VERSION 5.8 ;
BUSBITCHARS "[]" ;
DIVIDERCHAR "/" ;
UNITS
    DATABASE MICRONS 1000 ;
END UNITS

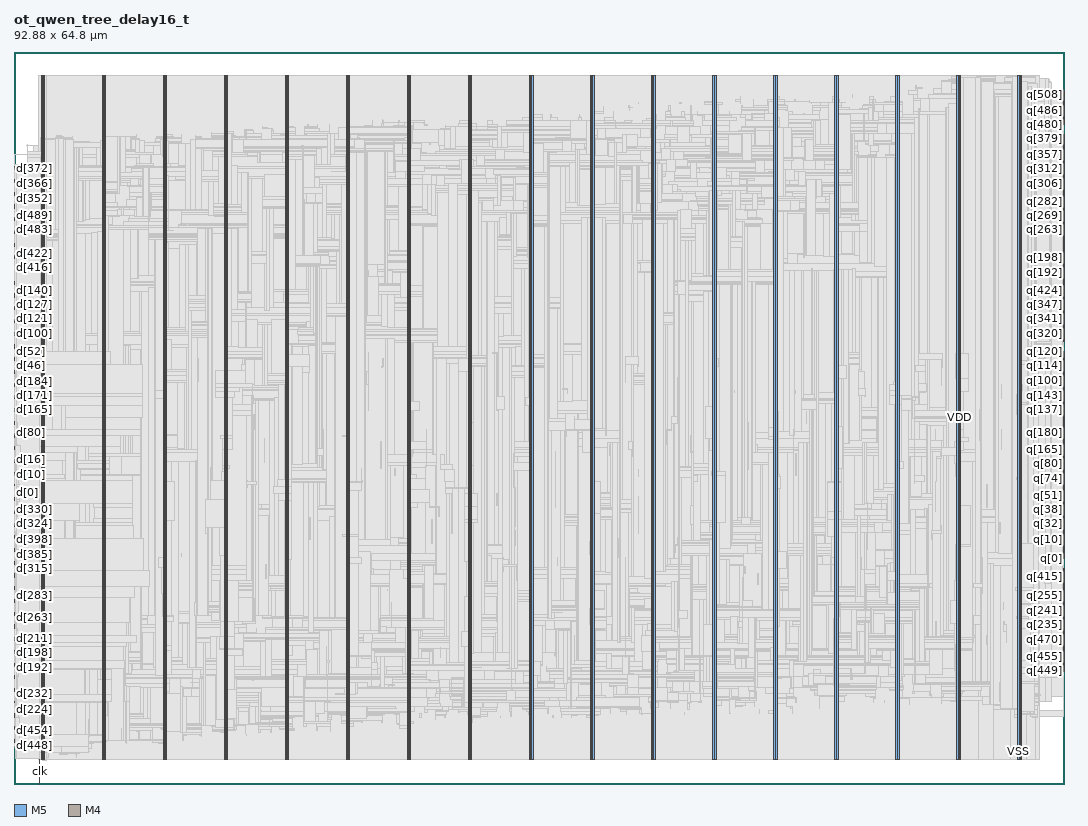
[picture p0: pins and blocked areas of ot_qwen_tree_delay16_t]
MACRO ot_qwen_tree_delay16_t
  FOREIGN ot_qwen_tree_delay16_t 0 0 ;
  CLASS BLOCK ;
  SIZE 92.88 BY 64.8 ;
  PIN clk
    DIRECTION INPUT ;
    USE SIGNAL ;
    PORT
      LAYER M5 ;
        RECT  2.256 0 2.28 0.084 ;
    END
    PORT
      LAYER M5 ;
        RECT  2.256 0.016 2.28 2.137 ;
    END
  END clk
  PIN d[0]
    DIRECTION INPUT ;
    USE SIGNAL ;
    PORT
      LAYER M4 ;
        RECT  0 26.448 0.084 26.472 ;
    END
  END d[0]
  PIN d[100]
    DIRECTION INPUT ;
    USE SIGNAL ;
    PORT
      LAYER M4 ;
        RECT  0 39.12 0.084 39.144 ;
    END
  END d[100]
  PIN d[101]
    DIRECTION INPUT ;
    USE SIGNAL ;
    PORT
      LAYER M4 ;
        RECT  0 39.216 0.084 39.24 ;
    END
  END d[101]
  PIN d[102]
    DIRECTION INPUT ;
    USE SIGNAL ;
    PORT
      LAYER M4 ;
        RECT  0 39.312 0.084 39.336 ;
    END
  END d[102]
  PIN d[103]
    DIRECTION INPUT ;
    USE SIGNAL ;
    PORT
      LAYER M4 ;
        RECT  0 39.408 0.084 39.432 ;
    END
  END d[103]
  PIN d[104]
    DIRECTION INPUT ;
    USE SIGNAL ;
    PORT
      LAYER M4 ;
        RECT  0 39.504 0.084 39.528 ;
    END
  END d[104]
  PIN d[105]
    DIRECTION INPUT ;
    USE SIGNAL ;
    PORT
      LAYER M4 ;
        RECT  0 39.6 0.084 39.624 ;
    END
  END d[105]
  PIN d[106]
    DIRECTION INPUT ;
    USE SIGNAL ;
    PORT
      LAYER M4 ;
        RECT  0 39.696 0.084 39.72 ;
    END
  END d[106]
  PIN d[107]
    DIRECTION INPUT ;
    USE SIGNAL ;
    PORT
      LAYER M4 ;
        RECT  0 39.792 0.084 39.816 ;
    END
  END d[107]
  PIN d[108]
    DIRECTION INPUT ;
    USE SIGNAL ;
    PORT
      LAYER M4 ;
        RECT  0 39.888 0.084 39.912 ;
    END
  END d[108]
  PIN d[109]
    DIRECTION INPUT ;
    USE SIGNAL ;
    PORT
      LAYER M4 ;
        RECT  0 39.984 0.084 40.008 ;
    END
  END d[109]
  PIN d[10]
    DIRECTION INPUT ;
    USE SIGNAL ;
    PORT
      LAYER M4 ;
        RECT  0 27.408 0.084 27.432 ;
    END
  END d[10]
  PIN d[110]
    DIRECTION INPUT ;
    USE SIGNAL ;
    PORT
      LAYER M4 ;
        RECT  0 40.08 0.084 40.104 ;
    END
  END d[110]
  PIN d[111]
    DIRECTION INPUT ;
    USE SIGNAL ;
    PORT
      LAYER M4 ;
        RECT  0 40.176 0.084 40.2 ;
    END
  END d[111]
  PIN d[112]
    DIRECTION INPUT ;
    USE SIGNAL ;
    PORT
      LAYER M4 ;
        RECT  0 40.272 0.084 40.296 ;
    END
  END d[112]
  PIN d[113]
    DIRECTION INPUT ;
    USE SIGNAL ;
    PORT
      LAYER M4 ;
        RECT  0 40.368 0.084 40.392 ;
    END
  END d[113]
  PIN d[114]
    DIRECTION INPUT ;
    USE SIGNAL ;
    PORT
      LAYER M4 ;
        RECT  0 40.464 0.084 40.488 ;
    END
  END d[114]
  PIN d[115]
    DIRECTION INPUT ;
    USE SIGNAL ;
    PORT
      LAYER M4 ;
        RECT  0 40.56 0.084 40.584 ;
    END
  END d[115]
  PIN d[116]
    DIRECTION INPUT ;
    USE SIGNAL ;
    PORT
      LAYER M4 ;
        RECT  0 40.656 0.084 40.68 ;
    END
  END d[116]
  PIN d[117]
    DIRECTION INPUT ;
    USE SIGNAL ;
    PORT
      LAYER M4 ;
        RECT  0 40.752 0.084 40.776 ;
    END
  END d[117]
  PIN d[118]
    DIRECTION INPUT ;
    USE SIGNAL ;
    PORT
      LAYER M4 ;
        RECT  0 40.848 0.084 40.872 ;
    END
  END d[118]
  PIN d[119]
    DIRECTION INPUT ;
    USE SIGNAL ;
    PORT
      LAYER M4 ;
        RECT  0 40.944 0.084 40.968 ;
    END
  END d[119]
  PIN d[11]
    DIRECTION INPUT ;
    USE SIGNAL ;
    PORT
      LAYER M4 ;
        RECT  0 27.504 0.084 27.528 ;
    END
  END d[11]
  PIN d[120]
    DIRECTION INPUT ;
    USE SIGNAL ;
    PORT
      LAYER M4 ;
        RECT  0 41.04 0.084 41.064 ;
    END
  END d[120]
  PIN d[121]
    DIRECTION INPUT ;
    USE SIGNAL ;
    PORT
      LAYER M4 ;
        RECT  0 41.136 0.084 41.16 ;
    END
  END d[121]
  PIN d[122]
    DIRECTION INPUT ;
    USE SIGNAL ;
    PORT
      LAYER M4 ;
        RECT  0 41.232 0.084 41.256 ;
    END
  END d[122]
  PIN d[123]
    DIRECTION INPUT ;
    USE SIGNAL ;
    PORT
      LAYER M4 ;
        RECT  0 41.328 0.084 41.352 ;
    END
  END d[123]
  PIN d[124]
    DIRECTION INPUT ;
    USE SIGNAL ;
    PORT
      LAYER M4 ;
        RECT  0 41.424 0.084 41.448 ;
    END
  END d[124]
  PIN d[125]
    DIRECTION INPUT ;
    USE SIGNAL ;
    PORT
      LAYER M4 ;
        RECT  0 41.52 0.084 41.544 ;
    END
  END d[125]
  PIN d[126]
    DIRECTION INPUT ;
    USE SIGNAL ;
    PORT
      LAYER M4 ;
        RECT  0 41.616 0.084 41.64 ;
    END
  END d[126]
  PIN d[127]
    DIRECTION INPUT ;
    USE SIGNAL ;
    PORT
      LAYER M4 ;
        RECT  0 41.712 0.084 41.736 ;
    END
  END d[127]
  PIN d[128]
    DIRECTION INPUT ;
    USE SIGNAL ;
    PORT
      LAYER M4 ;
        RECT  0 41.808 0.084 41.832 ;
    END
  END d[128]
  PIN d[129]
    DIRECTION INPUT ;
    USE SIGNAL ;
    PORT
      LAYER M4 ;
        RECT  0 41.904 0.084 41.928 ;
    END
  END d[129]
  PIN d[12]
    DIRECTION INPUT ;
    USE SIGNAL ;
    PORT
      LAYER M4 ;
        RECT  0 27.6 0.084 27.624 ;
    END
  END d[12]
  PIN d[130]
    DIRECTION INPUT ;
    USE SIGNAL ;
    PORT
      LAYER M4 ;
        RECT  0 42 0.084 42.024 ;
    END
  END d[130]
  PIN d[131]
    DIRECTION INPUT ;
    USE SIGNAL ;
    PORT
      LAYER M4 ;
        RECT  0 42.096 0.084 42.12 ;
    END
  END d[131]
  PIN d[132]
    DIRECTION INPUT ;
    USE SIGNAL ;
    PORT
      LAYER M4 ;
        RECT  0 42.192 0.084 42.216 ;
    END
  END d[132]
  PIN d[133]
    DIRECTION INPUT ;
    USE SIGNAL ;
    PORT
      LAYER M4 ;
        RECT  0 42.288 0.084 42.312 ;
    END
  END d[133]
  PIN d[134]
    DIRECTION INPUT ;
    USE SIGNAL ;
    PORT
      LAYER M4 ;
        RECT  0 42.384 0.084 42.408 ;
    END
  END d[134]
  PIN d[135]
    DIRECTION INPUT ;
    USE SIGNAL ;
    PORT
      LAYER M4 ;
        RECT  0 42.48 0.084 42.504 ;
    END
  END d[135]
  PIN d[136]
    DIRECTION INPUT ;
    USE SIGNAL ;
    PORT
      LAYER M4 ;
        RECT  0 42.576 0.084 42.6 ;
    END
  END d[136]
  PIN d[137]
    DIRECTION INPUT ;
    USE SIGNAL ;
    PORT
      LAYER M4 ;
        RECT  0 42.672 0.084 42.696 ;
    END
  END d[137]
  PIN d[138]
    DIRECTION INPUT ;
    USE SIGNAL ;
    PORT
      LAYER M4 ;
        RECT  0 42.768 0.084 42.792 ;
    END
  END d[138]
  PIN d[139]
    DIRECTION INPUT ;
    USE SIGNAL ;
    PORT
      LAYER M4 ;
        RECT  0 42.864 0.084 42.888 ;
    END
  END d[139]
  PIN d[13]
    DIRECTION INPUT ;
    USE SIGNAL ;
    PORT
      LAYER M4 ;
        RECT  0 27.696 0.084 27.72 ;
    END
  END d[13]
  PIN d[140]
    DIRECTION INPUT ;
    USE SIGNAL ;
    PORT
      LAYER M4 ;
        RECT  0 42.96 0.084 42.984 ;
    END
  END d[140]
  PIN d[141]
    DIRECTION INPUT ;
    USE SIGNAL ;
    PORT
      LAYER M4 ;
        RECT  0 43.056 0.084 43.08 ;
    END
  END d[141]
  PIN d[142]
    DIRECTION INPUT ;
    USE SIGNAL ;
    PORT
      LAYER M4 ;
        RECT  0 43.152 0.084 43.176 ;
    END
  END d[142]
  PIN d[143]
    DIRECTION INPUT ;
    USE SIGNAL ;
    PORT
      LAYER M4 ;
        RECT  0 43.248 0.084 43.272 ;
    END
  END d[143]
  PIN d[144]
    DIRECTION INPUT ;
    USE SIGNAL ;
    PORT
      LAYER M4 ;
        RECT  0 43.344 0.084 43.368 ;
    END
  END d[144]
  PIN d[145]
    DIRECTION INPUT ;
    USE SIGNAL ;
    PORT
      LAYER M4 ;
        RECT  0 43.44 0.084 43.464 ;
    END
  END d[145]
  PIN d[146]
    DIRECTION INPUT ;
    USE SIGNAL ;
    PORT
      LAYER M4 ;
        RECT  0 43.536 0.084 43.56 ;
    END
  END d[146]
  PIN d[147]
    DIRECTION INPUT ;
    USE SIGNAL ;
    PORT
      LAYER M4 ;
        RECT  0 43.632 0.084 43.656 ;
    END
  END d[147]
  PIN d[148]
    DIRECTION INPUT ;
    USE SIGNAL ;
    PORT
      LAYER M4 ;
        RECT  0 43.728 0.084 43.752 ;
    END
  END d[148]
  PIN d[149]
    DIRECTION INPUT ;
    USE SIGNAL ;
    PORT
      LAYER M4 ;
        RECT  0 43.824 0.084 43.848 ;
    END
  END d[149]
  PIN d[14]
    DIRECTION INPUT ;
    USE SIGNAL ;
    PORT
      LAYER M4 ;
        RECT  0 27.792 0.084 27.816 ;
    END
  END d[14]
  PIN d[150]
    DIRECTION INPUT ;
    USE SIGNAL ;
    PORT
      LAYER M4 ;
        RECT  0 43.92 0.084 43.944 ;
    END
  END d[150]
  PIN d[151]
    DIRECTION INPUT ;
    USE SIGNAL ;
    PORT
      LAYER M4 ;
        RECT  0 44.016 0.084 44.04 ;
    END
  END d[151]
  PIN d[152]
    DIRECTION INPUT ;
    USE SIGNAL ;
    PORT
      LAYER M4 ;
        RECT  0 44.112 0.084 44.136 ;
    END
  END d[152]
  PIN d[153]
    DIRECTION INPUT ;
    USE SIGNAL ;
    PORT
      LAYER M4 ;
        RECT  0 44.208 0.084 44.232 ;
    END
  END d[153]
  PIN d[154]
    DIRECTION INPUT ;
    USE SIGNAL ;
    PORT
      LAYER M4 ;
        RECT  0 44.304 0.084 44.328 ;
    END
  END d[154]
  PIN d[155]
    DIRECTION INPUT ;
    USE SIGNAL ;
    PORT
      LAYER M4 ;
        RECT  0 44.4 0.084 44.424 ;
    END
  END d[155]
  PIN d[156]
    DIRECTION INPUT ;
    USE SIGNAL ;
    PORT
      LAYER M4 ;
        RECT  0 44.496 0.084 44.52 ;
    END
  END d[156]
  PIN d[157]
    DIRECTION INPUT ;
    USE SIGNAL ;
    PORT
      LAYER M4 ;
        RECT  0 44.592 0.084 44.616 ;
    END
  END d[157]
  PIN d[158]
    DIRECTION INPUT ;
    USE SIGNAL ;
    PORT
      LAYER M4 ;
        RECT  0 44.688 0.084 44.712 ;
    END
  END d[158]
  PIN d[159]
    DIRECTION INPUT ;
    USE SIGNAL ;
    PORT
      LAYER M4 ;
        RECT  0 44.784 0.084 44.808 ;
    END
  END d[159]
  PIN d[15]
    DIRECTION INPUT ;
    USE SIGNAL ;
    PORT
      LAYER M4 ;
        RECT  0 27.888 0.084 27.912 ;
    END
  END d[15]
  PIN d[160]
    DIRECTION INPUT ;
    USE SIGNAL ;
    PORT
      LAYER M4 ;
        RECT  0 32.592 0.084 32.616 ;
    END
  END d[160]
  PIN d[161]
    DIRECTION INPUT ;
    USE SIGNAL ;
    PORT
      LAYER M4 ;
        RECT  0 32.688 0.084 32.712 ;
    END
  END d[161]
  PIN d[162]
    DIRECTION INPUT ;
    USE SIGNAL ;
    PORT
      LAYER M4 ;
        RECT  0 32.784 0.084 32.808 ;
    END
  END d[162]
  PIN d[163]
    DIRECTION INPUT ;
    USE SIGNAL ;
    PORT
      LAYER M4 ;
        RECT  0 32.88 0.084 32.904 ;
    END
  END d[163]
  PIN d[164]
    DIRECTION INPUT ;
    USE SIGNAL ;
    PORT
      LAYER M4 ;
        RECT  0 32.976 0.084 33 ;
    END
  END d[164]
  PIN d[165]
    DIRECTION INPUT ;
    USE SIGNAL ;
    PORT
      LAYER M4 ;
        RECT  0 33.072 0.084 33.096 ;
    END
  END d[165]
  PIN d[166]
    DIRECTION INPUT ;
    USE SIGNAL ;
    PORT
      LAYER M4 ;
        RECT  0 33.168 0.084 33.192 ;
    END
  END d[166]
  PIN d[167]
    DIRECTION INPUT ;
    USE SIGNAL ;
    PORT
      LAYER M4 ;
        RECT  0 33.264 0.084 33.288 ;
    END
  END d[167]
  PIN d[168]
    DIRECTION INPUT ;
    USE SIGNAL ;
    PORT
      LAYER M4 ;
        RECT  0 33.36 0.084 33.384 ;
    END
  END d[168]
  PIN d[169]
    DIRECTION INPUT ;
    USE SIGNAL ;
    PORT
      LAYER M4 ;
        RECT  0 33.456 0.084 33.48 ;
    END
  END d[169]
  PIN d[16]
    DIRECTION INPUT ;
    USE SIGNAL ;
    PORT
      LAYER M4 ;
        RECT  0 27.984 0.084 28.008 ;
    END
  END d[16]
  PIN d[170]
    DIRECTION INPUT ;
    USE SIGNAL ;
    PORT
      LAYER M4 ;
        RECT  0 33.552 0.084 33.576 ;
    END
  END d[170]
  PIN d[171]
    DIRECTION INPUT ;
    USE SIGNAL ;
    PORT
      LAYER M4 ;
        RECT  0 33.648 0.084 33.672 ;
    END
  END d[171]
  PIN d[172]
    DIRECTION INPUT ;
    USE SIGNAL ;
    PORT
      LAYER M4 ;
        RECT  0 33.744 0.084 33.768 ;
    END
  END d[172]
  PIN d[173]
    DIRECTION INPUT ;
    USE SIGNAL ;
    PORT
      LAYER M4 ;
        RECT  0 33.84 0.084 33.864 ;
    END
  END d[173]
  PIN d[174]
    DIRECTION INPUT ;
    USE SIGNAL ;
    PORT
      LAYER M4 ;
        RECT  0 33.936 0.084 33.96 ;
    END
  END d[174]
  PIN d[175]
    DIRECTION INPUT ;
    USE SIGNAL ;
    PORT
      LAYER M4 ;
        RECT  0 34.032 0.084 34.056 ;
    END
  END d[175]
  PIN d[176]
    DIRECTION INPUT ;
    USE SIGNAL ;
    PORT
      LAYER M4 ;
        RECT  0 34.128 0.084 34.152 ;
    END
  END d[176]
  PIN d[177]
    DIRECTION INPUT ;
    USE SIGNAL ;
    PORT
      LAYER M4 ;
        RECT  0 34.224 0.084 34.248 ;
    END
  END d[177]
  PIN d[178]
    DIRECTION INPUT ;
    USE SIGNAL ;
    PORT
      LAYER M4 ;
        RECT  0 34.32 0.084 34.344 ;
    END
  END d[178]
  PIN d[179]
    DIRECTION INPUT ;
    USE SIGNAL ;
    PORT
      LAYER M4 ;
        RECT  0 34.416 0.084 34.44 ;
    END
  END d[179]
  PIN d[17]
    DIRECTION INPUT ;
    USE SIGNAL ;
    PORT
      LAYER M4 ;
        RECT  0 28.08 0.084 28.104 ;
    END
  END d[17]
  PIN d[180]
    DIRECTION INPUT ;
    USE SIGNAL ;
    PORT
      LAYER M4 ;
        RECT  0 34.512 0.084 34.536 ;
    END
  END d[180]
  PIN d[181]
    DIRECTION INPUT ;
    USE SIGNAL ;
    PORT
      LAYER M4 ;
        RECT  0 34.608 0.084 34.632 ;
    END
  END d[181]
  PIN d[182]
    DIRECTION INPUT ;
    USE SIGNAL ;
    PORT
      LAYER M4 ;
        RECT  0 34.704 0.084 34.728 ;
    END
  END d[182]
  PIN d[183]
    DIRECTION INPUT ;
    USE SIGNAL ;
    PORT
      LAYER M4 ;
        RECT  0 34.8 0.084 34.824 ;
    END
  END d[183]
  PIN d[184]
    DIRECTION INPUT ;
    USE SIGNAL ;
    PORT
      LAYER M4 ;
        RECT  0 34.896 0.084 34.92 ;
    END
  END d[184]
  PIN d[185]
    DIRECTION INPUT ;
    USE SIGNAL ;
    PORT
      LAYER M4 ;
        RECT  0 34.992 0.084 35.016 ;
    END
  END d[185]
  PIN d[186]
    DIRECTION INPUT ;
    USE SIGNAL ;
    PORT
      LAYER M4 ;
        RECT  0 35.088 0.084 35.112 ;
    END
  END d[186]
  PIN d[187]
    DIRECTION INPUT ;
    USE SIGNAL ;
    PORT
      LAYER M4 ;
        RECT  0 35.184 0.084 35.208 ;
    END
  END d[187]
  PIN d[188]
    DIRECTION INPUT ;
    USE SIGNAL ;
    PORT
      LAYER M4 ;
        RECT  0 35.28 0.084 35.304 ;
    END
  END d[188]
  PIN d[189]
    DIRECTION INPUT ;
    USE SIGNAL ;
    PORT
      LAYER M4 ;
        RECT  0 35.376 0.084 35.4 ;
    END
  END d[189]
  PIN d[18]
    DIRECTION INPUT ;
    USE SIGNAL ;
    PORT
      LAYER M4 ;
        RECT  0 28.176 0.084 28.2 ;
    END
  END d[18]
  PIN d[190]
    DIRECTION INPUT ;
    USE SIGNAL ;
    PORT
      LAYER M4 ;
        RECT  0 35.472 0.084 35.496 ;
    END
  END d[190]
  PIN d[191]
    DIRECTION INPUT ;
    USE SIGNAL ;
    PORT
      LAYER M4 ;
        RECT  0 35.568 0.084 35.592 ;
    END
  END d[191]
  PIN d[192]
    DIRECTION INPUT ;
    USE SIGNAL ;
    PORT
      LAYER M4 ;
        RECT  0 10.32 0.084 10.344 ;
    END
  END d[192]
  PIN d[193]
    DIRECTION INPUT ;
    USE SIGNAL ;
    PORT
      LAYER M4 ;
        RECT  0 10.416 0.084 10.44 ;
    END
  END d[193]
  PIN d[194]
    DIRECTION INPUT ;
    USE SIGNAL ;
    PORT
      LAYER M4 ;
        RECT  0 10.512 0.084 10.536 ;
    END
  END d[194]
  PIN d[195]
    DIRECTION INPUT ;
    USE SIGNAL ;
    PORT
      LAYER M4 ;
        RECT  0 10.608 0.084 10.632 ;
    END
  END d[195]
  PIN d[196]
    DIRECTION INPUT ;
    USE SIGNAL ;
    PORT
      LAYER M4 ;
        RECT  0 10.704 0.084 10.728 ;
    END
  END d[196]
  PIN d[197]
    DIRECTION INPUT ;
    USE SIGNAL ;
    PORT
      LAYER M4 ;
        RECT  0 10.8 0.084 10.824 ;
    END
  END d[197]
  PIN d[198]
    DIRECTION INPUT ;
    USE SIGNAL ;
    PORT
      LAYER M4 ;
        RECT  0 10.896 0.084 10.92 ;
    END
  END d[198]
  PIN d[199]
    DIRECTION INPUT ;
    USE SIGNAL ;
    PORT
      LAYER M4 ;
        RECT  0 10.992 0.084 11.016 ;
    END
  END d[199]
  PIN d[19]
    DIRECTION INPUT ;
    USE SIGNAL ;
    PORT
      LAYER M4 ;
        RECT  0 28.272 0.084 28.296 ;
    END
  END d[19]
  PIN d[1]
    DIRECTION INPUT ;
    USE SIGNAL ;
    PORT
      LAYER M4 ;
        RECT  0 26.544 0.084 26.568 ;
    END
  END d[1]
  PIN d[200]
    DIRECTION INPUT ;
    USE SIGNAL ;
    PORT
      LAYER M4 ;
        RECT  0 11.088 0.084 11.112 ;
    END
  END d[200]
  PIN d[201]
    DIRECTION INPUT ;
    USE SIGNAL ;
    PORT
      LAYER M4 ;
        RECT  0 11.184 0.084 11.208 ;
    END
  END d[201]
  PIN d[202]
    DIRECTION INPUT ;
    USE SIGNAL ;
    PORT
      LAYER M4 ;
        RECT  0 11.28 0.084 11.304 ;
    END
  END d[202]
  PIN d[203]
    DIRECTION INPUT ;
    USE SIGNAL ;
    PORT
      LAYER M4 ;
        RECT  0 11.376 0.084 11.4 ;
    END
  END d[203]
  PIN d[204]
    DIRECTION INPUT ;
    USE SIGNAL ;
    PORT
      LAYER M4 ;
        RECT  0 11.472 0.084 11.496 ;
    END
  END d[204]
  PIN d[205]
    DIRECTION INPUT ;
    USE SIGNAL ;
    PORT
      LAYER M4 ;
        RECT  0 11.568 0.084 11.592 ;
    END
  END d[205]
  PIN d[206]
    DIRECTION INPUT ;
    USE SIGNAL ;
    PORT
      LAYER M4 ;
        RECT  0 11.664 0.084 11.688 ;
    END
  END d[206]
  PIN d[207]
    DIRECTION INPUT ;
    USE SIGNAL ;
    PORT
      LAYER M4 ;
        RECT  0 11.76 0.084 11.784 ;
    END
  END d[207]
  PIN d[208]
    DIRECTION INPUT ;
    USE SIGNAL ;
    PORT
      LAYER M4 ;
        RECT  0 11.856 0.084 11.88 ;
    END
  END d[208]
  PIN d[209]
    DIRECTION INPUT ;
    USE SIGNAL ;
    PORT
      LAYER M4 ;
        RECT  0 11.952 0.084 11.976 ;
    END
  END d[209]
  PIN d[20]
    DIRECTION INPUT ;
    USE SIGNAL ;
    PORT
      LAYER M4 ;
        RECT  0 28.368 0.084 28.392 ;
    END
  END d[20]
  PIN d[210]
    DIRECTION INPUT ;
    USE SIGNAL ;
    PORT
      LAYER M4 ;
        RECT  0 12.048 0.084 12.072 ;
    END
  END d[210]
  PIN d[211]
    DIRECTION INPUT ;
    USE SIGNAL ;
    PORT
      LAYER M4 ;
        RECT  0 12.144 0.084 12.168 ;
    END
  END d[211]
  PIN d[212]
    DIRECTION INPUT ;
    USE SIGNAL ;
    PORT
      LAYER M4 ;
        RECT  0 12.24 0.084 12.264 ;
    END
  END d[212]
  PIN d[213]
    DIRECTION INPUT ;
    USE SIGNAL ;
    PORT
      LAYER M4 ;
        RECT  0 12.336 0.084 12.36 ;
    END
  END d[213]
  PIN d[214]
    DIRECTION INPUT ;
    USE SIGNAL ;
    PORT
      LAYER M4 ;
        RECT  0 12.432 0.084 12.456 ;
    END
  END d[214]
  PIN d[215]
    DIRECTION INPUT ;
    USE SIGNAL ;
    PORT
      LAYER M4 ;
        RECT  0 12.528 0.084 12.552 ;
    END
  END d[215]
  PIN d[216]
    DIRECTION INPUT ;
    USE SIGNAL ;
    PORT
      LAYER M4 ;
        RECT  0 12.624 0.084 12.648 ;
    END
  END d[216]
  PIN d[217]
    DIRECTION INPUT ;
    USE SIGNAL ;
    PORT
      LAYER M4 ;
        RECT  0 12.72 0.084 12.744 ;
    END
  END d[217]
  PIN d[218]
    DIRECTION INPUT ;
    USE SIGNAL ;
    PORT
      LAYER M4 ;
        RECT  0 12.816 0.084 12.84 ;
    END
  END d[218]
  PIN d[219]
    DIRECTION INPUT ;
    USE SIGNAL ;
    PORT
      LAYER M4 ;
        RECT  0 12.912 0.084 12.936 ;
    END
  END d[219]
  PIN d[21]
    DIRECTION INPUT ;
    USE SIGNAL ;
    PORT
      LAYER M4 ;
        RECT  0 28.464 0.084 28.488 ;
    END
  END d[21]
  PIN d[220]
    DIRECTION INPUT ;
    USE SIGNAL ;
    PORT
      LAYER M4 ;
        RECT  0 13.008 0.084 13.032 ;
    END
  END d[220]
  PIN d[221]
    DIRECTION INPUT ;
    USE SIGNAL ;
    PORT
      LAYER M4 ;
        RECT  0 13.104 0.084 13.128 ;
    END
  END d[221]
  PIN d[222]
    DIRECTION INPUT ;
    USE SIGNAL ;
    PORT
      LAYER M4 ;
        RECT  0 13.2 0.084 13.224 ;
    END
  END d[222]
  PIN d[223]
    DIRECTION INPUT ;
    USE SIGNAL ;
    PORT
      LAYER M4 ;
        RECT  0 13.296 0.084 13.32 ;
    END
  END d[223]
  PIN d[224]
    DIRECTION INPUT ;
    USE SIGNAL ;
    PORT
      LAYER M4 ;
        RECT  0 7.248 0.084 7.272 ;
    END
  END d[224]
  PIN d[225]
    DIRECTION INPUT ;
    USE SIGNAL ;
    PORT
      LAYER M4 ;
        RECT  0 7.344 0.084 7.368 ;
    END
  END d[225]
  PIN d[226]
    DIRECTION INPUT ;
    USE SIGNAL ;
    PORT
      LAYER M4 ;
        RECT  0 7.44 0.084 7.464 ;
    END
  END d[226]
  PIN d[227]
    DIRECTION INPUT ;
    USE SIGNAL ;
    PORT
      LAYER M4 ;
        RECT  0 7.536 0.084 7.56 ;
    END
  END d[227]
  PIN d[228]
    DIRECTION INPUT ;
    USE SIGNAL ;
    PORT
      LAYER M4 ;
        RECT  0 7.632 0.084 7.656 ;
    END
  END d[228]
  PIN d[229]
    DIRECTION INPUT ;
    USE SIGNAL ;
    PORT
      LAYER M4 ;
        RECT  0 7.728 0.084 7.752 ;
    END
  END d[229]
  PIN d[22]
    DIRECTION INPUT ;
    USE SIGNAL ;
    PORT
      LAYER M4 ;
        RECT  0 28.56 0.084 28.584 ;
    END
  END d[22]
  PIN d[230]
    DIRECTION INPUT ;
    USE SIGNAL ;
    PORT
      LAYER M4 ;
        RECT  0 7.824 0.084 7.848 ;
    END
  END d[230]
  PIN d[231]
    DIRECTION INPUT ;
    USE SIGNAL ;
    PORT
      LAYER M4 ;
        RECT  0 7.92 0.084 7.944 ;
    END
  END d[231]
  PIN d[232]
    DIRECTION INPUT ;
    USE SIGNAL ;
    PORT
      LAYER M4 ;
        RECT  0 8.016 0.084 8.04 ;
    END
  END d[232]
  PIN d[233]
    DIRECTION INPUT ;
    USE SIGNAL ;
    PORT
      LAYER M4 ;
        RECT  0 8.112 0.084 8.136 ;
    END
  END d[233]
  PIN d[234]
    DIRECTION INPUT ;
    USE SIGNAL ;
    PORT
      LAYER M4 ;
        RECT  0 8.208 0.084 8.232 ;
    END
  END d[234]
  PIN d[235]
    DIRECTION INPUT ;
    USE SIGNAL ;
    PORT
      LAYER M4 ;
        RECT  0 8.304 0.084 8.328 ;
    END
  END d[235]
  PIN d[236]
    DIRECTION INPUT ;
    USE SIGNAL ;
    PORT
      LAYER M4 ;
        RECT  0 8.4 0.084 8.424 ;
    END
  END d[236]
  PIN d[237]
    DIRECTION INPUT ;
    USE SIGNAL ;
    PORT
      LAYER M4 ;
        RECT  0 8.496 0.084 8.52 ;
    END
  END d[237]
  PIN d[238]
    DIRECTION INPUT ;
    USE SIGNAL ;
    PORT
      LAYER M4 ;
        RECT  0 8.592 0.084 8.616 ;
    END
  END d[238]
  PIN d[239]
    DIRECTION INPUT ;
    USE SIGNAL ;
    PORT
      LAYER M4 ;
        RECT  0 8.688 0.084 8.712 ;
    END
  END d[239]
  PIN d[23]
    DIRECTION INPUT ;
    USE SIGNAL ;
    PORT
      LAYER M4 ;
        RECT  0 28.656 0.084 28.68 ;
    END
  END d[23]
  PIN d[240]
    DIRECTION INPUT ;
    USE SIGNAL ;
    PORT
      LAYER M4 ;
        RECT  0 8.784 0.084 8.808 ;
    END
  END d[240]
  PIN d[241]
    DIRECTION INPUT ;
    USE SIGNAL ;
    PORT
      LAYER M4 ;
        RECT  0 8.88 0.084 8.904 ;
    END
  END d[241]
  PIN d[242]
    DIRECTION INPUT ;
    USE SIGNAL ;
    PORT
      LAYER M4 ;
        RECT  0 8.976 0.084 9 ;
    END
  END d[242]
  PIN d[243]
    DIRECTION INPUT ;
    USE SIGNAL ;
    PORT
      LAYER M4 ;
        RECT  0 9.072 0.084 9.096 ;
    END
  END d[243]
  PIN d[244]
    DIRECTION INPUT ;
    USE SIGNAL ;
    PORT
      LAYER M4 ;
        RECT  0 9.168 0.084 9.192 ;
    END
  END d[244]
  PIN d[245]
    DIRECTION INPUT ;
    USE SIGNAL ;
    PORT
      LAYER M4 ;
        RECT  0 9.264 0.084 9.288 ;
    END
  END d[245]
  PIN d[246]
    DIRECTION INPUT ;
    USE SIGNAL ;
    PORT
      LAYER M4 ;
        RECT  0 9.36 0.084 9.384 ;
    END
  END d[246]
  PIN d[247]
    DIRECTION INPUT ;
    USE SIGNAL ;
    PORT
      LAYER M4 ;
        RECT  0 9.456 0.084 9.48 ;
    END
  END d[247]
  PIN d[248]
    DIRECTION INPUT ;
    USE SIGNAL ;
    PORT
      LAYER M4 ;
        RECT  0 9.552 0.084 9.576 ;
    END
  END d[248]
  PIN d[249]
    DIRECTION INPUT ;
    USE SIGNAL ;
    PORT
      LAYER M4 ;
        RECT  0 9.648 0.084 9.672 ;
    END
  END d[249]
  PIN d[24]
    DIRECTION INPUT ;
    USE SIGNAL ;
    PORT
      LAYER M4 ;
        RECT  0 28.752 0.084 28.776 ;
    END
  END d[24]
  PIN d[250]
    DIRECTION INPUT ;
    USE SIGNAL ;
    PORT
      LAYER M4 ;
        RECT  0 9.744 0.084 9.768 ;
    END
  END d[250]
  PIN d[251]
    DIRECTION INPUT ;
    USE SIGNAL ;
    PORT
      LAYER M4 ;
        RECT  0 9.84 0.084 9.864 ;
    END
  END d[251]
  PIN d[252]
    DIRECTION INPUT ;
    USE SIGNAL ;
    PORT
      LAYER M4 ;
        RECT  0 9.936 0.084 9.96 ;
    END
  END d[252]
  PIN d[253]
    DIRECTION INPUT ;
    USE SIGNAL ;
    PORT
      LAYER M4 ;
        RECT  0 10.032 0.084 10.056 ;
    END
  END d[253]
  PIN d[254]
    DIRECTION INPUT ;
    USE SIGNAL ;
    PORT
      LAYER M4 ;
        RECT  0 10.128 0.084 10.152 ;
    END
  END d[254]
  PIN d[255]
    DIRECTION INPUT ;
    USE SIGNAL ;
    PORT
      LAYER M4 ;
        RECT  0 10.224 0.084 10.248 ;
    END
  END d[255]
  PIN d[256]
    DIRECTION INPUT ;
    USE SIGNAL ;
    PORT
      LAYER M4 ;
        RECT  0 13.392 0.084 13.416 ;
    END
  END d[256]
  PIN d[257]
    DIRECTION INPUT ;
    USE SIGNAL ;
    PORT
      LAYER M4 ;
        RECT  0 13.488 0.084 13.512 ;
    END
  END d[257]
  PIN d[258]
    DIRECTION INPUT ;
    USE SIGNAL ;
    PORT
      LAYER M4 ;
        RECT  0 13.584 0.084 13.608 ;
    END
  END d[258]
  PIN d[259]
    DIRECTION INPUT ;
    USE SIGNAL ;
    PORT
      LAYER M4 ;
        RECT  0 13.68 0.084 13.704 ;
    END
  END d[259]
  PIN d[25]
    DIRECTION INPUT ;
    USE SIGNAL ;
    PORT
      LAYER M4 ;
        RECT  0 28.848 0.084 28.872 ;
    END
  END d[25]
  PIN d[260]
    DIRECTION INPUT ;
    USE SIGNAL ;
    PORT
      LAYER M4 ;
        RECT  0 13.776 0.084 13.8 ;
    END
  END d[260]
  PIN d[261]
    DIRECTION INPUT ;
    USE SIGNAL ;
    PORT
      LAYER M4 ;
        RECT  0 13.872 0.084 13.896 ;
    END
  END d[261]
  PIN d[262]
    DIRECTION INPUT ;
    USE SIGNAL ;
    PORT
      LAYER M4 ;
        RECT  0 13.968 0.084 13.992 ;
    END
  END d[262]
  PIN d[263]
    DIRECTION INPUT ;
    USE SIGNAL ;
    PORT
      LAYER M4 ;
        RECT  0 14.064 0.084 14.088 ;
    END
  END d[263]
  PIN d[264]
    DIRECTION INPUT ;
    USE SIGNAL ;
    PORT
      LAYER M4 ;
        RECT  0 14.16 0.084 14.184 ;
    END
  END d[264]
  PIN d[265]
    DIRECTION INPUT ;
    USE SIGNAL ;
    PORT
      LAYER M4 ;
        RECT  0 14.256 0.084 14.28 ;
    END
  END d[265]
  PIN d[266]
    DIRECTION INPUT ;
    USE SIGNAL ;
    PORT
      LAYER M4 ;
        RECT  0 14.352 0.084 14.376 ;
    END
  END d[266]
  PIN d[267]
    DIRECTION INPUT ;
    USE SIGNAL ;
    PORT
      LAYER M4 ;
        RECT  0 14.448 0.084 14.472 ;
    END
  END d[267]
  PIN d[268]
    DIRECTION INPUT ;
    USE SIGNAL ;
    PORT
      LAYER M4 ;
        RECT  0 14.544 0.084 14.568 ;
    END
  END d[268]
  PIN d[269]
    DIRECTION INPUT ;
    USE SIGNAL ;
    PORT
      LAYER M4 ;
        RECT  0 14.64 0.084 14.664 ;
    END
  END d[269]
  PIN d[26]
    DIRECTION INPUT ;
    USE SIGNAL ;
    PORT
      LAYER M4 ;
        RECT  0 28.944 0.084 28.968 ;
    END
  END d[26]
  PIN d[270]
    DIRECTION INPUT ;
    USE SIGNAL ;
    PORT
      LAYER M4 ;
        RECT  0 14.736 0.084 14.76 ;
    END
  END d[270]
  PIN d[271]
    DIRECTION INPUT ;
    USE SIGNAL ;
    PORT
      LAYER M4 ;
        RECT  0 14.832 0.084 14.856 ;
    END
  END d[271]
  PIN d[272]
    DIRECTION INPUT ;
    USE SIGNAL ;
    PORT
      LAYER M4 ;
        RECT  0 14.928 0.084 14.952 ;
    END
  END d[272]
  PIN d[273]
    DIRECTION INPUT ;
    USE SIGNAL ;
    PORT
      LAYER M4 ;
        RECT  0 15.024 0.084 15.048 ;
    END
  END d[273]
  PIN d[274]
    DIRECTION INPUT ;
    USE SIGNAL ;
    PORT
      LAYER M4 ;
        RECT  0 15.12 0.084 15.144 ;
    END
  END d[274]
  PIN d[275]
    DIRECTION INPUT ;
    USE SIGNAL ;
    PORT
      LAYER M4 ;
        RECT  0 15.216 0.084 15.24 ;
    END
  END d[275]
  PIN d[276]
    DIRECTION INPUT ;
    USE SIGNAL ;
    PORT
      LAYER M4 ;
        RECT  0 15.312 0.084 15.336 ;
    END
  END d[276]
  PIN d[277]
    DIRECTION INPUT ;
    USE SIGNAL ;
    PORT
      LAYER M4 ;
        RECT  0 15.408 0.084 15.432 ;
    END
  END d[277]
  PIN d[278]
    DIRECTION INPUT ;
    USE SIGNAL ;
    PORT
      LAYER M4 ;
        RECT  0 15.504 0.084 15.528 ;
    END
  END d[278]
  PIN d[279]
    DIRECTION INPUT ;
    USE SIGNAL ;
    PORT
      LAYER M4 ;
        RECT  0 15.6 0.084 15.624 ;
    END
  END d[279]
  PIN d[27]
    DIRECTION INPUT ;
    USE SIGNAL ;
    PORT
      LAYER M4 ;
        RECT  0 29.04 0.084 29.064 ;
    END
  END d[27]
  PIN d[280]
    DIRECTION INPUT ;
    USE SIGNAL ;
    PORT
      LAYER M4 ;
        RECT  0 15.696 0.084 15.72 ;
    END
  END d[280]
  PIN d[281]
    DIRECTION INPUT ;
    USE SIGNAL ;
    PORT
      LAYER M4 ;
        RECT  0 15.792 0.084 15.816 ;
    END
  END d[281]
  PIN d[282]
    DIRECTION INPUT ;
    USE SIGNAL ;
    PORT
      LAYER M4 ;
        RECT  0 15.888 0.084 15.912 ;
    END
  END d[282]
  PIN d[283]
    DIRECTION INPUT ;
    USE SIGNAL ;
    PORT
      LAYER M4 ;
        RECT  0 15.984 0.084 16.008 ;
    END
  END d[283]
  PIN d[284]
    DIRECTION INPUT ;
    USE SIGNAL ;
    PORT
      LAYER M4 ;
        RECT  0 16.08 0.084 16.104 ;
    END
  END d[284]
  PIN d[285]
    DIRECTION INPUT ;
    USE SIGNAL ;
    PORT
      LAYER M4 ;
        RECT  0 16.176 0.084 16.2 ;
    END
  END d[285]
  PIN d[286]
    DIRECTION INPUT ;
    USE SIGNAL ;
    PORT
      LAYER M4 ;
        RECT  0 16.272 0.084 16.296 ;
    END
  END d[286]
  PIN d[287]
    DIRECTION INPUT ;
    USE SIGNAL ;
    PORT
      LAYER M4 ;
        RECT  0 16.368 0.084 16.392 ;
    END
  END d[287]
  PIN d[288]
    DIRECTION INPUT ;
    USE SIGNAL ;
    PORT
      LAYER M4 ;
        RECT  0 16.464 0.084 16.488 ;
    END
  END d[288]
  PIN d[289]
    DIRECTION INPUT ;
    USE SIGNAL ;
    PORT
      LAYER M4 ;
        RECT  0 16.56 0.084 16.584 ;
    END
  END d[289]
  PIN d[28]
    DIRECTION INPUT ;
    USE SIGNAL ;
    PORT
      LAYER M4 ;
        RECT  0 29.136 0.084 29.16 ;
    END
  END d[28]
  PIN d[290]
    DIRECTION INPUT ;
    USE SIGNAL ;
    PORT
      LAYER M4 ;
        RECT  0 16.656 0.084 16.68 ;
    END
  END d[290]
  PIN d[291]
    DIRECTION INPUT ;
    USE SIGNAL ;
    PORT
      LAYER M4 ;
        RECT  0 16.752 0.084 16.776 ;
    END
  END d[291]
  PIN d[292]
    DIRECTION INPUT ;
    USE SIGNAL ;
    PORT
      LAYER M4 ;
        RECT  0 16.848 0.084 16.872 ;
    END
  END d[292]
  PIN d[293]
    DIRECTION INPUT ;
    USE SIGNAL ;
    PORT
      LAYER M4 ;
        RECT  0 16.944 0.084 16.968 ;
    END
  END d[293]
  PIN d[294]
    DIRECTION INPUT ;
    USE SIGNAL ;
    PORT
      LAYER M4 ;
        RECT  0 17.04 0.084 17.064 ;
    END
  END d[294]
  PIN d[295]
    DIRECTION INPUT ;
    USE SIGNAL ;
    PORT
      LAYER M4 ;
        RECT  0 17.136 0.084 17.16 ;
    END
  END d[295]
  PIN d[296]
    DIRECTION INPUT ;
    USE SIGNAL ;
    PORT
      LAYER M4 ;
        RECT  0 17.232 0.084 17.256 ;
    END
  END d[296]
  PIN d[297]
    DIRECTION INPUT ;
    USE SIGNAL ;
    PORT
      LAYER M4 ;
        RECT  0 17.328 0.084 17.352 ;
    END
  END d[297]
  PIN d[298]
    DIRECTION INPUT ;
    USE SIGNAL ;
    PORT
      LAYER M4 ;
        RECT  0 17.424 0.084 17.448 ;
    END
  END d[298]
  PIN d[299]
    DIRECTION INPUT ;
    USE SIGNAL ;
    PORT
      LAYER M4 ;
        RECT  0 17.52 0.084 17.544 ;
    END
  END d[299]
  PIN d[29]
    DIRECTION INPUT ;
    USE SIGNAL ;
    PORT
      LAYER M4 ;
        RECT  0 29.232 0.084 29.256 ;
    END
  END d[29]
  PIN d[2]
    DIRECTION INPUT ;
    USE SIGNAL ;
    PORT
      LAYER M4 ;
        RECT  0 26.64 0.084 26.664 ;
    END
  END d[2]
  PIN d[300]
    DIRECTION INPUT ;
    USE SIGNAL ;
    PORT
      LAYER M4 ;
        RECT  0 17.616 0.084 17.64 ;
    END
  END d[300]
  PIN d[301]
    DIRECTION INPUT ;
    USE SIGNAL ;
    PORT
      LAYER M4 ;
        RECT  0 17.712 0.084 17.736 ;
    END
  END d[301]
  PIN d[302]
    DIRECTION INPUT ;
    USE SIGNAL ;
    PORT
      LAYER M4 ;
        RECT  0 17.808 0.084 17.832 ;
    END
  END d[302]
  PIN d[303]
    DIRECTION INPUT ;
    USE SIGNAL ;
    PORT
      LAYER M4 ;
        RECT  0 17.904 0.084 17.928 ;
    END
  END d[303]
  PIN d[304]
    DIRECTION INPUT ;
    USE SIGNAL ;
    PORT
      LAYER M4 ;
        RECT  0 18 0.084 18.024 ;
    END
  END d[304]
  PIN d[305]
    DIRECTION INPUT ;
    USE SIGNAL ;
    PORT
      LAYER M4 ;
        RECT  0 18.096 0.084 18.12 ;
    END
  END d[305]
  PIN d[306]
    DIRECTION INPUT ;
    USE SIGNAL ;
    PORT
      LAYER M4 ;
        RECT  0 18.192 0.084 18.216 ;
    END
  END d[306]
  PIN d[307]
    DIRECTION INPUT ;
    USE SIGNAL ;
    PORT
      LAYER M4 ;
        RECT  0 18.288 0.084 18.312 ;
    END
  END d[307]
  PIN d[308]
    DIRECTION INPUT ;
    USE SIGNAL ;
    PORT
      LAYER M4 ;
        RECT  0 18.384 0.084 18.408 ;
    END
  END d[308]
  PIN d[309]
    DIRECTION INPUT ;
    USE SIGNAL ;
    PORT
      LAYER M4 ;
        RECT  0 18.48 0.084 18.504 ;
    END
  END d[309]
  PIN d[30]
    DIRECTION INPUT ;
    USE SIGNAL ;
    PORT
      LAYER M4 ;
        RECT  0 29.328 0.084 29.352 ;
    END
  END d[30]
  PIN d[310]
    DIRECTION INPUT ;
    USE SIGNAL ;
    PORT
      LAYER M4 ;
        RECT  0 18.576 0.084 18.6 ;
    END
  END d[310]
  PIN d[311]
    DIRECTION INPUT ;
    USE SIGNAL ;
    PORT
      LAYER M4 ;
        RECT  0 18.672 0.084 18.696 ;
    END
  END d[311]
  PIN d[312]
    DIRECTION INPUT ;
    USE SIGNAL ;
    PORT
      LAYER M4 ;
        RECT  0 18.768 0.084 18.792 ;
    END
  END d[312]
  PIN d[313]
    DIRECTION INPUT ;
    USE SIGNAL ;
    PORT
      LAYER M4 ;
        RECT  0 18.864 0.084 18.888 ;
    END
  END d[313]
  PIN d[314]
    DIRECTION INPUT ;
    USE SIGNAL ;
    PORT
      LAYER M4 ;
        RECT  0 18.96 0.084 18.984 ;
    END
  END d[314]
  PIN d[315]
    DIRECTION INPUT ;
    USE SIGNAL ;
    PORT
      LAYER M4 ;
        RECT  0 19.056 0.084 19.08 ;
    END
  END d[315]
  PIN d[316]
    DIRECTION INPUT ;
    USE SIGNAL ;
    PORT
      LAYER M4 ;
        RECT  0 19.152 0.084 19.176 ;
    END
  END d[316]
  PIN d[317]
    DIRECTION INPUT ;
    USE SIGNAL ;
    PORT
      LAYER M4 ;
        RECT  0 19.248 0.084 19.272 ;
    END
  END d[317]
  PIN d[318]
    DIRECTION INPUT ;
    USE SIGNAL ;
    PORT
      LAYER M4 ;
        RECT  0 19.344 0.084 19.368 ;
    END
  END d[318]
  PIN d[319]
    DIRECTION INPUT ;
    USE SIGNAL ;
    PORT
      LAYER M4 ;
        RECT  0 19.44 0.084 19.464 ;
    END
  END d[319]
  PIN d[31]
    DIRECTION INPUT ;
    USE SIGNAL ;
    PORT
      LAYER M4 ;
        RECT  0 29.424 0.084 29.448 ;
    END
  END d[31]
  PIN d[320]
    DIRECTION INPUT ;
    USE SIGNAL ;
    PORT
      LAYER M4 ;
        RECT  0 22.608 0.084 22.632 ;
    END
  END d[320]
  PIN d[321]
    DIRECTION INPUT ;
    USE SIGNAL ;
    PORT
      LAYER M4 ;
        RECT  0 22.704 0.084 22.728 ;
    END
  END d[321]
  PIN d[322]
    DIRECTION INPUT ;
    USE SIGNAL ;
    PORT
      LAYER M4 ;
        RECT  0 22.8 0.084 22.824 ;
    END
  END d[322]
  PIN d[323]
    DIRECTION INPUT ;
    USE SIGNAL ;
    PORT
      LAYER M4 ;
        RECT  0 22.896 0.084 22.92 ;
    END
  END d[323]
  PIN d[324]
    DIRECTION INPUT ;
    USE SIGNAL ;
    PORT
      LAYER M4 ;
        RECT  0 22.992 0.084 23.016 ;
    END
  END d[324]
  PIN d[325]
    DIRECTION INPUT ;
    USE SIGNAL ;
    PORT
      LAYER M4 ;
        RECT  0 23.088 0.084 23.112 ;
    END
  END d[325]
  PIN d[326]
    DIRECTION INPUT ;
    USE SIGNAL ;
    PORT
      LAYER M4 ;
        RECT  0 23.184 0.084 23.208 ;
    END
  END d[326]
  PIN d[327]
    DIRECTION INPUT ;
    USE SIGNAL ;
    PORT
      LAYER M4 ;
        RECT  0 23.28 0.084 23.304 ;
    END
  END d[327]
  PIN d[328]
    DIRECTION INPUT ;
    USE SIGNAL ;
    PORT
      LAYER M4 ;
        RECT  0 23.376 0.084 23.4 ;
    END
  END d[328]
  PIN d[329]
    DIRECTION INPUT ;
    USE SIGNAL ;
    PORT
      LAYER M4 ;
        RECT  0 23.472 0.084 23.496 ;
    END
  END d[329]
  PIN d[32]
    DIRECTION INPUT ;
    USE SIGNAL ;
    PORT
      LAYER M4 ;
        RECT  0 35.664 0.084 35.688 ;
    END
  END d[32]
  PIN d[330]
    DIRECTION INPUT ;
    USE SIGNAL ;
    PORT
      LAYER M4 ;
        RECT  0 23.568 0.084 23.592 ;
    END
  END d[330]
  PIN d[331]
    DIRECTION INPUT ;
    USE SIGNAL ;
    PORT
      LAYER M4 ;
        RECT  0 23.664 0.084 23.688 ;
    END
  END d[331]
  PIN d[332]
    DIRECTION INPUT ;
    USE SIGNAL ;
    PORT
      LAYER M4 ;
        RECT  0 23.76 0.084 23.784 ;
    END
  END d[332]
  PIN d[333]
    DIRECTION INPUT ;
    USE SIGNAL ;
    PORT
      LAYER M4 ;
        RECT  0 23.856 0.084 23.88 ;
    END
  END d[333]
  PIN d[334]
    DIRECTION INPUT ;
    USE SIGNAL ;
    PORT
      LAYER M4 ;
        RECT  0 23.952 0.084 23.976 ;
    END
  END d[334]
  PIN d[335]
    DIRECTION INPUT ;
    USE SIGNAL ;
    PORT
      LAYER M4 ;
        RECT  0 24.048 0.084 24.072 ;
    END
  END d[335]
  PIN d[336]
    DIRECTION INPUT ;
    USE SIGNAL ;
    PORT
      LAYER M4 ;
        RECT  0 24.144 0.084 24.168 ;
    END
  END d[336]
  PIN d[337]
    DIRECTION INPUT ;
    USE SIGNAL ;
    PORT
      LAYER M4 ;
        RECT  0 24.24 0.084 24.264 ;
    END
  END d[337]
  PIN d[338]
    DIRECTION INPUT ;
    USE SIGNAL ;
    PORT
      LAYER M4 ;
        RECT  0 24.336 0.084 24.36 ;
    END
  END d[338]
  PIN d[339]
    DIRECTION INPUT ;
    USE SIGNAL ;
    PORT
      LAYER M4 ;
        RECT  0 24.432 0.084 24.456 ;
    END
  END d[339]
  PIN d[33]
    DIRECTION INPUT ;
    USE SIGNAL ;
    PORT
      LAYER M4 ;
        RECT  0 35.76 0.084 35.784 ;
    END
  END d[33]
  PIN d[340]
    DIRECTION INPUT ;
    USE SIGNAL ;
    PORT
      LAYER M4 ;
        RECT  0 24.528 0.084 24.552 ;
    END
  END d[340]
  PIN d[341]
    DIRECTION INPUT ;
    USE SIGNAL ;
    PORT
      LAYER M4 ;
        RECT  0 24.624 0.084 24.648 ;
    END
  END d[341]
  PIN d[342]
    DIRECTION INPUT ;
    USE SIGNAL ;
    PORT
      LAYER M4 ;
        RECT  0 24.72 0.084 24.744 ;
    END
  END d[342]
  PIN d[343]
    DIRECTION INPUT ;
    USE SIGNAL ;
    PORT
      LAYER M4 ;
        RECT  0 24.816 0.084 24.84 ;
    END
  END d[343]
  PIN d[344]
    DIRECTION INPUT ;
    USE SIGNAL ;
    PORT
      LAYER M4 ;
        RECT  0 24.912 0.084 24.936 ;
    END
  END d[344]
  PIN d[345]
    DIRECTION INPUT ;
    USE SIGNAL ;
    PORT
      LAYER M4 ;
        RECT  0 25.008 0.084 25.032 ;
    END
  END d[345]
  PIN d[346]
    DIRECTION INPUT ;
    USE SIGNAL ;
    PORT
      LAYER M4 ;
        RECT  0 25.104 0.084 25.128 ;
    END
  END d[346]
  PIN d[347]
    DIRECTION INPUT ;
    USE SIGNAL ;
    PORT
      LAYER M4 ;
        RECT  0 25.2 0.084 25.224 ;
    END
  END d[347]
  PIN d[348]
    DIRECTION INPUT ;
    USE SIGNAL ;
    PORT
      LAYER M4 ;
        RECT  0 25.296 0.084 25.32 ;
    END
  END d[348]
  PIN d[349]
    DIRECTION INPUT ;
    USE SIGNAL ;
    PORT
      LAYER M4 ;
        RECT  0 25.392 0.084 25.416 ;
    END
  END d[349]
  PIN d[34]
    DIRECTION INPUT ;
    USE SIGNAL ;
    PORT
      LAYER M4 ;
        RECT  0 35.856 0.084 35.88 ;
    END
  END d[34]
  PIN d[350]
    DIRECTION INPUT ;
    USE SIGNAL ;
    PORT
      LAYER M4 ;
        RECT  0 25.488 0.084 25.512 ;
    END
  END d[350]
  PIN d[351]
    DIRECTION INPUT ;
    USE SIGNAL ;
    PORT
      LAYER M4 ;
        RECT  0 25.584 0.084 25.608 ;
    END
  END d[351]
  PIN d[352]
    DIRECTION INPUT ;
    USE SIGNAL ;
    PORT
      LAYER M4 ;
        RECT  0 51.792 0.084 51.816 ;
    END
  END d[352]
  PIN d[353]
    DIRECTION INPUT ;
    USE SIGNAL ;
    PORT
      LAYER M4 ;
        RECT  0 51.888 0.084 51.912 ;
    END
  END d[353]
  PIN d[354]
    DIRECTION INPUT ;
    USE SIGNAL ;
    PORT
      LAYER M4 ;
        RECT  0 51.984 0.084 52.008 ;
    END
  END d[354]
  PIN d[355]
    DIRECTION INPUT ;
    USE SIGNAL ;
    PORT
      LAYER M4 ;
        RECT  0 52.08 0.084 52.104 ;
    END
  END d[355]
  PIN d[356]
    DIRECTION INPUT ;
    USE SIGNAL ;
    PORT
      LAYER M4 ;
        RECT  0 52.176 0.084 52.2 ;
    END
  END d[356]
  PIN d[357]
    DIRECTION INPUT ;
    USE SIGNAL ;
    PORT
      LAYER M4 ;
        RECT  0 52.272 0.084 52.296 ;
    END
  END d[357]
  PIN d[358]
    DIRECTION INPUT ;
    USE SIGNAL ;
    PORT
      LAYER M4 ;
        RECT  0 52.368 0.084 52.392 ;
    END
  END d[358]
  PIN d[359]
    DIRECTION INPUT ;
    USE SIGNAL ;
    PORT
      LAYER M4 ;
        RECT  0 52.464 0.084 52.488 ;
    END
  END d[359]
  PIN d[35]
    DIRECTION INPUT ;
    USE SIGNAL ;
    PORT
      LAYER M4 ;
        RECT  0 35.952 0.084 35.976 ;
    END
  END d[35]
  PIN d[360]
    DIRECTION INPUT ;
    USE SIGNAL ;
    PORT
      LAYER M4 ;
        RECT  0 52.56 0.084 52.584 ;
    END
  END d[360]
  PIN d[361]
    DIRECTION INPUT ;
    USE SIGNAL ;
    PORT
      LAYER M4 ;
        RECT  0 52.656 0.084 52.68 ;
    END
  END d[361]
  PIN d[362]
    DIRECTION INPUT ;
    USE SIGNAL ;
    PORT
      LAYER M4 ;
        RECT  0 52.752 0.084 52.776 ;
    END
  END d[362]
  PIN d[363]
    DIRECTION INPUT ;
    USE SIGNAL ;
    PORT
      LAYER M4 ;
        RECT  0 52.848 0.084 52.872 ;
    END
  END d[363]
  PIN d[364]
    DIRECTION INPUT ;
    USE SIGNAL ;
    PORT
      LAYER M4 ;
        RECT  0 52.944 0.084 52.968 ;
    END
  END d[364]
  PIN d[365]
    DIRECTION INPUT ;
    USE SIGNAL ;
    PORT
      LAYER M4 ;
        RECT  0 53.04 0.084 53.064 ;
    END
  END d[365]
  PIN d[366]
    DIRECTION INPUT ;
    USE SIGNAL ;
    PORT
      LAYER M4 ;
        RECT  0 53.136 0.084 53.16 ;
    END
  END d[366]
  PIN d[367]
    DIRECTION INPUT ;
    USE SIGNAL ;
    PORT
      LAYER M4 ;
        RECT  0 53.232 0.084 53.256 ;
    END
  END d[367]
  PIN d[368]
    DIRECTION INPUT ;
    USE SIGNAL ;
    PORT
      LAYER M4 ;
        RECT  0 53.328 0.084 53.352 ;
    END
  END d[368]
  PIN d[369]
    DIRECTION INPUT ;
    USE SIGNAL ;
    PORT
      LAYER M4 ;
        RECT  0 53.424 0.084 53.448 ;
    END
  END d[369]
  PIN d[36]
    DIRECTION INPUT ;
    USE SIGNAL ;
    PORT
      LAYER M4 ;
        RECT  0 36.048 0.084 36.072 ;
    END
  END d[36]
  PIN d[370]
    DIRECTION INPUT ;
    USE SIGNAL ;
    PORT
      LAYER M4 ;
        RECT  0 53.52 0.084 53.544 ;
    END
  END d[370]
  PIN d[371]
    DIRECTION INPUT ;
    USE SIGNAL ;
    PORT
      LAYER M4 ;
        RECT  0 53.616 0.084 53.64 ;
    END
  END d[371]
  PIN d[372]
    DIRECTION INPUT ;
    USE SIGNAL ;
    PORT
      LAYER M4 ;
        RECT  0 53.712 0.084 53.736 ;
    END
  END d[372]
  PIN d[373]
    DIRECTION INPUT ;
    USE SIGNAL ;
    PORT
      LAYER M4 ;
        RECT  0 53.808 0.084 53.832 ;
    END
  END d[373]
  PIN d[374]
    DIRECTION INPUT ;
    USE SIGNAL ;
    PORT
      LAYER M4 ;
        RECT  0 53.904 0.084 53.928 ;
    END
  END d[374]
  PIN d[375]
    DIRECTION INPUT ;
    USE SIGNAL ;
    PORT
      LAYER M4 ;
        RECT  0 54 0.084 54.024 ;
    END
  END d[375]
  PIN d[376]
    DIRECTION INPUT ;
    USE SIGNAL ;
    PORT
      LAYER M4 ;
        RECT  0 54.096 0.084 54.12 ;
    END
  END d[376]
  PIN d[377]
    DIRECTION INPUT ;
    USE SIGNAL ;
    PORT
      LAYER M4 ;
        RECT  0 54.192 0.084 54.216 ;
    END
  END d[377]
  PIN d[378]
    DIRECTION INPUT ;
    USE SIGNAL ;
    PORT
      LAYER M4 ;
        RECT  0 54.288 0.084 54.312 ;
    END
  END d[378]
  PIN d[379]
    DIRECTION INPUT ;
    USE SIGNAL ;
    PORT
      LAYER M4 ;
        RECT  0 54.384 0.084 54.408 ;
    END
  END d[379]
  PIN d[37]
    DIRECTION INPUT ;
    USE SIGNAL ;
    PORT
      LAYER M4 ;
        RECT  0 36.144 0.084 36.168 ;
    END
  END d[37]
  PIN d[380]
    DIRECTION INPUT ;
    USE SIGNAL ;
    PORT
      LAYER M4 ;
        RECT  0 54.48 0.084 54.504 ;
    END
  END d[380]
  PIN d[381]
    DIRECTION INPUT ;
    USE SIGNAL ;
    PORT
      LAYER M4 ;
        RECT  0 54.576 0.084 54.6 ;
    END
  END d[381]
  PIN d[382]
    DIRECTION INPUT ;
    USE SIGNAL ;
    PORT
      LAYER M4 ;
        RECT  0 54.672 0.084 54.696 ;
    END
  END d[382]
  PIN d[383]
    DIRECTION INPUT ;
    USE SIGNAL ;
    PORT
      LAYER M4 ;
        RECT  0 54.768 0.084 54.792 ;
    END
  END d[383]
  PIN d[384]
    DIRECTION INPUT ;
    USE SIGNAL ;
    PORT
      LAYER M4 ;
        RECT  0 19.536 0.084 19.56 ;
    END
  END d[384]
  PIN d[385]
    DIRECTION INPUT ;
    USE SIGNAL ;
    PORT
      LAYER M4 ;
        RECT  0 19.632 0.084 19.656 ;
    END
  END d[385]
  PIN d[386]
    DIRECTION INPUT ;
    USE SIGNAL ;
    PORT
      LAYER M4 ;
        RECT  0 19.728 0.084 19.752 ;
    END
  END d[386]
  PIN d[387]
    DIRECTION INPUT ;
    USE SIGNAL ;
    PORT
      LAYER M4 ;
        RECT  0 19.824 0.084 19.848 ;
    END
  END d[387]
  PIN d[388]
    DIRECTION INPUT ;
    USE SIGNAL ;
    PORT
      LAYER M4 ;
        RECT  0 19.92 0.084 19.944 ;
    END
  END d[388]
  PIN d[389]
    DIRECTION INPUT ;
    USE SIGNAL ;
    PORT
      LAYER M4 ;
        RECT  0 20.016 0.084 20.04 ;
    END
  END d[389]
  PIN d[38]
    DIRECTION INPUT ;
    USE SIGNAL ;
    PORT
      LAYER M4 ;
        RECT  0 36.24 0.084 36.264 ;
    END
  END d[38]
  PIN d[390]
    DIRECTION INPUT ;
    USE SIGNAL ;
    PORT
      LAYER M4 ;
        RECT  0 20.112 0.084 20.136 ;
    END
  END d[390]
  PIN d[391]
    DIRECTION INPUT ;
    USE SIGNAL ;
    PORT
      LAYER M4 ;
        RECT  0 20.208 0.084 20.232 ;
    END
  END d[391]
  PIN d[392]
    DIRECTION INPUT ;
    USE SIGNAL ;
    PORT
      LAYER M4 ;
        RECT  0 20.304 0.084 20.328 ;
    END
  END d[392]
  PIN d[393]
    DIRECTION INPUT ;
    USE SIGNAL ;
    PORT
      LAYER M4 ;
        RECT  0 20.4 0.084 20.424 ;
    END
  END d[393]
  PIN d[394]
    DIRECTION INPUT ;
    USE SIGNAL ;
    PORT
      LAYER M4 ;
        RECT  0 20.496 0.084 20.52 ;
    END
  END d[394]
  PIN d[395]
    DIRECTION INPUT ;
    USE SIGNAL ;
    PORT
      LAYER M4 ;
        RECT  0 20.592 0.084 20.616 ;
    END
  END d[395]
  PIN d[396]
    DIRECTION INPUT ;
    USE SIGNAL ;
    PORT
      LAYER M4 ;
        RECT  0 20.688 0.084 20.712 ;
    END
  END d[396]
  PIN d[397]
    DIRECTION INPUT ;
    USE SIGNAL ;
    PORT
      LAYER M4 ;
        RECT  0 20.784 0.084 20.808 ;
    END
  END d[397]
  PIN d[398]
    DIRECTION INPUT ;
    USE SIGNAL ;
    PORT
      LAYER M4 ;
        RECT  0 20.88 0.084 20.904 ;
    END
  END d[398]
  PIN d[399]
    DIRECTION INPUT ;
    USE SIGNAL ;
    PORT
      LAYER M4 ;
        RECT  0 20.976 0.084 21 ;
    END
  END d[399]
  PIN d[39]
    DIRECTION INPUT ;
    USE SIGNAL ;
    PORT
      LAYER M4 ;
        RECT  0 36.336 0.084 36.36 ;
    END
  END d[39]
  PIN d[3]
    DIRECTION INPUT ;
    USE SIGNAL ;
    PORT
      LAYER M4 ;
        RECT  0 26.736 0.084 26.76 ;
    END
  END d[3]
  PIN d[400]
    DIRECTION INPUT ;
    USE SIGNAL ;
    PORT
      LAYER M4 ;
        RECT  0 21.072 0.084 21.096 ;
    END
  END d[400]
  PIN d[401]
    DIRECTION INPUT ;
    USE SIGNAL ;
    PORT
      LAYER M4 ;
        RECT  0 21.168 0.084 21.192 ;
    END
  END d[401]
  PIN d[402]
    DIRECTION INPUT ;
    USE SIGNAL ;
    PORT
      LAYER M4 ;
        RECT  0 21.264 0.084 21.288 ;
    END
  END d[402]
  PIN d[403]
    DIRECTION INPUT ;
    USE SIGNAL ;
    PORT
      LAYER M4 ;
        RECT  0 21.36 0.084 21.384 ;
    END
  END d[403]
  PIN d[404]
    DIRECTION INPUT ;
    USE SIGNAL ;
    PORT
      LAYER M4 ;
        RECT  0 21.456 0.084 21.48 ;
    END
  END d[404]
  PIN d[405]
    DIRECTION INPUT ;
    USE SIGNAL ;
    PORT
      LAYER M4 ;
        RECT  0 21.552 0.084 21.576 ;
    END
  END d[405]
  PIN d[406]
    DIRECTION INPUT ;
    USE SIGNAL ;
    PORT
      LAYER M4 ;
        RECT  0 21.648 0.084 21.672 ;
    END
  END d[406]
  PIN d[407]
    DIRECTION INPUT ;
    USE SIGNAL ;
    PORT
      LAYER M4 ;
        RECT  0 21.744 0.084 21.768 ;
    END
  END d[407]
  PIN d[408]
    DIRECTION INPUT ;
    USE SIGNAL ;
    PORT
      LAYER M4 ;
        RECT  0 21.84 0.084 21.864 ;
    END
  END d[408]
  PIN d[409]
    DIRECTION INPUT ;
    USE SIGNAL ;
    PORT
      LAYER M4 ;
        RECT  0 21.936 0.084 21.96 ;
    END
  END d[409]
  PIN d[40]
    DIRECTION INPUT ;
    USE SIGNAL ;
    PORT
      LAYER M4 ;
        RECT  0 36.432 0.084 36.456 ;
    END
  END d[40]
  PIN d[410]
    DIRECTION INPUT ;
    USE SIGNAL ;
    PORT
      LAYER M4 ;
        RECT  0 22.032 0.084 22.056 ;
    END
  END d[410]
  PIN d[411]
    DIRECTION INPUT ;
    USE SIGNAL ;
    PORT
      LAYER M4 ;
        RECT  0 22.128 0.084 22.152 ;
    END
  END d[411]
  PIN d[412]
    DIRECTION INPUT ;
    USE SIGNAL ;
    PORT
      LAYER M4 ;
        RECT  0 22.224 0.084 22.248 ;
    END
  END d[412]
  PIN d[413]
    DIRECTION INPUT ;
    USE SIGNAL ;
    PORT
      LAYER M4 ;
        RECT  0 22.32 0.084 22.344 ;
    END
  END d[413]
  PIN d[414]
    DIRECTION INPUT ;
    USE SIGNAL ;
    PORT
      LAYER M4 ;
        RECT  0 22.416 0.084 22.44 ;
    END
  END d[414]
  PIN d[415]
    DIRECTION INPUT ;
    USE SIGNAL ;
    PORT
      LAYER M4 ;
        RECT  0 22.512 0.084 22.536 ;
    END
  END d[415]
  PIN d[416]
    DIRECTION INPUT ;
    USE SIGNAL ;
    PORT
      LAYER M4 ;
        RECT  0 45.648 0.084 45.672 ;
    END
  END d[416]
  PIN d[417]
    DIRECTION INPUT ;
    USE SIGNAL ;
    PORT
      LAYER M4 ;
        RECT  0 45.744 0.084 45.768 ;
    END
  END d[417]
  PIN d[418]
    DIRECTION INPUT ;
    USE SIGNAL ;
    PORT
      LAYER M4 ;
        RECT  0 45.84 0.084 45.864 ;
    END
  END d[418]
  PIN d[419]
    DIRECTION INPUT ;
    USE SIGNAL ;
    PORT
      LAYER M4 ;
        RECT  0 45.936 0.084 45.96 ;
    END
  END d[419]
  PIN d[41]
    DIRECTION INPUT ;
    USE SIGNAL ;
    PORT
      LAYER M4 ;
        RECT  0 36.528 0.084 36.552 ;
    END
  END d[41]
  PIN d[420]
    DIRECTION INPUT ;
    USE SIGNAL ;
    PORT
      LAYER M4 ;
        RECT  0 46.032 0.084 46.056 ;
    END
  END d[420]
  PIN d[421]
    DIRECTION INPUT ;
    USE SIGNAL ;
    PORT
      LAYER M4 ;
        RECT  0 46.128 0.084 46.152 ;
    END
  END d[421]
  PIN d[422]
    DIRECTION INPUT ;
    USE SIGNAL ;
    PORT
      LAYER M4 ;
        RECT  0 46.224 0.084 46.248 ;
    END
  END d[422]
  PIN d[423]
    DIRECTION INPUT ;
    USE SIGNAL ;
    PORT
      LAYER M4 ;
        RECT  0 46.32 0.084 46.344 ;
    END
  END d[423]
  PIN d[424]
    DIRECTION INPUT ;
    USE SIGNAL ;
    PORT
      LAYER M4 ;
        RECT  0 46.416 0.084 46.44 ;
    END
  END d[424]
  PIN d[425]
    DIRECTION INPUT ;
    USE SIGNAL ;
    PORT
      LAYER M4 ;
        RECT  0 46.512 0.084 46.536 ;
    END
  END d[425]
  PIN d[426]
    DIRECTION INPUT ;
    USE SIGNAL ;
    PORT
      LAYER M4 ;
        RECT  0 46.608 0.084 46.632 ;
    END
  END d[426]
  PIN d[427]
    DIRECTION INPUT ;
    USE SIGNAL ;
    PORT
      LAYER M4 ;
        RECT  0 46.704 0.084 46.728 ;
    END
  END d[427]
  PIN d[428]
    DIRECTION INPUT ;
    USE SIGNAL ;
    PORT
      LAYER M4 ;
        RECT  0 46.8 0.084 46.824 ;
    END
  END d[428]
  PIN d[429]
    DIRECTION INPUT ;
    USE SIGNAL ;
    PORT
      LAYER M4 ;
        RECT  0 46.896 0.084 46.92 ;
    END
  END d[429]
  PIN d[42]
    DIRECTION INPUT ;
    USE SIGNAL ;
    PORT
      LAYER M4 ;
        RECT  0 36.624 0.084 36.648 ;
    END
  END d[42]
  PIN d[430]
    DIRECTION INPUT ;
    USE SIGNAL ;
    PORT
      LAYER M4 ;
        RECT  0 46.992 0.084 47.016 ;
    END
  END d[430]
  PIN d[431]
    DIRECTION INPUT ;
    USE SIGNAL ;
    PORT
      LAYER M4 ;
        RECT  0 47.088 0.084 47.112 ;
    END
  END d[431]
  PIN d[432]
    DIRECTION INPUT ;
    USE SIGNAL ;
    PORT
      LAYER M4 ;
        RECT  0 47.184 0.084 47.208 ;
    END
  END d[432]
  PIN d[433]
    DIRECTION INPUT ;
    USE SIGNAL ;
    PORT
      LAYER M4 ;
        RECT  0 47.28 0.084 47.304 ;
    END
  END d[433]
  PIN d[434]
    DIRECTION INPUT ;
    USE SIGNAL ;
    PORT
      LAYER M4 ;
        RECT  0 47.376 0.084 47.4 ;
    END
  END d[434]
  PIN d[435]
    DIRECTION INPUT ;
    USE SIGNAL ;
    PORT
      LAYER M4 ;
        RECT  0 47.472 0.084 47.496 ;
    END
  END d[435]
  PIN d[436]
    DIRECTION INPUT ;
    USE SIGNAL ;
    PORT
      LAYER M4 ;
        RECT  0 47.568 0.084 47.592 ;
    END
  END d[436]
  PIN d[437]
    DIRECTION INPUT ;
    USE SIGNAL ;
    PORT
      LAYER M4 ;
        RECT  0 47.664 0.084 47.688 ;
    END
  END d[437]
  PIN d[438]
    DIRECTION INPUT ;
    USE SIGNAL ;
    PORT
      LAYER M4 ;
        RECT  0 47.76 0.084 47.784 ;
    END
  END d[438]
  PIN d[439]
    DIRECTION INPUT ;
    USE SIGNAL ;
    PORT
      LAYER M4 ;
        RECT  0 47.856 0.084 47.88 ;
    END
  END d[439]
  PIN d[43]
    DIRECTION INPUT ;
    USE SIGNAL ;
    PORT
      LAYER M4 ;
        RECT  0 36.72 0.084 36.744 ;
    END
  END d[43]
  PIN d[440]
    DIRECTION INPUT ;
    USE SIGNAL ;
    PORT
      LAYER M4 ;
        RECT  0 47.952 0.084 47.976 ;
    END
  END d[440]
  PIN d[441]
    DIRECTION INPUT ;
    USE SIGNAL ;
    PORT
      LAYER M4 ;
        RECT  0 48.048 0.084 48.072 ;
    END
  END d[441]
  PIN d[442]
    DIRECTION INPUT ;
    USE SIGNAL ;
    PORT
      LAYER M4 ;
        RECT  0 48.144 0.084 48.168 ;
    END
  END d[442]
  PIN d[443]
    DIRECTION INPUT ;
    USE SIGNAL ;
    PORT
      LAYER M4 ;
        RECT  0 48.24 0.084 48.264 ;
    END
  END d[443]
  PIN d[444]
    DIRECTION INPUT ;
    USE SIGNAL ;
    PORT
      LAYER M4 ;
        RECT  0 48.336 0.084 48.36 ;
    END
  END d[444]
  PIN d[445]
    DIRECTION INPUT ;
    USE SIGNAL ;
    PORT
      LAYER M4 ;
        RECT  0 48.432 0.084 48.456 ;
    END
  END d[445]
  PIN d[446]
    DIRECTION INPUT ;
    USE SIGNAL ;
    PORT
      LAYER M4 ;
        RECT  0 48.528 0.084 48.552 ;
    END
  END d[446]
  PIN d[447]
    DIRECTION INPUT ;
    USE SIGNAL ;
    PORT
      LAYER M4 ;
        RECT  0 48.624 0.084 48.648 ;
    END
  END d[447]
  PIN d[448]
    DIRECTION INPUT ;
    USE SIGNAL ;
    PORT
      LAYER M4 ;
        RECT  0 3.408 0.084 3.432 ;
    END
  END d[448]
  PIN d[449]
    DIRECTION INPUT ;
    USE SIGNAL ;
    PORT
      LAYER M4 ;
        RECT  0 3.504 0.084 3.528 ;
    END
  END d[449]
  PIN d[44]
    DIRECTION INPUT ;
    USE SIGNAL ;
    PORT
      LAYER M4 ;
        RECT  0 36.816 0.084 36.84 ;
    END
  END d[44]
  PIN d[450]
    DIRECTION INPUT ;
    USE SIGNAL ;
    PORT
      LAYER M4 ;
        RECT  0 3.6 0.084 3.624 ;
    END
  END d[450]
  PIN d[451]
    DIRECTION INPUT ;
    USE SIGNAL ;
    PORT
      LAYER M4 ;
        RECT  0 3.696 0.084 3.72 ;
    END
  END d[451]
  PIN d[452]
    DIRECTION INPUT ;
    USE SIGNAL ;
    PORT
      LAYER M4 ;
        RECT  0 3.792 0.084 3.816 ;
    END
  END d[452]
  PIN d[453]
    DIRECTION INPUT ;
    USE SIGNAL ;
    PORT
      LAYER M4 ;
        RECT  0 3.888 0.084 3.912 ;
    END
  END d[453]
  PIN d[454]
    DIRECTION INPUT ;
    USE SIGNAL ;
    PORT
      LAYER M4 ;
        RECT  0 3.984 0.084 4.008 ;
    END
  END d[454]
  PIN d[455]
    DIRECTION INPUT ;
    USE SIGNAL ;
    PORT
      LAYER M4 ;
        RECT  0 4.08 0.084 4.104 ;
    END
  END d[455]
  PIN d[456]
    DIRECTION INPUT ;
    USE SIGNAL ;
    PORT
      LAYER M4 ;
        RECT  0 4.176 0.084 4.2 ;
    END
  END d[456]
  PIN d[457]
    DIRECTION INPUT ;
    USE SIGNAL ;
    PORT
      LAYER M4 ;
        RECT  0 4.272 0.084 4.296 ;
    END
  END d[457]
  PIN d[458]
    DIRECTION INPUT ;
    USE SIGNAL ;
    PORT
      LAYER M4 ;
        RECT  0 4.368 0.084 4.392 ;
    END
  END d[458]
  PIN d[459]
    DIRECTION INPUT ;
    USE SIGNAL ;
    PORT
      LAYER M4 ;
        RECT  0 4.464 0.084 4.488 ;
    END
  END d[459]
  PIN d[45]
    DIRECTION INPUT ;
    USE SIGNAL ;
    PORT
      LAYER M4 ;
        RECT  0 36.912 0.084 36.936 ;
    END
  END d[45]
  PIN d[460]
    DIRECTION INPUT ;
    USE SIGNAL ;
    PORT
      LAYER M4 ;
        RECT  0 4.56 0.084 4.584 ;
    END
  END d[460]
  PIN d[461]
    DIRECTION INPUT ;
    USE SIGNAL ;
    PORT
      LAYER M4 ;
        RECT  0 4.656 0.084 4.68 ;
    END
  END d[461]
  PIN d[462]
    DIRECTION INPUT ;
    USE SIGNAL ;
    PORT
      LAYER M4 ;
        RECT  0 4.752 0.084 4.776 ;
    END
  END d[462]
  PIN d[463]
    DIRECTION INPUT ;
    USE SIGNAL ;
    PORT
      LAYER M4 ;
        RECT  0 4.848 0.084 4.872 ;
    END
  END d[463]
  PIN d[464]
    DIRECTION INPUT ;
    USE SIGNAL ;
    PORT
      LAYER M4 ;
        RECT  0 4.944 0.084 4.968 ;
    END
  END d[464]
  PIN d[465]
    DIRECTION INPUT ;
    USE SIGNAL ;
    PORT
      LAYER M4 ;
        RECT  0 5.04 0.084 5.064 ;
    END
  END d[465]
  PIN d[466]
    DIRECTION INPUT ;
    USE SIGNAL ;
    PORT
      LAYER M4 ;
        RECT  0 5.136 0.084 5.16 ;
    END
  END d[466]
  PIN d[467]
    DIRECTION INPUT ;
    USE SIGNAL ;
    PORT
      LAYER M4 ;
        RECT  0 5.232 0.084 5.256 ;
    END
  END d[467]
  PIN d[468]
    DIRECTION INPUT ;
    USE SIGNAL ;
    PORT
      LAYER M4 ;
        RECT  0 5.328 0.084 5.352 ;
    END
  END d[468]
  PIN d[469]
    DIRECTION INPUT ;
    USE SIGNAL ;
    PORT
      LAYER M4 ;
        RECT  0 5.424 0.084 5.448 ;
    END
  END d[469]
  PIN d[46]
    DIRECTION INPUT ;
    USE SIGNAL ;
    PORT
      LAYER M4 ;
        RECT  0 37.008 0.084 37.032 ;
    END
  END d[46]
  PIN d[470]
    DIRECTION INPUT ;
    USE SIGNAL ;
    PORT
      LAYER M4 ;
        RECT  0 5.52 0.084 5.544 ;
    END
  END d[470]
  PIN d[471]
    DIRECTION INPUT ;
    USE SIGNAL ;
    PORT
      LAYER M4 ;
        RECT  0 5.616 0.084 5.64 ;
    END
  END d[471]
  PIN d[472]
    DIRECTION INPUT ;
    USE SIGNAL ;
    PORT
      LAYER M4 ;
        RECT  0 5.712 0.084 5.736 ;
    END
  END d[472]
  PIN d[473]
    DIRECTION INPUT ;
    USE SIGNAL ;
    PORT
      LAYER M4 ;
        RECT  0 5.808 0.084 5.832 ;
    END
  END d[473]
  PIN d[474]
    DIRECTION INPUT ;
    USE SIGNAL ;
    PORT
      LAYER M4 ;
        RECT  0 5.904 0.084 5.928 ;
    END
  END d[474]
  PIN d[475]
    DIRECTION INPUT ;
    USE SIGNAL ;
    PORT
      LAYER M4 ;
        RECT  0 6 0.084 6.024 ;
    END
  END d[475]
  PIN d[476]
    DIRECTION INPUT ;
    USE SIGNAL ;
    PORT
      LAYER M4 ;
        RECT  0 6.096 0.084 6.12 ;
    END
  END d[476]
  PIN d[477]
    DIRECTION INPUT ;
    USE SIGNAL ;
    PORT
      LAYER M4 ;
        RECT  0 6.192 0.084 6.216 ;
    END
  END d[477]
  PIN d[478]
    DIRECTION INPUT ;
    USE SIGNAL ;
    PORT
      LAYER M4 ;
        RECT  0 6.288 0.084 6.312 ;
    END
  END d[478]
  PIN d[479]
    DIRECTION INPUT ;
    USE SIGNAL ;
    PORT
      LAYER M4 ;
        RECT  0 6.384 0.084 6.408 ;
    END
  END d[479]
  PIN d[47]
    DIRECTION INPUT ;
    USE SIGNAL ;
    PORT
      LAYER M4 ;
        RECT  0 37.104 0.084 37.128 ;
    END
  END d[47]
  PIN d[480]
    DIRECTION INPUT ;
    USE SIGNAL ;
    PORT
      LAYER M4 ;
        RECT  0 48.72 0.084 48.744 ;
    END
  END d[480]
  PIN d[481]
    DIRECTION INPUT ;
    USE SIGNAL ;
    PORT
      LAYER M4 ;
        RECT  0 48.816 0.084 48.84 ;
    END
  END d[481]
  PIN d[482]
    DIRECTION INPUT ;
    USE SIGNAL ;
    PORT
      LAYER M4 ;
        RECT  0 48.912 0.084 48.936 ;
    END
  END d[482]
  PIN d[483]
    DIRECTION INPUT ;
    USE SIGNAL ;
    PORT
      LAYER M4 ;
        RECT  0 49.008 0.084 49.032 ;
    END
  END d[483]
  PIN d[484]
    DIRECTION INPUT ;
    USE SIGNAL ;
    PORT
      LAYER M4 ;
        RECT  0 49.104 0.084 49.128 ;
    END
  END d[484]
  PIN d[485]
    DIRECTION INPUT ;
    USE SIGNAL ;
    PORT
      LAYER M4 ;
        RECT  0 49.2 0.084 49.224 ;
    END
  END d[485]
  PIN d[486]
    DIRECTION INPUT ;
    USE SIGNAL ;
    PORT
      LAYER M4 ;
        RECT  0 49.296 0.084 49.32 ;
    END
  END d[486]
  PIN d[487]
    DIRECTION INPUT ;
    USE SIGNAL ;
    PORT
      LAYER M4 ;
        RECT  0 49.392 0.084 49.416 ;
    END
  END d[487]
  PIN d[488]
    DIRECTION INPUT ;
    USE SIGNAL ;
    PORT
      LAYER M4 ;
        RECT  0 49.488 0.084 49.512 ;
    END
  END d[488]
  PIN d[489]
    DIRECTION INPUT ;
    USE SIGNAL ;
    PORT
      LAYER M4 ;
        RECT  0 49.584 0.084 49.608 ;
    END
  END d[489]
  PIN d[48]
    DIRECTION INPUT ;
    USE SIGNAL ;
    PORT
      LAYER M4 ;
        RECT  0 37.2 0.084 37.224 ;
    END
  END d[48]
  PIN d[490]
    DIRECTION INPUT ;
    USE SIGNAL ;
    PORT
      LAYER M4 ;
        RECT  0 49.68 0.084 49.704 ;
    END
  END d[490]
  PIN d[491]
    DIRECTION INPUT ;
    USE SIGNAL ;
    PORT
      LAYER M4 ;
        RECT  0 49.776 0.084 49.8 ;
    END
  END d[491]
  PIN d[492]
    DIRECTION INPUT ;
    USE SIGNAL ;
    PORT
      LAYER M4 ;
        RECT  0 49.872 0.084 49.896 ;
    END
  END d[492]
  PIN d[493]
    DIRECTION INPUT ;
    USE SIGNAL ;
    PORT
      LAYER M4 ;
        RECT  0 49.968 0.084 49.992 ;
    END
  END d[493]
  PIN d[494]
    DIRECTION INPUT ;
    USE SIGNAL ;
    PORT
      LAYER M4 ;
        RECT  0 50.064 0.084 50.088 ;
    END
  END d[494]
  PIN d[495]
    DIRECTION INPUT ;
    USE SIGNAL ;
    PORT
      LAYER M4 ;
        RECT  0 50.16 0.084 50.184 ;
    END
  END d[495]
  PIN d[496]
    DIRECTION INPUT ;
    USE SIGNAL ;
    PORT
      LAYER M4 ;
        RECT  0 50.256 0.084 50.28 ;
    END
  END d[496]
  PIN d[497]
    DIRECTION INPUT ;
    USE SIGNAL ;
    PORT
      LAYER M4 ;
        RECT  0 50.352 0.084 50.376 ;
    END
  END d[497]
  PIN d[498]
    DIRECTION INPUT ;
    USE SIGNAL ;
    PORT
      LAYER M4 ;
        RECT  0 50.448 0.084 50.472 ;
    END
  END d[498]
  PIN d[499]
    DIRECTION INPUT ;
    USE SIGNAL ;
    PORT
      LAYER M4 ;
        RECT  0 50.544 0.084 50.568 ;
    END
  END d[499]
  PIN d[49]
    DIRECTION INPUT ;
    USE SIGNAL ;
    PORT
      LAYER M4 ;
        RECT  0 37.296 0.084 37.32 ;
    END
  END d[49]
  PIN d[4]
    DIRECTION INPUT ;
    USE SIGNAL ;
    PORT
      LAYER M4 ;
        RECT  0 26.832 0.084 26.856 ;
    END
  END d[4]
  PIN d[500]
    DIRECTION INPUT ;
    USE SIGNAL ;
    PORT
      LAYER M4 ;
        RECT  0 50.64 0.084 50.664 ;
    END
  END d[500]
  PIN d[501]
    DIRECTION INPUT ;
    USE SIGNAL ;
    PORT
      LAYER M4 ;
        RECT  0 50.736 0.084 50.76 ;
    END
  END d[501]
  PIN d[502]
    DIRECTION INPUT ;
    USE SIGNAL ;
    PORT
      LAYER M4 ;
        RECT  0 50.832 0.084 50.856 ;
    END
  END d[502]
  PIN d[503]
    DIRECTION INPUT ;
    USE SIGNAL ;
    PORT
      LAYER M4 ;
        RECT  0 50.928 0.084 50.952 ;
    END
  END d[503]
  PIN d[504]
    DIRECTION INPUT ;
    USE SIGNAL ;
    PORT
      LAYER M4 ;
        RECT  0 51.024 0.084 51.048 ;
    END
  END d[504]
  PIN d[505]
    DIRECTION INPUT ;
    USE SIGNAL ;
    PORT
      LAYER M4 ;
        RECT  0 51.12 0.084 51.144 ;
    END
  END d[505]
  PIN d[506]
    DIRECTION INPUT ;
    USE SIGNAL ;
    PORT
      LAYER M4 ;
        RECT  0 51.216 0.084 51.24 ;
    END
  END d[506]
  PIN d[507]
    DIRECTION INPUT ;
    USE SIGNAL ;
    PORT
      LAYER M4 ;
        RECT  0 51.312 0.084 51.336 ;
    END
  END d[507]
  PIN d[508]
    DIRECTION INPUT ;
    USE SIGNAL ;
    PORT
      LAYER M4 ;
        RECT  0 51.408 0.084 51.432 ;
    END
  END d[508]
  PIN d[509]
    DIRECTION INPUT ;
    USE SIGNAL ;
    PORT
      LAYER M4 ;
        RECT  0 51.504 0.084 51.528 ;
    END
  END d[509]
  PIN d[50]
    DIRECTION INPUT ;
    USE SIGNAL ;
    PORT
      LAYER M4 ;
        RECT  0 37.392 0.084 37.416 ;
    END
  END d[50]
  PIN d[510]
    DIRECTION INPUT ;
    USE SIGNAL ;
    PORT
      LAYER M4 ;
        RECT  0 51.6 0.084 51.624 ;
    END
  END d[510]
  PIN d[511]
    DIRECTION INPUT ;
    USE SIGNAL ;
    PORT
      LAYER M4 ;
        RECT  0 51.696 0.084 51.72 ;
    END
  END d[511]
  PIN d[51]
    DIRECTION INPUT ;
    USE SIGNAL ;
    PORT
      LAYER M4 ;
        RECT  0 37.488 0.084 37.512 ;
    END
  END d[51]
  PIN d[52]
    DIRECTION INPUT ;
    USE SIGNAL ;
    PORT
      LAYER M4 ;
        RECT  0 37.584 0.084 37.608 ;
    END
  END d[52]
  PIN d[53]
    DIRECTION INPUT ;
    USE SIGNAL ;
    PORT
      LAYER M4 ;
        RECT  0 37.68 0.084 37.704 ;
    END
  END d[53]
  PIN d[54]
    DIRECTION INPUT ;
    USE SIGNAL ;
    PORT
      LAYER M4 ;
        RECT  0 37.776 0.084 37.8 ;
    END
  END d[54]
  PIN d[55]
    DIRECTION INPUT ;
    USE SIGNAL ;
    PORT
      LAYER M4 ;
        RECT  0 37.872 0.084 37.896 ;
    END
  END d[55]
  PIN d[56]
    DIRECTION INPUT ;
    USE SIGNAL ;
    PORT
      LAYER M4 ;
        RECT  0 37.968 0.084 37.992 ;
    END
  END d[56]
  PIN d[57]
    DIRECTION INPUT ;
    USE SIGNAL ;
    PORT
      LAYER M4 ;
        RECT  0 38.064 0.084 38.088 ;
    END
  END d[57]
  PIN d[58]
    DIRECTION INPUT ;
    USE SIGNAL ;
    PORT
      LAYER M4 ;
        RECT  0 38.16 0.084 38.184 ;
    END
  END d[58]
  PIN d[59]
    DIRECTION INPUT ;
    USE SIGNAL ;
    PORT
      LAYER M4 ;
        RECT  0 38.256 0.084 38.28 ;
    END
  END d[59]
  PIN d[5]
    DIRECTION INPUT ;
    USE SIGNAL ;
    PORT
      LAYER M4 ;
        RECT  0 26.928 0.084 26.952 ;
    END
  END d[5]
  PIN d[60]
    DIRECTION INPUT ;
    USE SIGNAL ;
    PORT
      LAYER M4 ;
        RECT  0 38.352 0.084 38.376 ;
    END
  END d[60]
  PIN d[61]
    DIRECTION INPUT ;
    USE SIGNAL ;
    PORT
      LAYER M4 ;
        RECT  0 38.448 0.084 38.472 ;
    END
  END d[61]
  PIN d[62]
    DIRECTION INPUT ;
    USE SIGNAL ;
    PORT
      LAYER M4 ;
        RECT  0 38.544 0.084 38.568 ;
    END
  END d[62]
  PIN d[63]
    DIRECTION INPUT ;
    USE SIGNAL ;
    PORT
      LAYER M4 ;
        RECT  0 38.64 0.084 38.664 ;
    END
  END d[63]
  PIN d[64]
    DIRECTION INPUT ;
    USE SIGNAL ;
    PORT
      LAYER M4 ;
        RECT  0 29.52 0.084 29.544 ;
    END
  END d[64]
  PIN d[65]
    DIRECTION INPUT ;
    USE SIGNAL ;
    PORT
      LAYER M4 ;
        RECT  0 29.616 0.084 29.64 ;
    END
  END d[65]
  PIN d[66]
    DIRECTION INPUT ;
    USE SIGNAL ;
    PORT
      LAYER M4 ;
        RECT  0 29.712 0.084 29.736 ;
    END
  END d[66]
  PIN d[67]
    DIRECTION INPUT ;
    USE SIGNAL ;
    PORT
      LAYER M4 ;
        RECT  0 29.808 0.084 29.832 ;
    END
  END d[67]
  PIN d[68]
    DIRECTION INPUT ;
    USE SIGNAL ;
    PORT
      LAYER M4 ;
        RECT  0 29.904 0.084 29.928 ;
    END
  END d[68]
  PIN d[69]
    DIRECTION INPUT ;
    USE SIGNAL ;
    PORT
      LAYER M4 ;
        RECT  0 30 0.084 30.024 ;
    END
  END d[69]
  PIN d[6]
    DIRECTION INPUT ;
    USE SIGNAL ;
    PORT
      LAYER M4 ;
        RECT  0 27.024 0.084 27.048 ;
    END
  END d[6]
  PIN d[70]
    DIRECTION INPUT ;
    USE SIGNAL ;
    PORT
      LAYER M4 ;
        RECT  0 30.096 0.084 30.12 ;
    END
  END d[70]
  PIN d[71]
    DIRECTION INPUT ;
    USE SIGNAL ;
    PORT
      LAYER M4 ;
        RECT  0 30.192 0.084 30.216 ;
    END
  END d[71]
  PIN d[72]
    DIRECTION INPUT ;
    USE SIGNAL ;
    PORT
      LAYER M4 ;
        RECT  0 30.288 0.084 30.312 ;
    END
  END d[72]
  PIN d[73]
    DIRECTION INPUT ;
    USE SIGNAL ;
    PORT
      LAYER M4 ;
        RECT  0 30.384 0.084 30.408 ;
    END
  END d[73]
  PIN d[74]
    DIRECTION INPUT ;
    USE SIGNAL ;
    PORT
      LAYER M4 ;
        RECT  0 30.48 0.084 30.504 ;
    END
  END d[74]
  PIN d[75]
    DIRECTION INPUT ;
    USE SIGNAL ;
    PORT
      LAYER M4 ;
        RECT  0 30.576 0.084 30.6 ;
    END
  END d[75]
  PIN d[76]
    DIRECTION INPUT ;
    USE SIGNAL ;
    PORT
      LAYER M4 ;
        RECT  0 30.672 0.084 30.696 ;
    END
  END d[76]
  PIN d[77]
    DIRECTION INPUT ;
    USE SIGNAL ;
    PORT
      LAYER M4 ;
        RECT  0 30.768 0.084 30.792 ;
    END
  END d[77]
  PIN d[78]
    DIRECTION INPUT ;
    USE SIGNAL ;
    PORT
      LAYER M4 ;
        RECT  0 30.864 0.084 30.888 ;
    END
  END d[78]
  PIN d[79]
    DIRECTION INPUT ;
    USE SIGNAL ;
    PORT
      LAYER M4 ;
        RECT  0 30.96 0.084 30.984 ;
    END
  END d[79]
  PIN d[7]
    DIRECTION INPUT ;
    USE SIGNAL ;
    PORT
      LAYER M4 ;
        RECT  0 27.12 0.084 27.144 ;
    END
  END d[7]
  PIN d[80]
    DIRECTION INPUT ;
    USE SIGNAL ;
    PORT
      LAYER M4 ;
        RECT  0 31.056 0.084 31.08 ;
    END
  END d[80]
  PIN d[81]
    DIRECTION INPUT ;
    USE SIGNAL ;
    PORT
      LAYER M4 ;
        RECT  0 31.152 0.084 31.176 ;
    END
  END d[81]
  PIN d[82]
    DIRECTION INPUT ;
    USE SIGNAL ;
    PORT
      LAYER M4 ;
        RECT  0 31.248 0.084 31.272 ;
    END
  END d[82]
  PIN d[83]
    DIRECTION INPUT ;
    USE SIGNAL ;
    PORT
      LAYER M4 ;
        RECT  0 31.344 0.084 31.368 ;
    END
  END d[83]
  PIN d[84]
    DIRECTION INPUT ;
    USE SIGNAL ;
    PORT
      LAYER M4 ;
        RECT  0 31.44 0.084 31.464 ;
    END
  END d[84]
  PIN d[85]
    DIRECTION INPUT ;
    USE SIGNAL ;
    PORT
      LAYER M4 ;
        RECT  0 31.536 0.084 31.56 ;
    END
  END d[85]
  PIN d[86]
    DIRECTION INPUT ;
    USE SIGNAL ;
    PORT
      LAYER M4 ;
        RECT  0 31.632 0.084 31.656 ;
    END
  END d[86]
  PIN d[87]
    DIRECTION INPUT ;
    USE SIGNAL ;
    PORT
      LAYER M4 ;
        RECT  0 31.728 0.084 31.752 ;
    END
  END d[87]
  PIN d[88]
    DIRECTION INPUT ;
    USE SIGNAL ;
    PORT
      LAYER M4 ;
        RECT  0 31.824 0.084 31.848 ;
    END
  END d[88]
  PIN d[89]
    DIRECTION INPUT ;
    USE SIGNAL ;
    PORT
      LAYER M4 ;
        RECT  0 31.92 0.084 31.944 ;
    END
  END d[89]
  PIN d[8]
    DIRECTION INPUT ;
    USE SIGNAL ;
    PORT
      LAYER M4 ;
        RECT  0 27.216 0.084 27.24 ;
    END
  END d[8]
  PIN d[90]
    DIRECTION INPUT ;
    USE SIGNAL ;
    PORT
      LAYER M4 ;
        RECT  0 32.016 0.084 32.04 ;
    END
  END d[90]
  PIN d[91]
    DIRECTION INPUT ;
    USE SIGNAL ;
    PORT
      LAYER M4 ;
        RECT  0 32.112 0.084 32.136 ;
    END
  END d[91]
  PIN d[92]
    DIRECTION INPUT ;
    USE SIGNAL ;
    PORT
      LAYER M4 ;
        RECT  0 32.208 0.084 32.232 ;
    END
  END d[92]
  PIN d[93]
    DIRECTION INPUT ;
    USE SIGNAL ;
    PORT
      LAYER M4 ;
        RECT  0 32.304 0.084 32.328 ;
    END
  END d[93]
  PIN d[94]
    DIRECTION INPUT ;
    USE SIGNAL ;
    PORT
      LAYER M4 ;
        RECT  0 32.4 0.084 32.424 ;
    END
  END d[94]
  PIN d[95]
    DIRECTION INPUT ;
    USE SIGNAL ;
    PORT
      LAYER M4 ;
        RECT  0 32.496 0.084 32.52 ;
    END
  END d[95]
  PIN d[96]
    DIRECTION INPUT ;
    USE SIGNAL ;
    PORT
      LAYER M4 ;
        RECT  0 38.736 0.084 38.76 ;
    END
  END d[96]
  PIN d[97]
    DIRECTION INPUT ;
    USE SIGNAL ;
    PORT
      LAYER M4 ;
        RECT  0 38.832 0.084 38.856 ;
    END
  END d[97]
  PIN d[98]
    DIRECTION INPUT ;
    USE SIGNAL ;
    PORT
      LAYER M4 ;
        RECT  0 38.928 0.084 38.952 ;
    END
  END d[98]
  PIN d[99]
    DIRECTION INPUT ;
    USE SIGNAL ;
    PORT
      LAYER M4 ;
        RECT  0 39.024 0.084 39.048 ;
    END
  END d[99]
  PIN d[9]
    DIRECTION INPUT ;
    USE SIGNAL ;
    PORT
      LAYER M4 ;
        RECT  0 27.312 0.084 27.336 ;
    END
  END d[9]
  PIN q[0]
    DIRECTION OUTPUT ;
    USE SIGNAL ;
    PORT
      LAYER M4 ;
        RECT  92.796 19.92 92.88 19.944 ;
    END
  END q[0]
  PIN q[100]
    DIRECTION OUTPUT ;
    USE SIGNAL ;
    PORT
      LAYER M4 ;
        RECT  92.796 35.664 92.88 35.688 ;
    END
  END q[100]
  PIN q[101]
    DIRECTION OUTPUT ;
    USE SIGNAL ;
    PORT
      LAYER M4 ;
        RECT  92.796 35.76 92.88 35.784 ;
    END
  END q[101]
  PIN q[102]
    DIRECTION OUTPUT ;
    USE SIGNAL ;
    PORT
      LAYER M4 ;
        RECT  92.796 35.856 92.88 35.88 ;
    END
  END q[102]
  PIN q[103]
    DIRECTION OUTPUT ;
    USE SIGNAL ;
    PORT
      LAYER M4 ;
        RECT  92.796 35.952 92.88 35.976 ;
    END
  END q[103]
  PIN q[104]
    DIRECTION OUTPUT ;
    USE SIGNAL ;
    PORT
      LAYER M4 ;
        RECT  92.796 36.048 92.88 36.072 ;
    END
  END q[104]
  PIN q[105]
    DIRECTION OUTPUT ;
    USE SIGNAL ;
    PORT
      LAYER M4 ;
        RECT  92.796 36.144 92.88 36.168 ;
    END
  END q[105]
  PIN q[106]
    DIRECTION OUTPUT ;
    USE SIGNAL ;
    PORT
      LAYER M4 ;
        RECT  92.796 36.24 92.88 36.264 ;
    END
  END q[106]
  PIN q[107]
    DIRECTION OUTPUT ;
    USE SIGNAL ;
    PORT
      LAYER M4 ;
        RECT  92.796 36.336 92.88 36.36 ;
    END
  END q[107]
  PIN q[108]
    DIRECTION OUTPUT ;
    USE SIGNAL ;
    PORT
      LAYER M4 ;
        RECT  92.796 36.432 92.88 36.456 ;
    END
  END q[108]
  PIN q[109]
    DIRECTION OUTPUT ;
    USE SIGNAL ;
    PORT
      LAYER M4 ;
        RECT  92.796 36.528 92.88 36.552 ;
    END
  END q[109]
  PIN q[10]
    DIRECTION OUTPUT ;
    USE SIGNAL ;
    PORT
      LAYER M4 ;
        RECT  92.796 20.88 92.88 20.904 ;
    END
  END q[10]
  PIN q[110]
    DIRECTION OUTPUT ;
    USE SIGNAL ;
    PORT
      LAYER M4 ;
        RECT  92.796 36.624 92.88 36.648 ;
    END
  END q[110]
  PIN q[111]
    DIRECTION OUTPUT ;
    USE SIGNAL ;
    PORT
      LAYER M4 ;
        RECT  92.796 36.72 92.88 36.744 ;
    END
  END q[111]
  PIN q[112]
    DIRECTION OUTPUT ;
    USE SIGNAL ;
    PORT
      LAYER M4 ;
        RECT  92.796 36.816 92.88 36.84 ;
    END
  END q[112]
  PIN q[113]
    DIRECTION OUTPUT ;
    USE SIGNAL ;
    PORT
      LAYER M4 ;
        RECT  92.796 36.912 92.88 36.936 ;
    END
  END q[113]
  PIN q[114]
    DIRECTION OUTPUT ;
    USE SIGNAL ;
    PORT
      LAYER M4 ;
        RECT  92.796 37.008 92.88 37.032 ;
    END
  END q[114]
  PIN q[115]
    DIRECTION OUTPUT ;
    USE SIGNAL ;
    PORT
      LAYER M4 ;
        RECT  92.796 37.104 92.88 37.128 ;
    END
  END q[115]
  PIN q[116]
    DIRECTION OUTPUT ;
    USE SIGNAL ;
    PORT
      LAYER M4 ;
        RECT  92.796 37.2 92.88 37.224 ;
    END
  END q[116]
  PIN q[117]
    DIRECTION OUTPUT ;
    USE SIGNAL ;
    PORT
      LAYER M4 ;
        RECT  92.796 37.296 92.88 37.32 ;
    END
  END q[117]
  PIN q[118]
    DIRECTION OUTPUT ;
    USE SIGNAL ;
    PORT
      LAYER M4 ;
        RECT  92.796 37.392 92.88 37.416 ;
    END
  END q[118]
  PIN q[119]
    DIRECTION OUTPUT ;
    USE SIGNAL ;
    PORT
      LAYER M4 ;
        RECT  92.796 37.488 92.88 37.512 ;
    END
  END q[119]
  PIN q[11]
    DIRECTION OUTPUT ;
    USE SIGNAL ;
    PORT
      LAYER M4 ;
        RECT  92.796 20.976 92.88 21 ;
    END
  END q[11]
  PIN q[120]
    DIRECTION OUTPUT ;
    USE SIGNAL ;
    PORT
      LAYER M4 ;
        RECT  92.796 37.584 92.88 37.608 ;
    END
  END q[120]
  PIN q[121]
    DIRECTION OUTPUT ;
    USE SIGNAL ;
    PORT
      LAYER M4 ;
        RECT  92.796 37.68 92.88 37.704 ;
    END
  END q[121]
  PIN q[122]
    DIRECTION OUTPUT ;
    USE SIGNAL ;
    PORT
      LAYER M4 ;
        RECT  92.796 37.776 92.88 37.8 ;
    END
  END q[122]
  PIN q[123]
    DIRECTION OUTPUT ;
    USE SIGNAL ;
    PORT
      LAYER M4 ;
        RECT  92.796 37.872 92.88 37.896 ;
    END
  END q[123]
  PIN q[124]
    DIRECTION OUTPUT ;
    USE SIGNAL ;
    PORT
      LAYER M4 ;
        RECT  92.796 37.968 92.88 37.992 ;
    END
  END q[124]
  PIN q[125]
    DIRECTION OUTPUT ;
    USE SIGNAL ;
    PORT
      LAYER M4 ;
        RECT  92.796 38.064 92.88 38.088 ;
    END
  END q[125]
  PIN q[126]
    DIRECTION OUTPUT ;
    USE SIGNAL ;
    PORT
      LAYER M4 ;
        RECT  92.796 38.16 92.88 38.184 ;
    END
  END q[126]
  PIN q[127]
    DIRECTION OUTPUT ;
    USE SIGNAL ;
    PORT
      LAYER M4 ;
        RECT  92.796 38.256 92.88 38.28 ;
    END
  END q[127]
  PIN q[128]
    DIRECTION OUTPUT ;
    USE SIGNAL ;
    PORT
      LAYER M4 ;
        RECT  92.796 32.208 92.88 32.232 ;
    END
  END q[128]
  PIN q[129]
    DIRECTION OUTPUT ;
    USE SIGNAL ;
    PORT
      LAYER M4 ;
        RECT  92.796 32.304 92.88 32.328 ;
    END
  END q[129]
  PIN q[12]
    DIRECTION OUTPUT ;
    USE SIGNAL ;
    PORT
      LAYER M4 ;
        RECT  92.796 21.072 92.88 21.096 ;
    END
  END q[12]
  PIN q[130]
    DIRECTION OUTPUT ;
    USE SIGNAL ;
    PORT
      LAYER M4 ;
        RECT  92.796 32.4 92.88 32.424 ;
    END
  END q[130]
  PIN q[131]
    DIRECTION OUTPUT ;
    USE SIGNAL ;
    PORT
      LAYER M4 ;
        RECT  92.796 32.496 92.88 32.52 ;
    END
  END q[131]
  PIN q[132]
    DIRECTION OUTPUT ;
    USE SIGNAL ;
    PORT
      LAYER M4 ;
        RECT  92.796 32.592 92.88 32.616 ;
    END
  END q[132]
  PIN q[133]
    DIRECTION OUTPUT ;
    USE SIGNAL ;
    PORT
      LAYER M4 ;
        RECT  92.796 32.688 92.88 32.712 ;
    END
  END q[133]
  PIN q[134]
    DIRECTION OUTPUT ;
    USE SIGNAL ;
    PORT
      LAYER M4 ;
        RECT  92.796 32.784 92.88 32.808 ;
    END
  END q[134]
  PIN q[135]
    DIRECTION OUTPUT ;
    USE SIGNAL ;
    PORT
      LAYER M4 ;
        RECT  92.796 32.88 92.88 32.904 ;
    END
  END q[135]
  PIN q[136]
    DIRECTION OUTPUT ;
    USE SIGNAL ;
    PORT
      LAYER M4 ;
        RECT  92.796 32.976 92.88 33 ;
    END
  END q[136]
  PIN q[137]
    DIRECTION OUTPUT ;
    USE SIGNAL ;
    PORT
      LAYER M4 ;
        RECT  92.796 33.072 92.88 33.096 ;
    END
  END q[137]
  PIN q[138]
    DIRECTION OUTPUT ;
    USE SIGNAL ;
    PORT
      LAYER M4 ;
        RECT  92.796 33.168 92.88 33.192 ;
    END
  END q[138]
  PIN q[139]
    DIRECTION OUTPUT ;
    USE SIGNAL ;
    PORT
      LAYER M4 ;
        RECT  92.796 33.264 92.88 33.288 ;
    END
  END q[139]
  PIN q[13]
    DIRECTION OUTPUT ;
    USE SIGNAL ;
    PORT
      LAYER M4 ;
        RECT  92.796 21.168 92.88 21.192 ;
    END
  END q[13]
  PIN q[140]
    DIRECTION OUTPUT ;
    USE SIGNAL ;
    PORT
      LAYER M4 ;
        RECT  92.796 33.36 92.88 33.384 ;
    END
  END q[140]
  PIN q[141]
    DIRECTION OUTPUT ;
    USE SIGNAL ;
    PORT
      LAYER M4 ;
        RECT  92.796 33.456 92.88 33.48 ;
    END
  END q[141]
  PIN q[142]
    DIRECTION OUTPUT ;
    USE SIGNAL ;
    PORT
      LAYER M4 ;
        RECT  92.796 33.552 92.88 33.576 ;
    END
  END q[142]
  PIN q[143]
    DIRECTION OUTPUT ;
    USE SIGNAL ;
    PORT
      LAYER M4 ;
        RECT  92.796 33.648 92.88 33.672 ;
    END
  END q[143]
  PIN q[144]
    DIRECTION OUTPUT ;
    USE SIGNAL ;
    PORT
      LAYER M4 ;
        RECT  92.796 33.744 92.88 33.768 ;
    END
  END q[144]
  PIN q[145]
    DIRECTION OUTPUT ;
    USE SIGNAL ;
    PORT
      LAYER M4 ;
        RECT  92.796 33.84 92.88 33.864 ;
    END
  END q[145]
  PIN q[146]
    DIRECTION OUTPUT ;
    USE SIGNAL ;
    PORT
      LAYER M4 ;
        RECT  92.796 33.936 92.88 33.96 ;
    END
  END q[146]
  PIN q[147]
    DIRECTION OUTPUT ;
    USE SIGNAL ;
    PORT
      LAYER M4 ;
        RECT  92.796 34.032 92.88 34.056 ;
    END
  END q[147]
  PIN q[148]
    DIRECTION OUTPUT ;
    USE SIGNAL ;
    PORT
      LAYER M4 ;
        RECT  92.796 34.128 92.88 34.152 ;
    END
  END q[148]
  PIN q[149]
    DIRECTION OUTPUT ;
    USE SIGNAL ;
    PORT
      LAYER M4 ;
        RECT  92.796 34.224 92.88 34.248 ;
    END
  END q[149]
  PIN q[14]
    DIRECTION OUTPUT ;
    USE SIGNAL ;
    PORT
      LAYER M4 ;
        RECT  92.796 21.264 92.88 21.288 ;
    END
  END q[14]
  PIN q[150]
    DIRECTION OUTPUT ;
    USE SIGNAL ;
    PORT
      LAYER M4 ;
        RECT  92.796 34.32 92.88 34.344 ;
    END
  END q[150]
  PIN q[151]
    DIRECTION OUTPUT ;
    USE SIGNAL ;
    PORT
      LAYER M4 ;
        RECT  92.796 34.416 92.88 34.44 ;
    END
  END q[151]
  PIN q[152]
    DIRECTION OUTPUT ;
    USE SIGNAL ;
    PORT
      LAYER M4 ;
        RECT  92.796 34.512 92.88 34.536 ;
    END
  END q[152]
  PIN q[153]
    DIRECTION OUTPUT ;
    USE SIGNAL ;
    PORT
      LAYER M4 ;
        RECT  92.796 34.608 92.88 34.632 ;
    END
  END q[153]
  PIN q[154]
    DIRECTION OUTPUT ;
    USE SIGNAL ;
    PORT
      LAYER M4 ;
        RECT  92.796 34.704 92.88 34.728 ;
    END
  END q[154]
  PIN q[155]
    DIRECTION OUTPUT ;
    USE SIGNAL ;
    PORT
      LAYER M4 ;
        RECT  92.796 34.8 92.88 34.824 ;
    END
  END q[155]
  PIN q[156]
    DIRECTION OUTPUT ;
    USE SIGNAL ;
    PORT
      LAYER M4 ;
        RECT  92.796 34.896 92.88 34.92 ;
    END
  END q[156]
  PIN q[157]
    DIRECTION OUTPUT ;
    USE SIGNAL ;
    PORT
      LAYER M4 ;
        RECT  92.796 34.992 92.88 35.016 ;
    END
  END q[157]
  PIN q[158]
    DIRECTION OUTPUT ;
    USE SIGNAL ;
    PORT
      LAYER M4 ;
        RECT  92.796 35.088 92.88 35.112 ;
    END
  END q[158]
  PIN q[159]
    DIRECTION OUTPUT ;
    USE SIGNAL ;
    PORT
      LAYER M4 ;
        RECT  92.796 35.184 92.88 35.208 ;
    END
  END q[159]
  PIN q[15]
    DIRECTION OUTPUT ;
    USE SIGNAL ;
    PORT
      LAYER M4 ;
        RECT  92.796 21.36 92.88 21.384 ;
    END
  END q[15]
  PIN q[160]
    DIRECTION OUTPUT ;
    USE SIGNAL ;
    PORT
      LAYER M4 ;
        RECT  92.796 29.136 92.88 29.16 ;
    END
  END q[160]
  PIN q[161]
    DIRECTION OUTPUT ;
    USE SIGNAL ;
    PORT
      LAYER M4 ;
        RECT  92.796 29.232 92.88 29.256 ;
    END
  END q[161]
  PIN q[162]
    DIRECTION OUTPUT ;
    USE SIGNAL ;
    PORT
      LAYER M4 ;
        RECT  92.796 29.328 92.88 29.352 ;
    END
  END q[162]
  PIN q[163]
    DIRECTION OUTPUT ;
    USE SIGNAL ;
    PORT
      LAYER M4 ;
        RECT  92.796 29.424 92.88 29.448 ;
    END
  END q[163]
  PIN q[164]
    DIRECTION OUTPUT ;
    USE SIGNAL ;
    PORT
      LAYER M4 ;
        RECT  92.796 29.52 92.88 29.544 ;
    END
  END q[164]
  PIN q[165]
    DIRECTION OUTPUT ;
    USE SIGNAL ;
    PORT
      LAYER M4 ;
        RECT  92.796 29.616 92.88 29.64 ;
    END
  END q[165]
  PIN q[166]
    DIRECTION OUTPUT ;
    USE SIGNAL ;
    PORT
      LAYER M4 ;
        RECT  92.796 29.712 92.88 29.736 ;
    END
  END q[166]
  PIN q[167]
    DIRECTION OUTPUT ;
    USE SIGNAL ;
    PORT
      LAYER M4 ;
        RECT  92.796 29.808 92.88 29.832 ;
    END
  END q[167]
  PIN q[168]
    DIRECTION OUTPUT ;
    USE SIGNAL ;
    PORT
      LAYER M4 ;
        RECT  92.796 29.904 92.88 29.928 ;
    END
  END q[168]
  PIN q[169]
    DIRECTION OUTPUT ;
    USE SIGNAL ;
    PORT
      LAYER M4 ;
        RECT  92.796 30 92.88 30.024 ;
    END
  END q[169]
  PIN q[16]
    DIRECTION OUTPUT ;
    USE SIGNAL ;
    PORT
      LAYER M4 ;
        RECT  92.796 21.456 92.88 21.48 ;
    END
  END q[16]
  PIN q[170]
    DIRECTION OUTPUT ;
    USE SIGNAL ;
    PORT
      LAYER M4 ;
        RECT  92.796 30.096 92.88 30.12 ;
    END
  END q[170]
  PIN q[171]
    DIRECTION OUTPUT ;
    USE SIGNAL ;
    PORT
      LAYER M4 ;
        RECT  92.796 30.192 92.88 30.216 ;
    END
  END q[171]
  PIN q[172]
    DIRECTION OUTPUT ;
    USE SIGNAL ;
    PORT
      LAYER M4 ;
        RECT  92.796 30.288 92.88 30.312 ;
    END
  END q[172]
  PIN q[173]
    DIRECTION OUTPUT ;
    USE SIGNAL ;
    PORT
      LAYER M4 ;
        RECT  92.796 30.384 92.88 30.408 ;
    END
  END q[173]
  PIN q[174]
    DIRECTION OUTPUT ;
    USE SIGNAL ;
    PORT
      LAYER M4 ;
        RECT  92.796 30.48 92.88 30.504 ;
    END
  END q[174]
  PIN q[175]
    DIRECTION OUTPUT ;
    USE SIGNAL ;
    PORT
      LAYER M4 ;
        RECT  92.796 30.576 92.88 30.6 ;
    END
  END q[175]
  PIN q[176]
    DIRECTION OUTPUT ;
    USE SIGNAL ;
    PORT
      LAYER M4 ;
        RECT  92.796 30.672 92.88 30.696 ;
    END
  END q[176]
  PIN q[177]
    DIRECTION OUTPUT ;
    USE SIGNAL ;
    PORT
      LAYER M4 ;
        RECT  92.796 30.768 92.88 30.792 ;
    END
  END q[177]
  PIN q[178]
    DIRECTION OUTPUT ;
    USE SIGNAL ;
    PORT
      LAYER M4 ;
        RECT  92.796 30.864 92.88 30.888 ;
    END
  END q[178]
  PIN q[179]
    DIRECTION OUTPUT ;
    USE SIGNAL ;
    PORT
      LAYER M4 ;
        RECT  92.796 30.96 92.88 30.984 ;
    END
  END q[179]
  PIN q[17]
    DIRECTION OUTPUT ;
    USE SIGNAL ;
    PORT
      LAYER M4 ;
        RECT  92.796 21.552 92.88 21.576 ;
    END
  END q[17]
  PIN q[180]
    DIRECTION OUTPUT ;
    USE SIGNAL ;
    PORT
      LAYER M4 ;
        RECT  92.796 31.056 92.88 31.08 ;
    END
  END q[180]
  PIN q[181]
    DIRECTION OUTPUT ;
    USE SIGNAL ;
    PORT
      LAYER M4 ;
        RECT  92.796 31.152 92.88 31.176 ;
    END
  END q[181]
  PIN q[182]
    DIRECTION OUTPUT ;
    USE SIGNAL ;
    PORT
      LAYER M4 ;
        RECT  92.796 31.248 92.88 31.272 ;
    END
  END q[182]
  PIN q[183]
    DIRECTION OUTPUT ;
    USE SIGNAL ;
    PORT
      LAYER M4 ;
        RECT  92.796 31.344 92.88 31.368 ;
    END
  END q[183]
  PIN q[184]
    DIRECTION OUTPUT ;
    USE SIGNAL ;
    PORT
      LAYER M4 ;
        RECT  92.796 31.44 92.88 31.464 ;
    END
  END q[184]
  PIN q[185]
    DIRECTION OUTPUT ;
    USE SIGNAL ;
    PORT
      LAYER M4 ;
        RECT  92.796 31.536 92.88 31.56 ;
    END
  END q[185]
  PIN q[186]
    DIRECTION OUTPUT ;
    USE SIGNAL ;
    PORT
      LAYER M4 ;
        RECT  92.796 31.632 92.88 31.656 ;
    END
  END q[186]
  PIN q[187]
    DIRECTION OUTPUT ;
    USE SIGNAL ;
    PORT
      LAYER M4 ;
        RECT  92.796 31.728 92.88 31.752 ;
    END
  END q[187]
  PIN q[188]
    DIRECTION OUTPUT ;
    USE SIGNAL ;
    PORT
      LAYER M4 ;
        RECT  92.796 31.824 92.88 31.848 ;
    END
  END q[188]
  PIN q[189]
    DIRECTION OUTPUT ;
    USE SIGNAL ;
    PORT
      LAYER M4 ;
        RECT  92.796 31.92 92.88 31.944 ;
    END
  END q[189]
  PIN q[18]
    DIRECTION OUTPUT ;
    USE SIGNAL ;
    PORT
      LAYER M4 ;
        RECT  92.796 21.648 92.88 21.672 ;
    END
  END q[18]
  PIN q[190]
    DIRECTION OUTPUT ;
    USE SIGNAL ;
    PORT
      LAYER M4 ;
        RECT  92.796 32.016 92.88 32.04 ;
    END
  END q[190]
  PIN q[191]
    DIRECTION OUTPUT ;
    USE SIGNAL ;
    PORT
      LAYER M4 ;
        RECT  92.796 32.112 92.88 32.136 ;
    END
  END q[191]
  PIN q[192]
    DIRECTION OUTPUT ;
    USE SIGNAL ;
    PORT
      LAYER M4 ;
        RECT  92.796 45.264 92.88 45.288 ;
    END
  END q[192]
  PIN q[193]
    DIRECTION OUTPUT ;
    USE SIGNAL ;
    PORT
      LAYER M4 ;
        RECT  92.796 45.36 92.88 45.384 ;
    END
  END q[193]
  PIN q[194]
    DIRECTION OUTPUT ;
    USE SIGNAL ;
    PORT
      LAYER M4 ;
        RECT  92.796 45.456 92.88 45.48 ;
    END
  END q[194]
  PIN q[195]
    DIRECTION OUTPUT ;
    USE SIGNAL ;
    PORT
      LAYER M4 ;
        RECT  92.796 45.552 92.88 45.576 ;
    END
  END q[195]
  PIN q[196]
    DIRECTION OUTPUT ;
    USE SIGNAL ;
    PORT
      LAYER M4 ;
        RECT  92.796 45.648 92.88 45.672 ;
    END
  END q[196]
  PIN q[197]
    DIRECTION OUTPUT ;
    USE SIGNAL ;
    PORT
      LAYER M4 ;
        RECT  92.796 45.744 92.88 45.768 ;
    END
  END q[197]
  PIN q[198]
    DIRECTION OUTPUT ;
    USE SIGNAL ;
    PORT
      LAYER M4 ;
        RECT  92.796 45.84 92.88 45.864 ;
    END
  END q[198]
  PIN q[199]
    DIRECTION OUTPUT ;
    USE SIGNAL ;
    PORT
      LAYER M4 ;
        RECT  92.796 45.936 92.88 45.96 ;
    END
  END q[199]
  PIN q[19]
    DIRECTION OUTPUT ;
    USE SIGNAL ;
    PORT
      LAYER M4 ;
        RECT  92.796 21.744 92.88 21.768 ;
    END
  END q[19]
  PIN q[1]
    DIRECTION OUTPUT ;
    USE SIGNAL ;
    PORT
      LAYER M4 ;
        RECT  92.796 20.016 92.88 20.04 ;
    END
  END q[1]
  PIN q[200]
    DIRECTION OUTPUT ;
    USE SIGNAL ;
    PORT
      LAYER M4 ;
        RECT  92.796 46.032 92.88 46.056 ;
    END
  END q[200]
  PIN q[201]
    DIRECTION OUTPUT ;
    USE SIGNAL ;
    PORT
      LAYER M4 ;
        RECT  92.796 46.128 92.88 46.152 ;
    END
  END q[201]
  PIN q[202]
    DIRECTION OUTPUT ;
    USE SIGNAL ;
    PORT
      LAYER M4 ;
        RECT  92.796 46.224 92.88 46.248 ;
    END
  END q[202]
  PIN q[203]
    DIRECTION OUTPUT ;
    USE SIGNAL ;
    PORT
      LAYER M4 ;
        RECT  92.796 46.32 92.88 46.344 ;
    END
  END q[203]
  PIN q[204]
    DIRECTION OUTPUT ;
    USE SIGNAL ;
    PORT
      LAYER M4 ;
        RECT  92.796 46.416 92.88 46.44 ;
    END
  END q[204]
  PIN q[205]
    DIRECTION OUTPUT ;
    USE SIGNAL ;
    PORT
      LAYER M4 ;
        RECT  92.796 46.512 92.88 46.536 ;
    END
  END q[205]
  PIN q[206]
    DIRECTION OUTPUT ;
    USE SIGNAL ;
    PORT
      LAYER M4 ;
        RECT  92.796 46.608 92.88 46.632 ;
    END
  END q[206]
  PIN q[207]
    DIRECTION OUTPUT ;
    USE SIGNAL ;
    PORT
      LAYER M4 ;
        RECT  92.796 46.704 92.88 46.728 ;
    END
  END q[207]
  PIN q[208]
    DIRECTION OUTPUT ;
    USE SIGNAL ;
    PORT
      LAYER M4 ;
        RECT  92.796 46.8 92.88 46.824 ;
    END
  END q[208]
  PIN q[209]
    DIRECTION OUTPUT ;
    USE SIGNAL ;
    PORT
      LAYER M4 ;
        RECT  92.796 46.896 92.88 46.92 ;
    END
  END q[209]
  PIN q[20]
    DIRECTION OUTPUT ;
    USE SIGNAL ;
    PORT
      LAYER M4 ;
        RECT  92.796 21.84 92.88 21.864 ;
    END
  END q[20]
  PIN q[210]
    DIRECTION OUTPUT ;
    USE SIGNAL ;
    PORT
      LAYER M4 ;
        RECT  92.796 46.992 92.88 47.016 ;
    END
  END q[210]
  PIN q[211]
    DIRECTION OUTPUT ;
    USE SIGNAL ;
    PORT
      LAYER M4 ;
        RECT  92.796 47.088 92.88 47.112 ;
    END
  END q[211]
  PIN q[212]
    DIRECTION OUTPUT ;
    USE SIGNAL ;
    PORT
      LAYER M4 ;
        RECT  92.796 47.184 92.88 47.208 ;
    END
  END q[212]
  PIN q[213]
    DIRECTION OUTPUT ;
    USE SIGNAL ;
    PORT
      LAYER M4 ;
        RECT  92.796 47.28 92.88 47.304 ;
    END
  END q[213]
  PIN q[214]
    DIRECTION OUTPUT ;
    USE SIGNAL ;
    PORT
      LAYER M4 ;
        RECT  92.796 47.376 92.88 47.4 ;
    END
  END q[214]
  PIN q[215]
    DIRECTION OUTPUT ;
    USE SIGNAL ;
    PORT
      LAYER M4 ;
        RECT  92.796 47.472 92.88 47.496 ;
    END
  END q[215]
  PIN q[216]
    DIRECTION OUTPUT ;
    USE SIGNAL ;
    PORT
      LAYER M4 ;
        RECT  92.796 47.568 92.88 47.592 ;
    END
  END q[216]
  PIN q[217]
    DIRECTION OUTPUT ;
    USE SIGNAL ;
    PORT
      LAYER M4 ;
        RECT  92.796 47.664 92.88 47.688 ;
    END
  END q[217]
  PIN q[218]
    DIRECTION OUTPUT ;
    USE SIGNAL ;
    PORT
      LAYER M4 ;
        RECT  92.796 47.76 92.88 47.784 ;
    END
  END q[218]
  PIN q[219]
    DIRECTION OUTPUT ;
    USE SIGNAL ;
    PORT
      LAYER M4 ;
        RECT  92.796 47.856 92.88 47.88 ;
    END
  END q[219]
  PIN q[21]
    DIRECTION OUTPUT ;
    USE SIGNAL ;
    PORT
      LAYER M4 ;
        RECT  92.796 21.936 92.88 21.96 ;
    END
  END q[21]
  PIN q[220]
    DIRECTION OUTPUT ;
    USE SIGNAL ;
    PORT
      LAYER M4 ;
        RECT  92.796 47.952 92.88 47.976 ;
    END
  END q[220]
  PIN q[221]
    DIRECTION OUTPUT ;
    USE SIGNAL ;
    PORT
      LAYER M4 ;
        RECT  92.796 48.048 92.88 48.072 ;
    END
  END q[221]
  PIN q[222]
    DIRECTION OUTPUT ;
    USE SIGNAL ;
    PORT
      LAYER M4 ;
        RECT  92.796 48.144 92.88 48.168 ;
    END
  END q[222]
  PIN q[223]
    DIRECTION OUTPUT ;
    USE SIGNAL ;
    PORT
      LAYER M4 ;
        RECT  92.796 48.24 92.88 48.264 ;
    END
  END q[223]
  PIN q[224]
    DIRECTION OUTPUT ;
    USE SIGNAL ;
    PORT
      LAYER M4 ;
        RECT  92.796 13.008 92.88 13.032 ;
    END
  END q[224]
  PIN q[225]
    DIRECTION OUTPUT ;
    USE SIGNAL ;
    PORT
      LAYER M4 ;
        RECT  92.796 13.104 92.88 13.128 ;
    END
  END q[225]
  PIN q[226]
    DIRECTION OUTPUT ;
    USE SIGNAL ;
    PORT
      LAYER M4 ;
        RECT  92.796 13.2 92.88 13.224 ;
    END
  END q[226]
  PIN q[227]
    DIRECTION OUTPUT ;
    USE SIGNAL ;
    PORT
      LAYER M4 ;
        RECT  92.796 13.296 92.88 13.32 ;
    END
  END q[227]
  PIN q[228]
    DIRECTION OUTPUT ;
    USE SIGNAL ;
    PORT
      LAYER M4 ;
        RECT  92.796 13.392 92.88 13.416 ;
    END
  END q[228]
  PIN q[229]
    DIRECTION OUTPUT ;
    USE SIGNAL ;
    PORT
      LAYER M4 ;
        RECT  92.796 13.488 92.88 13.512 ;
    END
  END q[229]
  PIN q[22]
    DIRECTION OUTPUT ;
    USE SIGNAL ;
    PORT
      LAYER M4 ;
        RECT  92.796 22.032 92.88 22.056 ;
    END
  END q[22]
  PIN q[230]
    DIRECTION OUTPUT ;
    USE SIGNAL ;
    PORT
      LAYER M4 ;
        RECT  92.796 13.584 92.88 13.608 ;
    END
  END q[230]
  PIN q[231]
    DIRECTION OUTPUT ;
    USE SIGNAL ;
    PORT
      LAYER M4 ;
        RECT  92.796 13.68 92.88 13.704 ;
    END
  END q[231]
  PIN q[232]
    DIRECTION OUTPUT ;
    USE SIGNAL ;
    PORT
      LAYER M4 ;
        RECT  92.796 13.776 92.88 13.8 ;
    END
  END q[232]
  PIN q[233]
    DIRECTION OUTPUT ;
    USE SIGNAL ;
    PORT
      LAYER M4 ;
        RECT  92.796 13.872 92.88 13.896 ;
    END
  END q[233]
  PIN q[234]
    DIRECTION OUTPUT ;
    USE SIGNAL ;
    PORT
      LAYER M4 ;
        RECT  92.796 13.968 92.88 13.992 ;
    END
  END q[234]
  PIN q[235]
    DIRECTION OUTPUT ;
    USE SIGNAL ;
    PORT
      LAYER M4 ;
        RECT  92.796 14.064 92.88 14.088 ;
    END
  END q[235]
  PIN q[236]
    DIRECTION OUTPUT ;
    USE SIGNAL ;
    PORT
      LAYER M4 ;
        RECT  92.796 14.16 92.88 14.184 ;
    END
  END q[236]
  PIN q[237]
    DIRECTION OUTPUT ;
    USE SIGNAL ;
    PORT
      LAYER M4 ;
        RECT  92.796 14.256 92.88 14.28 ;
    END
  END q[237]
  PIN q[238]
    DIRECTION OUTPUT ;
    USE SIGNAL ;
    PORT
      LAYER M4 ;
        RECT  92.796 14.352 92.88 14.376 ;
    END
  END q[238]
  PIN q[239]
    DIRECTION OUTPUT ;
    USE SIGNAL ;
    PORT
      LAYER M4 ;
        RECT  92.796 14.448 92.88 14.472 ;
    END
  END q[239]
  PIN q[23]
    DIRECTION OUTPUT ;
    USE SIGNAL ;
    PORT
      LAYER M4 ;
        RECT  92.796 22.128 92.88 22.152 ;
    END
  END q[23]
  PIN q[240]
    DIRECTION OUTPUT ;
    USE SIGNAL ;
    PORT
      LAYER M4 ;
        RECT  92.796 14.544 92.88 14.568 ;
    END
  END q[240]
  PIN q[241]
    DIRECTION OUTPUT ;
    USE SIGNAL ;
    PORT
      LAYER M4 ;
        RECT  92.796 14.64 92.88 14.664 ;
    END
  END q[241]
  PIN q[242]
    DIRECTION OUTPUT ;
    USE SIGNAL ;
    PORT
      LAYER M4 ;
        RECT  92.796 14.736 92.88 14.76 ;
    END
  END q[242]
  PIN q[243]
    DIRECTION OUTPUT ;
    USE SIGNAL ;
    PORT
      LAYER M4 ;
        RECT  92.796 14.832 92.88 14.856 ;
    END
  END q[243]
  PIN q[244]
    DIRECTION OUTPUT ;
    USE SIGNAL ;
    PORT
      LAYER M4 ;
        RECT  92.796 14.928 92.88 14.952 ;
    END
  END q[244]
  PIN q[245]
    DIRECTION OUTPUT ;
    USE SIGNAL ;
    PORT
      LAYER M4 ;
        RECT  92.796 15.024 92.88 15.048 ;
    END
  END q[245]
  PIN q[246]
    DIRECTION OUTPUT ;
    USE SIGNAL ;
    PORT
      LAYER M4 ;
        RECT  92.796 15.12 92.88 15.144 ;
    END
  END q[246]
  PIN q[247]
    DIRECTION OUTPUT ;
    USE SIGNAL ;
    PORT
      LAYER M4 ;
        RECT  92.796 15.216 92.88 15.24 ;
    END
  END q[247]
  PIN q[248]
    DIRECTION OUTPUT ;
    USE SIGNAL ;
    PORT
      LAYER M4 ;
        RECT  92.796 15.312 92.88 15.336 ;
    END
  END q[248]
  PIN q[249]
    DIRECTION OUTPUT ;
    USE SIGNAL ;
    PORT
      LAYER M4 ;
        RECT  92.796 15.408 92.88 15.432 ;
    END
  END q[249]
  PIN q[24]
    DIRECTION OUTPUT ;
    USE SIGNAL ;
    PORT
      LAYER M4 ;
        RECT  92.796 22.224 92.88 22.248 ;
    END
  END q[24]
  PIN q[250]
    DIRECTION OUTPUT ;
    USE SIGNAL ;
    PORT
      LAYER M4 ;
        RECT  92.796 15.504 92.88 15.528 ;
    END
  END q[250]
  PIN q[251]
    DIRECTION OUTPUT ;
    USE SIGNAL ;
    PORT
      LAYER M4 ;
        RECT  92.796 15.6 92.88 15.624 ;
    END
  END q[251]
  PIN q[252]
    DIRECTION OUTPUT ;
    USE SIGNAL ;
    PORT
      LAYER M4 ;
        RECT  92.796 15.696 92.88 15.72 ;
    END
  END q[252]
  PIN q[253]
    DIRECTION OUTPUT ;
    USE SIGNAL ;
    PORT
      LAYER M4 ;
        RECT  92.796 15.792 92.88 15.816 ;
    END
  END q[253]
  PIN q[254]
    DIRECTION OUTPUT ;
    USE SIGNAL ;
    PORT
      LAYER M4 ;
        RECT  92.796 15.888 92.88 15.912 ;
    END
  END q[254]
  PIN q[255]
    DIRECTION OUTPUT ;
    USE SIGNAL ;
    PORT
      LAYER M4 ;
        RECT  92.796 15.984 92.88 16.008 ;
    END
  END q[255]
  PIN q[256]
    DIRECTION OUTPUT ;
    USE SIGNAL ;
    PORT
      LAYER M4 ;
        RECT  92.796 48.336 92.88 48.36 ;
    END
  END q[256]
  PIN q[257]
    DIRECTION OUTPUT ;
    USE SIGNAL ;
    PORT
      LAYER M4 ;
        RECT  92.796 48.432 92.88 48.456 ;
    END
  END q[257]
  PIN q[258]
    DIRECTION OUTPUT ;
    USE SIGNAL ;
    PORT
      LAYER M4 ;
        RECT  92.796 48.528 92.88 48.552 ;
    END
  END q[258]
  PIN q[259]
    DIRECTION OUTPUT ;
    USE SIGNAL ;
    PORT
      LAYER M4 ;
        RECT  92.796 48.624 92.88 48.648 ;
    END
  END q[259]
  PIN q[25]
    DIRECTION OUTPUT ;
    USE SIGNAL ;
    PORT
      LAYER M4 ;
        RECT  92.796 22.32 92.88 22.344 ;
    END
  END q[25]
  PIN q[260]
    DIRECTION OUTPUT ;
    USE SIGNAL ;
    PORT
      LAYER M4 ;
        RECT  92.796 48.72 92.88 48.744 ;
    END
  END q[260]
  PIN q[261]
    DIRECTION OUTPUT ;
    USE SIGNAL ;
    PORT
      LAYER M4 ;
        RECT  92.796 48.816 92.88 48.84 ;
    END
  END q[261]
  PIN q[262]
    DIRECTION OUTPUT ;
    USE SIGNAL ;
    PORT
      LAYER M4 ;
        RECT  92.796 48.912 92.88 48.936 ;
    END
  END q[262]
  PIN q[263]
    DIRECTION OUTPUT ;
    USE SIGNAL ;
    PORT
      LAYER M4 ;
        RECT  92.796 49.008 92.88 49.032 ;
    END
  END q[263]
  PIN q[264]
    DIRECTION OUTPUT ;
    USE SIGNAL ;
    PORT
      LAYER M4 ;
        RECT  92.796 49.104 92.88 49.128 ;
    END
  END q[264]
  PIN q[265]
    DIRECTION OUTPUT ;
    USE SIGNAL ;
    PORT
      LAYER M4 ;
        RECT  92.796 49.2 92.88 49.224 ;
    END
  END q[265]
  PIN q[266]
    DIRECTION OUTPUT ;
    USE SIGNAL ;
    PORT
      LAYER M4 ;
        RECT  92.796 49.296 92.88 49.32 ;
    END
  END q[266]
  PIN q[267]
    DIRECTION OUTPUT ;
    USE SIGNAL ;
    PORT
      LAYER M4 ;
        RECT  92.796 49.392 92.88 49.416 ;
    END
  END q[267]
  PIN q[268]
    DIRECTION OUTPUT ;
    USE SIGNAL ;
    PORT
      LAYER M4 ;
        RECT  92.796 49.488 92.88 49.512 ;
    END
  END q[268]
  PIN q[269]
    DIRECTION OUTPUT ;
    USE SIGNAL ;
    PORT
      LAYER M4 ;
        RECT  92.796 49.584 92.88 49.608 ;
    END
  END q[269]
  PIN q[26]
    DIRECTION OUTPUT ;
    USE SIGNAL ;
    PORT
      LAYER M4 ;
        RECT  92.796 22.416 92.88 22.44 ;
    END
  END q[26]
  PIN q[270]
    DIRECTION OUTPUT ;
    USE SIGNAL ;
    PORT
      LAYER M4 ;
        RECT  92.796 49.68 92.88 49.704 ;
    END
  END q[270]
  PIN q[271]
    DIRECTION OUTPUT ;
    USE SIGNAL ;
    PORT
      LAYER M4 ;
        RECT  92.796 49.776 92.88 49.8 ;
    END
  END q[271]
  PIN q[272]
    DIRECTION OUTPUT ;
    USE SIGNAL ;
    PORT
      LAYER M4 ;
        RECT  92.796 49.872 92.88 49.896 ;
    END
  END q[272]
  PIN q[273]
    DIRECTION OUTPUT ;
    USE SIGNAL ;
    PORT
      LAYER M4 ;
        RECT  92.796 49.968 92.88 49.992 ;
    END
  END q[273]
  PIN q[274]
    DIRECTION OUTPUT ;
    USE SIGNAL ;
    PORT
      LAYER M4 ;
        RECT  92.796 50.064 92.88 50.088 ;
    END
  END q[274]
  PIN q[275]
    DIRECTION OUTPUT ;
    USE SIGNAL ;
    PORT
      LAYER M4 ;
        RECT  92.796 50.16 92.88 50.184 ;
    END
  END q[275]
  PIN q[276]
    DIRECTION OUTPUT ;
    USE SIGNAL ;
    PORT
      LAYER M4 ;
        RECT  92.796 50.256 92.88 50.28 ;
    END
  END q[276]
  PIN q[277]
    DIRECTION OUTPUT ;
    USE SIGNAL ;
    PORT
      LAYER M4 ;
        RECT  92.796 50.352 92.88 50.376 ;
    END
  END q[277]
  PIN q[278]
    DIRECTION OUTPUT ;
    USE SIGNAL ;
    PORT
      LAYER M4 ;
        RECT  92.796 50.448 92.88 50.472 ;
    END
  END q[278]
  PIN q[279]
    DIRECTION OUTPUT ;
    USE SIGNAL ;
    PORT
      LAYER M4 ;
        RECT  92.796 50.544 92.88 50.568 ;
    END
  END q[279]
  PIN q[27]
    DIRECTION OUTPUT ;
    USE SIGNAL ;
    PORT
      LAYER M4 ;
        RECT  92.796 22.512 92.88 22.536 ;
    END
  END q[27]
  PIN q[280]
    DIRECTION OUTPUT ;
    USE SIGNAL ;
    PORT
      LAYER M4 ;
        RECT  92.796 50.64 92.88 50.664 ;
    END
  END q[280]
  PIN q[281]
    DIRECTION OUTPUT ;
    USE SIGNAL ;
    PORT
      LAYER M4 ;
        RECT  92.796 50.736 92.88 50.76 ;
    END
  END q[281]
  PIN q[282]
    DIRECTION OUTPUT ;
    USE SIGNAL ;
    PORT
      LAYER M4 ;
        RECT  92.796 50.832 92.88 50.856 ;
    END
  END q[282]
  PIN q[283]
    DIRECTION OUTPUT ;
    USE SIGNAL ;
    PORT
      LAYER M4 ;
        RECT  92.796 50.928 92.88 50.952 ;
    END
  END q[283]
  PIN q[284]
    DIRECTION OUTPUT ;
    USE SIGNAL ;
    PORT
      LAYER M4 ;
        RECT  92.796 51.024 92.88 51.048 ;
    END
  END q[284]
  PIN q[285]
    DIRECTION OUTPUT ;
    USE SIGNAL ;
    PORT
      LAYER M4 ;
        RECT  92.796 51.12 92.88 51.144 ;
    END
  END q[285]
  PIN q[286]
    DIRECTION OUTPUT ;
    USE SIGNAL ;
    PORT
      LAYER M4 ;
        RECT  92.796 51.216 92.88 51.24 ;
    END
  END q[286]
  PIN q[287]
    DIRECTION OUTPUT ;
    USE SIGNAL ;
    PORT
      LAYER M4 ;
        RECT  92.796 51.312 92.88 51.336 ;
    END
  END q[287]
  PIN q[288]
    DIRECTION OUTPUT ;
    USE SIGNAL ;
    PORT
      LAYER M4 ;
        RECT  92.796 51.408 92.88 51.432 ;
    END
  END q[288]
  PIN q[289]
    DIRECTION OUTPUT ;
    USE SIGNAL ;
    PORT
      LAYER M4 ;
        RECT  92.796 51.504 92.88 51.528 ;
    END
  END q[289]
  PIN q[28]
    DIRECTION OUTPUT ;
    USE SIGNAL ;
    PORT
      LAYER M4 ;
        RECT  92.796 22.608 92.88 22.632 ;
    END
  END q[28]
  PIN q[290]
    DIRECTION OUTPUT ;
    USE SIGNAL ;
    PORT
      LAYER M4 ;
        RECT  92.796 51.6 92.88 51.624 ;
    END
  END q[290]
  PIN q[291]
    DIRECTION OUTPUT ;
    USE SIGNAL ;
    PORT
      LAYER M4 ;
        RECT  92.796 51.696 92.88 51.72 ;
    END
  END q[291]
  PIN q[292]
    DIRECTION OUTPUT ;
    USE SIGNAL ;
    PORT
      LAYER M4 ;
        RECT  92.796 51.792 92.88 51.816 ;
    END
  END q[292]
  PIN q[293]
    DIRECTION OUTPUT ;
    USE SIGNAL ;
    PORT
      LAYER M4 ;
        RECT  92.796 51.888 92.88 51.912 ;
    END
  END q[293]
  PIN q[294]
    DIRECTION OUTPUT ;
    USE SIGNAL ;
    PORT
      LAYER M4 ;
        RECT  92.796 51.984 92.88 52.008 ;
    END
  END q[294]
  PIN q[295]
    DIRECTION OUTPUT ;
    USE SIGNAL ;
    PORT
      LAYER M4 ;
        RECT  92.796 52.08 92.88 52.104 ;
    END
  END q[295]
  PIN q[296]
    DIRECTION OUTPUT ;
    USE SIGNAL ;
    PORT
      LAYER M4 ;
        RECT  92.796 52.176 92.88 52.2 ;
    END
  END q[296]
  PIN q[297]
    DIRECTION OUTPUT ;
    USE SIGNAL ;
    PORT
      LAYER M4 ;
        RECT  92.796 52.272 92.88 52.296 ;
    END
  END q[297]
  PIN q[298]
    DIRECTION OUTPUT ;
    USE SIGNAL ;
    PORT
      LAYER M4 ;
        RECT  92.796 52.368 92.88 52.392 ;
    END
  END q[298]
  PIN q[299]
    DIRECTION OUTPUT ;
    USE SIGNAL ;
    PORT
      LAYER M4 ;
        RECT  92.796 52.464 92.88 52.488 ;
    END
  END q[299]
  PIN q[29]
    DIRECTION OUTPUT ;
    USE SIGNAL ;
    PORT
      LAYER M4 ;
        RECT  92.796 22.704 92.88 22.728 ;
    END
  END q[29]
  PIN q[2]
    DIRECTION OUTPUT ;
    USE SIGNAL ;
    PORT
      LAYER M4 ;
        RECT  92.796 20.112 92.88 20.136 ;
    END
  END q[2]
  PIN q[300]
    DIRECTION OUTPUT ;
    USE SIGNAL ;
    PORT
      LAYER M4 ;
        RECT  92.796 52.56 92.88 52.584 ;
    END
  END q[300]
  PIN q[301]
    DIRECTION OUTPUT ;
    USE SIGNAL ;
    PORT
      LAYER M4 ;
        RECT  92.796 52.656 92.88 52.68 ;
    END
  END q[301]
  PIN q[302]
    DIRECTION OUTPUT ;
    USE SIGNAL ;
    PORT
      LAYER M4 ;
        RECT  92.796 52.752 92.88 52.776 ;
    END
  END q[302]
  PIN q[303]
    DIRECTION OUTPUT ;
    USE SIGNAL ;
    PORT
      LAYER M4 ;
        RECT  92.796 52.848 92.88 52.872 ;
    END
  END q[303]
  PIN q[304]
    DIRECTION OUTPUT ;
    USE SIGNAL ;
    PORT
      LAYER M4 ;
        RECT  92.796 52.944 92.88 52.968 ;
    END
  END q[304]
  PIN q[305]
    DIRECTION OUTPUT ;
    USE SIGNAL ;
    PORT
      LAYER M4 ;
        RECT  92.796 53.04 92.88 53.064 ;
    END
  END q[305]
  PIN q[306]
    DIRECTION OUTPUT ;
    USE SIGNAL ;
    PORT
      LAYER M4 ;
        RECT  92.796 53.136 92.88 53.16 ;
    END
  END q[306]
  PIN q[307]
    DIRECTION OUTPUT ;
    USE SIGNAL ;
    PORT
      LAYER M4 ;
        RECT  92.796 53.232 92.88 53.256 ;
    END
  END q[307]
  PIN q[308]
    DIRECTION OUTPUT ;
    USE SIGNAL ;
    PORT
      LAYER M4 ;
        RECT  92.796 53.328 92.88 53.352 ;
    END
  END q[308]
  PIN q[309]
    DIRECTION OUTPUT ;
    USE SIGNAL ;
    PORT
      LAYER M4 ;
        RECT  92.796 53.424 92.88 53.448 ;
    END
  END q[309]
  PIN q[30]
    DIRECTION OUTPUT ;
    USE SIGNAL ;
    PORT
      LAYER M4 ;
        RECT  92.796 22.8 92.88 22.824 ;
    END
  END q[30]
  PIN q[310]
    DIRECTION OUTPUT ;
    USE SIGNAL ;
    PORT
      LAYER M4 ;
        RECT  92.796 53.52 92.88 53.544 ;
    END
  END q[310]
  PIN q[311]
    DIRECTION OUTPUT ;
    USE SIGNAL ;
    PORT
      LAYER M4 ;
        RECT  92.796 53.616 92.88 53.64 ;
    END
  END q[311]
  PIN q[312]
    DIRECTION OUTPUT ;
    USE SIGNAL ;
    PORT
      LAYER M4 ;
        RECT  92.796 53.712 92.88 53.736 ;
    END
  END q[312]
  PIN q[313]
    DIRECTION OUTPUT ;
    USE SIGNAL ;
    PORT
      LAYER M4 ;
        RECT  92.796 53.808 92.88 53.832 ;
    END
  END q[313]
  PIN q[314]
    DIRECTION OUTPUT ;
    USE SIGNAL ;
    PORT
      LAYER M4 ;
        RECT  92.796 53.904 92.88 53.928 ;
    END
  END q[314]
  PIN q[315]
    DIRECTION OUTPUT ;
    USE SIGNAL ;
    PORT
      LAYER M4 ;
        RECT  92.796 54 92.88 54.024 ;
    END
  END q[315]
  PIN q[316]
    DIRECTION OUTPUT ;
    USE SIGNAL ;
    PORT
      LAYER M4 ;
        RECT  92.796 54.096 92.88 54.12 ;
    END
  END q[316]
  PIN q[317]
    DIRECTION OUTPUT ;
    USE SIGNAL ;
    PORT
      LAYER M4 ;
        RECT  92.796 54.192 92.88 54.216 ;
    END
  END q[317]
  PIN q[318]
    DIRECTION OUTPUT ;
    USE SIGNAL ;
    PORT
      LAYER M4 ;
        RECT  92.796 54.288 92.88 54.312 ;
    END
  END q[318]
  PIN q[319]
    DIRECTION OUTPUT ;
    USE SIGNAL ;
    PORT
      LAYER M4 ;
        RECT  92.796 54.384 92.88 54.408 ;
    END
  END q[319]
  PIN q[31]
    DIRECTION OUTPUT ;
    USE SIGNAL ;
    PORT
      LAYER M4 ;
        RECT  92.796 22.896 92.88 22.92 ;
    END
  END q[31]
  PIN q[320]
    DIRECTION OUTPUT ;
    USE SIGNAL ;
    PORT
      LAYER M4 ;
        RECT  92.796 39.12 92.88 39.144 ;
    END
  END q[320]
  PIN q[321]
    DIRECTION OUTPUT ;
    USE SIGNAL ;
    PORT
      LAYER M4 ;
        RECT  92.796 39.216 92.88 39.24 ;
    END
  END q[321]
  PIN q[322]
    DIRECTION OUTPUT ;
    USE SIGNAL ;
    PORT
      LAYER M4 ;
        RECT  92.796 39.312 92.88 39.336 ;
    END
  END q[322]
  PIN q[323]
    DIRECTION OUTPUT ;
    USE SIGNAL ;
    PORT
      LAYER M4 ;
        RECT  92.796 39.408 92.88 39.432 ;
    END
  END q[323]
  PIN q[324]
    DIRECTION OUTPUT ;
    USE SIGNAL ;
    PORT
      LAYER M4 ;
        RECT  92.796 39.504 92.88 39.528 ;
    END
  END q[324]
  PIN q[325]
    DIRECTION OUTPUT ;
    USE SIGNAL ;
    PORT
      LAYER M4 ;
        RECT  92.796 39.6 92.88 39.624 ;
    END
  END q[325]
  PIN q[326]
    DIRECTION OUTPUT ;
    USE SIGNAL ;
    PORT
      LAYER M4 ;
        RECT  92.796 39.696 92.88 39.72 ;
    END
  END q[326]
  PIN q[327]
    DIRECTION OUTPUT ;
    USE SIGNAL ;
    PORT
      LAYER M4 ;
        RECT  92.796 39.792 92.88 39.816 ;
    END
  END q[327]
  PIN q[328]
    DIRECTION OUTPUT ;
    USE SIGNAL ;
    PORT
      LAYER M4 ;
        RECT  92.796 39.888 92.88 39.912 ;
    END
  END q[328]
  PIN q[329]
    DIRECTION OUTPUT ;
    USE SIGNAL ;
    PORT
      LAYER M4 ;
        RECT  92.796 39.984 92.88 40.008 ;
    END
  END q[329]
  PIN q[32]
    DIRECTION OUTPUT ;
    USE SIGNAL ;
    PORT
      LAYER M4 ;
        RECT  92.796 22.992 92.88 23.016 ;
    END
  END q[32]
  PIN q[330]
    DIRECTION OUTPUT ;
    USE SIGNAL ;
    PORT
      LAYER M4 ;
        RECT  92.796 40.08 92.88 40.104 ;
    END
  END q[330]
  PIN q[331]
    DIRECTION OUTPUT ;
    USE SIGNAL ;
    PORT
      LAYER M4 ;
        RECT  92.796 40.176 92.88 40.2 ;
    END
  END q[331]
  PIN q[332]
    DIRECTION OUTPUT ;
    USE SIGNAL ;
    PORT
      LAYER M4 ;
        RECT  92.796 40.272 92.88 40.296 ;
    END
  END q[332]
  PIN q[333]
    DIRECTION OUTPUT ;
    USE SIGNAL ;
    PORT
      LAYER M4 ;
        RECT  92.796 40.368 92.88 40.392 ;
    END
  END q[333]
  PIN q[334]
    DIRECTION OUTPUT ;
    USE SIGNAL ;
    PORT
      LAYER M4 ;
        RECT  92.796 40.464 92.88 40.488 ;
    END
  END q[334]
  PIN q[335]
    DIRECTION OUTPUT ;
    USE SIGNAL ;
    PORT
      LAYER M4 ;
        RECT  92.796 40.56 92.88 40.584 ;
    END
  END q[335]
  PIN q[336]
    DIRECTION OUTPUT ;
    USE SIGNAL ;
    PORT
      LAYER M4 ;
        RECT  92.796 40.656 92.88 40.68 ;
    END
  END q[336]
  PIN q[337]
    DIRECTION OUTPUT ;
    USE SIGNAL ;
    PORT
      LAYER M4 ;
        RECT  92.796 40.752 92.88 40.776 ;
    END
  END q[337]
  PIN q[338]
    DIRECTION OUTPUT ;
    USE SIGNAL ;
    PORT
      LAYER M4 ;
        RECT  92.796 40.848 92.88 40.872 ;
    END
  END q[338]
  PIN q[339]
    DIRECTION OUTPUT ;
    USE SIGNAL ;
    PORT
      LAYER M4 ;
        RECT  92.796 40.944 92.88 40.968 ;
    END
  END q[339]
  PIN q[33]
    DIRECTION OUTPUT ;
    USE SIGNAL ;
    PORT
      LAYER M4 ;
        RECT  92.796 23.088 92.88 23.112 ;
    END
  END q[33]
  PIN q[340]
    DIRECTION OUTPUT ;
    USE SIGNAL ;
    PORT
      LAYER M4 ;
        RECT  92.796 41.04 92.88 41.064 ;
    END
  END q[340]
  PIN q[341]
    DIRECTION OUTPUT ;
    USE SIGNAL ;
    PORT
      LAYER M4 ;
        RECT  92.796 41.136 92.88 41.16 ;
    END
  END q[341]
  PIN q[342]
    DIRECTION OUTPUT ;
    USE SIGNAL ;
    PORT
      LAYER M4 ;
        RECT  92.796 41.232 92.88 41.256 ;
    END
  END q[342]
  PIN q[343]
    DIRECTION OUTPUT ;
    USE SIGNAL ;
    PORT
      LAYER M4 ;
        RECT  92.796 41.328 92.88 41.352 ;
    END
  END q[343]
  PIN q[344]
    DIRECTION OUTPUT ;
    USE SIGNAL ;
    PORT
      LAYER M4 ;
        RECT  92.796 41.424 92.88 41.448 ;
    END
  END q[344]
  PIN q[345]
    DIRECTION OUTPUT ;
    USE SIGNAL ;
    PORT
      LAYER M4 ;
        RECT  92.796 41.52 92.88 41.544 ;
    END
  END q[345]
  PIN q[346]
    DIRECTION OUTPUT ;
    USE SIGNAL ;
    PORT
      LAYER M4 ;
        RECT  92.796 41.616 92.88 41.64 ;
    END
  END q[346]
  PIN q[347]
    DIRECTION OUTPUT ;
    USE SIGNAL ;
    PORT
      LAYER M4 ;
        RECT  92.796 41.712 92.88 41.736 ;
    END
  END q[347]
  PIN q[348]
    DIRECTION OUTPUT ;
    USE SIGNAL ;
    PORT
      LAYER M4 ;
        RECT  92.796 41.808 92.88 41.832 ;
    END
  END q[348]
  PIN q[349]
    DIRECTION OUTPUT ;
    USE SIGNAL ;
    PORT
      LAYER M4 ;
        RECT  92.796 41.904 92.88 41.928 ;
    END
  END q[349]
  PIN q[34]
    DIRECTION OUTPUT ;
    USE SIGNAL ;
    PORT
      LAYER M4 ;
        RECT  92.796 23.184 92.88 23.208 ;
    END
  END q[34]
  PIN q[350]
    DIRECTION OUTPUT ;
    USE SIGNAL ;
    PORT
      LAYER M4 ;
        RECT  92.796 42 92.88 42.024 ;
    END
  END q[350]
  PIN q[351]
    DIRECTION OUTPUT ;
    USE SIGNAL ;
    PORT
      LAYER M4 ;
        RECT  92.796 42.096 92.88 42.12 ;
    END
  END q[351]
  PIN q[352]
    DIRECTION OUTPUT ;
    USE SIGNAL ;
    PORT
      LAYER M4 ;
        RECT  92.796 54.48 92.88 54.504 ;
    END
  END q[352]
  PIN q[353]
    DIRECTION OUTPUT ;
    USE SIGNAL ;
    PORT
      LAYER M4 ;
        RECT  92.796 54.576 92.88 54.6 ;
    END
  END q[353]
  PIN q[354]
    DIRECTION OUTPUT ;
    USE SIGNAL ;
    PORT
      LAYER M4 ;
        RECT  92.796 54.672 92.88 54.696 ;
    END
  END q[354]
  PIN q[355]
    DIRECTION OUTPUT ;
    USE SIGNAL ;
    PORT
      LAYER M4 ;
        RECT  92.796 54.768 92.88 54.792 ;
    END
  END q[355]
  PIN q[356]
    DIRECTION OUTPUT ;
    USE SIGNAL ;
    PORT
      LAYER M4 ;
        RECT  92.796 54.864 92.88 54.888 ;
    END
  END q[356]
  PIN q[357]
    DIRECTION OUTPUT ;
    USE SIGNAL ;
    PORT
      LAYER M4 ;
        RECT  92.796 54.96 92.88 54.984 ;
    END
  END q[357]
  PIN q[358]
    DIRECTION OUTPUT ;
    USE SIGNAL ;
    PORT
      LAYER M4 ;
        RECT  92.796 55.056 92.88 55.08 ;
    END
  END q[358]
  PIN q[359]
    DIRECTION OUTPUT ;
    USE SIGNAL ;
    PORT
      LAYER M4 ;
        RECT  92.796 55.152 92.88 55.176 ;
    END
  END q[359]
  PIN q[35]
    DIRECTION OUTPUT ;
    USE SIGNAL ;
    PORT
      LAYER M4 ;
        RECT  92.796 23.28 92.88 23.304 ;
    END
  END q[35]
  PIN q[360]
    DIRECTION OUTPUT ;
    USE SIGNAL ;
    PORT
      LAYER M4 ;
        RECT  92.796 55.248 92.88 55.272 ;
    END
  END q[360]
  PIN q[361]
    DIRECTION OUTPUT ;
    USE SIGNAL ;
    PORT
      LAYER M4 ;
        RECT  92.796 55.344 92.88 55.368 ;
    END
  END q[361]
  PIN q[362]
    DIRECTION OUTPUT ;
    USE SIGNAL ;
    PORT
      LAYER M4 ;
        RECT  92.796 55.44 92.88 55.464 ;
    END
  END q[362]
  PIN q[363]
    DIRECTION OUTPUT ;
    USE SIGNAL ;
    PORT
      LAYER M4 ;
        RECT  92.796 55.536 92.88 55.56 ;
    END
  END q[363]
  PIN q[364]
    DIRECTION OUTPUT ;
    USE SIGNAL ;
    PORT
      LAYER M4 ;
        RECT  92.796 55.632 92.88 55.656 ;
    END
  END q[364]
  PIN q[365]
    DIRECTION OUTPUT ;
    USE SIGNAL ;
    PORT
      LAYER M4 ;
        RECT  92.796 55.728 92.88 55.752 ;
    END
  END q[365]
  PIN q[366]
    DIRECTION OUTPUT ;
    USE SIGNAL ;
    PORT
      LAYER M4 ;
        RECT  92.796 55.824 92.88 55.848 ;
    END
  END q[366]
  PIN q[367]
    DIRECTION OUTPUT ;
    USE SIGNAL ;
    PORT
      LAYER M4 ;
        RECT  92.796 55.92 92.88 55.944 ;
    END
  END q[367]
  PIN q[368]
    DIRECTION OUTPUT ;
    USE SIGNAL ;
    PORT
      LAYER M4 ;
        RECT  92.796 56.016 92.88 56.04 ;
    END
  END q[368]
  PIN q[369]
    DIRECTION OUTPUT ;
    USE SIGNAL ;
    PORT
      LAYER M4 ;
        RECT  92.796 56.112 92.88 56.136 ;
    END
  END q[369]
  PIN q[36]
    DIRECTION OUTPUT ;
    USE SIGNAL ;
    PORT
      LAYER M4 ;
        RECT  92.796 23.376 92.88 23.4 ;
    END
  END q[36]
  PIN q[370]
    DIRECTION OUTPUT ;
    USE SIGNAL ;
    PORT
      LAYER M4 ;
        RECT  92.796 56.208 92.88 56.232 ;
    END
  END q[370]
  PIN q[371]
    DIRECTION OUTPUT ;
    USE SIGNAL ;
    PORT
      LAYER M4 ;
        RECT  92.796 56.304 92.88 56.328 ;
    END
  END q[371]
  PIN q[372]
    DIRECTION OUTPUT ;
    USE SIGNAL ;
    PORT
      LAYER M4 ;
        RECT  92.796 56.4 92.88 56.424 ;
    END
  END q[372]
  PIN q[373]
    DIRECTION OUTPUT ;
    USE SIGNAL ;
    PORT
      LAYER M4 ;
        RECT  92.796 56.496 92.88 56.52 ;
    END
  END q[373]
  PIN q[374]
    DIRECTION OUTPUT ;
    USE SIGNAL ;
    PORT
      LAYER M4 ;
        RECT  92.796 56.592 92.88 56.616 ;
    END
  END q[374]
  PIN q[375]
    DIRECTION OUTPUT ;
    USE SIGNAL ;
    PORT
      LAYER M4 ;
        RECT  92.796 56.688 92.88 56.712 ;
    END
  END q[375]
  PIN q[376]
    DIRECTION OUTPUT ;
    USE SIGNAL ;
    PORT
      LAYER M4 ;
        RECT  92.796 56.784 92.88 56.808 ;
    END
  END q[376]
  PIN q[377]
    DIRECTION OUTPUT ;
    USE SIGNAL ;
    PORT
      LAYER M4 ;
        RECT  92.796 56.88 92.88 56.904 ;
    END
  END q[377]
  PIN q[378]
    DIRECTION OUTPUT ;
    USE SIGNAL ;
    PORT
      LAYER M4 ;
        RECT  92.796 56.976 92.88 57 ;
    END
  END q[378]
  PIN q[379]
    DIRECTION OUTPUT ;
    USE SIGNAL ;
    PORT
      LAYER M4 ;
        RECT  92.796 57.072 92.88 57.096 ;
    END
  END q[379]
  PIN q[37]
    DIRECTION OUTPUT ;
    USE SIGNAL ;
    PORT
      LAYER M4 ;
        RECT  92.796 23.472 92.88 23.496 ;
    END
  END q[37]
  PIN q[380]
    DIRECTION OUTPUT ;
    USE SIGNAL ;
    PORT
      LAYER M4 ;
        RECT  92.796 57.168 92.88 57.192 ;
    END
  END q[380]
  PIN q[381]
    DIRECTION OUTPUT ;
    USE SIGNAL ;
    PORT
      LAYER M4 ;
        RECT  92.796 57.264 92.88 57.288 ;
    END
  END q[381]
  PIN q[382]
    DIRECTION OUTPUT ;
    USE SIGNAL ;
    PORT
      LAYER M4 ;
        RECT  92.796 57.36 92.88 57.384 ;
    END
  END q[382]
  PIN q[383]
    DIRECTION OUTPUT ;
    USE SIGNAL ;
    PORT
      LAYER M4 ;
        RECT  92.796 57.456 92.88 57.48 ;
    END
  END q[383]
  PIN q[384]
    DIRECTION OUTPUT ;
    USE SIGNAL ;
    PORT
      LAYER M4 ;
        RECT  92.796 16.08 92.88 16.104 ;
    END
  END q[384]
  PIN q[385]
    DIRECTION OUTPUT ;
    USE SIGNAL ;
    PORT
      LAYER M4 ;
        RECT  92.796 16.176 92.88 16.2 ;
    END
  END q[385]
  PIN q[386]
    DIRECTION OUTPUT ;
    USE SIGNAL ;
    PORT
      LAYER M4 ;
        RECT  92.796 16.272 92.88 16.296 ;
    END
  END q[386]
  PIN q[387]
    DIRECTION OUTPUT ;
    USE SIGNAL ;
    PORT
      LAYER M4 ;
        RECT  92.796 16.368 92.88 16.392 ;
    END
  END q[387]
  PIN q[388]
    DIRECTION OUTPUT ;
    USE SIGNAL ;
    PORT
      LAYER M4 ;
        RECT  92.796 16.464 92.88 16.488 ;
    END
  END q[388]
  PIN q[389]
    DIRECTION OUTPUT ;
    USE SIGNAL ;
    PORT
      LAYER M4 ;
        RECT  92.796 16.56 92.88 16.584 ;
    END
  END q[389]
  PIN q[38]
    DIRECTION OUTPUT ;
    USE SIGNAL ;
    PORT
      LAYER M4 ;
        RECT  92.796 23.568 92.88 23.592 ;
    END
  END q[38]
  PIN q[390]
    DIRECTION OUTPUT ;
    USE SIGNAL ;
    PORT
      LAYER M4 ;
        RECT  92.796 16.656 92.88 16.68 ;
    END
  END q[390]
  PIN q[391]
    DIRECTION OUTPUT ;
    USE SIGNAL ;
    PORT
      LAYER M4 ;
        RECT  92.796 16.752 92.88 16.776 ;
    END
  END q[391]
  PIN q[392]
    DIRECTION OUTPUT ;
    USE SIGNAL ;
    PORT
      LAYER M4 ;
        RECT  92.796 16.848 92.88 16.872 ;
    END
  END q[392]
  PIN q[393]
    DIRECTION OUTPUT ;
    USE SIGNAL ;
    PORT
      LAYER M4 ;
        RECT  92.796 16.944 92.88 16.968 ;
    END
  END q[393]
  PIN q[394]
    DIRECTION OUTPUT ;
    USE SIGNAL ;
    PORT
      LAYER M4 ;
        RECT  92.796 17.04 92.88 17.064 ;
    END
  END q[394]
  PIN q[395]
    DIRECTION OUTPUT ;
    USE SIGNAL ;
    PORT
      LAYER M4 ;
        RECT  92.796 17.136 92.88 17.16 ;
    END
  END q[395]
  PIN q[396]
    DIRECTION OUTPUT ;
    USE SIGNAL ;
    PORT
      LAYER M4 ;
        RECT  92.796 17.232 92.88 17.256 ;
    END
  END q[396]
  PIN q[397]
    DIRECTION OUTPUT ;
    USE SIGNAL ;
    PORT
      LAYER M4 ;
        RECT  92.796 17.328 92.88 17.352 ;
    END
  END q[397]
  PIN q[398]
    DIRECTION OUTPUT ;
    USE SIGNAL ;
    PORT
      LAYER M4 ;
        RECT  92.796 17.424 92.88 17.448 ;
    END
  END q[398]
  PIN q[399]
    DIRECTION OUTPUT ;
    USE SIGNAL ;
    PORT
      LAYER M4 ;
        RECT  92.796 17.52 92.88 17.544 ;
    END
  END q[399]
  PIN q[39]
    DIRECTION OUTPUT ;
    USE SIGNAL ;
    PORT
      LAYER M4 ;
        RECT  92.796 23.664 92.88 23.688 ;
    END
  END q[39]
  PIN q[3]
    DIRECTION OUTPUT ;
    USE SIGNAL ;
    PORT
      LAYER M4 ;
        RECT  92.796 20.208 92.88 20.232 ;
    END
  END q[3]
  PIN q[400]
    DIRECTION OUTPUT ;
    USE SIGNAL ;
    PORT
      LAYER M4 ;
        RECT  92.796 17.616 92.88 17.64 ;
    END
  END q[400]
  PIN q[401]
    DIRECTION OUTPUT ;
    USE SIGNAL ;
    PORT
      LAYER M4 ;
        RECT  92.796 17.712 92.88 17.736 ;
    END
  END q[401]
  PIN q[402]
    DIRECTION OUTPUT ;
    USE SIGNAL ;
    PORT
      LAYER M4 ;
        RECT  92.796 17.808 92.88 17.832 ;
    END
  END q[402]
  PIN q[403]
    DIRECTION OUTPUT ;
    USE SIGNAL ;
    PORT
      LAYER M4 ;
        RECT  92.796 17.904 92.88 17.928 ;
    END
  END q[403]
  PIN q[404]
    DIRECTION OUTPUT ;
    USE SIGNAL ;
    PORT
      LAYER M4 ;
        RECT  92.796 18 92.88 18.024 ;
    END
  END q[404]
  PIN q[405]
    DIRECTION OUTPUT ;
    USE SIGNAL ;
    PORT
      LAYER M4 ;
        RECT  92.796 18.096 92.88 18.12 ;
    END
  END q[405]
  PIN q[406]
    DIRECTION OUTPUT ;
    USE SIGNAL ;
    PORT
      LAYER M4 ;
        RECT  92.796 18.192 92.88 18.216 ;
    END
  END q[406]
  PIN q[407]
    DIRECTION OUTPUT ;
    USE SIGNAL ;
    PORT
      LAYER M4 ;
        RECT  92.796 18.288 92.88 18.312 ;
    END
  END q[407]
  PIN q[408]
    DIRECTION OUTPUT ;
    USE SIGNAL ;
    PORT
      LAYER M4 ;
        RECT  92.796 18.384 92.88 18.408 ;
    END
  END q[408]
  PIN q[409]
    DIRECTION OUTPUT ;
    USE SIGNAL ;
    PORT
      LAYER M4 ;
        RECT  92.796 18.48 92.88 18.504 ;
    END
  END q[409]
  PIN q[40]
    DIRECTION OUTPUT ;
    USE SIGNAL ;
    PORT
      LAYER M4 ;
        RECT  92.796 23.76 92.88 23.784 ;
    END
  END q[40]
  PIN q[410]
    DIRECTION OUTPUT ;
    USE SIGNAL ;
    PORT
      LAYER M4 ;
        RECT  92.796 18.576 92.88 18.6 ;
    END
  END q[410]
  PIN q[411]
    DIRECTION OUTPUT ;
    USE SIGNAL ;
    PORT
      LAYER M4 ;
        RECT  92.796 18.672 92.88 18.696 ;
    END
  END q[411]
  PIN q[412]
    DIRECTION OUTPUT ;
    USE SIGNAL ;
    PORT
      LAYER M4 ;
        RECT  92.796 18.768 92.88 18.792 ;
    END
  END q[412]
  PIN q[413]
    DIRECTION OUTPUT ;
    USE SIGNAL ;
    PORT
      LAYER M4 ;
        RECT  92.796 18.864 92.88 18.888 ;
    END
  END q[413]
  PIN q[414]
    DIRECTION OUTPUT ;
    USE SIGNAL ;
    PORT
      LAYER M4 ;
        RECT  92.796 18.96 92.88 18.984 ;
    END
  END q[414]
  PIN q[415]
    DIRECTION OUTPUT ;
    USE SIGNAL ;
    PORT
      LAYER M4 ;
        RECT  92.796 19.056 92.88 19.08 ;
    END
  END q[415]
  PIN q[416]
    DIRECTION OUTPUT ;
    USE SIGNAL ;
    PORT
      LAYER M4 ;
        RECT  92.796 42.192 92.88 42.216 ;
    END
  END q[416]
  PIN q[417]
    DIRECTION OUTPUT ;
    USE SIGNAL ;
    PORT
      LAYER M4 ;
        RECT  92.796 42.288 92.88 42.312 ;
    END
  END q[417]
  PIN q[418]
    DIRECTION OUTPUT ;
    USE SIGNAL ;
    PORT
      LAYER M4 ;
        RECT  92.796 42.384 92.88 42.408 ;
    END
  END q[418]
  PIN q[419]
    DIRECTION OUTPUT ;
    USE SIGNAL ;
    PORT
      LAYER M4 ;
        RECT  92.796 42.48 92.88 42.504 ;
    END
  END q[419]
  PIN q[41]
    DIRECTION OUTPUT ;
    USE SIGNAL ;
    PORT
      LAYER M4 ;
        RECT  92.796 23.856 92.88 23.88 ;
    END
  END q[41]
  PIN q[420]
    DIRECTION OUTPUT ;
    USE SIGNAL ;
    PORT
      LAYER M4 ;
        RECT  92.796 42.576 92.88 42.6 ;
    END
  END q[420]
  PIN q[421]
    DIRECTION OUTPUT ;
    USE SIGNAL ;
    PORT
      LAYER M4 ;
        RECT  92.796 42.672 92.88 42.696 ;
    END
  END q[421]
  PIN q[422]
    DIRECTION OUTPUT ;
    USE SIGNAL ;
    PORT
      LAYER M4 ;
        RECT  92.796 42.768 92.88 42.792 ;
    END
  END q[422]
  PIN q[423]
    DIRECTION OUTPUT ;
    USE SIGNAL ;
    PORT
      LAYER M4 ;
        RECT  92.796 42.864 92.88 42.888 ;
    END
  END q[423]
  PIN q[424]
    DIRECTION OUTPUT ;
    USE SIGNAL ;
    PORT
      LAYER M4 ;
        RECT  92.796 42.96 92.88 42.984 ;
    END
  END q[424]
  PIN q[425]
    DIRECTION OUTPUT ;
    USE SIGNAL ;
    PORT
      LAYER M4 ;
        RECT  92.796 43.056 92.88 43.08 ;
    END
  END q[425]
  PIN q[426]
    DIRECTION OUTPUT ;
    USE SIGNAL ;
    PORT
      LAYER M4 ;
        RECT  92.796 43.152 92.88 43.176 ;
    END
  END q[426]
  PIN q[427]
    DIRECTION OUTPUT ;
    USE SIGNAL ;
    PORT
      LAYER M4 ;
        RECT  92.796 43.248 92.88 43.272 ;
    END
  END q[427]
  PIN q[428]
    DIRECTION OUTPUT ;
    USE SIGNAL ;
    PORT
      LAYER M4 ;
        RECT  92.796 43.344 92.88 43.368 ;
    END
  END q[428]
  PIN q[429]
    DIRECTION OUTPUT ;
    USE SIGNAL ;
    PORT
      LAYER M4 ;
        RECT  92.796 43.44 92.88 43.464 ;
    END
  END q[429]
  PIN q[42]
    DIRECTION OUTPUT ;
    USE SIGNAL ;
    PORT
      LAYER M4 ;
        RECT  92.796 23.952 92.88 23.976 ;
    END
  END q[42]
  PIN q[430]
    DIRECTION OUTPUT ;
    USE SIGNAL ;
    PORT
      LAYER M4 ;
        RECT  92.796 43.536 92.88 43.56 ;
    END
  END q[430]
  PIN q[431]
    DIRECTION OUTPUT ;
    USE SIGNAL ;
    PORT
      LAYER M4 ;
        RECT  92.796 43.632 92.88 43.656 ;
    END
  END q[431]
  PIN q[432]
    DIRECTION OUTPUT ;
    USE SIGNAL ;
    PORT
      LAYER M4 ;
        RECT  92.796 43.728 92.88 43.752 ;
    END
  END q[432]
  PIN q[433]
    DIRECTION OUTPUT ;
    USE SIGNAL ;
    PORT
      LAYER M4 ;
        RECT  92.796 43.824 92.88 43.848 ;
    END
  END q[433]
  PIN q[434]
    DIRECTION OUTPUT ;
    USE SIGNAL ;
    PORT
      LAYER M4 ;
        RECT  92.796 43.92 92.88 43.944 ;
    END
  END q[434]
  PIN q[435]
    DIRECTION OUTPUT ;
    USE SIGNAL ;
    PORT
      LAYER M4 ;
        RECT  92.796 44.016 92.88 44.04 ;
    END
  END q[435]
  PIN q[436]
    DIRECTION OUTPUT ;
    USE SIGNAL ;
    PORT
      LAYER M4 ;
        RECT  92.796 44.112 92.88 44.136 ;
    END
  END q[436]
  PIN q[437]
    DIRECTION OUTPUT ;
    USE SIGNAL ;
    PORT
      LAYER M4 ;
        RECT  92.796 44.208 92.88 44.232 ;
    END
  END q[437]
  PIN q[438]
    DIRECTION OUTPUT ;
    USE SIGNAL ;
    PORT
      LAYER M4 ;
        RECT  92.796 44.304 92.88 44.328 ;
    END
  END q[438]
  PIN q[439]
    DIRECTION OUTPUT ;
    USE SIGNAL ;
    PORT
      LAYER M4 ;
        RECT  92.796 44.4 92.88 44.424 ;
    END
  END q[439]
  PIN q[43]
    DIRECTION OUTPUT ;
    USE SIGNAL ;
    PORT
      LAYER M4 ;
        RECT  92.796 24.048 92.88 24.072 ;
    END
  END q[43]
  PIN q[440]
    DIRECTION OUTPUT ;
    USE SIGNAL ;
    PORT
      LAYER M4 ;
        RECT  92.796 44.496 92.88 44.52 ;
    END
  END q[440]
  PIN q[441]
    DIRECTION OUTPUT ;
    USE SIGNAL ;
    PORT
      LAYER M4 ;
        RECT  92.796 44.592 92.88 44.616 ;
    END
  END q[441]
  PIN q[442]
    DIRECTION OUTPUT ;
    USE SIGNAL ;
    PORT
      LAYER M4 ;
        RECT  92.796 44.688 92.88 44.712 ;
    END
  END q[442]
  PIN q[443]
    DIRECTION OUTPUT ;
    USE SIGNAL ;
    PORT
      LAYER M4 ;
        RECT  92.796 44.784 92.88 44.808 ;
    END
  END q[443]
  PIN q[444]
    DIRECTION OUTPUT ;
    USE SIGNAL ;
    PORT
      LAYER M4 ;
        RECT  92.796 44.88 92.88 44.904 ;
    END
  END q[444]
  PIN q[445]
    DIRECTION OUTPUT ;
    USE SIGNAL ;
    PORT
      LAYER M4 ;
        RECT  92.796 44.976 92.88 45 ;
    END
  END q[445]
  PIN q[446]
    DIRECTION OUTPUT ;
    USE SIGNAL ;
    PORT
      LAYER M4 ;
        RECT  92.796 45.072 92.88 45.096 ;
    END
  END q[446]
  PIN q[447]
    DIRECTION OUTPUT ;
    USE SIGNAL ;
    PORT
      LAYER M4 ;
        RECT  92.796 45.168 92.88 45.192 ;
    END
  END q[447]
  PIN q[448]
    DIRECTION OUTPUT ;
    USE SIGNAL ;
    PORT
      LAYER M4 ;
        RECT  92.796 9.936 92.88 9.96 ;
    END
  END q[448]
  PIN q[449]
    DIRECTION OUTPUT ;
    USE SIGNAL ;
    PORT
      LAYER M4 ;
        RECT  92.796 10.032 92.88 10.056 ;
    END
  END q[449]
  PIN q[44]
    DIRECTION OUTPUT ;
    USE SIGNAL ;
    PORT
      LAYER M4 ;
        RECT  92.796 24.144 92.88 24.168 ;
    END
  END q[44]
  PIN q[450]
    DIRECTION OUTPUT ;
    USE SIGNAL ;
    PORT
      LAYER M4 ;
        RECT  92.796 10.128 92.88 10.152 ;
    END
  END q[450]
  PIN q[451]
    DIRECTION OUTPUT ;
    USE SIGNAL ;
    PORT
      LAYER M4 ;
        RECT  92.796 10.224 92.88 10.248 ;
    END
  END q[451]
  PIN q[452]
    DIRECTION OUTPUT ;
    USE SIGNAL ;
    PORT
      LAYER M4 ;
        RECT  92.796 10.32 92.88 10.344 ;
    END
  END q[452]
  PIN q[453]
    DIRECTION OUTPUT ;
    USE SIGNAL ;
    PORT
      LAYER M4 ;
        RECT  92.796 10.416 92.88 10.44 ;
    END
  END q[453]
  PIN q[454]
    DIRECTION OUTPUT ;
    USE SIGNAL ;
    PORT
      LAYER M4 ;
        RECT  92.796 10.512 92.88 10.536 ;
    END
  END q[454]
  PIN q[455]
    DIRECTION OUTPUT ;
    USE SIGNAL ;
    PORT
      LAYER M4 ;
        RECT  92.796 10.608 92.88 10.632 ;
    END
  END q[455]
  PIN q[456]
    DIRECTION OUTPUT ;
    USE SIGNAL ;
    PORT
      LAYER M4 ;
        RECT  92.796 10.704 92.88 10.728 ;
    END
  END q[456]
  PIN q[457]
    DIRECTION OUTPUT ;
    USE SIGNAL ;
    PORT
      LAYER M4 ;
        RECT  92.796 10.8 92.88 10.824 ;
    END
  END q[457]
  PIN q[458]
    DIRECTION OUTPUT ;
    USE SIGNAL ;
    PORT
      LAYER M4 ;
        RECT  92.796 10.896 92.88 10.92 ;
    END
  END q[458]
  PIN q[459]
    DIRECTION OUTPUT ;
    USE SIGNAL ;
    PORT
      LAYER M4 ;
        RECT  92.796 10.992 92.88 11.016 ;
    END
  END q[459]
  PIN q[45]
    DIRECTION OUTPUT ;
    USE SIGNAL ;
    PORT
      LAYER M4 ;
        RECT  92.796 24.24 92.88 24.264 ;
    END
  END q[45]
  PIN q[460]
    DIRECTION OUTPUT ;
    USE SIGNAL ;
    PORT
      LAYER M4 ;
        RECT  92.796 11.088 92.88 11.112 ;
    END
  END q[460]
  PIN q[461]
    DIRECTION OUTPUT ;
    USE SIGNAL ;
    PORT
      LAYER M4 ;
        RECT  92.796 11.184 92.88 11.208 ;
    END
  END q[461]
  PIN q[462]
    DIRECTION OUTPUT ;
    USE SIGNAL ;
    PORT
      LAYER M4 ;
        RECT  92.796 11.28 92.88 11.304 ;
    END
  END q[462]
  PIN q[463]
    DIRECTION OUTPUT ;
    USE SIGNAL ;
    PORT
      LAYER M4 ;
        RECT  92.796 11.376 92.88 11.4 ;
    END
  END q[463]
  PIN q[464]
    DIRECTION OUTPUT ;
    USE SIGNAL ;
    PORT
      LAYER M4 ;
        RECT  92.796 11.472 92.88 11.496 ;
    END
  END q[464]
  PIN q[465]
    DIRECTION OUTPUT ;
    USE SIGNAL ;
    PORT
      LAYER M4 ;
        RECT  92.796 11.568 92.88 11.592 ;
    END
  END q[465]
  PIN q[466]
    DIRECTION OUTPUT ;
    USE SIGNAL ;
    PORT
      LAYER M4 ;
        RECT  92.796 11.664 92.88 11.688 ;
    END
  END q[466]
  PIN q[467]
    DIRECTION OUTPUT ;
    USE SIGNAL ;
    PORT
      LAYER M4 ;
        RECT  92.796 11.76 92.88 11.784 ;
    END
  END q[467]
  PIN q[468]
    DIRECTION OUTPUT ;
    USE SIGNAL ;
    PORT
      LAYER M4 ;
        RECT  92.796 11.856 92.88 11.88 ;
    END
  END q[468]
  PIN q[469]
    DIRECTION OUTPUT ;
    USE SIGNAL ;
    PORT
      LAYER M4 ;
        RECT  92.796 11.952 92.88 11.976 ;
    END
  END q[469]
  PIN q[46]
    DIRECTION OUTPUT ;
    USE SIGNAL ;
    PORT
      LAYER M4 ;
        RECT  92.796 24.336 92.88 24.36 ;
    END
  END q[46]
  PIN q[470]
    DIRECTION OUTPUT ;
    USE SIGNAL ;
    PORT
      LAYER M4 ;
        RECT  92.796 12.048 92.88 12.072 ;
    END
  END q[470]
  PIN q[471]
    DIRECTION OUTPUT ;
    USE SIGNAL ;
    PORT
      LAYER M4 ;
        RECT  92.796 12.144 92.88 12.168 ;
    END
  END q[471]
  PIN q[472]
    DIRECTION OUTPUT ;
    USE SIGNAL ;
    PORT
      LAYER M4 ;
        RECT  92.796 12.24 92.88 12.264 ;
    END
  END q[472]
  PIN q[473]
    DIRECTION OUTPUT ;
    USE SIGNAL ;
    PORT
      LAYER M4 ;
        RECT  92.796 12.336 92.88 12.36 ;
    END
  END q[473]
  PIN q[474]
    DIRECTION OUTPUT ;
    USE SIGNAL ;
    PORT
      LAYER M4 ;
        RECT  92.796 12.432 92.88 12.456 ;
    END
  END q[474]
  PIN q[475]
    DIRECTION OUTPUT ;
    USE SIGNAL ;
    PORT
      LAYER M4 ;
        RECT  92.796 12.528 92.88 12.552 ;
    END
  END q[475]
  PIN q[476]
    DIRECTION OUTPUT ;
    USE SIGNAL ;
    PORT
      LAYER M4 ;
        RECT  92.796 12.624 92.88 12.648 ;
    END
  END q[476]
  PIN q[477]
    DIRECTION OUTPUT ;
    USE SIGNAL ;
    PORT
      LAYER M4 ;
        RECT  92.796 12.72 92.88 12.744 ;
    END
  END q[477]
  PIN q[478]
    DIRECTION OUTPUT ;
    USE SIGNAL ;
    PORT
      LAYER M4 ;
        RECT  92.796 12.816 92.88 12.84 ;
    END
  END q[478]
  PIN q[479]
    DIRECTION OUTPUT ;
    USE SIGNAL ;
    PORT
      LAYER M4 ;
        RECT  92.796 12.912 92.88 12.936 ;
    END
  END q[479]
  PIN q[47]
    DIRECTION OUTPUT ;
    USE SIGNAL ;
    PORT
      LAYER M4 ;
        RECT  92.796 24.432 92.88 24.456 ;
    END
  END q[47]
  PIN q[480]
    DIRECTION OUTPUT ;
    USE SIGNAL ;
    PORT
      LAYER M4 ;
        RECT  92.796 58.32 92.88 58.344 ;
    END
  END q[480]
  PIN q[481]
    DIRECTION OUTPUT ;
    USE SIGNAL ;
    PORT
      LAYER M4 ;
        RECT  92.796 58.416 92.88 58.44 ;
    END
  END q[481]
  PIN q[482]
    DIRECTION OUTPUT ;
    USE SIGNAL ;
    PORT
      LAYER M4 ;
        RECT  92.796 58.512 92.88 58.536 ;
    END
  END q[482]
  PIN q[483]
    DIRECTION OUTPUT ;
    USE SIGNAL ;
    PORT
      LAYER M4 ;
        RECT  92.796 58.608 92.88 58.632 ;
    END
  END q[483]
  PIN q[484]
    DIRECTION OUTPUT ;
    USE SIGNAL ;
    PORT
      LAYER M4 ;
        RECT  92.796 58.704 92.88 58.728 ;
    END
  END q[484]
  PIN q[485]
    DIRECTION OUTPUT ;
    USE SIGNAL ;
    PORT
      LAYER M4 ;
        RECT  92.796 58.8 92.88 58.824 ;
    END
  END q[485]
  PIN q[486]
    DIRECTION OUTPUT ;
    USE SIGNAL ;
    PORT
      LAYER M4 ;
        RECT  92.796 58.896 92.88 58.92 ;
    END
  END q[486]
  PIN q[487]
    DIRECTION OUTPUT ;
    USE SIGNAL ;
    PORT
      LAYER M4 ;
        RECT  92.796 58.992 92.88 59.016 ;
    END
  END q[487]
  PIN q[488]
    DIRECTION OUTPUT ;
    USE SIGNAL ;
    PORT
      LAYER M4 ;
        RECT  92.796 59.088 92.88 59.112 ;
    END
  END q[488]
  PIN q[489]
    DIRECTION OUTPUT ;
    USE SIGNAL ;
    PORT
      LAYER M4 ;
        RECT  92.796 59.184 92.88 59.208 ;
    END
  END q[489]
  PIN q[48]
    DIRECTION OUTPUT ;
    USE SIGNAL ;
    PORT
      LAYER M4 ;
        RECT  92.796 24.528 92.88 24.552 ;
    END
  END q[48]
  PIN q[490]
    DIRECTION OUTPUT ;
    USE SIGNAL ;
    PORT
      LAYER M4 ;
        RECT  92.796 59.28 92.88 59.304 ;
    END
  END q[490]
  PIN q[491]
    DIRECTION OUTPUT ;
    USE SIGNAL ;
    PORT
      LAYER M4 ;
        RECT  92.796 59.376 92.88 59.4 ;
    END
  END q[491]
  PIN q[492]
    DIRECTION OUTPUT ;
    USE SIGNAL ;
    PORT
      LAYER M4 ;
        RECT  92.796 59.472 92.88 59.496 ;
    END
  END q[492]
  PIN q[493]
    DIRECTION OUTPUT ;
    USE SIGNAL ;
    PORT
      LAYER M4 ;
        RECT  92.796 59.568 92.88 59.592 ;
    END
  END q[493]
  PIN q[494]
    DIRECTION OUTPUT ;
    USE SIGNAL ;
    PORT
      LAYER M4 ;
        RECT  92.796 59.664 92.88 59.688 ;
    END
  END q[494]
  PIN q[495]
    DIRECTION OUTPUT ;
    USE SIGNAL ;
    PORT
      LAYER M4 ;
        RECT  92.796 59.76 92.88 59.784 ;
    END
  END q[495]
  PIN q[496]
    DIRECTION OUTPUT ;
    USE SIGNAL ;
    PORT
      LAYER M4 ;
        RECT  92.796 59.856 92.88 59.88 ;
    END
  END q[496]
  PIN q[497]
    DIRECTION OUTPUT ;
    USE SIGNAL ;
    PORT
      LAYER M4 ;
        RECT  92.796 59.952 92.88 59.976 ;
    END
  END q[497]
  PIN q[498]
    DIRECTION OUTPUT ;
    USE SIGNAL ;
    PORT
      LAYER M4 ;
        RECT  92.796 60.048 92.88 60.072 ;
    END
  END q[498]
  PIN q[499]
    DIRECTION OUTPUT ;
    USE SIGNAL ;
    PORT
      LAYER M4 ;
        RECT  92.796 60.144 92.88 60.168 ;
    END
  END q[499]
  PIN q[49]
    DIRECTION OUTPUT ;
    USE SIGNAL ;
    PORT
      LAYER M4 ;
        RECT  92.796 24.624 92.88 24.648 ;
    END
  END q[49]
  PIN q[4]
    DIRECTION OUTPUT ;
    USE SIGNAL ;
    PORT
      LAYER M4 ;
        RECT  92.796 20.304 92.88 20.328 ;
    END
  END q[4]
  PIN q[500]
    DIRECTION OUTPUT ;
    USE SIGNAL ;
    PORT
      LAYER M4 ;
        RECT  92.796 60.24 92.88 60.264 ;
    END
  END q[500]
  PIN q[501]
    DIRECTION OUTPUT ;
    USE SIGNAL ;
    PORT
      LAYER M4 ;
        RECT  92.796 60.336 92.88 60.36 ;
    END
  END q[501]
  PIN q[502]
    DIRECTION OUTPUT ;
    USE SIGNAL ;
    PORT
      LAYER M4 ;
        RECT  92.796 60.432 92.88 60.456 ;
    END
  END q[502]
  PIN q[503]
    DIRECTION OUTPUT ;
    USE SIGNAL ;
    PORT
      LAYER M4 ;
        RECT  92.796 60.528 92.88 60.552 ;
    END
  END q[503]
  PIN q[504]
    DIRECTION OUTPUT ;
    USE SIGNAL ;
    PORT
      LAYER M4 ;
        RECT  92.796 60.624 92.88 60.648 ;
    END
  END q[504]
  PIN q[505]
    DIRECTION OUTPUT ;
    USE SIGNAL ;
    PORT
      LAYER M4 ;
        RECT  92.796 60.72 92.88 60.744 ;
    END
  END q[505]
  PIN q[506]
    DIRECTION OUTPUT ;
    USE SIGNAL ;
    PORT
      LAYER M4 ;
        RECT  92.796 60.816 92.88 60.84 ;
    END
  END q[506]
  PIN q[507]
    DIRECTION OUTPUT ;
    USE SIGNAL ;
    PORT
      LAYER M4 ;
        RECT  92.796 60.912 92.88 60.936 ;
    END
  END q[507]
  PIN q[508]
    DIRECTION OUTPUT ;
    USE SIGNAL ;
    PORT
      LAYER M4 ;
        RECT  92.796 61.008 92.88 61.032 ;
    END
  END q[508]
  PIN q[509]
    DIRECTION OUTPUT ;
    USE SIGNAL ;
    PORT
      LAYER M4 ;
        RECT  92.796 61.104 92.88 61.128 ;
    END
  END q[509]
  PIN q[50]
    DIRECTION OUTPUT ;
    USE SIGNAL ;
    PORT
      LAYER M4 ;
        RECT  92.796 24.72 92.88 24.744 ;
    END
  END q[50]
  PIN q[510]
    DIRECTION OUTPUT ;
    USE SIGNAL ;
    PORT
      LAYER M4 ;
        RECT  92.796 61.2 92.88 61.224 ;
    END
  END q[510]
  PIN q[511]
    DIRECTION OUTPUT ;
    USE SIGNAL ;
    PORT
      LAYER M4 ;
        RECT  92.796 61.296 92.88 61.32 ;
    END
  END q[511]
  PIN q[51]
    DIRECTION OUTPUT ;
    USE SIGNAL ;
    PORT
      LAYER M4 ;
        RECT  92.796 24.816 92.88 24.84 ;
    END
  END q[51]
  PIN q[52]
    DIRECTION OUTPUT ;
    USE SIGNAL ;
    PORT
      LAYER M4 ;
        RECT  92.796 24.912 92.88 24.936 ;
    END
  END q[52]
  PIN q[53]
    DIRECTION OUTPUT ;
    USE SIGNAL ;
    PORT
      LAYER M4 ;
        RECT  92.796 25.008 92.88 25.032 ;
    END
  END q[53]
  PIN q[54]
    DIRECTION OUTPUT ;
    USE SIGNAL ;
    PORT
      LAYER M4 ;
        RECT  92.796 25.104 92.88 25.128 ;
    END
  END q[54]
  PIN q[55]
    DIRECTION OUTPUT ;
    USE SIGNAL ;
    PORT
      LAYER M4 ;
        RECT  92.796 25.2 92.88 25.224 ;
    END
  END q[55]
  PIN q[56]
    DIRECTION OUTPUT ;
    USE SIGNAL ;
    PORT
      LAYER M4 ;
        RECT  92.796 25.296 92.88 25.32 ;
    END
  END q[56]
  PIN q[57]
    DIRECTION OUTPUT ;
    USE SIGNAL ;
    PORT
      LAYER M4 ;
        RECT  92.796 25.392 92.88 25.416 ;
    END
  END q[57]
  PIN q[58]
    DIRECTION OUTPUT ;
    USE SIGNAL ;
    PORT
      LAYER M4 ;
        RECT  92.796 25.488 92.88 25.512 ;
    END
  END q[58]
  PIN q[59]
    DIRECTION OUTPUT ;
    USE SIGNAL ;
    PORT
      LAYER M4 ;
        RECT  92.796 25.584 92.88 25.608 ;
    END
  END q[59]
  PIN q[5]
    DIRECTION OUTPUT ;
    USE SIGNAL ;
    PORT
      LAYER M4 ;
        RECT  92.796 20.4 92.88 20.424 ;
    END
  END q[5]
  PIN q[60]
    DIRECTION OUTPUT ;
    USE SIGNAL ;
    PORT
      LAYER M4 ;
        RECT  92.796 25.68 92.88 25.704 ;
    END
  END q[60]
  PIN q[61]
    DIRECTION OUTPUT ;
    USE SIGNAL ;
    PORT
      LAYER M4 ;
        RECT  92.796 25.776 92.88 25.8 ;
    END
  END q[61]
  PIN q[62]
    DIRECTION OUTPUT ;
    USE SIGNAL ;
    PORT
      LAYER M4 ;
        RECT  92.796 25.872 92.88 25.896 ;
    END
  END q[62]
  PIN q[63]
    DIRECTION OUTPUT ;
    USE SIGNAL ;
    PORT
      LAYER M4 ;
        RECT  92.796 25.968 92.88 25.992 ;
    END
  END q[63]
  PIN q[64]
    DIRECTION OUTPUT ;
    USE SIGNAL ;
    PORT
      LAYER M4 ;
        RECT  92.796 26.064 92.88 26.088 ;
    END
  END q[64]
  PIN q[65]
    DIRECTION OUTPUT ;
    USE SIGNAL ;
    PORT
      LAYER M4 ;
        RECT  92.796 26.16 92.88 26.184 ;
    END
  END q[65]
  PIN q[66]
    DIRECTION OUTPUT ;
    USE SIGNAL ;
    PORT
      LAYER M4 ;
        RECT  92.796 26.256 92.88 26.28 ;
    END
  END q[66]
  PIN q[67]
    DIRECTION OUTPUT ;
    USE SIGNAL ;
    PORT
      LAYER M4 ;
        RECT  92.796 26.352 92.88 26.376 ;
    END
  END q[67]
  PIN q[68]
    DIRECTION OUTPUT ;
    USE SIGNAL ;
    PORT
      LAYER M4 ;
        RECT  92.796 26.448 92.88 26.472 ;
    END
  END q[68]
  PIN q[69]
    DIRECTION OUTPUT ;
    USE SIGNAL ;
    PORT
      LAYER M4 ;
        RECT  92.796 26.544 92.88 26.568 ;
    END
  END q[69]
  PIN q[6]
    DIRECTION OUTPUT ;
    USE SIGNAL ;
    PORT
      LAYER M4 ;
        RECT  92.796 20.496 92.88 20.52 ;
    END
  END q[6]
  PIN q[70]
    DIRECTION OUTPUT ;
    USE SIGNAL ;
    PORT
      LAYER M4 ;
        RECT  92.796 26.64 92.88 26.664 ;
    END
  END q[70]
  PIN q[71]
    DIRECTION OUTPUT ;
    USE SIGNAL ;
    PORT
      LAYER M4 ;
        RECT  92.796 26.736 92.88 26.76 ;
    END
  END q[71]
  PIN q[72]
    DIRECTION OUTPUT ;
    USE SIGNAL ;
    PORT
      LAYER M4 ;
        RECT  92.796 26.832 92.88 26.856 ;
    END
  END q[72]
  PIN q[73]
    DIRECTION OUTPUT ;
    USE SIGNAL ;
    PORT
      LAYER M4 ;
        RECT  92.796 26.928 92.88 26.952 ;
    END
  END q[73]
  PIN q[74]
    DIRECTION OUTPUT ;
    USE SIGNAL ;
    PORT
      LAYER M4 ;
        RECT  92.796 27.024 92.88 27.048 ;
    END
  END q[74]
  PIN q[75]
    DIRECTION OUTPUT ;
    USE SIGNAL ;
    PORT
      LAYER M4 ;
        RECT  92.796 27.12 92.88 27.144 ;
    END
  END q[75]
  PIN q[76]
    DIRECTION OUTPUT ;
    USE SIGNAL ;
    PORT
      LAYER M4 ;
        RECT  92.796 27.216 92.88 27.24 ;
    END
  END q[76]
  PIN q[77]
    DIRECTION OUTPUT ;
    USE SIGNAL ;
    PORT
      LAYER M4 ;
        RECT  92.796 27.312 92.88 27.336 ;
    END
  END q[77]
  PIN q[78]
    DIRECTION OUTPUT ;
    USE SIGNAL ;
    PORT
      LAYER M4 ;
        RECT  92.796 27.408 92.88 27.432 ;
    END
  END q[78]
  PIN q[79]
    DIRECTION OUTPUT ;
    USE SIGNAL ;
    PORT
      LAYER M4 ;
        RECT  92.796 27.504 92.88 27.528 ;
    END
  END q[79]
  PIN q[7]
    DIRECTION OUTPUT ;
    USE SIGNAL ;
    PORT
      LAYER M4 ;
        RECT  92.796 20.592 92.88 20.616 ;
    END
  END q[7]
  PIN q[80]
    DIRECTION OUTPUT ;
    USE SIGNAL ;
    PORT
      LAYER M4 ;
        RECT  92.796 27.6 92.88 27.624 ;
    END
  END q[80]
  PIN q[81]
    DIRECTION OUTPUT ;
    USE SIGNAL ;
    PORT
      LAYER M4 ;
        RECT  92.796 27.696 92.88 27.72 ;
    END
  END q[81]
  PIN q[82]
    DIRECTION OUTPUT ;
    USE SIGNAL ;
    PORT
      LAYER M4 ;
        RECT  92.796 27.792 92.88 27.816 ;
    END
  END q[82]
  PIN q[83]
    DIRECTION OUTPUT ;
    USE SIGNAL ;
    PORT
      LAYER M4 ;
        RECT  92.796 27.888 92.88 27.912 ;
    END
  END q[83]
  PIN q[84]
    DIRECTION OUTPUT ;
    USE SIGNAL ;
    PORT
      LAYER M4 ;
        RECT  92.796 27.984 92.88 28.008 ;
    END
  END q[84]
  PIN q[85]
    DIRECTION OUTPUT ;
    USE SIGNAL ;
    PORT
      LAYER M4 ;
        RECT  92.796 28.08 92.88 28.104 ;
    END
  END q[85]
  PIN q[86]
    DIRECTION OUTPUT ;
    USE SIGNAL ;
    PORT
      LAYER M4 ;
        RECT  92.796 28.176 92.88 28.2 ;
    END
  END q[86]
  PIN q[87]
    DIRECTION OUTPUT ;
    USE SIGNAL ;
    PORT
      LAYER M4 ;
        RECT  92.796 28.272 92.88 28.296 ;
    END
  END q[87]
  PIN q[88]
    DIRECTION OUTPUT ;
    USE SIGNAL ;
    PORT
      LAYER M4 ;
        RECT  92.796 28.368 92.88 28.392 ;
    END
  END q[88]
  PIN q[89]
    DIRECTION OUTPUT ;
    USE SIGNAL ;
    PORT
      LAYER M4 ;
        RECT  92.796 28.464 92.88 28.488 ;
    END
  END q[89]
  PIN q[8]
    DIRECTION OUTPUT ;
    USE SIGNAL ;
    PORT
      LAYER M4 ;
        RECT  92.796 20.688 92.88 20.712 ;
    END
  END q[8]
  PIN q[90]
    DIRECTION OUTPUT ;
    USE SIGNAL ;
    PORT
      LAYER M4 ;
        RECT  92.796 28.56 92.88 28.584 ;
    END
  END q[90]
  PIN q[91]
    DIRECTION OUTPUT ;
    USE SIGNAL ;
    PORT
      LAYER M4 ;
        RECT  92.796 28.656 92.88 28.68 ;
    END
  END q[91]
  PIN q[92]
    DIRECTION OUTPUT ;
    USE SIGNAL ;
    PORT
      LAYER M4 ;
        RECT  92.796 28.752 92.88 28.776 ;
    END
  END q[92]
  PIN q[93]
    DIRECTION OUTPUT ;
    USE SIGNAL ;
    PORT
      LAYER M4 ;
        RECT  92.796 28.848 92.88 28.872 ;
    END
  END q[93]
  PIN q[94]
    DIRECTION OUTPUT ;
    USE SIGNAL ;
    PORT
      LAYER M4 ;
        RECT  92.796 28.944 92.88 28.968 ;
    END
  END q[94]
  PIN q[95]
    DIRECTION OUTPUT ;
    USE SIGNAL ;
    PORT
      LAYER M4 ;
        RECT  92.796 29.04 92.88 29.064 ;
    END
  END q[95]
  PIN q[96]
    DIRECTION OUTPUT ;
    USE SIGNAL ;
    PORT
      LAYER M4 ;
        RECT  92.796 35.28 92.88 35.304 ;
    END
  END q[96]
  PIN q[97]
    DIRECTION OUTPUT ;
    USE SIGNAL ;
    PORT
      LAYER M4 ;
        RECT  92.796 35.376 92.88 35.4 ;
    END
  END q[97]
  PIN q[98]
    DIRECTION OUTPUT ;
    USE SIGNAL ;
    PORT
      LAYER M4 ;
        RECT  92.796 35.472 92.88 35.496 ;
    END
  END q[98]
  PIN q[99]
    DIRECTION OUTPUT ;
    USE SIGNAL ;
    PORT
      LAYER M4 ;
        RECT  92.796 35.568 92.88 35.592 ;
    END
  END q[99]
  PIN q[9]
    DIRECTION OUTPUT ;
    USE SIGNAL ;
    PORT
      LAYER M4 ;
        RECT  92.796 20.784 92.88 20.808 ;
    END
  END q[9]
  PIN VDD
    DIRECTION INOUT ;
    USE POWER ;
    PORT
      LAYER M5 ;
        RECT  88.992 2.151 89.112 62.649 ;
        RECT  83.592 2.151 83.712 62.649 ;
        RECT  78.192 2.151 78.312 62.649 ;
        RECT  72.792 2.151 72.912 62.649 ;
        RECT  67.392 2.151 67.512 62.649 ;
        RECT  61.992 2.151 62.112 62.649 ;
        RECT  56.592 2.151 56.712 62.649 ;
        RECT  51.192 2.151 51.312 62.649 ;
        RECT  45.792 2.151 45.912 62.649 ;
        RECT  40.392 2.151 40.512 62.649 ;
        RECT  34.992 2.151 35.112 62.649 ;
        RECT  29.592 2.151 29.712 62.649 ;
        RECT  24.192 2.151 24.312 62.649 ;
        RECT  18.792 2.151 18.912 62.649 ;
        RECT  13.392 2.151 13.512 62.649 ;
        RECT  7.992 2.151 8.112 62.649 ;
        RECT  2.592 2.151 2.712 62.649 ;
    END
  END VDD
  PIN VSS
    DIRECTION INOUT ;
    USE GROUND ;
    PORT
      LAYER M5 ;
        RECT  88.8 2.137 88.92 62.663 ;
        RECT  83.4 2.137 83.52 62.663 ;
        RECT  78 2.137 78.12 62.663 ;
        RECT  72.6 2.137 72.72 62.663 ;
        RECT  67.2 2.137 67.32 62.663 ;
        RECT  61.8 2.137 61.92 62.663 ;
        RECT  56.4 2.137 56.52 62.663 ;
        RECT  51 2.137 51.12 62.663 ;
        RECT  45.6 2.137 45.72 62.663 ;
        RECT  40.2 2.137 40.32 62.663 ;
        RECT  34.8 2.137 34.92 62.663 ;
        RECT  29.4 2.137 29.52 62.663 ;
        RECT  24 2.137 24.12 62.663 ;
        RECT  18.6 2.137 18.72 62.663 ;
        RECT  13.2 2.137 13.32 62.663 ;
        RECT  7.8 2.137 7.92 62.663 ;
        RECT  2.4 2.137 2.52 62.663 ;
    END
  END VSS
  OBS
    LAYER RVTN ;
     RECT  2.16 2.16 90.72 2.295 ;
     RECT  2.16 2.565 90.72 2.835 ;
     RECT  2.16 3.105 90.72 3.375 ;
     RECT  2.16 3.645 90.72 3.915 ;
     RECT  2.16 4.185 90.72 4.455 ;
     RECT  2.16 4.725 90.72 4.995 ;
     RECT  2.16 5.265 90.72 5.535 ;
     RECT  2.16 5.805 90.72 6.075 ;
     RECT  2.16 6.345 90.72 6.615 ;
     RECT  2.16 6.885 90.72 7.155 ;
     RECT  2.16 7.425 90.72 7.695 ;
     RECT  2.16 7.965 90.72 8.235 ;
     RECT  2.16 8.505 90.72 8.775 ;
     RECT  2.16 9.045 90.72 9.315 ;
     RECT  2.16 9.585 90.72 9.855 ;
     RECT  2.16 10.125 90.72 10.395 ;
     RECT  2.16 10.665 90.72 10.935 ;
     RECT  2.16 11.205 90.72 11.475 ;
     RECT  2.16 11.745 90.72 12.015 ;
     RECT  2.16 12.285 90.72 12.555 ;
     RECT  2.16 12.825 90.72 13.095 ;
     RECT  2.16 13.365 90.72 13.635 ;
     RECT  2.16 13.905 90.72 14.175 ;
     RECT  2.16 14.445 90.72 14.715 ;
     RECT  2.16 14.985 90.72 15.255 ;
     RECT  2.16 15.525 90.72 15.795 ;
     RECT  2.16 16.065 90.72 16.335 ;
     RECT  2.16 16.605 90.72 16.875 ;
     RECT  2.16 17.145 90.72 17.415 ;
     RECT  2.16 17.685 90.72 17.955 ;
     RECT  2.16 18.225 90.72 18.495 ;
     RECT  2.16 18.765 90.72 19.035 ;
     RECT  2.16 19.305 90.72 19.575 ;
     RECT  2.16 19.845 90.72 20.115 ;
     RECT  2.16 20.385 90.72 20.655 ;
     RECT  2.16 20.925 90.72 21.195 ;
     RECT  2.16 21.465 90.72 21.735 ;
     RECT  2.16 22.005 90.72 22.275 ;
     RECT  2.16 22.545 90.72 22.815 ;
     RECT  2.16 23.085 90.72 23.355 ;
     RECT  2.16 23.625 90.72 23.895 ;
     RECT  2.16 24.165 90.72 24.435 ;
     RECT  2.16 24.705 90.72 24.975 ;
     RECT  2.16 25.245 90.72 25.515 ;
     RECT  2.16 25.785 90.72 26.055 ;
     RECT  2.16 26.325 90.72 26.595 ;
     RECT  2.16 26.865 90.72 27.135 ;
     RECT  2.16 27.405 90.72 27.675 ;
     RECT  2.16 27.945 90.72 28.215 ;
     RECT  2.16 28.485 90.72 28.755 ;
     RECT  2.16 29.025 90.72 29.295 ;
     RECT  2.16 29.565 90.72 29.835 ;
     RECT  2.16 30.105 90.72 30.375 ;
     RECT  2.16 30.645 90.72 30.915 ;
     RECT  2.16 31.185 90.72 31.455 ;
     RECT  2.16 31.725 90.72 31.995 ;
     RECT  2.16 32.265 90.72 32.535 ;
     RECT  2.16 32.805 90.72 33.075 ;
     RECT  2.16 33.345 90.72 33.615 ;
     RECT  2.16 33.885 90.72 34.155 ;
     RECT  2.16 34.425 90.72 34.695 ;
     RECT  2.16 34.965 90.72 35.235 ;
     RECT  2.16 35.505 90.72 35.775 ;
     RECT  2.16 36.045 90.72 36.315 ;
     RECT  2.16 36.585 90.72 36.855 ;
     RECT  2.16 37.125 90.72 37.395 ;
     RECT  2.16 37.665 90.72 37.935 ;
     RECT  2.16 38.205 90.72 38.475 ;
     RECT  2.16 38.745 90.72 39.015 ;
     RECT  2.16 39.285 90.72 39.555 ;
     RECT  2.16 39.825 90.72 40.095 ;
     RECT  2.16 40.365 90.72 40.635 ;
     RECT  2.16 40.905 90.72 41.175 ;
     RECT  2.16 41.445 90.72 41.715 ;
     RECT  2.16 41.985 90.72 42.255 ;
     RECT  2.16 42.525 90.72 42.795 ;
     RECT  2.16 43.065 90.72 43.335 ;
     RECT  2.16 43.605 90.72 43.875 ;
     RECT  2.16 44.145 90.72 44.415 ;
     RECT  2.16 44.685 90.72 44.955 ;
     RECT  2.16 45.225 90.72 45.495 ;
     RECT  2.16 45.765 90.72 46.035 ;
     RECT  2.16 46.305 90.72 46.575 ;
     RECT  2.16 46.845 90.72 47.115 ;
     RECT  2.16 47.385 90.72 47.655 ;
     RECT  2.16 47.925 90.72 48.195 ;
     RECT  2.16 48.465 90.72 48.735 ;
     RECT  2.16 49.005 90.72 49.275 ;
     RECT  2.16 49.545 90.72 49.815 ;
     RECT  2.16 50.085 90.72 50.355 ;
     RECT  2.16 50.625 90.72 50.895 ;
     RECT  2.16 51.165 90.72 51.435 ;
     RECT  2.16 51.705 90.72 51.975 ;
     RECT  2.16 52.245 90.72 52.515 ;
     RECT  2.16 52.785 90.72 53.055 ;
     RECT  2.16 53.325 90.72 53.595 ;
     RECT  2.16 53.865 90.72 54.135 ;
     RECT  2.16 54.405 90.72 54.675 ;
     RECT  2.16 54.945 90.72 55.215 ;
     RECT  2.16 55.485 90.72 55.755 ;
     RECT  2.16 56.025 90.72 56.295 ;
     RECT  2.16 56.565 90.72 56.835 ;
     RECT  2.16 57.105 90.72 57.375 ;
     RECT  2.16 57.645 90.72 57.915 ;
     RECT  2.16 58.185 90.72 58.455 ;
     RECT  2.16 58.725 90.72 58.995 ;
     RECT  2.16 59.265 90.72 59.535 ;
     RECT  2.16 59.805 90.72 60.075 ;
     RECT  2.16 60.345 90.72 60.615 ;
     RECT  2.16 60.885 90.72 61.155 ;
     RECT  2.16 61.425 90.72 61.695 ;
     RECT  2.16 61.965 90.72 62.235 ;
     RECT  2.16 62.505 90.72 62.64 ;
    LAYER RVTP ;
     RECT  2.16 2.295 90.72 2.565 ;
     RECT  2.16 2.835 90.72 3.105 ;
     RECT  2.16 3.375 90.72 3.645 ;
     RECT  2.16 3.915 90.72 4.185 ;
     RECT  2.16 4.455 90.72 4.725 ;
     RECT  2.16 4.995 90.72 5.265 ;
     RECT  2.16 5.535 90.72 5.805 ;
     RECT  2.16 6.075 90.72 6.345 ;
     RECT  2.16 6.615 90.72 6.885 ;
     RECT  2.16 7.155 90.72 7.425 ;
     RECT  2.16 7.695 90.72 7.965 ;
     RECT  2.16 8.235 90.72 8.505 ;
     RECT  2.16 8.775 90.72 9.045 ;
     RECT  2.16 9.315 90.72 9.585 ;
     RECT  2.16 9.855 90.72 10.125 ;
     RECT  2.16 10.395 90.72 10.665 ;
     RECT  2.16 10.935 90.72 11.205 ;
     RECT  2.16 11.475 90.72 11.745 ;
     RECT  2.16 12.015 90.72 12.285 ;
     RECT  2.16 12.555 90.72 12.825 ;
     RECT  2.16 13.095 90.72 13.365 ;
     RECT  2.16 13.635 90.72 13.905 ;
     RECT  2.16 14.175 90.72 14.445 ;
     RECT  2.16 14.715 90.72 14.985 ;
     RECT  2.16 15.255 90.72 15.525 ;
     RECT  2.16 15.795 90.72 16.065 ;
     RECT  2.16 16.335 90.72 16.605 ;
     RECT  2.16 16.875 90.72 17.145 ;
     RECT  2.16 17.415 90.72 17.685 ;
     RECT  2.16 17.955 90.72 18.225 ;
     RECT  2.16 18.495 90.72 18.765 ;
     RECT  2.16 19.035 90.72 19.305 ;
     RECT  2.16 19.575 90.72 19.845 ;
     RECT  2.16 20.115 90.72 20.385 ;
     RECT  2.16 20.655 90.72 20.925 ;
     RECT  2.16 21.195 90.72 21.465 ;
     RECT  2.16 21.735 90.72 22.005 ;
     RECT  2.16 22.275 90.72 22.545 ;
     RECT  2.16 22.815 90.72 23.085 ;
     RECT  2.16 23.355 90.72 23.625 ;
     RECT  2.16 23.895 90.72 24.165 ;
     RECT  2.16 24.435 90.72 24.705 ;
     RECT  2.16 24.975 90.72 25.245 ;
     RECT  2.16 25.515 90.72 25.785 ;
     RECT  2.16 26.055 90.72 26.325 ;
     RECT  2.16 26.595 90.72 26.865 ;
     RECT  2.16 27.135 90.72 27.405 ;
     RECT  2.16 27.675 90.72 27.945 ;
     RECT  2.16 28.215 90.72 28.485 ;
     RECT  2.16 28.755 90.72 29.025 ;
     RECT  2.16 29.295 90.72 29.565 ;
     RECT  2.16 29.835 90.72 30.105 ;
     RECT  2.16 30.375 90.72 30.645 ;
     RECT  2.16 30.915 90.72 31.185 ;
     RECT  2.16 31.455 90.72 31.725 ;
     RECT  2.16 31.995 90.72 32.265 ;
     RECT  2.16 32.535 90.72 32.805 ;
     RECT  2.16 33.075 90.72 33.345 ;
     RECT  2.16 33.615 90.72 33.885 ;
     RECT  2.16 34.155 90.72 34.425 ;
     RECT  2.16 34.695 90.72 34.965 ;
     RECT  2.16 35.235 90.72 35.505 ;
     RECT  2.16 35.775 90.72 36.045 ;
     RECT  2.16 36.315 90.72 36.585 ;
     RECT  2.16 36.855 90.72 37.125 ;
     RECT  2.16 37.395 90.72 37.665 ;
     RECT  2.16 37.935 90.72 38.205 ;
     RECT  2.16 38.475 90.72 38.745 ;
     RECT  2.16 39.015 90.72 39.285 ;
     RECT  2.16 39.555 90.72 39.825 ;
     RECT  2.16 40.095 90.72 40.365 ;
     RECT  2.16 40.635 90.72 40.905 ;
     RECT  2.16 41.175 90.72 41.445 ;
     RECT  2.16 41.715 90.72 41.985 ;
     RECT  2.16 42.255 90.72 42.525 ;
     RECT  2.16 42.795 90.72 43.065 ;
     RECT  2.16 43.335 90.72 43.605 ;
     RECT  2.16 43.875 90.72 44.145 ;
     RECT  2.16 44.415 90.72 44.685 ;
     RECT  2.16 44.955 90.72 45.225 ;
     RECT  2.16 45.495 90.72 45.765 ;
     RECT  2.16 46.035 90.72 46.305 ;
     RECT  2.16 46.575 90.72 46.845 ;
     RECT  2.16 47.115 90.72 47.385 ;
     RECT  2.16 47.655 90.72 47.925 ;
     RECT  2.16 48.195 90.72 48.465 ;
     RECT  2.16 48.735 90.72 49.005 ;
     RECT  2.16 49.275 90.72 49.545 ;
     RECT  2.16 49.815 90.72 50.085 ;
     RECT  2.16 50.355 90.72 50.625 ;
     RECT  2.16 50.895 90.72 51.165 ;
     RECT  2.16 51.435 90.72 51.705 ;
     RECT  2.16 51.975 90.72 52.245 ;
     RECT  2.16 52.515 90.72 52.785 ;
     RECT  2.16 53.055 90.72 53.325 ;
     RECT  2.16 53.595 90.72 53.865 ;
     RECT  2.16 54.135 90.72 54.405 ;
     RECT  2.16 54.675 90.72 54.945 ;
     RECT  2.16 55.215 90.72 55.485 ;
     RECT  2.16 55.755 90.72 56.025 ;
     RECT  2.16 56.295 90.72 56.565 ;
     RECT  2.16 56.835 90.72 57.105 ;
     RECT  2.16 57.375 90.72 57.645 ;
     RECT  2.16 57.915 90.72 58.185 ;
     RECT  2.16 58.455 90.72 58.725 ;
     RECT  2.16 58.995 90.72 59.265 ;
     RECT  2.16 59.535 90.72 59.805 ;
     RECT  2.16 60.075 90.72 60.345 ;
     RECT  2.16 60.615 90.72 60.885 ;
     RECT  2.16 61.155 90.72 61.425 ;
     RECT  2.16 61.695 90.72 61.965 ;
     RECT  2.16 62.235 90.72 62.505 ;
    LAYER M1 ;
     RECT  2.16 2.151 90.72 62.649 ;
    LAYER M2 ;
     RECT  0.031 51.408 0.103 51.426 ;
     RECT  0.103 51.408 0.131 51.498 ;
     RECT  0.103 2.61 0.139 2.628 ;
     RECT  0.103 14.652 0.139 14.67 ;
     RECT  0.103 18.54 0.139 18.558 ;
     RECT  0.103 24.786 0.139 25.038 ;
     RECT  0.103 30.726 0.139 30.978 ;
     RECT  0.103 32.31 0.139 33.03 ;
     RECT  0.139 18.54 0.175 19.26 ;
     RECT  0.103 20.088 0.175 20.106 ;
     RECT  0.139 26.37 0.175 26.388 ;
     RECT  0.139 30.582 0.175 30.978 ;
     RECT  0.139 31.932 0.175 33.03 ;
     RECT  0.103 39.141 0.175 39.888 ;
     RECT  0.103 40.644 0.175 40.662 ;
     RECT  0.175 26.37 0.211 26.928 ;
     RECT  0.103 27.882 0.211 28.98 ;
     RECT  0.175 30.582 0.211 33.03 ;
     RECT  0.103 34.902 0.211 34.92 ;
     RECT  0.175 18.432 0.239 20.106 ;
     RECT  0.139 47.394 0.239 47.412 ;
     RECT  0.211 30.384 0.247 33.03 ;
     RECT  0.175 42.804 0.247 42.822 ;
     RECT  0.175 39.06 0.275 40.662 ;
     RECT  0.103 17.46 0.283 17.478 ;
     RECT  0.175 5.166 0.347 5.184 ;
     RECT  0.139 14.301 0.347 14.67 ;
     RECT  0.211 15.426 0.347 15.444 ;
     RECT  0.139 24.642 0.347 25.038 ;
     RECT  0.275 39.87 0.347 40.662 ;
     RECT  0.347 14.382 0.383 14.472 ;
     RECT  0.383 14.454 0.419 14.472 ;
     RECT  0.247 42.732 0.499 42.822 ;
     RECT  0.103 10.71 0.535 11.43 ;
     RECT  0.103 22.05 0.535 22.068 ;
     RECT  0.211 25.83 0.535 26.928 ;
     RECT  0.211 27.684 0.535 28.98 ;
     RECT  0.211 34.74 0.535 34.92 ;
     RECT  0.499 42.696 0.535 42.822 ;
     RECT  0.347 25.02 1.147 25.038 ;
     RECT  0.247 30.15 1.175 33.03 ;
     RECT  0.031 55.692 1.723 55.71 ;
     RECT  1.723 55.458 1.759 55.71 ;
     RECT  1.147 56.502 1.759 56.52 ;
     RECT  0.139 2.61 2.16 3.096 ;
     RECT  0.535 7.776 2.16 7.794 ;
     RECT  0.535 10.71 2.16 11.772 ;
     RECT  0.535 15.534 2.16 15.552 ;
     RECT  0.283 17.352 2.16 17.478 ;
     RECT  0.239 18.432 2.16 19.908 ;
     RECT  0.535 22.05 2.16 22.104 ;
     RECT  1.147 24.642 2.16 25.038 ;
     RECT  0.535 25.83 2.16 29.052 ;
     RECT  1.175 30.15 2.16 30.87 ;
     RECT  1.175 31.698 2.16 33.03 ;
     RECT  0.535 34.74 2.16 35.496 ;
     RECT  0.103 36.36 2.16 36.846 ;
     RECT  0.535 37.602 2.16 37.62 ;
     RECT  0.275 39.06 2.16 39.078 ;
     RECT  0.347 39.87 2.16 40.32 ;
     RECT  0.535 41.958 2.16 43.164 ;
     RECT  0.535 45 2.16 45.018 ;
     RECT  0.103 45.81 2.16 45.828 ;
     RECT  0.103 46.62 2.16 46.638 ;
     RECT  0.535 47.736 2.16 47.754 ;
     RECT  0.131 51.48 2.16 51.498 ;
     RECT  1.759 55.458 2.16 56.52 ;
     RECT  2.16 2.151 2.551 62.649 ;
     RECT  2.551 2.106 2.831 62.649 ;
     RECT  2.831 2.151 85.315 62.649 ;
     RECT  85.315 2.151 86.675 62.694 ;
     RECT  86.675 2.151 88.123 62.649 ;
     RECT  88.123 2.151 88.799 62.694 ;
     RECT  88.799 2.151 89.563 62.649 ;
     RECT  89.563 2.151 90.383 62.694 ;
     RECT  90.383 2.151 90.72 62.649 ;
     RECT  90.72 7.326 91.247 62.424 ;
     RECT  91.247 23.166 91.499 62.424 ;
     RECT  91.499 23.166 91.571 62.334 ;
     RECT  91.571 23.166 91.643 62.154 ;
     RECT  91.643 23.166 91.715 62.064 ;
     RECT  91.247 11.646 91.751 22.302 ;
     RECT  91.715 23.166 91.751 39.474 ;
     RECT  91.715 40.644 91.751 57.024 ;
     RECT  91.715 57.816 91.751 60.804 ;
     RECT  91.715 62.046 91.751 62.064 ;
     RECT  91.247 7.326 91.787 10.854 ;
     RECT  91.751 13.986 91.787 18.288 ;
     RECT  91.751 23.166 91.787 23.31 ;
     RECT  91.751 25.758 91.787 29.826 ;
     RECT  91.751 31.086 91.787 38.736 ;
     RECT  91.751 40.878 91.787 53.55 ;
     RECT  91.751 56.466 91.787 56.934 ;
     RECT  91.751 11.646 91.823 13.014 ;
     RECT  91.823 11.646 91.859 12.618 ;
     RECT  91.859 11.646 91.895 11.934 ;
     RECT  91.787 7.704 91.931 10.854 ;
     RECT  91.931 9.018 92.003 10.854 ;
     RECT  92.003 9.09 92.507 10.854 ;
     RECT  91.931 7.704 92.543 8.154 ;
     RECT  92.543 7.704 92.579 7.839 ;
     RECT  92.579 7.821 92.615 7.839 ;
     RECT  91.787 15.696 92.651 18.288 ;
     RECT  91.751 24.138 92.687 24.498 ;
     RECT  92.507 9.486 92.723 10.854 ;
     RECT  91.751 19.656 92.723 22.302 ;
     RECT  91.787 25.758 92.723 28.944 ;
     RECT  91.787 31.086 92.723 38.466 ;
     RECT  91.787 40.878 92.723 43.83 ;
     RECT  91.787 49.986 92.723 53.55 ;
     RECT  92.723 10.206 92.759 10.854 ;
     RECT  92.651 15.966 92.759 18.288 ;
     RECT  92.723 20.124 92.759 22.302 ;
     RECT  91.787 29.736 92.759 29.826 ;
     RECT  92.723 31.086 92.759 35.694 ;
     RECT  92.723 36.792 92.759 38.394 ;
     RECT  91.787 45.81 92.759 47.754 ;
     RECT  92.723 50.166 92.759 51.084 ;
     RECT  92.723 52.146 92.759 53.55 ;
     RECT  91.787 56.466 92.759 56.754 ;
     RECT  91.751 60.318 92.759 60.804 ;
     RECT  92.759 10.296 92.795 10.854 ;
     RECT  91.895 11.646 92.795 11.664 ;
     RECT  91.787 13.986 92.795 14.742 ;
     RECT  92.759 15.966 92.795 15.984 ;
     RECT  92.759 16.956 92.795 18.288 ;
     RECT  92.759 20.286 92.795 22.302 ;
     RECT  91.787 23.292 92.795 23.31 ;
     RECT  92.687 24.138 92.795 24.156 ;
     RECT  92.723 25.794 92.795 28.944 ;
     RECT  92.759 29.736 92.795 29.754 ;
     RECT  92.759 31.806 92.795 31.824 ;
     RECT  92.759 32.58 92.795 35.694 ;
     RECT  92.759 36.792 92.795 36.81 ;
     RECT  92.759 38.106 92.795 38.124 ;
     RECT  92.723 40.878 92.795 42.129 ;
     RECT  92.723 42.966 92.795 43.83 ;
     RECT  91.787 44.586 92.795 44.874 ;
     RECT  92.759 46.818 92.795 47.034 ;
     RECT  91.787 48.546 92.795 49.194 ;
     RECT  92.759 52.416 92.795 53.55 ;
     RECT  91.751 54.306 92.795 55.134 ;
     RECT  92.759 56.466 92.795 56.484 ;
     RECT  91.751 58.194 92.795 58.212 ;
     RECT  92.759 60.786 92.795 60.804 ;
     RECT  90.72 5.976 92.831 6.534 ;
     RECT  92.795 10.296 92.831 10.386 ;
     RECT  92.831 5.976 92.867 5.994 ;
     RECT  92.831 10.368 92.867 10.386 ;
     RECT  92.767 13.176 92.867 13.194 ;
    LAYER M3 ;
     RECT  2.556 2.101 2.826 2.143 ;
     RECT  2.415 2.143 2.826 2.227 ;
     RECT  2.34 2.227 2.862 2.371 ;
     RECT  7.815 2.143 7.905 2.413 ;
     RECT  13.215 2.143 13.305 2.413 ;
     RECT  18.615 2.143 18.705 2.413 ;
     RECT  24.015 2.143 24.105 2.413 ;
     RECT  29.415 2.143 29.505 2.413 ;
     RECT  34.815 2.143 34.905 2.413 ;
     RECT  40.215 2.143 40.305 2.413 ;
     RECT  45.615 2.143 45.705 2.413 ;
     RECT  51.015 2.143 51.105 2.413 ;
     RECT  56.415 2.143 56.505 2.413 ;
     RECT  61.815 2.143 61.905 2.413 ;
     RECT  67.215 2.143 67.305 2.413 ;
     RECT  72.615 2.143 72.705 2.413 ;
     RECT  78.015 2.143 78.105 2.413 ;
     RECT  83.415 2.143 83.505 2.413 ;
     RECT  88.815 2.143 88.905 2.413 ;
     RECT  4.032 2.605 4.05 2.641 ;
     RECT  5.508 2.371 5.526 2.641 ;
     RECT  4.032 2.641 4.698 2.725 ;
     RECT  5.472 2.641 5.526 2.725 ;
     RECT  4.032 2.725 5.526 2.731 ;
     RECT  4.032 2.731 5.778 2.767 ;
     RECT  2.34 2.371 3.042 2.803 ;
     RECT  3.96 2.767 5.778 2.803 ;
     RECT  2.34 2.803 5.778 2.813 ;
     RECT  6.588 2.803 6.606 2.861 ;
     RECT  0.108 2.605 0.126 3.073 ;
     RECT  2.34 2.813 5.598 3.145 ;
     RECT  6.624 3.181 6.858 3.541 ;
     RECT  13.215 2.413 13.497 3.577 ;
     RECT  6.624 3.541 7.074 3.649 ;
     RECT  7.815 2.413 8.097 3.649 ;
     RECT  9.972 3.541 9.99 3.649 ;
     RECT  12.816 3.577 13.497 3.649 ;
     RECT  9.9 3.649 9.99 3.677 ;
     RECT  2.304 3.145 5.598 3.721 ;
     RECT  6.624 3.649 8.097 3.721 ;
     RECT  0.108 3.073 0.162 3.725 ;
     RECT  9.9 3.677 9.918 3.839 ;
     RECT  12.24 3.649 13.497 3.883 ;
     RECT  9.756 3.847 9.774 3.917 ;
     RECT  12.06 3.883 13.497 3.917 ;
     RECT  14.94 3.811 14.958 4.189 ;
     RECT  14.904 4.189 14.958 4.261 ;
     RECT  16.596 4.189 16.614 4.261 ;
     RECT  2.304 3.721 8.19 4.267 ;
     RECT  20.592 4.261 20.61 4.379 ;
     RECT  14.904 4.261 15.282 4.387 ;
     RECT  16.38 4.261 16.614 4.387 ;
     RECT  0.144 3.725 0.162 4.397 ;
     RECT  2.268 4.267 8.19 4.523 ;
     RECT  2.304 4.523 8.19 4.531 ;
     RECT  9.108 3.991 9.666 4.531 ;
     RECT  18.615 2.413 18.897 4.531 ;
     RECT  14.904 4.387 16.614 4.555 ;
     RECT  11.052 3.811 11.07 4.621 ;
     RECT  18.252 4.531 18.897 4.621 ;
     RECT  2.304 4.531 9.666 4.693 ;
     RECT  10.836 4.621 11.07 4.693 ;
     RECT  12.06 3.917 12.258 4.693 ;
     RECT  17.532 4.621 18.897 4.729 ;
     RECT  24.015 2.413 24.297 4.729 ;
     RECT  13.215 3.917 13.497 4.801 ;
     RECT  14.76 4.555 16.614 4.801 ;
     RECT  17.532 4.729 19.566 4.801 ;
     RECT  21.636 4.531 21.834 4.801 ;
     RECT  22.716 4.531 22.734 4.801 ;
     RECT  24.015 4.729 24.822 4.801 ;
     RECT  13.068 4.801 13.497 4.891 ;
     RECT  14.256 4.801 16.614 4.891 ;
     RECT  23.508 4.801 24.822 4.919 ;
     RECT  13.068 4.891 16.614 4.927 ;
     RECT  34.815 2.413 35.097 4.927 ;
     RECT  2.304 4.693 12.258 4.963 ;
     RECT  12.996 4.927 16.614 4.963 ;
     RECT  17.532 4.801 19.638 5.071 ;
     RECT  21.636 4.801 22.734 5.071 ;
     RECT  23.508 4.919 24.678 5.071 ;
     RECT  26.748 4.729 26.838 5.071 ;
     RECT  28.008 4.621 28.026 5.071 ;
     RECT  29.415 2.413 29.697 5.071 ;
     RECT  0.18 5.131 0.198 5.161 ;
     RECT  2.304 4.963 16.614 5.161 ;
     RECT  17.496 5.071 19.638 5.161 ;
     RECT  20.448 4.495 20.466 5.161 ;
     RECT  0.18 5.161 0.342 5.189 ;
     RECT  34.092 4.927 35.097 5.189 ;
     RECT  0.324 5.189 0.342 5.261 ;
     RECT  2.304 5.161 20.466 5.269 ;
     RECT  21.636 5.071 24.678 5.269 ;
     RECT  2.304 5.269 24.678 5.305 ;
     RECT  25.596 5.071 25.902 5.341 ;
     RECT  26.748 5.071 28.026 5.341 ;
     RECT  29.412 5.071 30.006 5.341 ;
     RECT  33.912 5.305 34.074 5.341 ;
     RECT  34.815 5.189 35.097 5.341 ;
     RECT  2.232 5.305 24.678 5.357 ;
     RECT  40.215 2.413 40.497 5.431 ;
     RECT  25.596 5.341 28.026 5.495 ;
     RECT  34.815 5.341 35.37 5.495 ;
     RECT  28.944 5.341 30.006 5.503 ;
     RECT  30.78 5.431 30.798 5.503 ;
     RECT  32.544 5.431 32.562 5.575 ;
     RECT  28.944 5.503 30.798 5.611 ;
     RECT  32.04 5.575 32.562 5.611 ;
     RECT  27.72 5.495 28.026 5.701 ;
     RECT  2.268 5.357 24.678 5.765 ;
     RECT  40.215 5.431 40.554 5.845 ;
     RECT  21.528 5.765 24.678 5.881 ;
     RECT  38.088 5.845 38.106 5.881 ;
     RECT  40.176 5.845 40.554 5.881 ;
     RECT  51.015 2.413 51.297 5.881 ;
     RECT  88.815 2.413 89.097 5.881 ;
     RECT  90.108 5.845 90.45 5.881 ;
     RECT  2.268 5.765 20.754 5.933 ;
     RECT  40.176 5.881 41.274 5.971 ;
     RECT  90.108 5.881 90.558 5.971 ;
     RECT  43.02 5.881 43.038 5.999 ;
     RECT  21.528 5.881 24.786 6.007 ;
     RECT  25.596 5.495 26.946 6.007 ;
     RECT  47.664 5.881 47.682 6.035 ;
     RECT  37.296 5.737 37.314 6.043 ;
     RECT  38.088 5.881 38.178 6.043 ;
     RECT  21.528 6.007 26.946 6.071 ;
     RECT  28.944 5.611 32.562 6.079 ;
     RECT  49.32 5.881 49.338 6.079 ;
     RECT  50.616 5.881 51.297 6.079 ;
     RECT  2.304 5.933 20.754 6.107 ;
     RECT  45.615 2.413 45.897 6.115 ;
     RECT  88.488 5.881 89.097 6.115 ;
     RECT  89.892 5.971 90.558 6.115 ;
     RECT  27.72 5.701 28.098 6.151 ;
     RECT  28.908 6.079 32.562 6.151 ;
     RECT  33.84 5.341 34.074 6.151 ;
     RECT  37.296 6.043 38.178 6.151 ;
     RECT  40.176 5.971 41.922 6.151 ;
     RECT  48.456 5.881 48.474 6.151 ;
     RECT  49.32 6.079 49.878 6.151 ;
     RECT  50.616 6.079 51.714 6.151 ;
     RECT  18.612 6.107 20.754 6.179 ;
     RECT  55.548 6.151 55.566 6.235 ;
     RECT  27.72 6.151 32.778 6.241 ;
     RECT  33.624 6.151 34.074 6.241 ;
     RECT  67.215 2.413 67.497 6.241 ;
     RECT  35.856 5.845 36.018 6.269 ;
     RECT  55.332 6.235 55.566 6.269 ;
     RECT  2.304 6.107 17.838 6.275 ;
     RECT  63.288 6.235 63.306 6.275 ;
     RECT  59.292 6.151 59.31 6.305 ;
     RECT  27.72 6.241 34.074 6.349 ;
     RECT  34.815 5.495 35.097 6.349 ;
     RECT  0.108 6.283 0.126 6.379 ;
     RECT  27.72 6.349 35.097 6.385 ;
     RECT  37.296 6.151 38.214 6.385 ;
     RECT  21.6 6.071 26.946 6.413 ;
     RECT  22.68 6.413 26.946 6.421 ;
     RECT  27.72 6.385 35.406 6.421 ;
     RECT  39.348 6.349 39.366 6.421 ;
     RECT  40.14 6.151 41.922 6.421 ;
     RECT  43.956 5.971 43.974 6.421 ;
     RECT  45.504 6.115 45.897 6.421 ;
     RECT  48.456 6.151 51.858 6.421 ;
     RECT  54.144 6.151 54.162 6.421 ;
     RECT  92.844 5.971 92.862 6.511 ;
     RECT  21.6 6.413 21.906 6.539 ;
     RECT  66.708 6.241 67.497 6.539 ;
     RECT  36.324 6.349 36.558 6.547 ;
     RECT  37.296 6.385 38.394 6.547 ;
     RECT  39.348 6.421 42.714 6.547 ;
     RECT  45.36 6.421 45.897 6.547 ;
     RECT  86.652 6.421 86.67 6.547 ;
     RECT  88.488 6.115 90.558 6.547 ;
     RECT  36.324 6.547 42.714 6.562 ;
     RECT  65.952 6.241 65.97 6.575 ;
     RECT  53.64 6.421 54.162 6.583 ;
     RECT  55.332 6.269 55.494 6.583 ;
     RECT  83.415 2.413 83.697 6.583 ;
     RECT  0.108 6.379 0.162 6.605 ;
     RECT  43.848 6.421 43.974 6.655 ;
     RECT  45 6.547 45.897 6.655 ;
     RECT  47.232 6.241 47.25 6.655 ;
     RECT  53.64 6.583 55.494 6.655 ;
     RECT  56.415 2.413 56.697 6.655 ;
     RECT  68.868 6.241 68.886 6.655 ;
     RECT  48.348 6.421 51.858 6.691 ;
     RECT  52.74 6.241 52.758 6.691 ;
     RECT  56.412 6.655 56.697 6.691 ;
     RECT  0.144 6.605 0.162 6.701 ;
     RECT  48.348 6.691 52.758 6.719 ;
     RECT  18.615 6.179 20.754 6.781 ;
     RECT  38.772 6.562 42.714 6.781 ;
     RECT  56.268 6.691 56.697 6.781 ;
     RECT  53.496 6.655 55.494 6.809 ;
     RECT  49.752 6.719 52.758 6.811 ;
     RECT  53.496 6.809 55.35 6.811 ;
     RECT  45 6.655 47.25 6.817 ;
     RECT  63.828 6.781 63.846 6.817 ;
     RECT  68.724 6.655 68.886 6.817 ;
     RECT  36.324 6.562 37.962 6.845 ;
     RECT  49.752 6.811 55.35 6.845 ;
     RECT  68.292 6.817 68.886 6.845 ;
     RECT  43.848 6.655 44.01 6.889 ;
     RECT  44.82 6.817 47.25 6.889 ;
     RECT  61.815 2.413 62.097 6.925 ;
     RECT  86.652 6.547 90.558 6.925 ;
     RECT  10.512 6.275 17.838 6.961 ;
     RECT  18.615 6.781 20.826 6.961 ;
     RECT  43.848 6.889 47.25 6.961 ;
     RECT  63.828 6.817 64.422 6.961 ;
     RECT  59.544 6.583 59.778 7.079 ;
     RECT  43.848 6.961 47.358 7.087 ;
     RECT  67.215 6.539 67.497 7.087 ;
     RECT  68.292 6.845 68.31 7.087 ;
     RECT  36.324 6.845 37.71 7.151 ;
     RECT  38.772 6.781 42.786 7.189 ;
     RECT  43.812 7.087 47.358 7.189 ;
     RECT  48.348 6.719 49.014 7.195 ;
     RECT  58.032 6.691 58.05 7.195 ;
     RECT  65.52 6.817 65.538 7.195 ;
     RECT  10.512 6.961 20.826 7.231 ;
     RECT  21.6 6.539 21.834 7.231 ;
     RECT  22.68 6.421 35.406 7.231 ;
     RECT  48.276 7.195 49.014 7.231 ;
     RECT  56.268 6.781 57.042 7.231 ;
     RECT  57.816 7.195 58.05 7.231 ;
     RECT  63.828 6.961 64.674 7.231 ;
     RECT  65.412 7.195 65.538 7.231 ;
     RECT  86.652 6.925 90.594 7.231 ;
     RECT  56.124 7.231 57.042 7.321 ;
     RECT  57.816 7.231 58.77 7.321 ;
     RECT  72.615 2.413 72.897 7.321 ;
     RECT  83.376 6.583 83.697 7.321 ;
     RECT  86.544 7.231 90.594 7.321 ;
     RECT  38.772 7.189 47.358 7.349 ;
     RECT  48.132 7.231 49.014 7.349 ;
     RECT  63.828 7.231 65.538 7.349 ;
     RECT  85.68 7.051 85.698 7.373 ;
     RECT  60.552 7.231 60.786 7.385 ;
     RECT  76.968 7.231 76.986 7.385 ;
     RECT  10.476 7.231 21.834 7.387 ;
     RECT  22.644 7.231 35.406 7.387 ;
     RECT  61.815 6.925 62.55 7.387 ;
     RECT  2.304 6.275 9.702 7.393 ;
     RECT  10.476 7.387 35.406 7.393 ;
     RECT  65.016 7.349 65.538 7.393 ;
     RECT  82.044 7.123 82.062 7.393 ;
     RECT  82.8 7.321 83.697 7.393 ;
     RECT  2.304 7.393 35.406 7.421 ;
     RECT  12.78 7.421 35.406 7.429 ;
     RECT  36.324 7.151 37.674 7.429 ;
     RECT  38.772 7.349 43.578 7.465 ;
     RECT  61.815 7.387 63.018 7.501 ;
     RECT  63.828 7.349 64.242 7.501 ;
     RECT  78.015 2.413 78.297 7.579 ;
     RECT  67.215 7.087 68.31 7.591 ;
     RECT  69.156 7.231 69.174 7.591 ;
     RECT  76.032 7.231 76.05 7.591 ;
     RECT  86.472 7.321 90.594 7.591 ;
     RECT  12.78 7.429 37.674 7.619 ;
     RECT  61.815 7.501 64.242 7.619 ;
     RECT  0.324 7.531 0.342 7.627 ;
     RECT  44.352 7.349 47.358 7.627 ;
     RECT  48.132 7.349 48.906 7.627 ;
     RECT  78.015 7.579 78.354 7.627 ;
     RECT  79.2 7.051 79.218 7.627 ;
     RECT  49.752 6.845 55.314 7.655 ;
     RECT  61.815 7.619 64.098 7.655 ;
     RECT  67.215 7.591 69.174 7.655 ;
     RECT  15.696 7.619 36.558 7.661 ;
     RECT  56.124 7.321 58.77 7.663 ;
     RECT  76.032 7.591 76.194 7.663 ;
     RECT  78.015 7.627 79.218 7.664 ;
     RECT  56.088 7.663 58.77 7.699 ;
     RECT  59.544 7.079 59.634 7.699 ;
     RECT  92.808 6.511 92.862 7.699 ;
     RECT  56.088 7.699 59.634 7.727 ;
     RECT  68.292 7.655 69.03 7.727 ;
     RECT  61.815 7.655 64.062 7.735 ;
     RECT  72.615 7.321 73.494 7.735 ;
     RECT  0.144 7.627 0.342 7.771 ;
     RECT  38.592 7.465 43.578 7.771 ;
     RECT  53.064 7.655 55.314 7.771 ;
     RECT  56.088 7.727 57.33 7.771 ;
     RECT  67.215 7.655 67.497 7.771 ;
     RECT  71.244 6.691 71.262 7.771 ;
     RECT  72.108 7.735 73.494 7.771 ;
     RECT  75.78 7.663 76.194 7.771 ;
     RECT  82.044 7.393 83.697 7.771 ;
     RECT  86.472 7.591 90.63 7.771 ;
     RECT  91.764 7.321 91.782 7.771 ;
     RECT  92.556 7.699 92.862 7.771 ;
     RECT  49.896 7.655 52.29 7.799 ;
     RECT  86.472 7.771 90.702 7.816 ;
     RECT  71.244 7.771 73.494 7.861 ;
     RECT  81.18 7.699 81.198 7.861 ;
     RECT  12.78 7.619 14.958 7.889 ;
     RECT  53.064 7.771 57.33 7.889 ;
     RECT  80.964 7.861 81.198 7.889 ;
     RECT  86.472 7.816 90.774 7.901 ;
     RECT  58.068 7.727 59.634 7.963 ;
     RECT  67.212 7.771 67.497 7.963 ;
     RECT  70.776 7.861 73.674 7.969 ;
     RECT  75.312 7.771 76.194 7.969 ;
     RECT  14.616 7.889 14.958 7.997 ;
     RECT  68.292 7.727 68.958 7.997 ;
     RECT  67.176 7.963 67.497 8.005 ;
     RECT  82.044 7.771 83.826 8.005 ;
     RECT  86.472 7.901 90.666 8.005 ;
     RECT  37.332 7.619 37.674 8.041 ;
     RECT  38.556 7.771 43.578 8.041 ;
     RECT  37.332 8.041 43.578 8.159 ;
     RECT  58.068 7.963 60.102 8.159 ;
     RECT  65.016 7.393 65.718 8.159 ;
     RECT  79.452 8.041 79.686 8.167 ;
     RECT  80.964 7.889 81.054 8.167 ;
     RECT  82.044 8.005 83.898 8.167 ;
     RECT  58.068 8.159 59.742 8.195 ;
     RECT  79.452 8.167 81.054 8.195 ;
     RECT  2.304 7.421 12.042 8.203 ;
     RECT  12.78 7.889 13.734 8.203 ;
     RECT  70.776 7.969 76.194 8.239 ;
     RECT  65.016 8.159 65.574 8.275 ;
     RECT  70.704 8.239 76.194 8.275 ;
     RECT  38.52 8.159 43.578 8.311 ;
     RECT  44.352 7.627 48.906 8.311 ;
     RECT  78.015 7.664 78.606 8.311 ;
     RECT  82.044 8.167 84.078 8.311 ;
     RECT  85.464 7.621 85.482 8.311 ;
     RECT  70.452 8.275 76.194 8.401 ;
     RECT  77.472 8.311 78.606 8.401 ;
     RECT  68.58 7.997 68.958 8.429 ;
     RECT  14.688 7.997 14.958 8.465 ;
     RECT  15.696 7.661 36.522 8.465 ;
     RECT  38.52 8.311 48.906 8.465 ;
     RECT  54.108 7.889 57.33 8.465 ;
     RECT  14.76 8.465 14.958 8.473 ;
     RECT  15.696 8.465 16.938 8.473 ;
     RECT  17.82 8.465 36.522 8.473 ;
     RECT  37.332 8.159 37.638 8.473 ;
     RECT  60.984 7.735 64.062 8.473 ;
     RECT  17.82 8.473 37.638 8.525 ;
     RECT  38.52 8.465 47.79 8.525 ;
     RECT  14.76 8.473 16.938 8.537 ;
     RECT  55.224 8.465 57.33 8.539 ;
     RECT  58.068 8.195 58.266 8.539 ;
     RECT  70.452 8.401 76.302 8.539 ;
     RECT  77.472 8.401 78.714 8.539 ;
     RECT  16.524 8.537 16.938 8.573 ;
     RECT  55.224 8.539 58.266 8.573 ;
     RECT  68.652 8.429 68.958 8.573 ;
     RECT  53.064 7.889 53.298 8.581 ;
     RECT  60.912 8.473 64.062 8.581 ;
     RECT  64.944 8.275 65.574 8.581 ;
     RECT  69.732 8.539 76.302 8.581 ;
     RECT  77.256 8.539 78.714 8.581 ;
     RECT  82.044 8.311 85.554 8.581 ;
     RECT  86.328 8.005 90.666 8.581 ;
     RECT  69.732 8.581 78.714 8.699 ;
     RECT  68.652 8.573 68.778 8.735 ;
     RECT  52.704 8.581 53.298 8.743 ;
     RECT  54.108 8.465 54.27 8.743 ;
     RECT  66.492 8.005 67.497 8.743 ;
     RECT  79.56 8.195 81.054 8.815 ;
     RECT  82.044 8.581 90.666 8.815 ;
     RECT  52.704 8.743 54.27 8.851 ;
     RECT  48.672 8.465 48.906 8.875 ;
     RECT  38.556 8.525 47.79 8.879 ;
     RECT  69.732 8.699 78.57 8.879 ;
     RECT  2.304 8.203 13.734 8.923 ;
     RECT  79.56 8.815 90.666 8.923 ;
     RECT  48.672 8.875 48.942 8.941 ;
     RECT  49.896 7.799 51.93 8.941 ;
     RECT  52.668 8.851 54.27 8.941 ;
     RECT  33.444 8.525 37.638 8.969 ;
     RECT  79.488 8.923 90.666 8.969 ;
     RECT  45.108 8.879 47.79 9.005 ;
     RECT  79.56 8.969 90.666 9.005 ;
     RECT  37.584 8.969 37.638 9.013 ;
     RECT  79.632 9.005 90.666 9.019 ;
     RECT  59.184 8.195 59.742 9.049 ;
     RECT  60.912 8.581 65.574 9.049 ;
     RECT  59.184 9.049 59.886 9.067 ;
     RECT  60.804 9.049 65.574 9.067 ;
     RECT  57.744 8.573 58.266 9.085 ;
     RECT  59.184 9.067 65.574 9.085 ;
     RECT  0.144 7.771 0.558 9.101 ;
     RECT  47.304 9.005 47.79 9.101 ;
     RECT  57.744 9.085 65.574 9.115 ;
     RECT  66.384 8.743 67.497 9.115 ;
     RECT  48.672 8.941 54.27 9.211 ;
     RECT  33.444 8.969 36.81 9.239 ;
     RECT  38.556 8.879 44.334 9.239 ;
     RECT  16.56 8.573 16.938 9.247 ;
     RECT  17.82 8.525 32.706 9.247 ;
     RECT  37.584 9.013 37.674 9.247 ;
     RECT  38.556 9.239 41.598 9.247 ;
     RECT  33.444 9.239 36.666 9.275 ;
     RECT  0.144 9.101 0.306 9.293 ;
     RECT  14.76 8.537 15.786 9.307 ;
     RECT  16.56 9.247 32.706 9.307 ;
     RECT  0.288 9.293 0.306 9.341 ;
     RECT  14.76 9.307 32.706 9.347 ;
     RECT  2.268 8.923 13.734 9.355 ;
     RECT  14.76 9.347 15.786 9.355 ;
     RECT  47.412 9.101 47.79 9.355 ;
     RECT  48.6 9.211 54.27 9.355 ;
     RECT  57.744 9.115 67.497 9.355 ;
     RECT  16.524 9.347 32.706 9.391 ;
     RECT  33.444 9.275 36.486 9.391 ;
     RECT  55.224 8.573 56.898 9.391 ;
     RECT  57.744 9.355 67.878 9.391 ;
     RECT  68.652 8.735 68.742 9.391 ;
     RECT  79.632 9.019 90.702 9.391 ;
     RECT  91.764 7.771 92.862 9.391 ;
     RECT  2.268 9.355 15.786 9.419 ;
     RECT  55.224 9.391 68.742 9.481 ;
     RECT  71.82 8.879 78.57 9.517 ;
     RECT  69.732 8.879 70.722 9.533 ;
     RECT  16.524 9.391 36.486 9.545 ;
     RECT  71.82 9.517 78.75 9.545 ;
     RECT  45.108 9.005 46.53 9.625 ;
     RECT  69.876 9.533 70.722 9.625 ;
     RECT  71.82 9.545 76.482 9.625 ;
     RECT  45.072 9.625 46.53 9.629 ;
     RECT  2.268 9.419 15.75 9.643 ;
     RECT  47.412 9.355 54.306 9.661 ;
     RECT  55.224 9.481 68.958 9.661 ;
     RECT  25.848 9.545 36.486 9.677 ;
     RECT  77.328 9.545 78.75 9.677 ;
     RECT  16.524 9.545 25.11 9.689 ;
     RECT  47.412 9.661 68.958 9.689 ;
     RECT  57.744 9.689 68.958 9.851 ;
     RECT  42.48 9.239 44.334 9.931 ;
     RECT  45.072 9.629 46.17 9.931 ;
     RECT  47.412 9.689 56.898 9.931 ;
     RECT  32.976 9.677 36.486 10.021 ;
     RECT  37.584 9.247 41.598 10.021 ;
     RECT  42.48 9.931 46.17 10.021 ;
     RECT  47.088 9.931 56.898 10.049 ;
     RECT  2.232 9.643 15.75 10.165 ;
     RECT  16.524 9.689 25.074 10.165 ;
     RECT  47.088 10.049 50.202 10.205 ;
     RECT  47.088 10.205 47.106 10.391 ;
     RECT  50.976 10.049 56.898 10.391 ;
     RECT  25.848 9.677 32.166 10.471 ;
     RECT  32.976 10.021 46.17 10.471 ;
     RECT  69.876 9.625 76.482 10.471 ;
     RECT  77.328 9.677 78.678 10.471 ;
     RECT  79.632 9.391 92.862 10.471 ;
     RECT  47.988 10.205 50.202 10.499 ;
     RECT  2.232 10.165 25.074 10.561 ;
     RECT  25.848 10.471 46.782 10.561 ;
     RECT  57.816 9.851 68.958 10.561 ;
     RECT  69.876 10.471 92.862 10.561 ;
     RECT  57.816 10.561 92.862 10.633 ;
     RECT  2.232 10.561 46.782 10.829 ;
     RECT  50.976 10.391 52.938 10.831 ;
     RECT  53.784 10.391 56.898 10.831 ;
     RECT  2.232 10.829 20.61 10.895 ;
     RECT  48.024 10.499 50.202 10.966 ;
     RECT  50.94 10.831 52.938 10.966 ;
     RECT  53.784 10.831 56.97 11.011 ;
     RECT  57.744 10.633 92.862 11.011 ;
     RECT  0.108 10.705 0.126 11.131 ;
     RECT  48.024 10.966 52.938 11.131 ;
     RECT  2.232 10.895 20.538 11.165 ;
     RECT  0.108 11.131 0.162 11.227 ;
     RECT  48.024 11.131 53.01 11.227 ;
     RECT  53.784 11.011 92.862 11.227 ;
     RECT  48.024 11.227 92.862 11.258 ;
     RECT  47.88 11.258 92.862 11.407 ;
     RECT  2.268 11.165 20.538 11.641 ;
     RECT  21.492 10.829 46.782 11.641 ;
     RECT  2.268 11.641 46.782 11.677 ;
     RECT  2.268 11.677 47.034 11.705 ;
     RECT  0.108 11.227 0.234 11.749 ;
     RECT  2.304 11.705 47.034 11.821 ;
     RECT  47.808 11.407 92.862 11.821 ;
     RECT  2.304 11.821 92.862 11.939 ;
     RECT  26.496 11.939 92.862 11.975 ;
     RECT  2.304 11.939 25.758 11.981 ;
     RECT  26.496 11.975 45.954 11.981 ;
     RECT  46.692 11.975 92.862 11.984 ;
     RECT  46.692 11.984 54.882 12.029 ;
     RECT  0.108 11.749 0.558 12.173 ;
     RECT  2.304 11.981 19.566 12.475 ;
     RECT  55.692 11.984 92.862 12.509 ;
     RECT  2.232 12.475 19.566 12.515 ;
     RECT  26.496 11.981 45.897 12.551 ;
     RECT  20.304 11.981 25.758 12.721 ;
     RECT  26.496 12.551 30.942 12.721 ;
     RECT  31.68 12.551 45.897 12.721 ;
     RECT  46.692 12.029 54.846 12.721 ;
     RECT  55.764 12.509 92.862 12.749 ;
     RECT  2.268 12.515 19.566 12.829 ;
     RECT  20.304 12.721 30.942 12.829 ;
     RECT  0.54 12.173 0.558 12.845 ;
     RECT  31.68 12.721 54.846 12.865 ;
     RECT  31.68 12.865 54.918 12.893 ;
     RECT  2.268 12.829 30.942 12.941 ;
     RECT  55.764 12.749 91.89 12.941 ;
     RECT  55.764 12.941 91.854 13.085 ;
     RECT  70.488 13.085 91.854 13.127 ;
     RECT  92.7 12.749 92.862 13.199 ;
     RECT  92.7 13.199 92.79 13.229 ;
     RECT  70.812 13.127 91.854 13.289 ;
     RECT  19.836 12.941 30.942 13.325 ;
     RECT  22.248 13.325 30.942 13.333 ;
     RECT  31.68 12.893 52.254 13.333 ;
     RECT  19.836 13.325 21.474 13.433 ;
     RECT  21.42 13.433 21.474 13.559 ;
     RECT  53.028 12.893 54.918 13.567 ;
     RECT  55.764 13.085 69.75 13.567 ;
     RECT  53.028 13.567 69.75 13.595 ;
     RECT  22.248 13.333 52.254 13.661 ;
     RECT  22.248 13.661 47.034 13.667 ;
     RECT  47.772 13.661 52.254 13.711 ;
     RECT  53.028 13.595 68.058 13.711 ;
     RECT  21.42 13.559 21.438 13.739 ;
     RECT  2.268 12.941 19.062 13.801 ;
     RECT  19.836 13.433 20.61 13.801 ;
     RECT  22.248 13.667 44.226 13.865 ;
     RECT  45.036 13.667 47.034 13.865 ;
     RECT  68.832 13.595 69.75 13.873 ;
     RECT  70.812 13.289 71.154 13.873 ;
     RECT  68.832 13.873 69.822 13.909 ;
     RECT  70.596 13.873 71.154 13.909 ;
     RECT  92.7 13.229 92.718 13.981 ;
     RECT  68.832 13.909 71.154 14.071 ;
     RECT  71.892 13.289 91.854 14.071 ;
     RECT  92.7 13.981 92.79 14.071 ;
     RECT  2.268 13.801 20.61 14.099 ;
     RECT  20.232 14.099 20.61 14.215 ;
     RECT  12.564 14.099 19.35 14.243 ;
     RECT  0.144 14.251 0.162 14.296 ;
     RECT  0.144 14.296 0.342 14.377 ;
     RECT  20.232 14.215 21.33 14.381 ;
     RECT  68.832 14.071 91.854 14.381 ;
     RECT  47.772 13.711 68.058 14.443 ;
     RECT  68.832 14.381 91.782 14.443 ;
     RECT  0.144 14.377 0.378 14.449 ;
     RECT  25.56 13.865 44.226 14.449 ;
     RECT  45.396 13.865 47.034 14.449 ;
     RECT  47.772 14.443 91.782 14.449 ;
     RECT  45.396 14.449 91.782 14.477 ;
     RECT  2.268 14.099 11.79 14.521 ;
     RECT  22.824 13.865 24.678 14.611 ;
     RECT  25.56 14.449 44.658 14.611 ;
     RECT  2.232 14.521 11.79 14.621 ;
     RECT  0.144 14.449 0.414 14.635 ;
     RECT  22.824 14.611 44.658 14.647 ;
     RECT  0.108 14.635 0.414 14.669 ;
     RECT  0.108 14.669 0.342 14.675 ;
     RECT  22.392 14.647 44.658 14.683 ;
     RECT  21.96 14.683 44.658 14.755 ;
     RECT  45.396 14.477 90.702 14.755 ;
     RECT  0.144 14.675 0.342 14.765 ;
     RECT  91.728 14.477 91.782 15.017 ;
     RECT  2.268 14.621 11.79 15.061 ;
     RECT  12.564 14.243 19.062 15.061 ;
     RECT  2.268 15.061 19.494 15.295 ;
     RECT  20.232 14.381 21.042 15.295 ;
     RECT  21.96 14.755 90.702 15.307 ;
     RECT  91.728 15.017 91.746 15.307 ;
     RECT  2.268 15.295 21.042 15.403 ;
     RECT  21.96 15.307 91.746 15.403 ;
     RECT  0.216 14.765 0.342 15.499 ;
     RECT  0.18 15.499 0.342 15.529 ;
     RECT  2.268 15.403 91.746 15.592 ;
     RECT  2.232 15.592 91.746 15.629 ;
     RECT  92.664 14.071 92.79 15.691 ;
     RECT  2.304 15.629 91.746 15.719 ;
     RECT  0.18 15.529 0.558 15.773 ;
     RECT  2.304 15.719 68.13 15.773 ;
     RECT  68.976 15.719 91.746 15.871 ;
     RECT  68.976 15.871 91.818 16.097 ;
     RECT  75.204 16.097 91.818 16.259 ;
     RECT  2.304 15.773 68.058 16.295 ;
     RECT  91.764 16.259 91.818 16.301 ;
     RECT  2.304 16.295 57.726 16.331 ;
     RECT  2.304 16.331 26.55 16.439 ;
     RECT  2.304 16.439 21.87 16.501 ;
     RECT  22.716 16.439 26.55 16.529 ;
     RECT  0.216 15.773 0.558 16.555 ;
     RECT  27.288 16.331 57.726 16.589 ;
     RECT  68.976 16.097 74.466 16.609 ;
     RECT  64.8 16.295 68.058 16.681 ;
     RECT  68.904 16.609 74.466 16.681 ;
     RECT  0.144 16.555 0.558 16.781 ;
     RECT  27.288 16.589 57.654 16.835 ;
     RECT  91.764 16.301 91.782 16.877 ;
     RECT  92.628 15.691 92.79 16.973 ;
     RECT  58.536 16.295 64.062 17.041 ;
     RECT  64.8 16.681 74.466 17.041 ;
     RECT  75.204 16.259 90.558 17.041 ;
     RECT  92.664 16.973 92.79 17.069 ;
     RECT  2.268 16.501 21.87 17.105 ;
     RECT  58.536 17.041 90.558 17.185 ;
     RECT  2.304 17.105 21.87 17.221 ;
     RECT  92.7 17.069 92.79 17.261 ;
     RECT  22.716 16.529 26.37 17.311 ;
     RECT  58.5 17.185 90.558 17.419 ;
     RECT  91.8 17.077 91.854 17.419 ;
     RECT  0.144 16.781 0.342 17.452 ;
     RECT  0.108 17.452 0.342 17.453 ;
     RECT  2.304 17.221 21.978 17.491 ;
     RECT  22.716 17.311 26.406 17.491 ;
     RECT  27.288 16.835 57.618 17.491 ;
     RECT  58.5 17.419 90.63 17.501 ;
     RECT  2.304 17.491 57.618 17.581 ;
     RECT  91.8 17.419 91.89 17.611 ;
     RECT  91.764 17.611 91.89 17.707 ;
     RECT  2.304 17.581 57.654 17.725 ;
     RECT  58.5 17.501 90.45 17.725 ;
     RECT  91.728 17.707 91.89 17.761 ;
     RECT  91.188 17.761 91.89 17.933 ;
     RECT  91.728 17.933 91.89 18.317 ;
     RECT  92.772 17.261 92.79 18.413 ;
     RECT  2.304 17.725 90.45 18.571 ;
     RECT  91.728 18.317 91.746 18.667 ;
     RECT  0.108 17.453 0.306 18.701 ;
     RECT  91.692 18.667 91.746 18.869 ;
     RECT  2.304 18.571 90.594 18.959 ;
     RECT  34.164 18.959 90.594 19.229 ;
     RECT  69.48 19.229 90.594 19.301 ;
     RECT  34.164 19.229 68.742 19.409 ;
     RECT  69.48 19.301 76.158 19.421 ;
     RECT  34.164 19.409 57.258 19.565 ;
     RECT  2.304 18.959 33.318 19.741 ;
     RECT  34.164 19.565 55.638 19.741 ;
     RECT  72.252 19.421 76.158 19.853 ;
     RECT  76.968 19.301 90.594 19.949 ;
     RECT  0.108 18.701 0.27 20.011 ;
     RECT  92.7 19.651 92.718 20.011 ;
     RECT  58.104 19.409 68.742 20.119 ;
     RECT  69.48 19.421 71.514 20.119 ;
     RECT  0.108 20.011 0.342 20.141 ;
     RECT  58.104 20.119 71.514 20.191 ;
     RECT  72.252 19.853 76.122 20.191 ;
     RECT  92.7 20.011 92.79 20.237 ;
     RECT  91.728 18.869 91.746 20.299 ;
     RECT  0.18 20.141 0.27 20.333 ;
     RECT  58.104 20.191 76.122 20.417 ;
     RECT  2.304 19.741 55.638 20.425 ;
     RECT  56.376 19.565 57.258 20.425 ;
     RECT  58.104 20.417 64.854 20.425 ;
     RECT  0.18 20.333 0.198 20.525 ;
     RECT  91.728 20.299 91.782 20.587 ;
     RECT  65.592 20.417 76.122 20.623 ;
     RECT  76.968 19.949 90.378 20.623 ;
     RECT  91.188 20.587 91.782 20.659 ;
     RECT  65.592 20.623 90.378 20.683 ;
     RECT  91.188 20.659 91.818 20.683 ;
     RECT  65.592 20.683 91.818 20.893 ;
     RECT  2.304 20.425 64.854 21.067 ;
     RECT  2.268 21.067 64.854 21.119 ;
     RECT  34.056 21.119 64.854 21.235 ;
     RECT  65.592 20.893 91.854 21.235 ;
     RECT  34.056 21.235 91.854 21.389 ;
     RECT  92.772 20.237 92.79 21.433 ;
     RECT  34.056 21.389 90.738 21.677 ;
     RECT  34.056 21.677 90.666 22.013 ;
     RECT  0.144 21.403 0.162 22.045 ;
     RECT  2.268 21.119 33.282 22.045 ;
     RECT  34.056 22.013 76.086 22.045 ;
     RECT  2.268 22.045 76.086 22.075 ;
     RECT  0.108 22.045 0.162 22.081 ;
     RECT  2.232 22.075 76.086 22.235 ;
     RECT  2.268 22.235 60.714 22.349 ;
     RECT  92.7 21.433 92.79 22.349 ;
     RECT  76.86 22.013 90.666 22.441 ;
     RECT  91.692 21.389 91.854 22.441 ;
     RECT  76.86 22.441 91.854 22.445 ;
     RECT  0.108 22.081 0.558 22.541 ;
     RECT  0.108 22.541 0.162 22.733 ;
     RECT  61.56 22.235 76.086 22.783 ;
     RECT  61.56 22.783 76.122 22.919 ;
     RECT  92.7 22.349 92.718 22.925 ;
     RECT  2.268 22.349 60.606 23.125 ;
     RECT  61.56 22.919 64.35 23.125 ;
     RECT  65.124 22.919 76.122 23.161 ;
     RECT  76.86 22.445 91.782 23.161 ;
     RECT  2.268 23.125 64.35 23.279 ;
     RECT  0.144 22.733 0.162 23.309 ;
     RECT  92.772 23.275 92.79 23.315 ;
     RECT  47.7 23.279 64.35 23.549 ;
     RECT  65.124 23.161 91.782 23.597 ;
     RECT  47.88 23.549 64.35 23.701 ;
     RECT  65.124 23.597 91.746 23.701 ;
     RECT  92.772 24.133 92.79 24.173 ;
     RECT  2.268 23.279 46.926 24.241 ;
     RECT  47.88 23.701 91.746 24.269 ;
     RECT  2.268 24.241 47.142 24.367 ;
     RECT  47.88 24.269 75.834 24.367 ;
     RECT  2.268 24.367 75.834 24.395 ;
     RECT  0.144 24.043 0.162 24.637 ;
     RECT  0.144 24.637 0.342 24.715 ;
     RECT  92.664 24.475 92.682 24.763 ;
     RECT  22.608 24.395 75.834 24.773 ;
     RECT  2.268 24.395 21.87 24.859 ;
     RECT  2.232 24.859 21.87 24.899 ;
     RECT  1.152 24.637 1.17 24.907 ;
     RECT  0.108 24.715 0.342 24.941 ;
     RECT  22.644 24.773 75.834 25.141 ;
     RECT  76.752 24.269 91.746 25.141 ;
     RECT  22.644 25.141 91.746 25.313 ;
     RECT  92.628 24.763 92.682 25.387 ;
     RECT  2.232 24.899 21.762 25.519 ;
     RECT  2.196 25.519 21.762 25.675 ;
     RECT  22.644 25.313 60.246 25.675 ;
     RECT  2.196 25.675 60.246 25.709 ;
     RECT  0.108 24.941 0.162 25.825 ;
     RECT  2.196 25.709 41.778 25.901 ;
     RECT  61.092 25.313 91.746 25.901 ;
     RECT  91.656 25.901 91.746 26.023 ;
     RECT  42.516 25.709 60.246 26.221 ;
     RECT  61.092 25.901 90.918 26.221 ;
     RECT  91.656 26.023 91.854 26.293 ;
     RECT  91.656 26.293 91.89 26.519 ;
     RECT  2.196 25.901 41.742 26.671 ;
     RECT  42.516 26.221 90.918 26.671 ;
     RECT  2.196 26.671 90.918 26.789 ;
     RECT  2.268 26.789 90.918 26.897 ;
     RECT  91.764 26.519 91.89 26.923 ;
     RECT  92.628 25.387 92.79 26.923 ;
     RECT  1.152 24.907 1.206 27.053 ;
     RECT  2.268 26.897 33.858 27.059 ;
     RECT  91.764 26.923 92.79 27.149 ;
     RECT  0.108 25.825 0.234 27.211 ;
     RECT  91.836 27.149 92.79 27.533 ;
     RECT  2.304 27.059 33.858 27.715 ;
     RECT  34.596 26.897 90.918 27.715 ;
     RECT  92.592 27.533 92.79 27.725 ;
     RECT  0.108 27.211 0.558 27.821 ;
     RECT  2.304 27.715 90.918 28.013 ;
     RECT  91.764 27.913 91.782 28.363 ;
     RECT  2.304 28.013 90.666 28.445 ;
     RECT  91.728 28.363 91.782 28.747 ;
     RECT  91.188 28.747 91.782 28.859 ;
     RECT  0.108 27.821 0.522 29.029 ;
     RECT  2.304 28.445 90.45 29.299 ;
     RECT  92.772 27.725 92.79 29.323 ;
     RECT  91.692 28.859 91.782 29.453 ;
     RECT  0.108 29.029 0.558 29.549 ;
     RECT  2.304 29.299 90.522 29.611 ;
     RECT  91.692 29.453 91.746 29.611 ;
     RECT  92.736 29.323 92.79 29.755 ;
     RECT  92.7 29.755 92.79 29.759 ;
     RECT  2.304 29.611 91.746 29.795 ;
     RECT  92.7 29.759 92.754 29.831 ;
     RECT  92.7 29.831 92.718 30.029 ;
     RECT  2.304 29.795 20.358 30.541 ;
     RECT  21.096 29.795 91.746 30.541 ;
     RECT  92.664 30.427 92.682 30.571 ;
     RECT  92.556 30.571 92.682 30.701 ;
     RECT  0.144 29.549 0.558 30.721 ;
     RECT  0.108 30.721 0.558 30.847 ;
     RECT  92.7 30.763 92.718 30.859 ;
     RECT  0.108 30.847 1.17 30.983 ;
     RECT  2.304 30.541 91.746 31.289 ;
     RECT  0.108 30.983 0.558 31.373 ;
     RECT  0.144 31.373 0.558 31.469 ;
     RECT  91.692 31.289 91.746 31.531 ;
     RECT  91.692 31.531 91.782 31.649 ;
     RECT  0.144 31.469 0.342 32.045 ;
     RECT  92.7 30.859 92.79 32.063 ;
     RECT  2.304 31.289 90.666 32.071 ;
     RECT  0.144 32.045 0.234 32.141 ;
     RECT  0.144 32.141 0.198 32.237 ;
     RECT  0.144 32.237 0.162 32.305 ;
     RECT  2.304 32.071 90.702 32.332 ;
     RECT  2.268 32.332 90.702 32.429 ;
     RECT  2.304 32.429 90.702 32.467 ;
     RECT  91.728 31.649 91.782 32.467 ;
     RECT  92.736 32.063 92.79 32.639 ;
     RECT  2.304 32.467 91.782 33.005 ;
     RECT  2.304 33.005 91.746 33.053 ;
     RECT  0.108 32.305 0.162 33.197 ;
     RECT  0.144 33.197 0.162 33.485 ;
     RECT  92.772 32.639 92.79 33.643 ;
     RECT  92.736 33.643 92.79 33.835 ;
     RECT  2.304 33.053 73.17 33.925 ;
     RECT  2.268 33.925 73.17 34.051 ;
     RECT  73.944 33.053 91.746 34.051 ;
     RECT  2.268 34.051 91.746 34.061 ;
     RECT  2.304 34.061 91.746 34.123 ;
     RECT  0.216 34.735 0.234 34.795 ;
     RECT  2.304 34.123 91.782 34.829 ;
     RECT  2.304 34.829 91.746 34.889 ;
     RECT  0.144 34.795 0.234 34.897 ;
     RECT  2.304 34.889 90.594 35.041 ;
     RECT  92.7 33.835 92.79 35.467 ;
     RECT  0.108 34.897 0.234 35.473 ;
     RECT  2.268 35.041 90.594 35.545 ;
     RECT  2.232 35.545 90.594 35.693 ;
     RECT  92.664 35.467 92.79 35.699 ;
     RECT  2.268 35.693 90.594 35.735 ;
     RECT  92.664 35.699 92.718 35.969 ;
     RECT  53.208 35.735 90.594 36.043 ;
     RECT  91.692 34.889 91.746 36.043 ;
     RECT  92.7 35.969 92.718 36.077 ;
     RECT  53.208 36.043 91.746 36.149 ;
     RECT  2.268 35.735 52.434 36.173 ;
     RECT  91.692 36.149 91.746 36.211 ;
     RECT  2.304 36.173 52.434 36.517 ;
     RECT  53.208 36.149 90.63 36.517 ;
     RECT  0.108 35.473 0.558 36.653 ;
     RECT  91.692 36.211 91.782 36.749 ;
     RECT  92.772 36.619 92.79 36.811 ;
     RECT  2.304 36.517 90.63 36.895 ;
     RECT  2.304 36.895 90.666 36.907 ;
     RECT  91.692 36.749 91.746 36.907 ;
     RECT  2.304 36.907 91.746 37.037 ;
     RECT  0.108 36.653 0.126 37.133 ;
     RECT  2.304 37.037 90.378 37.165 ;
     RECT  2.268 37.165 90.378 37.597 ;
     RECT  91.188 37.037 91.746 37.669 ;
     RECT  0.54 37.597 0.558 37.709 ;
     RECT  2.232 37.597 90.378 37.733 ;
     RECT  92.736 36.811 92.79 37.768 ;
     RECT  2.304 37.733 90.378 37.975 ;
     RECT  91.188 37.669 91.782 37.975 ;
     RECT  92.7 37.768 92.79 38.129 ;
     RECT  2.304 37.975 91.818 38.285 ;
     RECT  92.7 38.129 92.754 38.399 ;
     RECT  92.7 38.399 92.718 38.471 ;
     RECT  2.304 38.285 91.782 38.849 ;
     RECT  0.144 38.539 0.162 38.923 ;
     RECT  21.348 38.849 91.782 38.975 ;
     RECT  0.144 38.923 0.342 39.019 ;
     RECT  25.164 38.975 91.782 39.245 ;
     RECT  2.304 38.849 20.61 39.631 ;
     RECT  21.348 38.975 24.297 39.631 ;
     RECT  25.164 39.245 91.746 39.659 ;
     RECT  25.164 39.659 44.37 39.721 ;
     RECT  2.304 39.631 24.297 39.883 ;
     RECT  2.268 39.883 24.297 40.055 ;
     RECT  25.092 39.721 44.37 40.063 ;
     RECT  2.304 40.055 24.297 40.165 ;
     RECT  25.056 40.063 44.37 40.165 ;
     RECT  2.304 40.165 44.37 40.531 ;
     RECT  45.108 39.659 91.746 40.531 ;
     RECT  2.304 40.531 91.746 40.637 ;
     RECT  0.108 39.019 0.342 40.667 ;
     RECT  18.252 40.637 91.746 40.667 ;
     RECT  0.18 40.667 0.342 40.685 ;
     RECT  2.304 40.637 17.514 40.843 ;
     RECT  18.252 40.667 91.206 40.865 ;
     RECT  0.18 40.685 0.198 41.069 ;
     RECT  2.268 40.843 17.514 41.467 ;
     RECT  18.252 40.865 90.306 41.467 ;
     RECT  2.268 41.467 90.306 41.611 ;
     RECT  91.08 40.865 91.206 41.611 ;
     RECT  92.772 40.843 92.79 41.803 ;
     RECT  92.556 41.803 92.79 42.029 ;
     RECT  2.268 41.611 90.342 42.106 ;
     RECT  91.08 41.611 91.782 42.106 ;
     RECT  2.268 42.106 91.782 42.179 ;
     RECT  0.54 41.953 0.558 42.221 ;
     RECT  2.268 42.179 90.522 42.521 ;
     RECT  23.868 42.521 90.522 42.605 ;
     RECT  92.592 42.029 92.79 42.653 ;
     RECT  2.268 42.521 22.95 42.691 ;
     RECT  0.324 42.379 0.522 42.727 ;
     RECT  0.252 42.727 0.522 42.763 ;
     RECT  0.18 42.763 0.522 42.827 ;
     RECT  2.16 42.691 22.95 42.863 ;
     RECT  92.628 42.653 92.79 42.893 ;
     RECT  91.728 42.179 91.782 42.989 ;
     RECT  91.728 42.989 91.746 43.051 ;
     RECT  92.7 42.893 92.79 43.061 ;
     RECT  0.504 42.827 0.522 43.141 ;
     RECT  44.784 42.605 90.522 43.169 ;
     RECT  92.736 43.061 92.79 43.169 ;
     RECT  91.692 43.051 91.746 43.259 ;
     RECT  44.784 43.169 64.494 43.325 ;
     RECT  23.868 42.605 44.01 43.339 ;
     RECT  44.784 43.325 58.662 43.339 ;
     RECT  2.268 42.863 22.95 43.367 ;
     RECT  65.232 43.169 90.522 43.367 ;
     RECT  0.504 43.141 0.558 43.373 ;
     RECT  2.304 43.367 22.95 43.483 ;
     RECT  2.304 43.483 22.986 43.609 ;
     RECT  23.868 43.339 58.662 43.609 ;
     RECT  0.504 43.373 0.522 43.661 ;
     RECT  59.4 43.325 64.494 43.673 ;
     RECT  2.304 43.609 58.662 44.107 ;
     RECT  2.268 44.107 58.662 44.203 ;
     RECT  91.728 43.259 91.746 44.203 ;
     RECT  59.436 43.673 64.494 44.221 ;
     RECT  65.232 43.367 90.378 44.221 ;
     RECT  91.692 44.203 91.746 44.248 ;
     RECT  59.436 44.221 90.378 44.266 ;
     RECT  91.692 44.248 91.782 44.299 ;
     RECT  59.436 44.266 90.774 44.333 ;
     RECT  2.232 44.203 58.662 44.339 ;
     RECT  2.232 44.339 16.722 44.447 ;
     RECT  17.496 44.339 58.662 44.455 ;
     RECT  59.436 44.333 90.522 44.455 ;
     RECT  92.772 43.169 92.79 44.689 ;
     RECT  0.324 44.683 0.342 44.779 ;
     RECT  17.496 44.455 90.522 44.879 ;
     RECT  92.736 44.689 92.79 44.879 ;
     RECT  0.108 44.779 0.342 44.995 ;
     RECT  0.108 44.995 0.558 45.005 ;
     RECT  2.304 44.447 16.722 45.112 ;
     RECT  17.496 44.879 31.374 45.112 ;
     RECT  91.512 44.299 91.782 45.121 ;
     RECT  32.112 44.879 90.522 45.293 ;
     RECT  56.376 45.293 90.522 45.301 ;
     RECT  91.26 45.121 91.782 45.301 ;
     RECT  32.112 45.293 55.458 45.329 ;
     RECT  2.304 45.112 31.374 45.419 ;
     RECT  32.112 45.329 42.606 45.533 ;
     RECT  2.304 45.419 31.302 45.599 ;
     RECT  92.736 44.879 92.754 45.739 ;
     RECT  0.54 45.005 0.558 45.805 ;
     RECT  0.108 45.805 0.558 45.869 ;
     RECT  12.456 45.599 31.302 45.869 ;
     RECT  12.528 45.869 31.302 45.959 ;
     RECT  43.344 45.329 55.458 46.013 ;
     RECT  56.376 45.301 91.782 46.031 ;
     RECT  69.3 46.031 91.782 46.061 ;
     RECT  12.636 45.959 27.126 46.067 ;
     RECT  32.112 45.533 42.534 46.111 ;
     RECT  53.604 46.013 55.458 46.111 ;
     RECT  56.376 46.031 68.382 46.111 ;
     RECT  27.864 45.959 31.302 46.201 ;
     RECT  32.076 46.111 42.534 46.201 ;
     RECT  92.736 45.739 92.79 46.315 ;
     RECT  27.864 46.201 42.534 46.345 ;
     RECT  43.344 46.013 52.866 46.345 ;
     RECT  91.764 46.061 91.782 46.471 ;
     RECT  92.592 46.315 92.79 46.733 ;
     RECT  17.46 46.067 27.126 46.741 ;
     RECT  27.864 46.345 52.866 46.741 ;
     RECT  12.636 46.067 16.47 46.795 ;
     RECT  17.46 46.741 52.866 46.795 ;
     RECT  69.3 46.061 90.594 46.795 ;
     RECT  91.764 46.471 91.818 46.795 ;
     RECT  0.108 45.869 0.126 46.829 ;
     RECT  12.636 46.795 52.866 46.849 ;
     RECT  53.604 46.111 68.382 46.849 ;
     RECT  69.3 46.795 91.818 46.925 ;
     RECT  2.304 45.599 11.646 47.075 ;
     RECT  12.564 46.849 68.382 47.075 ;
     RECT  57.78 47.075 68.382 47.083 ;
     RECT  69.3 46.925 90.63 47.083 ;
     RECT  92.7 46.733 92.79 47.147 ;
     RECT  57.78 47.083 90.63 47.183 ;
     RECT  12.564 47.075 57.006 47.191 ;
     RECT  57.888 47.183 90.63 47.219 ;
     RECT  91.764 46.925 91.818 47.281 ;
     RECT  12.384 47.191 57.006 47.309 ;
     RECT  0.144 47.371 0.162 47.389 ;
     RECT  12.384 47.309 19.638 47.389 ;
     RECT  20.412 47.309 57.006 47.579 ;
     RECT  91.764 47.281 91.854 47.693 ;
     RECT  0.144 47.389 0.234 47.731 ;
     RECT  2.304 47.075 11.538 47.731 ;
     RECT  0.144 47.731 0.558 47.741 ;
     RECT  55.404 47.579 57.006 47.821 ;
     RECT  57.888 47.219 90.594 47.947 ;
     RECT  91.764 47.693 91.782 47.947 ;
     RECT  55.404 47.821 57.078 47.965 ;
     RECT  57.888 47.947 91.782 47.965 ;
     RECT  2.268 47.731 11.538 48.001 ;
     RECT  12.276 47.389 19.638 48.001 ;
     RECT  0.54 47.741 0.558 48.077 ;
     RECT  20.412 47.579 54.63 48.085 ;
     RECT  2.268 48.001 19.638 48.127 ;
     RECT  20.376 48.085 54.63 48.127 ;
     RECT  2.268 48.127 54.63 48.361 ;
     RECT  55.404 47.965 91.782 48.361 ;
     RECT  2.268 48.361 91.782 48.425 ;
     RECT  2.268 48.425 49.302 48.497 ;
     RECT  2.268 48.497 49.194 48.619 ;
     RECT  2.232 48.619 49.194 48.659 ;
     RECT  50.04 48.425 91.782 48.695 ;
     RECT  50.04 48.695 74.754 48.701 ;
     RECT  92.736 47.147 92.79 49.003 ;
     RECT  92.592 49.003 92.79 49.133 ;
     RECT  92.628 49.133 92.79 49.199 ;
     RECT  2.232 48.659 27.594 49.235 ;
     RECT  92.628 49.199 92.754 49.277 ;
     RECT  2.232 49.235 13.698 49.379 ;
     RECT  75.492 48.695 91.782 49.379 ;
     RECT  28.404 48.659 49.194 49.435 ;
     RECT  50.04 48.701 62.982 49.435 ;
     RECT  14.58 49.235 27.594 49.441 ;
     RECT  28.404 49.435 62.982 49.441 ;
     RECT  63.72 48.701 74.754 49.441 ;
     RECT  91.476 49.379 91.782 49.483 ;
     RECT  2.232 49.379 8.73 49.505 ;
     RECT  14.58 49.441 74.754 49.505 ;
     RECT  0.324 49.387 0.342 49.517 ;
     RECT  14.724 49.505 74.754 49.541 ;
     RECT  14.724 49.541 44.01 49.565 ;
     RECT  44.748 49.541 74.754 49.585 ;
     RECT  75.492 49.379 90.666 49.585 ;
     RECT  44.748 49.585 90.666 49.613 ;
     RECT  9.684 49.379 13.698 49.739 ;
     RECT  44.748 49.613 53.91 49.811 ;
     RECT  54.684 49.613 66.186 49.919 ;
     RECT  10.116 49.739 13.698 50.009 ;
     RECT  54.684 49.919 63.954 50.009 ;
     RECT  64.872 49.919 66.186 50.009 ;
     RECT  54.684 50.009 63.846 50.141 ;
     RECT  64.872 50.009 66.042 50.153 ;
     RECT  2.268 49.505 8.73 50.161 ;
     RECT  2.268 50.161 9.342 50.251 ;
     RECT  54.684 50.141 63.738 50.315 ;
     RECT  1.152 49.003 1.17 50.333 ;
     RECT  67.14 49.613 90.666 50.347 ;
     RECT  14.796 49.565 44.01 50.395 ;
     RECT  44.964 49.811 53.91 50.395 ;
     RECT  54.684 50.315 59.778 50.395 ;
     RECT  67.104 50.347 90.666 50.443 ;
     RECT  91.476 49.483 91.854 50.443 ;
     RECT  14.796 50.395 44.226 50.549 ;
     RECT  44.964 50.395 59.778 50.549 ;
     RECT  92.7 49.277 92.754 50.549 ;
     RECT  39.78 50.549 44.226 50.557 ;
     RECT  44.964 50.549 55.422 50.557 ;
     RECT  0.324 50.347 0.342 50.573 ;
     RECT  67.104 50.443 91.854 50.635 ;
     RECT  67.068 50.635 91.854 50.693 ;
     RECT  10.188 50.009 13.698 50.701 ;
     RECT  14.796 50.549 39.042 50.701 ;
     RECT  64.872 50.153 65.682 50.701 ;
     RECT  39.78 50.557 55.422 50.729 ;
     RECT  2.232 50.251 9.342 50.731 ;
     RECT  69.408 50.693 91.854 50.855 ;
     RECT  60.552 50.315 63.738 50.863 ;
     RECT  64.656 50.701 65.682 50.863 ;
     RECT  60.552 50.863 65.682 50.926 ;
     RECT  69.516 50.855 91.854 50.927 ;
     RECT  45.036 50.729 54.342 50.963 ;
     RECT  2.196 50.731 9.342 50.965 ;
     RECT  10.188 50.701 39.042 50.965 ;
     RECT  60.552 50.926 65.718 51.061 ;
     RECT  2.196 50.965 39.042 51.089 ;
     RECT  60.516 51.061 65.718 51.205 ;
     RECT  25.344 51.089 37.962 51.233 ;
     RECT  60.444 51.205 65.718 51.241 ;
     RECT  91.152 50.927 91.854 51.269 ;
     RECT  38.736 51.089 39.042 51.307 ;
     RECT  39.78 50.729 41.454 51.307 ;
     RECT  55.08 50.729 55.422 51.355 ;
     RECT  25.344 51.233 31.806 51.359 ;
     RECT  2.196 51.089 9.126 51.395 ;
     RECT  0.324 51.307 0.342 51.397 ;
     RECT  0.108 51.397 0.342 51.403 ;
     RECT  92.736 50.549 92.754 51.403 ;
     RECT  2.196 51.395 9.018 51.431 ;
     RECT  25.38 51.359 31.806 51.431 ;
     RECT  69.516 50.927 90.342 51.431 ;
     RECT  45.072 50.963 54.342 51.511 ;
     RECT  55.08 51.355 55.458 51.511 ;
     RECT  56.268 50.549 59.67 51.511 ;
     RECT  60.444 51.241 66.402 51.511 ;
     RECT  56.268 51.511 66.402 51.539 ;
     RECT  38.736 51.307 41.454 51.601 ;
     RECT  42.444 50.729 44.19 51.601 ;
     RECT  45.072 51.511 55.458 51.601 ;
     RECT  56.268 51.539 59.094 51.601 ;
     RECT  67.215 50.693 68.67 51.601 ;
     RECT  69.516 51.431 70.938 51.601 ;
     RECT  59.868 51.539 66.402 51.629 ;
     RECT  9.972 51.089 24.57 51.665 ;
     RECT  71.784 51.431 90.342 51.709 ;
     RECT  45.072 51.601 59.094 51.725 ;
     RECT  32.724 51.233 37.962 51.737 ;
     RECT  38.736 51.601 44.19 51.781 ;
     RECT  45.072 51.725 51.894 51.781 ;
     RECT  60.336 51.629 66.402 51.781 ;
     RECT  67.215 51.601 70.938 51.781 ;
     RECT  0.036 51.403 0.342 51.821 ;
     RECT  36.576 51.737 37.962 51.871 ;
     RECT  38.736 51.781 51.894 51.871 ;
     RECT  92.7 51.403 92.754 51.883 ;
     RECT  0.036 51.821 0.126 51.917 ;
     RECT  10.26 51.665 24.57 51.971 ;
     RECT  32.724 51.737 35.838 51.979 ;
     RECT  71.784 51.709 90.378 52.007 ;
     RECT  92.592 51.883 92.754 52.013 ;
     RECT  92.7 52.013 92.754 52.157 ;
     RECT  21.168 51.971 24.57 52.169 ;
     RECT  92.736 52.157 92.754 52.169 ;
     RECT  7.488 51.431 9.018 52.213 ;
     RECT  26.64 51.431 31.806 52.213 ;
     RECT  32.58 51.979 35.838 52.213 ;
     RECT  60.336 51.781 70.938 52.213 ;
     RECT  71.784 52.007 76.518 52.213 ;
     RECT  25.38 51.431 25.902 52.249 ;
     RECT  26.64 52.213 35.838 52.249 ;
     RECT  52.812 51.725 59.094 52.262 ;
     RECT  2.196 51.431 6.75 52.267 ;
     RECT  7.488 52.213 9.198 52.267 ;
     RECT  21.204 52.169 24.57 52.267 ;
     RECT  25.38 52.249 35.838 52.267 ;
     RECT  91.224 51.269 91.854 52.267 ;
     RECT  77.292 52.007 90.378 52.285 ;
     RECT  77.292 52.285 90.414 52.315 ;
     RECT  91.188 52.267 91.854 52.315 ;
     RECT  10.26 51.971 20.214 52.349 ;
     RECT  77.292 52.315 91.854 52.367 ;
     RECT  77.292 52.367 91.818 52.394 ;
     RECT  52.812 52.262 59.526 52.411 ;
     RECT  60.336 52.213 76.518 52.411 ;
     RECT  2.196 52.267 9.306 52.439 ;
     RECT  52.812 52.411 76.518 52.439 ;
     RECT  77.292 52.394 90.414 52.439 ;
     RECT  91.188 52.394 91.818 52.445 ;
     RECT  36.576 51.871 51.894 52.459 ;
     RECT  52.812 52.439 57.114 52.459 ;
     RECT  2.196 52.439 9.198 52.583 ;
     RECT  2.232 52.583 9.198 52.619 ;
     RECT  36.576 52.459 57.114 52.709 ;
     RECT  57.852 52.439 76.518 52.817 ;
     RECT  61.308 52.817 76.518 52.825 ;
     RECT  77.292 52.439 90.378 52.825 ;
     RECT  10.26 52.349 18.897 52.853 ;
     RECT  10.26 52.853 10.278 52.861 ;
     RECT  36.9 52.709 57.114 52.979 ;
     RECT  61.308 52.825 90.378 52.979 ;
     RECT  21.204 52.267 35.838 52.987 ;
     RECT  11.052 52.853 18.897 53.015 ;
     RECT  21.204 52.987 36.162 53.015 ;
     RECT  64.188 52.979 90.378 53.015 ;
     RECT  19.62 52.349 20.214 53.023 ;
     RECT  21.204 53.015 32.202 53.023 ;
     RECT  91.26 52.445 91.818 53.069 ;
     RECT  38.124 52.979 57.114 53.159 ;
     RECT  69.516 53.015 90.378 53.165 ;
     RECT  2.268 52.619 9.198 53.221 ;
     RECT  10.08 52.861 10.278 53.221 ;
     RECT  14.292 53.015 18.897 53.221 ;
     RECT  19.62 53.023 32.202 53.221 ;
     RECT  75.564 53.165 90.378 53.249 ;
     RECT  57.852 52.817 60.462 53.285 ;
     RECT  61.308 52.979 63.45 53.285 ;
     RECT  91.656 53.069 91.818 53.357 ;
     RECT  0.036 51.917 0.054 53.371 ;
     RECT  2.268 53.221 10.278 53.419 ;
     RECT  14.292 53.221 32.202 53.429 ;
     RECT  58.392 53.285 60.462 53.519 ;
     RECT  38.124 53.159 41.778 53.555 ;
     RECT  92.772 52.411 92.79 53.555 ;
     RECT  32.94 53.015 36.162 53.591 ;
     RECT  2.232 53.419 10.278 53.599 ;
     RECT  11.052 53.015 13.554 53.599 ;
     RECT  58.464 53.519 60.462 53.599 ;
     RECT  58.464 53.599 60.57 53.671 ;
     RECT  0.036 53.371 0.162 53.707 ;
     RECT  42.588 53.159 57.114 53.755 ;
     RECT  2.232 53.599 13.554 53.761 ;
     RECT  14.292 53.429 15.21 53.761 ;
     RECT  15.948 53.429 32.202 53.761 ;
     RECT  32.94 53.591 33.786 53.761 ;
     RECT  64.188 53.015 68.598 53.761 ;
     RECT  58.464 53.671 60.858 53.789 ;
     RECT  91.656 53.357 91.782 53.803 ;
     RECT  0.036 53.707 0.342 53.837 ;
     RECT  36.9 52.979 37.35 53.869 ;
     RECT  38.124 53.555 41.67 53.869 ;
     RECT  64.188 53.761 68.634 53.869 ;
     RECT  69.516 53.165 74.826 53.869 ;
     RECT  91.512 53.803 91.782 53.933 ;
     RECT  34.632 53.591 36.162 53.941 ;
     RECT  36.9 53.869 41.67 53.941 ;
     RECT  42.588 53.755 57.654 53.941 ;
     RECT  64.188 53.869 74.826 54.043 ;
     RECT  64.188 54.043 74.862 54.067 ;
     RECT  64.188 54.067 74.934 54.077 ;
     RECT  74.52 54.077 74.934 54.091 ;
     RECT  75.744 53.249 90.378 54.091 ;
     RECT  74.52 54.091 90.378 54.103 ;
     RECT  0.036 53.837 0.198 54.125 ;
     RECT  64.188 54.077 73.746 54.131 ;
     RECT  91.512 53.933 91.566 54.131 ;
     RECT  61.668 53.285 63.45 54.139 ;
     RECT  64.188 54.131 65.574 54.139 ;
     RECT  2.232 53.761 15.21 54.187 ;
     RECT  74.52 54.103 90.45 54.239 ;
     RECT  66.384 54.131 73.746 54.329 ;
     RECT  42.444 53.941 57.654 54.365 ;
     RECT  66.384 54.329 68.958 54.371 ;
     RECT  15.948 53.761 33.786 54.409 ;
     RECT  34.632 53.941 41.67 54.409 ;
     RECT  58.464 53.789 60.678 54.409 ;
     RECT  15.948 54.409 41.67 54.437 ;
     RECT  17.604 54.437 41.67 54.481 ;
     RECT  42.444 54.365 57.114 54.481 ;
     RECT  61.668 54.139 65.574 54.481 ;
     RECT  1.728 54.187 15.21 54.571 ;
     RECT  15.948 54.437 16.686 54.571 ;
     RECT  57.888 54.409 60.678 54.571 ;
     RECT  61.56 54.481 65.574 54.571 ;
     RECT  91.512 54.131 91.53 54.571 ;
     RECT  1.728 54.571 16.686 54.599 ;
     RECT  17.604 54.481 57.114 54.599 ;
     RECT  1.728 54.599 13.806 54.635 ;
     RECT  17.676 54.599 57.114 54.635 ;
     RECT  1.728 54.635 9.846 54.667 ;
     RECT  32.688 54.635 57.114 54.671 ;
     RECT  74.52 54.239 90.414 54.701 ;
     RECT  10.692 54.635 12.366 54.707 ;
     RECT  74.52 54.701 90.378 54.707 ;
     RECT  71.712 54.329 73.746 54.841 ;
     RECT  74.52 54.707 75.258 54.841 ;
     RECT  10.8 54.707 12.366 54.869 ;
     RECT  10.8 54.869 11.322 54.905 ;
     RECT  92.772 54.283 92.79 54.913 ;
     RECT  91.224 54.571 91.53 54.955 ;
     RECT  41.652 54.671 57.114 54.977 ;
     RECT  57.888 54.571 65.574 54.985 ;
     RECT  57.888 54.985 65.61 55.049 ;
     RECT  59.22 55.049 65.61 55.111 ;
     RECT  66.384 54.371 68.814 55.111 ;
     RECT  69.804 54.329 70.902 55.111 ;
     RECT  71.712 54.841 75.258 55.111 ;
     RECT  92.736 54.913 92.79 55.139 ;
     RECT  32.688 54.671 40.878 55.175 ;
     RECT  41.652 54.977 55.566 55.175 ;
     RECT  76.032 54.707 90.378 55.175 ;
     RECT  92.736 55.139 92.754 55.181 ;
     RECT  56.415 54.977 57.114 55.183 ;
     RECT  57.888 55.049 58.374 55.183 ;
     RECT  77.04 55.175 90.378 55.211 ;
     RECT  56.415 55.183 58.374 55.229 ;
     RECT  69.804 55.111 75.258 55.255 ;
     RECT  41.652 55.175 45.897 55.283 ;
     RECT  59.22 55.111 68.958 55.291 ;
     RECT  69.732 55.255 75.258 55.291 ;
     RECT  91.188 54.955 91.53 55.339 ;
     RECT  1.152 54.667 9.846 55.453 ;
     RECT  10.8 54.905 11.07 55.453 ;
     RECT  13.215 54.635 13.806 55.483 ;
     RECT  13.14 55.483 13.806 55.489 ;
     RECT  14.58 54.599 16.686 55.489 ;
     RECT  17.712 54.635 31.914 55.489 ;
     RECT  32.688 55.175 35.097 55.489 ;
     RECT  59.22 55.291 75.258 55.489 ;
     RECT  76.032 55.175 76.302 55.489 ;
     RECT  17.712 55.489 35.097 55.525 ;
     RECT  59.22 55.489 76.302 55.553 ;
     RECT  35.928 55.175 40.878 55.561 ;
     RECT  41.652 55.283 42.57 55.561 ;
     RECT  77.076 55.211 90.378 55.561 ;
     RECT  91.188 55.339 91.746 55.561 ;
     RECT  12.06 54.869 12.15 55.675 ;
     RECT  17.46 55.525 35.097 55.679 ;
     RECT  59.22 55.553 74.718 55.679 ;
     RECT  1.152 55.453 11.07 55.687 ;
     RECT  12.06 55.675 12.366 55.687 ;
     RECT  0.036 54.125 0.054 55.715 ;
     RECT  46.728 55.175 55.422 55.715 ;
     RECT  75.564 55.553 76.302 55.715 ;
     RECT  77.076 55.561 91.746 55.715 ;
     RECT  35.928 55.561 42.57 55.751 ;
     RECT  35.928 55.751 36.45 55.859 ;
     RECT  13.14 55.489 16.686 55.921 ;
     RECT  17.46 55.679 33.57 55.921 ;
     RECT  43.38 55.283 45.897 55.921 ;
     RECT  46.728 55.715 49.698 55.921 ;
     RECT  37.296 55.751 42.57 55.949 ;
     RECT  43.38 55.921 49.698 55.949 ;
     RECT  75.744 55.715 76.302 55.957 ;
     RECT  1.152 55.687 12.366 55.985 ;
     RECT  59.22 55.679 74.682 55.985 ;
     RECT  58.068 55.229 58.374 55.993 ;
     RECT  59.22 55.985 74.61 55.993 ;
     RECT  2.304 55.985 12.366 56.029 ;
     RECT  13.14 55.921 33.57 56.029 ;
     RECT  50.508 55.715 55.422 56.065 ;
     RECT  56.415 55.229 57.258 56.065 ;
     RECT  37.62 55.949 42.57 56.101 ;
     RECT  43.38 55.949 48.546 56.101 ;
     RECT  34.344 55.679 35.097 56.191 ;
     RECT  35.928 55.859 36.018 56.191 ;
     RECT  50.508 56.065 57.258 56.191 ;
     RECT  58.068 55.993 74.61 56.191 ;
     RECT  2.304 56.029 33.57 56.219 ;
     RECT  50.508 56.191 74.61 56.255 ;
     RECT  2.304 56.219 30.114 56.327 ;
     RECT  50.508 56.255 55.098 56.327 ;
     RECT  2.376 56.327 19.17 56.333 ;
     RECT  19.908 56.327 30.114 56.399 ;
     RECT  55.836 56.255 74.61 56.429 ;
     RECT  75.744 55.957 76.446 56.443 ;
     RECT  92.772 56.203 92.79 56.488 ;
     RECT  92.736 56.488 92.79 56.489 ;
     RECT  1.152 55.985 1.17 56.525 ;
     RECT  75.6 56.443 76.446 56.533 ;
     RECT  77.4 55.715 91.746 56.533 ;
     RECT  31.032 56.219 33.57 56.605 ;
     RECT  75.6 56.533 91.746 56.605 ;
     RECT  31.032 56.605 33.606 56.641 ;
     RECT  34.344 56.191 36.018 56.641 ;
     RECT  49.356 55.949 49.698 56.641 ;
     RECT  50.508 56.327 53.154 56.641 ;
     RECT  75.348 56.605 91.746 56.669 ;
     RECT  91.62 56.669 91.746 56.683 ;
     RECT  31.032 56.641 36.018 56.731 ;
     RECT  36.792 56.605 36.81 56.731 ;
     RECT  2.376 56.333 14.85 56.759 ;
     RECT  92.736 56.489 92.754 56.759 ;
     RECT  31.032 56.731 36.81 56.767 ;
     RECT  37.62 56.101 48.546 56.767 ;
     RECT  2.376 56.759 6.642 56.795 ;
     RECT  2.376 56.795 5.274 56.831 ;
     RECT  6.624 56.795 6.642 56.831 ;
     RECT  12.456 56.759 14.85 56.831 ;
     RECT  69.696 56.429 74.61 56.839 ;
     RECT  75.348 56.669 90.522 56.839 ;
     RECT  9.684 56.759 11.502 56.909 ;
     RECT  31.032 56.767 48.546 56.911 ;
     RECT  49.356 56.641 53.154 56.911 ;
     RECT  7.668 56.759 8.226 56.939 ;
     RECT  9.684 56.909 11.322 56.939 ;
     RECT  91.62 56.683 91.782 56.939 ;
     RECT  19.944 56.399 30.114 57.001 ;
     RECT  31.032 56.911 53.154 57.001 ;
     RECT  19.944 57.001 53.154 57.029 ;
     RECT  55.836 56.429 68.85 57.029 ;
     RECT  15.588 56.333 19.17 57.053 ;
     RECT  2.376 56.831 5.166 57.065 ;
     RECT  9.684 56.939 11.106 57.065 ;
     RECT  12.492 56.831 14.85 57.065 ;
     RECT  16.056 57.053 19.17 57.065 ;
     RECT  22.752 57.029 53.154 57.109 ;
     RECT  53.928 56.327 55.098 57.109 ;
     RECT  12.6 57.065 14.85 57.137 ;
     RECT  22.752 57.109 55.098 57.137 ;
     RECT  52.344 57.137 55.098 57.145 ;
     RECT  55.836 57.029 56.754 57.145 ;
     RECT  3.636 57.065 5.166 57.173 ;
     RECT  12.636 57.137 14.85 57.173 ;
     RECT  17.46 57.065 19.17 57.181 ;
     RECT  19.944 57.029 21.87 57.181 ;
     RECT  57.564 57.029 68.85 57.181 ;
     RECT  69.696 56.839 90.522 57.181 ;
     RECT  52.344 57.145 56.754 57.197 ;
     RECT  2.376 57.065 2.697 57.209 ;
     RECT  3.744 57.173 5.166 57.209 ;
     RECT  9.684 57.065 10.854 57.209 ;
     RECT  16.056 57.065 16.614 57.209 ;
     RECT  3.744 57.209 4.374 57.299 ;
     RECT  5.148 57.209 5.166 57.299 ;
     RECT  7.815 56.939 8.226 57.299 ;
     RECT  10.008 57.209 10.854 57.299 ;
     RECT  12.636 57.173 14.094 57.299 ;
     RECT  16.056 57.209 16.542 57.299 ;
     RECT  17.46 57.181 21.87 57.299 ;
     RECT  3.744 57.299 4.194 57.335 ;
     RECT  16.056 57.299 16.074 57.335 ;
     RECT  17.46 57.299 19.566 57.335 ;
     RECT  22.752 57.137 51.606 57.335 ;
     RECT  22.752 57.335 35.478 57.371 ;
     RECT  36.756 57.335 51.606 57.371 ;
     RECT  25.668 57.371 35.478 57.443 ;
     RECT  36.756 57.371 49.554 57.443 ;
     RECT  57.564 57.181 90.522 57.443 ;
     RECT  10.836 57.299 10.854 57.479 ;
     RECT  13.215 57.299 13.986 57.479 ;
     RECT  14.832 57.173 14.85 57.479 ;
     RECT  37.008 57.443 49.554 57.479 ;
     RECT  57.672 57.443 90.522 57.479 ;
     RECT  17.46 57.335 19.422 57.569 ;
     RECT  20.412 57.299 21.87 57.569 ;
     RECT  22.752 57.371 24.894 57.569 ;
     RECT  61.596 57.479 90.522 57.569 ;
     RECT  25.668 57.443 35.37 57.581 ;
     RECT  17.46 57.569 17.478 57.605 ;
     RECT  18.615 57.569 19.422 57.713 ;
     RECT  23.976 57.569 24.894 57.713 ;
     RECT  25.668 57.581 27.918 57.713 ;
     RECT  61.596 57.569 76.41 57.749 ;
     RECT  20.412 57.569 21.222 57.839 ;
     RECT  22.752 57.569 22.914 57.839 ;
     RECT  37.008 57.479 49.302 57.839 ;
     RECT  64.08 57.749 76.41 57.839 ;
     RECT  20.412 57.839 21.042 57.875 ;
     RECT  37.692 57.839 49.302 57.875 ;
     RECT  22.752 57.839 22.842 57.991 ;
     RECT  50.292 57.371 51.606 57.991 ;
     RECT  52.344 57.197 55.386 57.991 ;
     RECT  56.304 57.197 56.754 57.991 ;
     RECT  21.996 57.991 22.842 58.019 ;
     RECT  25.668 57.713 27.018 58.019 ;
     RECT  37.692 57.875 38.61 58.019 ;
     RECT  28.692 57.581 35.37 58.061 ;
     RECT  21.996 58.019 22.446 58.109 ;
     RECT  24.015 57.713 24.894 58.109 ;
     RECT  25.668 58.019 26.874 58.109 ;
     RECT  28.764 58.061 35.37 58.109 ;
     RECT  64.332 57.839 76.41 58.115 ;
     RECT  21.996 58.109 22.014 58.145 ;
     RECT  24.015 58.109 24.714 58.145 ;
     RECT  25.668 58.109 26.838 58.145 ;
     RECT  29.415 58.109 35.37 58.145 ;
     RECT  57.672 57.479 60.75 58.145 ;
     RECT  64.332 58.115 67.698 58.145 ;
     RECT  31.032 58.145 32.67 58.157 ;
     RECT  38.16 58.019 38.61 58.157 ;
     RECT  41.868 57.875 49.302 58.168 ;
     RECT  33.588 58.145 35.37 58.217 ;
     RECT  92.772 57.451 92.79 58.217 ;
     RECT  43.56 58.168 49.302 58.225 ;
     RECT  50.292 57.991 56.826 58.225 ;
     RECT  57.672 58.145 60.066 58.225 ;
     RECT  61.596 57.749 63.306 58.225 ;
     RECT  31.032 58.157 31.698 58.253 ;
     RECT  38.16 58.157 38.178 58.253 ;
     RECT  25.956 58.145 26.046 58.379 ;
     RECT  26.82 58.145 26.838 58.379 ;
     RECT  27.9 57.713 27.918 58.379 ;
     RECT  36.324 58.261 36.558 58.379 ;
     RECT  41.868 58.168 42.786 58.379 ;
     RECT  43.56 58.225 49.338 58.379 ;
     RECT  36.324 58.379 36.342 58.387 ;
     RECT  91.62 56.939 91.746 58.411 ;
     RECT  32.508 58.157 32.67 58.415 ;
     RECT  36.252 58.387 36.342 58.415 ;
     RECT  39.348 57.875 40.914 58.415 ;
     RECT  49.032 58.379 49.086 58.415 ;
     RECT  50.292 58.225 60.066 58.451 ;
     RECT  68.472 58.115 76.41 58.459 ;
     RECT  77.148 57.569 90.378 58.459 ;
     RECT  52.2 58.451 54.666 58.487 ;
     RECT  68.472 58.459 90.378 58.507 ;
     RECT  91.188 58.411 91.746 58.507 ;
     RECT  34.056 58.217 35.37 58.531 ;
     RECT  36.252 58.415 36.306 58.531 ;
     RECT  50.292 58.451 51.297 58.531 ;
     RECT  34.056 58.531 36.306 58.541 ;
     RECT  31.68 58.253 31.698 58.649 ;
     RECT  34.056 58.541 34.074 58.649 ;
     RECT  34.815 58.541 36.306 58.649 ;
     RECT  39.42 58.415 40.497 58.649 ;
     RECT  41.868 58.379 42.318 58.649 ;
     RECT  43.56 58.379 48.042 58.649 ;
     RECT  54 58.487 54.666 58.649 ;
     RECT  32.58 58.415 32.67 58.685 ;
     RECT  34.815 58.649 35.55 58.685 ;
     RECT  39.564 58.649 40.497 58.685 ;
     RECT  41.868 58.649 41.886 58.685 ;
     RECT  43.56 58.649 43.578 58.685 ;
     RECT  49.968 58.531 51.297 58.685 ;
     RECT  54.648 58.649 54.666 58.685 ;
     RECT  55.584 58.451 60.066 58.685 ;
     RECT  45 58.649 48.042 58.691 ;
     RECT  49.032 58.415 49.05 58.691 ;
     RECT  52.2 58.487 53.226 58.691 ;
     RECT  60.912 58.225 63.306 58.693 ;
     RECT  64.728 58.145 67.698 58.721 ;
     RECT  57.636 58.685 60.066 58.733 ;
     RECT  32.58 58.685 32.598 58.793 ;
     RECT  68.472 58.507 91.746 58.793 ;
     RECT  55.908 58.685 56.862 58.829 ;
     RECT  45 58.691 46.71 58.919 ;
     RECT  47.484 58.691 48.042 58.919 ;
     RECT  49.968 58.685 50.202 58.919 ;
     RECT  52.2 58.691 53.01 58.919 ;
     RECT  60.912 58.693 63.882 58.919 ;
     RECT  67.176 58.721 67.698 58.919 ;
     RECT  45.54 58.919 46.71 58.955 ;
     RECT  47.484 58.919 47.898 58.955 ;
     RECT  49.968 58.919 50.13 58.955 ;
     RECT  52.2 58.919 52.218 58.955 ;
     RECT  57.636 58.733 59.382 58.955 ;
     RECT  72.108 58.793 91.746 58.991 ;
     RECT  64.728 58.721 66.402 58.999 ;
     RECT  57.636 58.955 59.346 59.027 ;
     RECT  50.004 58.955 50.13 59.063 ;
     RECT  60.912 58.919 63.45 59.161 ;
     RECT  45.615 58.955 46.71 59.189 ;
     RECT  50.976 58.685 51.297 59.189 ;
     RECT  56.415 58.829 56.862 59.189 ;
     RECT  57.636 59.027 58.194 59.189 ;
     RECT  60.444 59.161 63.45 59.189 ;
     RECT  64.224 58.999 66.402 59.189 ;
     RECT  68.472 58.793 71.226 59.189 ;
     RECT  63.108 59.189 63.306 59.213 ;
     RECT  45.615 59.189 46.35 59.225 ;
     RECT  47.484 58.955 47.574 59.225 ;
     RECT  50.004 59.063 50.022 59.225 ;
     RECT  60.444 59.189 60.966 59.225 ;
     RECT  63.252 59.213 63.306 59.225 ;
     RECT  68.472 59.189 69.894 59.225 ;
     RECT  76.932 58.991 91.746 59.225 ;
     RECT  47.556 59.225 47.574 59.261 ;
     RECT  72.108 58.991 76.158 59.297 ;
     RECT  69.876 59.225 69.894 59.333 ;
     RECT  51.015 59.189 51.297 59.341 ;
     RECT  59.04 59.027 59.346 59.459 ;
     RECT  79.56 59.225 91.746 59.459 ;
     RECT  51.015 59.341 52.182 59.495 ;
     RECT  52.992 58.919 53.01 59.495 ;
     RECT  57.636 59.189 58.086 59.495 ;
     RECT  59.04 59.459 59.058 59.495 ;
     RECT  60.444 59.225 60.462 59.495 ;
     RECT  63.288 59.225 63.306 59.495 ;
     RECT  68.472 59.225 68.886 59.495 ;
     RECT  64.368 59.189 66.402 59.539 ;
     RECT  67.176 58.919 67.497 59.539 ;
     RECT  57.816 59.495 58.086 59.603 ;
     RECT  70.668 59.189 71.226 59.611 ;
     RECT  72.108 59.297 76.122 59.639 ;
     RECT  64.368 59.539 67.497 59.701 ;
     RECT  68.22 59.611 68.382 59.701 ;
     RECT  74.772 59.639 76.122 59.729 ;
     RECT  72.108 59.639 73.926 59.801 ;
     RECT  64.368 59.701 68.382 59.837 ;
     RECT  54.468 59.611 54.486 59.851 ;
     RECT  70.668 59.611 71.298 59.881 ;
     RECT  72.108 59.801 73.206 59.881 ;
     RECT  52.164 59.495 52.182 59.909 ;
     RECT  54.324 59.851 54.486 59.999 ;
     RECT  57.888 59.603 58.086 59.999 ;
     RECT  65.376 59.837 68.382 59.999 ;
     RECT  70.668 59.881 73.206 59.999 ;
     RECT  75.024 59.729 76.122 59.999 ;
     RECT  57.888 59.999 57.906 60.035 ;
     RECT  59.868 59.851 59.886 60.035 ;
     RECT  64.368 59.837 64.422 60.035 ;
     RECT  66.672 59.999 68.238 60.071 ;
     RECT  75.132 59.999 76.122 60.071 ;
     RECT  61.815 59.189 62.334 60.115 ;
     RECT  75.672 60.071 76.122 60.115 ;
     RECT  76.932 59.225 78.57 60.115 ;
     RECT  58.86 60.151 59.022 60.269 ;
     RECT  61.092 60.115 62.694 60.269 ;
     RECT  70.56 60.151 70.578 60.269 ;
     RECT  71.352 59.999 73.206 60.269 ;
     RECT  75.672 60.115 78.57 60.269 ;
     RECT  55.26 60.151 55.278 60.305 ;
     RECT  58.86 60.269 58.878 60.305 ;
     RECT  72 60.269 73.062 60.305 ;
     RECT  92.772 59.563 92.79 60.313 ;
     RECT  61.092 60.269 62.097 60.377 ;
     RECT  64.224 60.151 64.242 60.385 ;
     RECT  76.968 60.269 78.57 60.413 ;
     RECT  70.38 60.283 70.398 60.419 ;
     RECT  79.56 59.459 80.226 60.421 ;
     RECT  92.736 60.313 92.79 60.461 ;
     RECT  65.376 59.999 65.394 60.539 ;
     RECT  66.672 60.071 68.166 60.539 ;
     RECT  69.084 60.421 69.102 60.539 ;
     RECT  75.672 60.269 76.194 60.539 ;
     RECT  63.864 60.385 64.242 60.575 ;
     RECT  66.672 60.539 67.698 60.575 ;
     RECT  72.432 60.305 73.062 60.575 ;
     RECT  79.524 60.421 80.226 60.619 ;
     RECT  81 59.459 91.746 60.619 ;
     RECT  79.524 60.619 91.746 60.647 ;
     RECT  67.215 60.575 67.698 60.809 ;
     RECT  72.432 60.575 72.897 60.809 ;
     RECT  75.672 60.539 76.014 60.809 ;
     RECT  92.772 60.461 92.79 60.809 ;
     RECT  64.224 60.575 64.242 60.845 ;
     RECT  67.215 60.809 67.626 60.845 ;
     RECT  77.544 60.413 78.297 60.845 ;
     RECT  74.196 60.691 74.214 60.953 ;
     RECT  79.524 60.647 79.902 60.961 ;
     RECT  80.928 60.647 91.746 60.989 ;
     RECT  81.324 60.989 91.746 61.079 ;
     RECT  77.94 60.845 78.297 61.115 ;
     RECT  79.092 60.961 79.902 61.385 ;
     RECT  82.908 61.079 91.746 61.457 ;
     RECT  79.776 61.385 79.902 61.501 ;
     RECT  81.324 61.079 82.026 61.529 ;
     RECT  79.776 61.501 80.406 61.619 ;
     RECT  79.776 61.619 79.794 61.799 ;
     RECT  82.908 61.457 90.522 61.925 ;
     RECT  82.908 61.925 90.378 62.069 ;
     RECT  91.476 61.457 91.746 62.069 ;
     RECT  91.476 62.069 91.638 62.159 ;
     RECT  82.008 61.529 82.026 62.167 ;
     RECT  82.908 62.069 86.778 62.167 ;
     RECT  82.008 62.167 86.778 62.195 ;
     RECT  82.656 62.195 86.778 62.339 ;
     RECT  91.476 62.159 91.566 62.339 ;
     RECT  2.415 57.209 2.697 62.387 ;
     RECT  7.815 57.299 8.097 62.387 ;
     RECT  13.215 57.479 13.497 62.387 ;
     RECT  18.615 57.713 18.897 62.387 ;
     RECT  24.015 58.145 24.297 62.387 ;
     RECT  29.415 58.145 29.697 62.387 ;
     RECT  34.815 58.685 35.097 62.387 ;
     RECT  40.215 58.685 40.497 62.387 ;
     RECT  45.615 59.225 45.897 62.387 ;
     RECT  51.015 59.495 51.297 62.387 ;
     RECT  56.415 59.189 56.697 62.387 ;
     RECT  61.815 60.377 62.097 62.387 ;
     RECT  67.215 60.845 67.497 62.387 ;
     RECT  72.615 60.809 72.897 62.387 ;
     RECT  78.015 61.115 78.297 62.387 ;
     RECT  82.944 62.339 86.778 62.387 ;
     RECT  84.384 62.387 86.778 62.429 ;
     RECT  91.476 62.339 91.494 62.429 ;
     RECT  84.384 62.429 84.402 62.477 ;
     RECT  87.588 62.069 90.378 62.537 ;
     RECT  82.944 62.387 83.505 62.573 ;
     RECT  85.176 62.429 86.778 62.573 ;
     RECT  87.768 62.537 90.378 62.573 ;
     RECT  85.32 62.573 86.778 62.609 ;
     RECT  88.128 62.573 90.378 62.609 ;
     RECT  2.415 62.387 2.505 62.657 ;
     RECT  7.815 62.387 7.905 62.657 ;
     RECT  13.215 62.387 13.305 62.657 ;
     RECT  18.615 62.387 18.705 62.657 ;
     RECT  24.015 62.387 24.105 62.657 ;
     RECT  29.415 62.387 29.505 62.657 ;
     RECT  34.815 62.387 34.905 62.657 ;
     RECT  40.215 62.387 40.305 62.657 ;
     RECT  45.615 62.387 45.705 62.657 ;
     RECT  51.015 62.387 51.105 62.657 ;
     RECT  56.415 62.387 56.505 62.657 ;
     RECT  61.815 62.387 61.905 62.657 ;
     RECT  67.215 62.387 67.305 62.657 ;
     RECT  72.615 62.387 72.705 62.657 ;
     RECT  78.015 62.387 78.105 62.657 ;
     RECT  83.415 62.573 83.505 62.657 ;
     RECT  88.128 62.609 89.586 62.657 ;
     RECT  85.32 62.609 85.338 62.699 ;
     RECT  86.652 62.609 86.67 62.699 ;
     RECT  88.128 62.657 88.794 62.699 ;
     RECT  89.568 62.657 89.586 62.699 ;
     RECT  90.36 62.609 90.378 62.699 ;
    LAYER M4 ;
     RECT  0.133 2.256 0.181 2.28 ;
     RECT  0.06 3.408 0.181 54.792 ;
     RECT  0.181 2.256 2.365 54.792 ;
     RECT  2.365 2.256 2.408 55.464 ;
     RECT  2.408 2.148 2.512 62.652 ;
     RECT  2.512 2.208 2.704 62.382 ;
     RECT  2.704 2.208 2.837 57.048 ;
     RECT  2.837 2.208 2.867 48.072 ;
     RECT  2.867 2.256 2.873 48.072 ;
     RECT  2.873 2.784 3.413 48.072 ;
     RECT  2.837 49.056 3.685 57.048 ;
     RECT  3.413 36.336 3.913 48.072 ;
     RECT  3.685 49.056 3.913 57.096 ;
     RECT  3.413 2.784 4.165 35.304 ;
     RECT  3.913 36.336 4.385 57.096 ;
     RECT  4.165 2.688 4.549 35.304 ;
     RECT  4.385 36.336 4.549 57.048 ;
     RECT  4.549 2.688 5.221 57.048 ;
     RECT  5.221 2.688 5.357 56.328 ;
     RECT  5.357 2.688 5.393 3 ;
     RECT  5.393 2.688 5.507 2.856 ;
     RECT  5.357 4.224 5.545 56.328 ;
     RECT  5.545 49.776 5.699 56.328 ;
     RECT  5.507 2.784 5.789 2.856 ;
     RECT  5.699 54.528 5.825 56.328 ;
     RECT  5.699 49.776 6.041 53.4 ;
     RECT  5.825 54.672 6.077 56.328 ;
     RECT  6.041 49.776 6.113 53.352 ;
     RECT  5.545 4.224 6.365 48.696 ;
     RECT  6.113 49.824 6.365 53.352 ;
     RECT  5.789 2.832 6.652 2.856 ;
     RECT  6.365 4.224 6.689 38.904 ;
     RECT  6.365 49.968 6.689 53.352 ;
     RECT  6.365 39.888 6.829 48.696 ;
     RECT  6.077 54.672 7.261 54.696 ;
     RECT  6.077 55.68 7.261 56.328 ;
     RECT  6.829 39.888 7.369 48.744 ;
     RECT  6.689 4.368 7.405 38.904 ;
     RECT  7.369 39.888 7.405 48.84 ;
     RECT  7.261 54.672 7.657 56.328 ;
     RECT  7.405 4.368 7.808 48.84 ;
     RECT  6.689 50.064 7.808 53.352 ;
     RECT  7.657 54.672 7.808 56.904 ;
     RECT  7.808 2.148 7.912 62.652 ;
     RECT  7.912 2.418 8.104 62.382 ;
     RECT  8.104 3.888 8.381 50.28 ;
     RECT  8.381 50.256 9.133 50.28 ;
     RECT  8.104 52.272 9.157 52.296 ;
     RECT  8.104 53.28 9.157 57.24 ;
     RECT  9.157 52.272 9.317 57.24 ;
     RECT  9.317 52.944 9.389 57.24 ;
     RECT  9.133 50.256 9.493 50.856 ;
     RECT  8.381 3.888 9.677 49.08 ;
     RECT  9.493 50.256 9.683 51 ;
     RECT  9.389 54.048 9.821 57.24 ;
     RECT  9.677 3.888 9.857 38.808 ;
     RECT  9.857 3.888 9.923 8.712 ;
     RECT  9.857 9.792 10.145 38.808 ;
     RECT  9.923 3.888 10.181 8.664 ;
     RECT  10.181 5.664 10.259 8.664 ;
     RECT  9.821 56.112 10.309 57.24 ;
     RECT  10.145 11.76 10.325 38.808 ;
     RECT  9.677 39.984 10.325 49.08 ;
     RECT  10.145 9.792 10.361 10.68 ;
     RECT  9.821 54.048 10.361 54.552 ;
     RECT  10.309 56.112 10.396 57.288 ;
     RECT  10.361 10.032 10.505 10.68 ;
     RECT  9.683 50.256 10.645 50.856 ;
     RECT  10.396 56.112 10.789 57.048 ;
     RECT  10.645 50.208 10.825 50.856 ;
     RECT  10.825 50.208 10.861 51.768 ;
     RECT  10.325 44.688 10.901 49.08 ;
     RECT  10.901 44.736 10.973 49.032 ;
     RECT  10.325 39.984 11.077 43.56 ;
     RECT  10.789 55.824 11.117 57.048 ;
     RECT  9.389 52.944 11.185 52.968 ;
     RECT  10.505 10.128 11.221 10.68 ;
     RECT  10.325 11.76 11.221 38.424 ;
     RECT  10.259 6.24 11.225 8.664 ;
     RECT  11.221 10.128 11.293 38.424 ;
     RECT  11.077 39.888 11.293 43.56 ;
     RECT  11.293 10.128 11.297 43.56 ;
     RECT  11.185 52.944 11.329 53.448 ;
     RECT  10.361 54.432 11.329 54.552 ;
     RECT  10.861 50.208 11.401 51.912 ;
     RECT  11.329 52.944 11.401 54.552 ;
     RECT  11.297 10.128 11.405 13.416 ;
     RECT  11.401 50.208 11.441 54.552 ;
     RECT  11.225 6.24 11.473 8.568 ;
     RECT  11.117 55.824 11.513 56.904 ;
     RECT  11.473 5.808 11.837 8.568 ;
     RECT  11.297 14.88 11.869 43.56 ;
     RECT  10.973 44.976 11.893 49.032 ;
     RECT  11.441 50.208 11.893 54.504 ;
     RECT  11.893 44.976 11.939 54.504 ;
     RECT  11.869 14.88 11.941 43.848 ;
     RECT  11.939 49.728 11.945 54.504 ;
     RECT  11.945 49.728 11.98 52.344 ;
     RECT  11.837 5.808 12.049 8.52 ;
     RECT  11.98 50.208 12.053 52.344 ;
     RECT  12.053 50.832 12.197 52.344 ;
     RECT  11.513 55.824 12.337 56.472 ;
     RECT  11.405 10.656 12.373 13.416 ;
     RECT  11.941 14.88 12.445 43.896 ;
     RECT  11.939 44.976 12.445 48.168 ;
     RECT  12.373 10.32 12.517 13.416 ;
     RECT  12.517 9.6 12.553 13.416 ;
     RECT  12.445 14.88 12.553 48.168 ;
     RECT  12.337 55.68 12.949 56.472 ;
     RECT  12.949 55.68 13.129 57 ;
     RECT  10.181 3.888 13.208 3.912 ;
     RECT  12.049 5.328 13.208 8.52 ;
     RECT  12.553 9.6 13.208 48.168 ;
     RECT  12.197 50.832 13.208 50.952 ;
     RECT  12.197 52.176 13.208 52.344 ;
     RECT  11.945 53.568 13.208 54.504 ;
     RECT  13.129 55.488 13.208 57 ;
     RECT  13.208 2.148 13.312 62.652 ;
     RECT  13.312 2.418 13.504 62.382 ;
     RECT  13.504 40.416 13.529 49.224 ;
     RECT  13.504 54.864 13.637 56.904 ;
     RECT  13.529 40.416 13.673 47.88 ;
     RECT  13.504 50.832 13.673 53.832 ;
     RECT  13.529 48.96 13.708 49.224 ;
     RECT  13.504 9.648 13.925 28.536 ;
     RECT  13.504 36.624 13.961 39.336 ;
     RECT  13.708 48.96 14.105 48.984 ;
     RECT  13.925 9.648 14.285 9.672 ;
     RECT  13.504 29.808 14.497 35.544 ;
     RECT  13.637 54.864 14.569 56.664 ;
     RECT  13.925 11.232 14.573 28.536 ;
     RECT  13.673 40.416 14.677 47.4 ;
     RECT  13.504 4.656 14.749 7.992 ;
     RECT  14.573 11.232 14.929 14.232 ;
     RECT  14.749 4.56 14.933 8.616 ;
     RECT  14.497 29.664 15.109 35.544 ;
     RECT  14.677 40.416 15.181 47.736 ;
     RECT  13.673 50.832 15.181 53.352 ;
     RECT  14.569 54.72 15.181 56.664 ;
     RECT  14.713 49.536 15.217 49.56 ;
     RECT  14.933 4.56 15.251 7.704 ;
     RECT  15.109 29.568 15.253 35.544 ;
     RECT  13.961 36.624 15.253 38.616 ;
     RECT  15.251 5.184 15.293 7.704 ;
     RECT  14.929 10.56 15.325 14.232 ;
     RECT  15.253 29.568 15.433 38.616 ;
     RECT  15.181 40.032 15.433 47.736 ;
     RECT  15.217 49.44 15.437 49.56 ;
     RECT  15.433 29.568 15.473 47.736 ;
     RECT  15.325 10.32 15.541 14.232 ;
     RECT  14.573 15.216 15.541 28.536 ;
     RECT  15.181 50.832 15.577 56.664 ;
     RECT  15.437 49.44 15.649 49.464 ;
     RECT  15.473 29.568 15.725 41.928 ;
     RECT  15.649 49.392 15.869 49.464 ;
     RECT  15.541 10.32 16.081 28.536 ;
     RECT  15.577 50.832 16.085 57.048 ;
     RECT  16.081 10.32 16.121 28.584 ;
     RECT  15.473 43.248 16.153 47.736 ;
     RECT  16.121 14.208 16.163 28.584 ;
     RECT  16.163 14.928 16.189 28.584 ;
     RECT  15.725 29.568 16.189 39.528 ;
     RECT  16.153 43.248 16.189 47.928 ;
     RECT  15.293 5.376 16.405 7.704 ;
     RECT  15.613 8.976 16.405 9 ;
     RECT  16.405 5.376 16.549 9.336 ;
     RECT  16.085 50.832 16.589 56.232 ;
     RECT  16.549 5.136 16.765 9.336 ;
     RECT  16.121 10.32 16.765 12.552 ;
     RECT  16.589 54.288 16.805 56.232 ;
     RECT  15.725 40.896 16.945 41.928 ;
     RECT  16.189 43.248 16.945 49.176 ;
     RECT  16.765 5.136 16.949 12.552 ;
     RECT  16.189 14.928 17.125 39.528 ;
     RECT  16.945 40.896 17.125 49.176 ;
     RECT  16.589 50.832 17.197 53.256 ;
     RECT  17.125 14.928 17.237 49.176 ;
     RECT  16.949 11.136 17.377 12.552 ;
     RECT  17.237 14.928 17.449 15.192 ;
     RECT  17.237 16.176 17.453 49.176 ;
     RECT  16.805 54.288 17.525 56.04 ;
     RECT  17.453 19.344 17.597 49.176 ;
     RECT  17.197 50.256 17.603 53.256 ;
     RECT  17.603 50.256 17.737 50.28 ;
     RECT  16.949 5.136 17.804 9.624 ;
     RECT  17.804 5.04 17.953 9.624 ;
     RECT  17.377 11.136 17.953 13.08 ;
     RECT  17.603 51.312 18.061 53.256 ;
     RECT  17.525 54.288 18.061 55.512 ;
     RECT  17.449 14.448 18.205 15.192 ;
     RECT  17.453 16.176 18.205 18.024 ;
     RECT  17.953 5.04 18.608 13.08 ;
     RECT  18.205 14.448 18.608 18.024 ;
     RECT  17.597 19.344 18.608 48.696 ;
     RECT  17.737 50.16 18.608 50.28 ;
     RECT  18.061 51.312 18.608 55.512 ;
     RECT  18.608 2.148 18.712 62.652 ;
     RECT  18.712 2.418 18.904 62.382 ;
     RECT  18.904 19.248 18.929 32.568 ;
     RECT  18.904 38.688 19.217 49.128 ;
     RECT  18.904 51.264 19.217 57.576 ;
     RECT  19.217 55.824 19.325 57.576 ;
     RECT  18.904 4.8 19.468 9.336 ;
     RECT  19.468 5.28 19.667 9.336 ;
     RECT  19.667 5.28 19.685 8.136 ;
     RECT  19.217 51.264 19.757 54.696 ;
     RECT  19.217 41.952 19.793 49.128 ;
     RECT  19.685 5.28 19.829 6.648 ;
     RECT  18.904 14.352 19.829 18.024 ;
     RECT  19.667 9.312 19.865 9.336 ;
     RECT  19.217 38.688 19.897 40.92 ;
     RECT  19.793 43.584 19.897 49.128 ;
     RECT  19.757 51.264 20.113 54.12 ;
     RECT  18.904 33.552 20.189 37.656 ;
     RECT  18.904 10.368 20.261 13.32 ;
     RECT  19.325 55.824 20.333 57 ;
     RECT  20.189 35.328 20.435 37.656 ;
     RECT  20.333 55.824 20.437 55.848 ;
     RECT  20.333 56.976 20.485 57 ;
     RECT  19.897 38.64 20.509 40.92 ;
     RECT  19.793 41.952 20.509 42.6 ;
     RECT  20.485 56.976 20.531 57.864 ;
     RECT  20.509 38.64 20.549 42.6 ;
     RECT  19.829 18 20.581 18.024 ;
     RECT  18.929 19.344 20.581 32.568 ;
     RECT  19.897 43.584 20.689 49.224 ;
     RECT  20.113 50.544 20.689 54.12 ;
     RECT  20.437 55.68 20.689 55.848 ;
     RECT  19.829 5.28 20.729 6.408 ;
     RECT  20.689 43.584 20.765 54.12 ;
     RECT  20.729 5.328 20.797 6.408 ;
     RECT  20.549 42.144 20.977 42.6 ;
     RECT  20.765 43.584 20.977 53.592 ;
     RECT  20.977 42.144 20.989 53.592 ;
     RECT  20.581 18 21.02 32.568 ;
     RECT  20.189 33.552 21.02 34.344 ;
     RECT  20.531 57.84 21.053 57.864 ;
     RECT  20.005 9.36 21.085 9.384 ;
     RECT  19.829 14.352 21.109 16.536 ;
     RECT  21.02 18 21.109 34.344 ;
     RECT  21.109 14.352 21.169 34.344 ;
     RECT  21.085 9.12 21.197 9.384 ;
     RECT  20.435 35.328 21.301 37.56 ;
     RECT  21.169 14.352 21.347 33.96 ;
     RECT  20.797 5.328 21.377 6.84 ;
     RECT  20.689 55.632 21.517 55.848 ;
     RECT  20.549 38.64 21.557 41.064 ;
     RECT  21.347 14.88 21.593 33.96 ;
     RECT  21.377 5.472 21.625 6.84 ;
     RECT  19.685 7.872 21.625 8.136 ;
     RECT  21.517 54.96 21.733 55.848 ;
     RECT  20.261 10.368 21.769 12.648 ;
     RECT  21.625 5.472 21.773 8.136 ;
     RECT  21.733 54.96 21.817 55.896 ;
     RECT  21.773 6.816 21.845 8.136 ;
     RECT  21.845 6.864 21.913 8.136 ;
     RECT  21.301 35.28 21.973 37.56 ;
     RECT  21.557 38.64 21.973 40.632 ;
     RECT  20.989 47.088 22.025 53.592 ;
     RECT  21.973 35.28 22.165 40.632 ;
     RECT  20.989 42.144 22.165 46.056 ;
     RECT  22.025 51.936 22.165 53.592 ;
     RECT  21.769 9.552 22.273 12.648 ;
     RECT  22.165 41.856 22.309 46.056 ;
     RECT  22.025 47.088 22.309 50.904 ;
     RECT  22.165 35.232 22.385 40.632 ;
     RECT  21.593 14.88 22.493 23.736 ;
     RECT  21.773 5.472 22.561 5.736 ;
     RECT  22.493 18.432 22.561 23.736 ;
     RECT  21.593 24.768 22.561 33.96 ;
     RECT  22.309 41.856 22.637 50.904 ;
     RECT  22.561 5.088 22.645 5.736 ;
     RECT  22.385 36.288 22.777 40.632 ;
     RECT  22.493 14.88 22.811 17.112 ;
     RECT  22.273 9.552 22.817 12.792 ;
     RECT  22.645 5.472 22.853 5.736 ;
     RECT  22.637 42.192 22.925 50.904 ;
     RECT  22.925 42.192 22.997 48.264 ;
     RECT  22.561 18.432 23.065 33.96 ;
     RECT  22.811 14.832 23.137 17.112 ;
     RECT  23.065 18.432 23.425 34.2 ;
     RECT  22.385 35.232 23.425 35.304 ;
     RECT  21.817 54.96 23.785 55.704 ;
     RECT  23.137 14.784 23.929 17.112 ;
     RECT  23.425 18.432 23.929 35.304 ;
     RECT  22.853 5.472 24.008 5.496 ;
     RECT  21.913 6.864 24.008 8.568 ;
     RECT  22.817 9.552 24.008 9.576 ;
     RECT  22.817 10.992 24.008 12.792 ;
     RECT  23.929 14.784 24.008 35.304 ;
     RECT  22.777 36.288 24.008 41.064 ;
     RECT  22.997 42.192 24.008 42.6 ;
     RECT  22.997 43.776 24.008 48.264 ;
     RECT  22.925 49.536 24.008 50.904 ;
     RECT  22.165 51.936 24.008 53.928 ;
     RECT  23.785 54.96 24.008 55.896 ;
     RECT  23.569 57.408 24.008 57.432 ;
     RECT  24.008 2.148 24.112 62.652 ;
     RECT  24.112 2.418 24.304 62.382 ;
     RECT  24.304 14.928 24.473 27.144 ;
     RECT  24.304 28.272 24.515 38.904 ;
     RECT  24.515 28.272 24.617 38.808 ;
     RECT  24.304 7.728 24.689 9.672 ;
     RECT  24.304 42.48 24.725 42.504 ;
     RECT  24.304 43.776 24.869 55.272 ;
     RECT  24.304 40.176 25.193 40.44 ;
     RECT  24.304 13.536 25.369 13.56 ;
     RECT  24.869 46.752 25.477 55.272 ;
     RECT  25.441 56.448 25.477 56.472 ;
     RECT  24.617 28.272 25.553 38.712 ;
     RECT  25.477 46.752 25.571 56.472 ;
     RECT  24.473 14.928 25.585 26.712 ;
     RECT  24.304 6.432 25.621 6.456 ;
     RECT  24.689 7.728 25.621 9.48 ;
     RECT  25.571 46.752 25.661 51.672 ;
     RECT  25.621 5.52 25.697 9.48 ;
     RECT  24.304 10.992 25.769 12.216 ;
     RECT  25.193 40.416 25.801 40.44 ;
     RECT  25.697 8.496 25.805 9.48 ;
     RECT  25.769 10.992 25.837 11.928 ;
     RECT  25.765 57.552 25.873 57.576 ;
     RECT  25.801 40.416 25.909 40.728 ;
     RECT  24.869 43.776 25.909 45.768 ;
     RECT  25.369 13.536 26.017 13.608 ;
     RECT  25.585 14.832 26.017 26.712 ;
     RECT  25.621 42.528 26.017 42.552 ;
     RECT  25.909 43.728 26.017 45.768 ;
     RECT  25.553 28.368 26.081 38.712 ;
     RECT  25.909 40.416 26.269 40.872 ;
     RECT  26.017 42.528 26.269 45.768 ;
     RECT  26.269 40.416 26.521 45.768 ;
     RECT  26.017 13.392 26.525 26.712 ;
     RECT  25.661 46.752 26.525 51.384 ;
     RECT  25.571 52.752 26.597 55.56 ;
     RECT  26.081 28.368 26.665 38.808 ;
     RECT  26.521 39.84 26.665 45.768 ;
     RECT  25.697 5.52 26.705 7.272 ;
     RECT  26.665 28.368 26.773 45.768 ;
     RECT  26.597 54.768 26.773 55.56 ;
     RECT  25.837 9.648 26.809 11.928 ;
     RECT  26.525 14.736 26.813 26.712 ;
     RECT  26.773 28.32 26.845 45.768 ;
     RECT  26.525 46.992 26.849 51.384 ;
     RECT  26.809 9.648 26.989 12.024 ;
     RECT  26.525 13.392 26.989 13.608 ;
     RECT  26.813 24.528 27.029 26.712 ;
     RECT  26.845 27.984 27.065 45.768 ;
     RECT  26.597 52.752 27.065 53.688 ;
     RECT  26.773 54.768 27.169 56.232 ;
     RECT  27.065 27.984 27.173 45.576 ;
     RECT  26.849 48.384 27.277 51.384 ;
     RECT  27.065 52.752 27.277 53.016 ;
     RECT  27.173 27.984 27.308 38.04 ;
     RECT  25.805 8.496 27.389 8.52 ;
     RECT  26.705 6.24 27.461 7.272 ;
     RECT  27.029 24.624 27.565 26.712 ;
     RECT  27.173 39.072 27.605 45.576 ;
     RECT  27.277 48.384 27.605 53.016 ;
     RECT  27.565 24.624 27.673 26.76 ;
     RECT  27.308 27.792 27.673 38.04 ;
     RECT  27.692 6.192 27.709 6.216 ;
     RECT  27.169 54.768 27.745 56.328 ;
     RECT  25.873 57.408 27.745 57.576 ;
     RECT  27.709 5.856 27.779 6.216 ;
     RECT  26.989 9.648 27.779 13.608 ;
     RECT  26.849 46.992 27.853 47.112 ;
     RECT  26.813 14.736 27.889 23.352 ;
     RECT  27.745 54.768 27.965 57.576 ;
     RECT  27.779 5.856 28.001 5.88 ;
     RECT  27.461 7.248 28.037 7.272 ;
     RECT  27.779 9.792 28.069 13.608 ;
     RECT  27.605 48.384 28.105 50.376 ;
     RECT  27.965 55.68 28.325 57.576 ;
     RECT  27.889 14.736 28.393 23.64 ;
     RECT  27.673 24.624 28.393 38.04 ;
     RECT  28.105 48.288 28.393 50.376 ;
     RECT  28.393 14.736 28.465 38.04 ;
     RECT  27.605 39.072 28.465 41.352 ;
     RECT  27.605 42.48 28.501 45.576 ;
     RECT  27.853 46.704 28.501 47.112 ;
     RECT  28.465 7.92 28.573 7.992 ;
     RECT  28.325 57.024 28.681 57.576 ;
     RECT  28.501 42.48 28.789 47.112 ;
     RECT  28.393 48.192 28.789 50.376 ;
     RECT  28.789 42.48 28.969 50.376 ;
     RECT  27.605 51.36 28.969 53.016 ;
     RECT  28.573 7.92 29.257 8.04 ;
     RECT  28.105 54.192 29.365 54.216 ;
     RECT  28.325 55.68 29.365 55.704 ;
     RECT  29.257 7.92 29.408 8.568 ;
     RECT  28.069 9.792 29.408 13.704 ;
     RECT  28.465 14.736 29.408 41.352 ;
     RECT  28.969 42.48 29.408 53.016 ;
     RECT  29.365 54.192 29.408 55.704 ;
     RECT  28.681 57.024 29.408 58.056 ;
     RECT  29.408 2.148 29.512 62.652 ;
     RECT  29.512 2.418 29.704 62.382 ;
     RECT  29.704 57.024 29.801 57.432 ;
     RECT  29.704 7.92 30.197 9 ;
     RECT  29.704 10.272 30.275 55.896 ;
     RECT  30.197 8.016 30.341 9 ;
     RECT  29.801 57.12 30.341 57.432 ;
     RECT  30.275 10.272 30.467 20.568 ;
     RECT  30.341 57.12 30.593 57.144 ;
     RECT  30.275 21.6 31.021 55.896 ;
     RECT  31.021 21.6 31.061 56.472 ;
     RECT  31.061 40.848 31.105 56.472 ;
     RECT  29.704 5.76 31.205 6.84 ;
     RECT  31.105 40.848 31.205 55.944 ;
     RECT  31.205 6 31.277 6.84 ;
     RECT  30.341 8.544 31.277 9 ;
     RECT  31.205 41.424 31.313 55.944 ;
     RECT  30.467 13.584 31.493 20.568 ;
     RECT  31.493 18.528 31.529 20.568 ;
     RECT  31.529 18.528 31.601 20.376 ;
     RECT  30.467 10.272 31.619 12.552 ;
     RECT  31.277 8.544 31.621 8.616 ;
     RECT  31.619 10.272 31.66 11.88 ;
     RECT  31.601 18.528 31.817 19.032 ;
     RECT  31.66 10.272 31.889 11.784 ;
     RECT  31.889 10.272 32.06 11.304 ;
     RECT  31.313 41.424 32.213 44.904 ;
     RECT  31.493 13.584 32.281 17.448 ;
     RECT  31.621 8.496 32.317 8.616 ;
     RECT  32.281 13.392 32.387 17.448 ;
     RECT  32.317 8.496 32.425 8.76 ;
     RECT  32.06 10.176 32.425 11.304 ;
     RECT  32.213 41.424 32.533 43.32 ;
     RECT  32.209 58.128 32.641 58.152 ;
     RECT  32.641 58.128 32.681 58.536 ;
     RECT  32.425 8.496 32.753 11.304 ;
     RECT  32.213 44.304 32.785 44.904 ;
     RECT  31.313 45.936 32.785 55.944 ;
     RECT  32.785 44.304 32.861 55.944 ;
     RECT  31.061 21.6 32.897 39.384 ;
     RECT  32.387 13.392 32.933 13.944 ;
     RECT  32.861 44.304 33.005 49.896 ;
     RECT  32.861 51.168 33.041 55.944 ;
     RECT  32.533 40.512 33.073 43.32 ;
     RECT  32.897 21.648 33.077 39.384 ;
     RECT  32.753 8.496 33.149 8.76 ;
     RECT  32.387 14.928 33.181 17.448 ;
     RECT  31.817 18.528 33.181 18.984 ;
     RECT  33.005 46.848 33.185 49.896 ;
     RECT  33.077 21.648 33.293 28.2 ;
     RECT  33.005 44.304 33.437 45.432 ;
     RECT  33.041 54.096 33.577 55.944 ;
     RECT  31.601 20.352 33.649 20.376 ;
     RECT  33.077 29.184 33.683 39.384 ;
     RECT  33.577 54.096 33.683 56.904 ;
     RECT  33.149 8.736 33.689 8.76 ;
     RECT  33.073 40.416 33.689 43.32 ;
     RECT  32.933 13.392 33.721 13.848 ;
     RECT  31.277 6.672 33.761 6.84 ;
     RECT  33.683 54.096 33.761 55.272 ;
     RECT  33.761 54.096 33.779 55.08 ;
     RECT  33.761 6.672 33.833 6.696 ;
     RECT  33.185 47.232 34.009 49.896 ;
     RECT  33.041 51.168 34.009 52.824 ;
     RECT  33.683 56.88 34.009 56.904 ;
     RECT  33.689 43.008 34.225 43.32 ;
     RECT  33.437 44.304 34.225 45.288 ;
     RECT  32.753 10.416 34.369 11.304 ;
     RECT  33.293 21.792 34.441 28.2 ;
     RECT  34.009 56.88 34.549 57.048 ;
     RECT  32.681 58.512 34.585 58.536 ;
     RECT  34.369 9.792 34.657 11.304 ;
     RECT  33.721 12.528 34.657 13.848 ;
     RECT  33.689 40.416 34.765 41.928 ;
     RECT  34.225 43.008 34.765 45.288 ;
     RECT  34.549 56.88 34.801 57.144 ;
     RECT  34.657 9.792 34.808 13.848 ;
     RECT  33.181 14.928 34.808 18.984 ;
     RECT  33.649 20.352 34.808 20.424 ;
     RECT  34.441 21.744 34.808 28.2 ;
     RECT  33.683 29.184 34.808 39.048 ;
     RECT  34.765 40.416 34.808 45.288 ;
     RECT  34.009 47.232 34.808 52.824 ;
     RECT  33.779 54.192 34.808 55.08 ;
     RECT  34.801 56.304 34.808 57.144 ;
     RECT  34.585 58.128 34.808 58.536 ;
     RECT  34.808 2.148 34.912 62.652 ;
     RECT  34.912 2.418 35.104 62.382 ;
     RECT  35.104 56.304 35.129 58.152 ;
     RECT  35.104 20.4 35.165 39.096 ;
     RECT  35.104 11.136 35.201 13.656 ;
     RECT  35.165 28.944 35.237 39.096 ;
     RECT  35.129 56.736 35.237 58.152 ;
     RECT  35.104 9.696 35.345 9.816 ;
     RECT  35.237 29.232 35.345 39.096 ;
     RECT  35.201 11.136 35.741 13.608 ;
     RECT  35.741 12.96 35.993 13.608 ;
     RECT  35.741 11.136 36.029 11.976 ;
     RECT  35.104 51.12 36.097 53.016 ;
     RECT  35.104 14.64 36.133 17.4 ;
     RECT  35.993 13.056 36.137 13.608 ;
     RECT  35.104 18.768 36.169 18.792 ;
     RECT  35.104 40.32 36.169 43.128 ;
     RECT  35.104 44.112 36.169 49.416 ;
     RECT  36.133 14.64 36.205 17.64 ;
     RECT  36.169 40.32 36.245 49.416 ;
     RECT  36.205 14.64 36.277 17.688 ;
     RECT  36.169 18.768 36.277 19.368 ;
     RECT  35.104 54.192 36.353 54.696 ;
     RECT  35.165 20.4 36.421 27.96 ;
     RECT  35.345 9.696 36.461 9.72 ;
     RECT  36.097 50.832 36.565 53.016 ;
     RECT  35.104 6.816 36.569 7.656 ;
     RECT  36.029 11.136 36.781 11.688 ;
     RECT  36.569 7.584 36.785 7.656 ;
     RECT  36.565 50.448 36.961 53.016 ;
     RECT  36.781 10.56 36.997 11.688 ;
     RECT  35.345 29.568 37.033 39.096 ;
     RECT  37.033 29.136 37.073 39.096 ;
     RECT  36.277 14.64 37.105 19.368 ;
     RECT  37.105 14.448 37.109 19.368 ;
     RECT  36.997 10.56 37.145 12.024 ;
     RECT  37.109 18.624 37.249 19.368 ;
     RECT  36.421 20.4 37.249 28.152 ;
     RECT  36.961 50.256 37.253 53.016 ;
     RECT  36.785 7.632 37.321 7.656 ;
     RECT  37.249 18.624 37.357 28.152 ;
     RECT  37.073 29.136 37.357 37.656 ;
     RECT  36.245 40.32 37.429 49.272 ;
     RECT  37.073 38.688 37.465 39.096 ;
     RECT  37.429 40.08 37.465 49.272 ;
     RECT  37.253 50.256 37.465 52.344 ;
     RECT  35.237 56.736 37.573 57.864 ;
     RECT  37.321 7.632 37.609 7.992 ;
     RECT  36.637 9.12 37.609 9.144 ;
     RECT  36.353 54.576 37.645 54.696 ;
     RECT  37.609 7.632 37.649 9.144 ;
     RECT  37.649 7.968 37.685 8.52 ;
     RECT  37.393 6.528 37.933 6.552 ;
     RECT  37.573 56.496 38.041 57.864 ;
     RECT  36.137 13.056 38.113 13.08 ;
     RECT  37.109 14.448 38.113 17.64 ;
     RECT  37.357 18.624 38.225 37.656 ;
     RECT  38.113 13.056 38.257 17.64 ;
     RECT  38.225 18.624 38.257 37.224 ;
     RECT  37.645 54.48 38.261 54.696 ;
     RECT  37.145 10.608 38.297 12.024 ;
     RECT  37.933 6.528 38.405 6.84 ;
     RECT  37.465 38.688 38.473 52.344 ;
     RECT  38.297 10.752 38.509 12.024 ;
     RECT  38.257 13.056 38.509 37.224 ;
     RECT  38.041 56.208 38.581 57.864 ;
     RECT  37.685 8.496 38.689 8.52 ;
     RECT  38.689 7.872 38.729 9.384 ;
     RECT  38.581 56.208 39.017 58.152 ;
     RECT  38.473 38.688 39.197 53.16 ;
     RECT  38.509 10.752 39.329 37.224 ;
     RECT  38.473 54.336 39.373 54.36 ;
     RECT  39.197 53.136 39.589 53.16 ;
     RECT  39.373 54.336 39.589 55.272 ;
     RECT  38.405 6.816 39.625 6.84 ;
     RECT  38.729 7.872 39.625 7.896 ;
     RECT  39.625 6.816 39.697 7.896 ;
     RECT  39.697 6.768 39.769 7.896 ;
     RECT  38.729 9.36 39.769 9.384 ;
     RECT  39.329 10.752 40.057 37.656 ;
     RECT  39.197 38.688 40.057 52.104 ;
     RECT  39.769 6.768 40.165 9.384 ;
     RECT  40.165 6.096 40.208 9.384 ;
     RECT  40.057 10.752 40.208 52.104 ;
     RECT  39.589 53.136 40.208 55.272 ;
     RECT  39.017 56.4 40.208 58.152 ;
     RECT  40.208 2.148 40.312 62.652 ;
     RECT  40.312 2.418 40.504 62.382 ;
     RECT  40.504 11.52 40.637 36.936 ;
     RECT  40.504 53.52 40.673 53.592 ;
     RECT  40.504 54.624 40.673 55.272 ;
     RECT  40.673 54.624 40.889 55.176 ;
     RECT  40.504 37.92 41.075 52.488 ;
     RECT  41.075 37.92 41.113 51.816 ;
     RECT  40.504 6.096 41.285 7.224 ;
     RECT  40.637 11.664 41.321 36.936 ;
     RECT  41.113 37.92 41.321 51.48 ;
     RECT  40.504 10.272 41.393 10.296 ;
     RECT  40.889 54.624 41.429 54.648 ;
     RECT  41.285 6.816 41.5 7.224 ;
     RECT  41.321 14.976 41.609 36.936 ;
     RECT  41.609 17.616 41.645 36.936 ;
     RECT  41.645 17.904 41.785 36.936 ;
     RECT  41.321 37.92 41.785 49.8 ;
     RECT  41.785 17.904 41.897 49.8 ;
     RECT  40.504 58.128 41.965 58.152 ;
     RECT  40.504 56.352 42.037 56.76 ;
     RECT  41.897 17.904 42.257 20.184 ;
     RECT  42.037 56.352 42.325 57 ;
     RECT  41.321 11.664 42.433 13.08 ;
     RECT  42.109 51.888 42.433 51.912 ;
     RECT  41.897 21.168 42.545 49.8 ;
     RECT  40.673 53.568 42.577 53.592 ;
     RECT  42.433 10.848 42.581 13.08 ;
     RECT  42.581 11.664 42.613 13.08 ;
     RECT  41.609 14.976 42.721 16.584 ;
     RECT  42.613 11.664 42.757 13.368 ;
     RECT  42.721 14.4 42.757 16.584 ;
     RECT  42.257 17.904 42.757 19.944 ;
     RECT  42.433 51.168 42.757 51.912 ;
     RECT  42.577 53.568 42.757 53.832 ;
     RECT  42.545 43.104 42.761 49.8 ;
     RECT  42.325 56.304 42.793 57 ;
     RECT  41.965 58.08 42.793 58.152 ;
     RECT  42.545 21.168 42.833 41.64 ;
     RECT  42.761 48.432 42.908 49.8 ;
     RECT  42.908 48.432 42.977 50.136 ;
     RECT  42.757 51.168 43.013 53.832 ;
     RECT  42.793 56.304 43.121 58.152 ;
     RECT  43.013 51.6 43.157 53.64 ;
     RECT  42.757 11.664 43.225 19.944 ;
     RECT  42.833 21.168 43.225 38.616 ;
     RECT  42.833 39.6 43.265 41.64 ;
     RECT  42.037 55.248 43.481 55.272 ;
     RECT  42.977 48.576 43.549 50.136 ;
     RECT  43.121 56.304 43.697 57.624 ;
     RECT  43.549 10.224 43.801 10.248 ;
     RECT  43.225 11.664 43.801 38.616 ;
     RECT  43.549 48.576 43.877 50.568 ;
     RECT  41.5 7.2 43.913 7.224 ;
     RECT  43.265 39.648 43.981 41.64 ;
     RECT  42.761 43.104 43.981 47.304 ;
     RECT  43.877 48.576 43.981 50.424 ;
     RECT  43.981 39.648 44.017 41.976 ;
     RECT  43.981 43.104 44.017 50.424 ;
     RECT  43.801 10.224 44.021 38.616 ;
     RECT  43.157 51.6 44.057 52.008 ;
     RECT  44.005 8.352 44.092 8.376 ;
     RECT  44.017 39.648 44.165 50.424 ;
     RECT  44.057 51.648 44.197 52.008 ;
     RECT  43.157 52.992 44.197 53.64 ;
     RECT  44.021 10.224 44.243 35.976 ;
     RECT  44.243 30.192 44.309 35.976 ;
     RECT  44.197 51.648 44.345 53.64 ;
     RECT  44.021 37.056 44.377 38.616 ;
     RECT  44.165 46.656 44.489 50.424 ;
     RECT  44.243 10.224 44.561 28.968 ;
     RECT  44.377 37.056 44.881 38.664 ;
     RECT  44.165 39.648 44.881 45.576 ;
     RECT  43.697 56.352 45.097 57.624 ;
     RECT  44.309 30.336 45.133 35.976 ;
     RECT  44.881 37.056 45.133 45.576 ;
     RECT  44.413 54.576 45.169 54.6 ;
     RECT  44.489 47.424 45.457 50.424 ;
     RECT  44.345 51.648 45.457 53.064 ;
     RECT  45.133 30.336 45.493 45.576 ;
     RECT  45.457 46.608 45.493 53.064 ;
     RECT  45.493 30.336 45.565 53.064 ;
     RECT  44.561 10.896 45.608 16.104 ;
     RECT  44.561 17.088 45.608 28.968 ;
     RECT  45.565 30.144 45.608 53.064 ;
     RECT  45.169 54.576 45.608 54.696 ;
     RECT  45.097 55.824 45.608 57.624 ;
     RECT  45.608 2.148 45.712 62.652 ;
     RECT  45.712 2.418 45.904 62.382 ;
     RECT  45.904 8.256 45.965 9.624 ;
     RECT  45.965 8.448 46.307 9.624 ;
     RECT  46.307 9.072 46.547 9.624 ;
     RECT  45.904 10.8 46.721 13.992 ;
     RECT  45.904 54.096 46.829 56.616 ;
     RECT  45.904 19.152 46.933 36.84 ;
     RECT  45.904 37.968 46.933 49.32 ;
     RECT  45.904 6.816 46.969 6.84 ;
     RECT  46.721 11.664 47.045 13.992 ;
     RECT  45.904 15.024 47.149 18.168 ;
     RECT  46.933 19.152 47.149 49.32 ;
     RECT  45.904 50.304 47.149 52.776 ;
     RECT  47.149 19.152 47.185 52.776 ;
     RECT  46.829 54.096 47.185 55.992 ;
     RECT  47.149 14.64 47.221 18.168 ;
     RECT  47.185 19.152 47.221 55.992 ;
     RECT  47.221 14.64 47.261 55.992 ;
     RECT  46.547 9.072 47.333 9.096 ;
     RECT  47.261 32.304 47.369 55.992 ;
     RECT  47.261 14.64 47.549 31.272 ;
     RECT  47.549 14.64 47.801 15.192 ;
     RECT  47.045 11.664 47.869 13.656 ;
     RECT  47.369 55.872 47.953 55.992 ;
     RECT  47.545 10.176 47.977 10.2 ;
     RECT  47.869 11.28 47.977 13.656 ;
     RECT  47.369 32.304 48.053 42.024 ;
     RECT  47.977 10.176 48.125 13.656 ;
     RECT  47.953 55.968 48.161 55.992 ;
     RECT  46.969 6.816 48.233 7.416 ;
     RECT  47.549 16.272 48.341 31.272 ;
     RECT  48.053 33.792 48.373 42.024 ;
     RECT  47.369 43.008 48.373 54.648 ;
     RECT  48.373 33.792 48.377 54.648 ;
     RECT  47.801 15.168 48.521 15.192 ;
     RECT  47.617 8.88 48.589 8.904 ;
     RECT  48.125 10.176 48.589 13.608 ;
     RECT  48.341 16.272 48.589 18.168 ;
     RECT  48.377 33.792 48.629 49.608 ;
     RECT  48.341 19.152 48.737 31.272 ;
     RECT  48.737 23.856 48.769 31.272 ;
     RECT  48.053 32.304 48.769 32.808 ;
     RECT  48.377 50.592 48.773 54.648 ;
     RECT  48.589 8.88 48.953 13.608 ;
     RECT  48.953 9.312 48.989 13.608 ;
     RECT  48.773 51.456 49.165 54.648 ;
     RECT  47.941 57.12 49.201 57.144 ;
     RECT  45.904 58.128 49.201 58.68 ;
     RECT  48.989 9.456 49.237 13.608 ;
     RECT  49.237 9.456 49.283 14.376 ;
     RECT  48.629 33.792 49.421 37.992 ;
     RECT  49.165 51.456 49.633 54.936 ;
     RECT  49.561 56.112 49.633 56.136 ;
     RECT  48.589 16.224 49.669 18.168 ;
     RECT  49.669 15.888 49.724 18.168 ;
     RECT  48.737 19.152 49.724 22.824 ;
     RECT  49.283 10.32 49.777 14.376 ;
     RECT  49.724 15.888 49.777 22.824 ;
     RECT  49.777 10.32 49.885 22.824 ;
     RECT  48.769 23.856 49.885 32.808 ;
     RECT  49.633 51.456 49.885 56.136 ;
     RECT  49.885 10.32 49.925 32.808 ;
     RECT  49.885 51.216 50.033 56.136 ;
     RECT  49.421 33.888 50.173 37.992 ;
     RECT  48.629 38.976 50.173 49.608 ;
     RECT  50.173 33.888 50.209 49.608 ;
     RECT  50.033 55.68 50.677 56.136 ;
     RECT  49.201 57.12 50.677 58.68 ;
     RECT  49.925 31.104 50.749 32.808 ;
     RECT  50.209 33.888 50.749 50.088 ;
     RECT  48.233 6.816 51.008 7.368 ;
     RECT  50.137 8.832 51.008 8.856 ;
     RECT  49.925 10.32 51.008 29.832 ;
     RECT  50.749 31.104 51.008 50.088 ;
     RECT  50.033 51.216 51.008 54.36 ;
     RECT  50.677 55.68 51.008 58.68 ;
     RECT  51.008 2.148 51.112 62.652 ;
     RECT  51.112 2.418 51.304 62.382 ;
     RECT  51.304 55.632 51.437 57.144 ;
     RECT  51.304 10.848 51.473 13.608 ;
     RECT  51.304 18.816 51.875 24.648 ;
     RECT  51.304 31.488 52.085 50.136 ;
     RECT  52.085 31.488 52.301 50.088 ;
     RECT  51.304 51.264 52.301 54.504 ;
     RECT  51.875 18.816 52.333 23.4 ;
     RECT  52.301 31.488 52.364 49.56 ;
     RECT  51.473 10.848 52.405 11.544 ;
     RECT  51.473 12.72 52.405 13.608 ;
     RECT  51.304 14.784 52.405 17.688 ;
     RECT  52.364 30.816 52.451 49.56 ;
     RECT  51.437 55.632 52.499 57.048 ;
     RECT  51.304 25.824 52.513 29.784 ;
     RECT  52.499 55.632 52.549 56.712 ;
     RECT  51.875 24.432 52.801 24.648 ;
     RECT  52.513 25.824 52.801 30.168 ;
     RECT  52.405 10.176 52.841 11.544 ;
     RECT  52.405 12.72 52.873 17.688 ;
     RECT  52.333 18.672 52.873 23.4 ;
     RECT  52.873 12.72 52.945 23.4 ;
     RECT  52.801 24.432 52.945 30.168 ;
     RECT  52.301 51.36 53.089 54.504 ;
     RECT  52.549 55.488 53.089 56.712 ;
     RECT  51.304 58.656 53.197 58.68 ;
     RECT  53.197 58.08 53.237 58.68 ;
     RECT  53.089 51.36 53.309 56.712 ;
     RECT  53.237 58.08 53.315 58.104 ;
     RECT  52.945 12.72 53.377 30.168 ;
     RECT  53.377 12.528 53.557 30.168 ;
     RECT  52.451 31.296 53.557 49.56 ;
     RECT  53.309 51.36 53.557 54.744 ;
     RECT  53.557 12.528 53.633 54.744 ;
     RECT  53.633 13.056 53.669 53.4 ;
     RECT  53.633 54.528 53.705 54.744 ;
     RECT  52.841 10.176 53.809 11.256 ;
     RECT  53.309 55.824 53.845 56.712 ;
     RECT  53.669 25.2 53.849 53.4 ;
     RECT  53.845 55.824 54.173 57.48 ;
     RECT  54.097 7.92 54.241 7.944 ;
     RECT  53.809 9.648 54.317 11.256 ;
     RECT  53.669 13.056 54.317 23.976 ;
     RECT  54.317 13.056 54.425 17.304 ;
     RECT  54.317 9.744 54.461 11.256 ;
     RECT  54.425 13.056 54.601 15.576 ;
     RECT  54.317 18.336 54.637 23.976 ;
     RECT  53.849 25.2 54.637 49.56 ;
     RECT  53.849 50.592 54.637 53.4 ;
     RECT  53.705 54.528 54.637 54.552 ;
     RECT  54.62 58.656 54.707 58.68 ;
     RECT  54.313 59.856 54.707 59.88 ;
     RECT  54.637 50.592 54.745 54.552 ;
     RECT  54.637 18.336 54.785 49.56 ;
     RECT  54.461 9.744 54.821 9.768 ;
     RECT  54.461 10.8 54.853 11.256 ;
     RECT  54.601 12.528 54.853 15.576 ;
     RECT  54.853 10.8 54.857 15.576 ;
     RECT  54.745 50.592 55.073 54.696 ;
     RECT  55.073 51.312 55.109 54.696 ;
     RECT  54.785 36.336 55.145 49.56 ;
     RECT  54.173 56.4 55.145 57.48 ;
     RECT  54.425 16.896 55.181 17.304 ;
     RECT  54.241 7.92 55.217 8.568 ;
     RECT  55.109 51.36 55.249 54.696 ;
     RECT  51.304 6.816 55.321 6.84 ;
     RECT  55.181 16.896 55.325 16.92 ;
     RECT  55.321 6.24 55.361 6.84 ;
     RECT  55.249 51.36 55.361 54.744 ;
     RECT  54.857 10.8 55.573 14.136 ;
     RECT  55.145 46.272 55.573 49.56 ;
     RECT  54.857 15.552 55.681 15.576 ;
     RECT  54.785 18.336 55.753 35.352 ;
     RECT  55.145 36.336 55.753 45.24 ;
     RECT  55.681 15.552 55.789 15.816 ;
     RECT  55.573 10.176 56.077 14.136 ;
     RECT  55.361 53.52 56.149 54.744 ;
     RECT  55.789 15.552 56.365 16.392 ;
     RECT  55.753 18.144 56.365 45.24 ;
     RECT  55.573 46.272 56.365 49.896 ;
     RECT  55.361 51.36 56.365 52.44 ;
     RECT  55.361 6.24 56.408 6.264 ;
     RECT  55.217 8.544 56.408 8.568 ;
     RECT  56.077 10.176 56.408 14.232 ;
     RECT  56.365 15.552 56.408 16.584 ;
     RECT  56.365 18.144 56.408 52.44 ;
     RECT  56.149 53.52 56.408 54.888 ;
     RECT  55.145 56.4 56.408 57.192 ;
     RECT  56.408 2.148 56.512 62.652 ;
     RECT  56.512 2.418 56.704 62.382 ;
     RECT  56.704 13.584 56.765 17.448 ;
     RECT  56.704 55.872 56.765 57.048 ;
     RECT  56.704 50.736 56.909 54.888 ;
     RECT  56.704 11.712 57.089 12.552 ;
     RECT  56.765 55.872 57.197 56.76 ;
     RECT  56.909 51.456 57.269 54.888 ;
     RECT  57.269 52.224 57.34 54.888 ;
     RECT  56.704 18.768 57.413 49.56 ;
     RECT  57.197 56.208 57.521 56.76 ;
     RECT  57.413 18.768 57.593 40.632 ;
     RECT  57.089 11.712 57.733 11.832 ;
     RECT  57.34 54.144 57.733 54.888 ;
     RECT  57.413 41.664 57.769 49.56 ;
     RECT  56.704 7.344 57.773 8.568 ;
     RECT  57.593 19.344 57.773 40.632 ;
     RECT  57.521 56.352 57.985 56.76 ;
     RECT  56.704 58.656 58.057 58.68 ;
     RECT  57.733 9.792 58.061 9.816 ;
     RECT  57.985 56.352 58.061 57.048 ;
     RECT  56.765 14.112 58.129 17.448 ;
     RECT  57.34 52.224 58.205 53.016 ;
     RECT  58.057 58.128 58.205 58.68 ;
     RECT  57.773 19.92 58.381 40.632 ;
     RECT  57.769 41.664 58.381 49.944 ;
     RECT  58.381 19.92 58.403 49.944 ;
     RECT  58.345 9.936 58.417 9.96 ;
     RECT  58.129 13.536 58.453 17.88 ;
     RECT  57.733 54.144 58.493 55.224 ;
     RECT  58.417 9.936 58.561 10.056 ;
     RECT  57.733 11.088 58.561 11.832 ;
     RECT  58.453 13.488 58.693 17.88 ;
     RECT  58.403 44.496 58.705 49.944 ;
     RECT  58.061 56.736 58.705 57.048 ;
     RECT  58.205 58.128 58.705 58.152 ;
     RECT  58.205 52.368 58.709 53.016 ;
     RECT  58.561 9.936 58.741 11.832 ;
     RECT  58.693 13.104 58.741 17.88 ;
     RECT  58.741 9.936 58.745 17.88 ;
     RECT  58.745 10.032 58.777 17.88 ;
     RECT  58.403 19.92 58.789 43.32 ;
     RECT  57.773 7.344 58.817 8.088 ;
     RECT  58.777 10.032 58.835 18.168 ;
     RECT  58.789 19.392 58.853 43.32 ;
     RECT  58.705 44.496 58.921 50.712 ;
     RECT  58.921 44.496 58.925 50.808 ;
     RECT  58.709 52.368 58.961 52.584 ;
     RECT  58.853 19.392 59.069 27.096 ;
     RECT  58.835 10.032 59.321 11.976 ;
     RECT  58.853 28.08 59.389 43.32 ;
     RECT  58.925 44.496 59.389 48.12 ;
     RECT  58.961 52.368 59.497 52.44 ;
     RECT  58.493 54.624 59.573 55.224 ;
     RECT  58.817 7.344 59.605 7.992 ;
     RECT  59.389 28.08 59.645 48.12 ;
     RECT  59.645 43.632 59.681 48.12 ;
     RECT  58.705 56.736 59.753 58.152 ;
     RECT  59.573 54.624 59.845 54.936 ;
     RECT  58.835 13.056 59.857 18.168 ;
     RECT  59.069 19.392 59.857 20.232 ;
     RECT  59.317 59.184 59.857 59.208 ;
     RECT  59.605 7.248 59.891 7.992 ;
     RECT  58.925 49.152 59.891 50.808 ;
     RECT  59.681 44.496 59.933 48.12 ;
     RECT  59.753 56.736 59.933 57.384 ;
     RECT  59.857 58.608 59.941 59.88 ;
     RECT  59.321 11.376 59.965 11.976 ;
     RECT  59.857 13.056 59.965 20.232 ;
     RECT  59.069 21.552 59.965 27.096 ;
     RECT  59.645 28.08 59.965 42.648 ;
     RECT  59.891 49.152 59.969 50.76 ;
     RECT  59.965 11.376 59.987 20.232 ;
     RECT  59.941 58.704 60.028 59.208 ;
     RECT  59.965 21.552 60.077 42.648 ;
     RECT  59.321 10.032 60.217 10.056 ;
     RECT  59.933 45.168 60.289 48.12 ;
     RECT  59.969 49.152 60.289 49.56 ;
     RECT  59.497 52.272 60.325 52.44 ;
     RECT  59.845 53.568 60.329 54.936 ;
     RECT  59.987 17.616 60.509 20.232 ;
     RECT  59.987 11.376 60.661 16.296 ;
     RECT  59.891 7.344 60.707 7.992 ;
     RECT  60.077 21.552 60.725 27.336 ;
     RECT  60.217 9.072 60.973 10.056 ;
     RECT  60.661 11.328 60.973 16.296 ;
     RECT  60.077 28.368 60.973 42.648 ;
     RECT  60.289 45.168 60.997 49.56 ;
     RECT  60.028 59.184 61.117 59.208 ;
     RECT  59.933 56.736 61.153 57.144 ;
     RECT  60.997 45.024 61.225 49.56 ;
     RECT  59.969 50.736 61.225 50.76 ;
     RECT  60.973 9.072 61.297 16.296 ;
     RECT  60.509 17.616 61.297 20.184 ;
     RECT  60.725 23.28 61.441 27.336 ;
     RECT  60.973 28.368 61.441 43.608 ;
     RECT  61.225 45.024 61.441 50.76 ;
     RECT  60.325 51.936 61.441 52.44 ;
     RECT  61.297 9.072 61.513 20.184 ;
     RECT  60.725 21.552 61.513 21.624 ;
     RECT  61.441 45.024 61.549 52.44 ;
     RECT  61.153 55.392 61.628 55.416 ;
     RECT  61.153 56.448 61.628 57.144 ;
     RECT  60.329 53.568 61.669 54.12 ;
     RECT  61.628 55.392 61.669 57.144 ;
     RECT  61.441 23.28 61.765 43.608 ;
     RECT  61.549 45.024 61.765 52.536 ;
     RECT  61.765 23.28 61.801 52.536 ;
     RECT  60.707 7.968 61.808 7.992 ;
     RECT  61.513 9.072 61.808 21.624 ;
     RECT  61.801 23.28 61.808 52.584 ;
     RECT  61.669 53.568 61.808 57.144 ;
     RECT  61.117 58.656 61.808 59.208 ;
     RECT  61.808 2.148 61.912 62.652 ;
     RECT  61.912 2.418 62.104 62.382 ;
     RECT  62.104 45.504 62.201 52.536 ;
     RECT  62.104 8.448 62.237 9.816 ;
     RECT  62.201 51.888 62.237 52.536 ;
     RECT  62.237 9.792 62.273 9.816 ;
     RECT  62.104 15.84 62.381 44.184 ;
     RECT  62.237 52.032 62.561 52.536 ;
     RECT  62.104 12.48 62.813 14.52 ;
     RECT  62.104 53.52 63.011 54.552 ;
     RECT  62.381 15.84 63.029 19.848 ;
     RECT  62.104 10.8 63.169 10.824 ;
     RECT  62.201 45.504 63.241 50.856 ;
     RECT  62.104 55.776 63.241 55.896 ;
     RECT  62.104 57.024 63.241 57.144 ;
     RECT  62.104 7.392 63.253 7.416 ;
     RECT  62.237 8.448 63.253 8.472 ;
     RECT  63.253 7.392 63.299 8.472 ;
     RECT  63.029 16.032 63.317 19.848 ;
     RECT  62.561 52.272 63.317 52.536 ;
     RECT  63.011 53.52 63.317 53.832 ;
     RECT  63.253 6.24 63.34 6.264 ;
     RECT  63.169 10.56 63.349 10.824 ;
     RECT  63.097 11.952 63.349 11.976 ;
     RECT  62.381 20.832 63.353 44.184 ;
     RECT  63.241 45.504 63.353 51.24 ;
     RECT  62.813 13.248 63.385 14.52 ;
     RECT  63.353 21.072 63.425 44.184 ;
     RECT  63.299 7.584 63.461 8.472 ;
     RECT  63.425 21.648 63.533 44.184 ;
     RECT  63.353 48.432 63.565 51.24 ;
     RECT  63.317 52.272 63.565 52.488 ;
     RECT  63.349 10.56 63.713 11.976 ;
     RECT  63.713 10.56 63.781 11.112 ;
     RECT  63.565 48.432 63.857 52.488 ;
     RECT  63.385 13.248 63.961 14.856 ;
     RECT  63.533 23.28 64.001 44.184 ;
     RECT  63.961 12.432 64.177 14.856 ;
     RECT  63.317 16.032 64.177 19.32 ;
     RECT  63.317 53.52 64.213 53.592 ;
     RECT  64.177 12.432 64.217 19.32 ;
     RECT  63.857 50.784 64.259 52.488 ;
     RECT  64.001 23.568 64.321 44.184 ;
     RECT  63.353 45.504 64.321 47.448 ;
     RECT  63.241 55.776 64.321 57.432 ;
     RECT  63.781 10.176 64.361 11.112 ;
     RECT  64.321 23.568 64.429 47.448 ;
     RECT  63.857 48.432 64.429 49.8 ;
     RECT  64.321 55.776 64.429 57.576 ;
     RECT  64.217 15.696 64.537 19.32 ;
     RECT  64.429 20.4 64.537 20.424 ;
     RECT  64.429 23.568 64.577 49.8 ;
     RECT  64.259 50.784 64.685 51.24 ;
     RECT  62.104 59.184 64.717 59.208 ;
     RECT  64.361 10.224 64.741 11.112 ;
     RECT  64.259 52.224 64.753 52.488 ;
     RECT  64.213 53.472 64.753 53.592 ;
     RECT  64.577 23.568 64.865 49.32 ;
     RECT  64.753 52.224 64.865 53.592 ;
     RECT  64.741 10.224 64.933 11.16 ;
     RECT  64.217 12.432 64.933 14.712 ;
     RECT  64.865 23.568 65.257 44.472 ;
     RECT  64.717 58.8 65.257 59.208 ;
     RECT  64.429 55.152 65.261 57.576 ;
     RECT  65.257 58.8 65.297 59.304 ;
     RECT  65.261 55.152 65.315 55.272 ;
     RECT  65.257 23.28 65.333 44.472 ;
     RECT  64.685 50.832 65.365 51.24 ;
     RECT  64.865 52.224 65.365 52.248 ;
     RECT  64.609 9.12 65.437 9.144 ;
     RECT  65.437 9.12 65.468 9.24 ;
     RECT  65.261 56.448 65.473 57.576 ;
     RECT  63.461 7.584 65.509 7.608 ;
     RECT  65.468 8.832 65.509 9.24 ;
     RECT  64.865 53.424 65.513 53.592 ;
     RECT  65.509 7.584 65.545 9.24 ;
     RECT  64.933 10.224 65.545 14.712 ;
     RECT  65.473 56.448 65.549 58.152 ;
     RECT  65.545 7.584 65.555 14.712 ;
     RECT  65.333 29.28 65.557 44.472 ;
     RECT  65.549 56.496 65.585 58.152 ;
     RECT  65.555 8.112 65.596 11.736 ;
     RECT  63.533 21.648 65.617 22.104 ;
     RECT  65.557 29.28 65.621 44.184 ;
     RECT  65.555 12.816 65.693 14.712 ;
     RECT  65.621 29.28 65.729 30.024 ;
     RECT  65.365 50.832 65.729 52.248 ;
     RECT  65.596 8.496 65.765 11.736 ;
     RECT  65.693 12.816 65.945 14.472 ;
     RECT  64.865 45.504 66.013 49.32 ;
     RECT  65.617 21.504 66.049 22.104 ;
     RECT  65.333 23.28 66.049 28.296 ;
     RECT  64.537 15.696 66.121 20.424 ;
     RECT  65.729 51.84 66.157 52.248 ;
     RECT  66.121 15.456 66.229 20.424 ;
     RECT  66.049 21.504 66.229 28.296 ;
     RECT  65.545 54.096 66.697 54.12 ;
     RECT  65.621 31.056 66.709 44.184 ;
     RECT  65.297 59.28 66.709 59.304 ;
     RECT  66.661 60.384 66.709 60.408 ;
     RECT  66.709 30.768 66.716 44.184 ;
     RECT  66.229 15.456 66.769 28.296 ;
     RECT  65.729 29.28 66.769 29.304 ;
     RECT  65.585 56.496 66.841 57.816 ;
     RECT  65.765 10.896 66.949 11.736 ;
     RECT  65.729 50.832 67.057 50.856 ;
     RECT  66.013 45.504 67.093 49.608 ;
     RECT  67.057 50.64 67.093 50.856 ;
     RECT  65.765 8.496 67.165 9.528 ;
     RECT  67.165 7.968 67.208 9.528 ;
     RECT  66.949 10.896 67.208 12.072 ;
     RECT  65.945 13.728 67.208 14.472 ;
     RECT  66.769 15.456 67.208 29.304 ;
     RECT  66.716 30.48 67.208 44.184 ;
     RECT  67.093 45.504 67.208 50.856 ;
     RECT  66.157 51.84 67.208 52.824 ;
     RECT  66.697 54.096 67.208 54.216 ;
     RECT  65.315 55.248 67.208 55.272 ;
     RECT  66.841 56.448 67.208 57.816 ;
     RECT  66.709 59.28 67.208 60.408 ;
     RECT  67.208 2.148 67.312 62.652 ;
     RECT  67.312 2.418 67.504 62.382 ;
     RECT  67.504 15.504 67.961 17.112 ;
     RECT  67.504 31.2 68.105 50.664 ;
     RECT  67.504 51.936 68.105 58.104 ;
     RECT  68.105 51.936 68.213 54.36 ;
     RECT  67.504 11.376 68.249 14.472 ;
     RECT  68.249 11.904 68.357 14.472 ;
     RECT  68.105 46.512 68.387 50.664 ;
     RECT  68.387 46.896 68.393 50.664 ;
     RECT  67.504 18.192 68.429 29.304 ;
     RECT  67.961 15.552 68.533 17.112 ;
     RECT  68.429 18.192 68.533 20.184 ;
     RECT  68.105 31.2 68.569 45.432 ;
     RECT  67.504 9.504 68.605 10.2 ;
     RECT  68.357 12.432 68.609 14.472 ;
     RECT  68.105 55.44 68.753 58.104 ;
     RECT  68.753 55.44 68.771 57.576 ;
     RECT  68.213 51.936 68.861 52.296 ;
     RECT  68.771 55.44 68.861 57.48 ;
     RECT  68.429 21.264 68.917 29.304 ;
     RECT  67.504 7.968 68.929 7.992 ;
     RECT  68.605 9.504 68.929 10.92 ;
     RECT  68.929 7.968 68.933 10.92 ;
     RECT  68.933 7.968 68.969 9.528 ;
     RECT  68.861 51.936 69.001 51.96 ;
     RECT  68.213 53.376 69.004 54.36 ;
     RECT  68.569 30.864 69.005 45.432 ;
     RECT  68.861 57.456 69.149 57.48 ;
     RECT  68.933 10.848 69.325 10.92 ;
     RECT  69.004 53.376 69.361 54.168 ;
     RECT  69.325 10.848 69.433 11.4 ;
     RECT  68.609 12.432 69.433 13.944 ;
     RECT  68.917 21.264 69.433 29.496 ;
     RECT  69.433 10.848 69.577 13.944 ;
     RECT  68.533 15.552 69.577 20.184 ;
     RECT  69.005 31.2 69.689 45.432 ;
     RECT  68.969 8.544 69.761 9.528 ;
     RECT  68.393 46.896 69.793 50.472 ;
     RECT  69.689 34.08 69.797 45.432 ;
     RECT  69.577 10.848 69.829 20.184 ;
     RECT  69.433 21.264 69.829 30.216 ;
     RECT  69.793 46.608 69.905 50.472 ;
     RECT  68.861 55.44 69.937 56.424 ;
     RECT  69.937 55.44 69.973 57 ;
     RECT  69.905 46.752 70.009 50.472 ;
     RECT  69.001 51.792 70.009 51.96 ;
     RECT  69.361 52.944 70.013 54.168 ;
     RECT  70.009 46.752 70.081 51.96 ;
     RECT  70.013 52.944 70.081 53.448 ;
     RECT  69.829 10.848 70.121 30.216 ;
     RECT  70.121 11.136 70.193 30.216 ;
     RECT  69.761 8.688 70.261 9.528 ;
     RECT  70.193 11.376 70.333 30.216 ;
     RECT  69.689 31.2 70.333 33.096 ;
     RECT  67.504 60.384 70.369 60.408 ;
     RECT  70.369 60.288 70.409 60.408 ;
     RECT  69.901 58.08 70.513 58.104 ;
     RECT  70.333 11.376 70.517 33.096 ;
     RECT  69.797 34.416 70.549 45.432 ;
     RECT  70.549 34.416 70.633 45.576 ;
     RECT  70.517 11.952 70.661 33.096 ;
     RECT  69.973 55.152 70.693 57 ;
     RECT  70.513 58.08 70.693 58.68 ;
     RECT  70.261 8.688 70.697 9.816 ;
     RECT  70.661 16.752 70.697 33.096 ;
     RECT  70.693 55.152 70.733 58.68 ;
     RECT  70.697 9.792 70.765 9.816 ;
     RECT  70.697 16.752 70.805 22.008 ;
     RECT  70.633 34.416 70.837 45.432 ;
     RECT  70.733 55.152 70.913 55.176 ;
     RECT  70.733 56.4 70.913 58.68 ;
     RECT  70.081 46.752 70.931 53.448 ;
     RECT  70.805 17.04 70.949 22.008 ;
     RECT  70.931 51.792 70.949 53.448 ;
     RECT  70.697 23.616 71.017 33.096 ;
     RECT  70.837 34.08 71.017 45.432 ;
     RECT  70.949 17.04 71.057 20.184 ;
     RECT  70.697 8.688 71.089 8.76 ;
     RECT  71.017 23.616 71.201 45.432 ;
     RECT  70.765 9.792 71.309 10.152 ;
     RECT  70.913 56.592 71.377 58.68 ;
     RECT  70.949 51.936 71.417 53.448 ;
     RECT  71.417 51.936 71.489 52.92 ;
     RECT  70.931 46.752 71.629 50.472 ;
     RECT  70.949 21.264 71.737 22.008 ;
     RECT  71.737 21.264 71.809 22.056 ;
     RECT  71.201 23.616 71.809 33.624 ;
     RECT  70.661 11.952 71.845 15.768 ;
     RECT  71.845 11.952 72.025 15.864 ;
     RECT  72.025 11.664 72.061 15.864 ;
     RECT  71.377 56.592 72.085 58.776 ;
     RECT  70.409 60.288 72.085 60.312 ;
     RECT  71.629 46.704 72.169 50.472 ;
     RECT  71.489 51.936 72.169 52.248 ;
     RECT  71.057 17.04 72.236 19.416 ;
     RECT  72.236 17.04 72.313 20.04 ;
     RECT  71.809 21.264 72.313 33.624 ;
     RECT  71.201 34.656 72.493 45.432 ;
     RECT  72.169 46.704 72.565 52.248 ;
     RECT  71.089 7.872 72.608 8.76 ;
     RECT  71.309 9.792 72.608 9.816 ;
     RECT  72.061 11.52 72.608 15.864 ;
     RECT  72.313 17.04 72.608 33.624 ;
     RECT  72.493 34.656 72.608 45.528 ;
     RECT  72.565 46.704 72.608 52.296 ;
     RECT  72.493 54.336 72.608 54.36 ;
     RECT  72.085 56.592 72.608 60.312 ;
     RECT  72.608 2.148 72.712 62.652 ;
     RECT  72.712 2.418 72.904 62.382 ;
     RECT  72.904 50.112 73.073 52.968 ;
     RECT  72.904 13.392 73.084 15.96 ;
     RECT  72.904 17.472 73.181 45.528 ;
     RECT  72.904 46.8 73.181 48.888 ;
     RECT  73.181 23.376 73.331 45.528 ;
     RECT  72.904 60.288 73.523 60.312 ;
     RECT  73.331 30.144 73.829 45.528 ;
     RECT  72.904 8.736 73.865 8.76 ;
     RECT  73.829 30.144 73.865 37.08 ;
     RECT  72.904 54.336 73.957 59.256 ;
     RECT  73.957 54.336 74.003 59.304 ;
     RECT  72.904 9.792 74.005 10.248 ;
     RECT  72.904 11.952 74.041 11.976 ;
     RECT  73.084 13.392 74.041 15.48 ;
     RECT  73.073 50.112 74.041 50.376 ;
     RECT  74.003 54.336 74.041 57.576 ;
     RECT  74.005 9.216 74.051 10.248 ;
     RECT  74.041 11.952 74.077 15.48 ;
     RECT  74.041 50.064 74.077 50.376 ;
     RECT  73.829 38.208 74.149 45.528 ;
     RECT  73.073 51.456 74.149 52.968 ;
     RECT  74.041 54.048 74.149 57.576 ;
     RECT  73.181 46.896 74.153 48.888 ;
     RECT  74.051 9.216 74.189 9.816 ;
     RECT  74.153 46.896 74.329 48.84 ;
     RECT  73.331 23.376 74.369 29.064 ;
     RECT  74.149 51.456 74.387 57.576 ;
     RECT  73.181 17.472 74.401 22.248 ;
     RECT  74.077 49.872 74.401 50.376 ;
     RECT  74.149 38.208 74.441 45.576 ;
     RECT  74.077 11.856 74.513 15.48 ;
     RECT  74.387 51.456 74.513 55.704 ;
     RECT  74.401 16.56 74.581 22.248 ;
     RECT  74.369 23.376 74.581 23.736 ;
     RECT  74.513 11.856 74.617 14.28 ;
     RECT  74.401 49.824 74.689 50.376 ;
     RECT  74.513 51.456 74.689 55.416 ;
     RECT  74.329 46.752 74.761 48.84 ;
     RECT  73.865 30.384 74.797 37.08 ;
     RECT  74.441 38.208 74.797 44.808 ;
     RECT  74.617 11.376 74.833 14.28 ;
     RECT  74.581 16.56 74.837 23.736 ;
     RECT  74.797 30.384 74.945 44.808 ;
     RECT  74.945 30.384 74.981 32.328 ;
     RECT  74.369 24.72 75.049 29.064 ;
     RECT  74.387 56.88 75.157 57.576 ;
     RECT  74.003 58.656 75.157 59.304 ;
     RECT  74.189 9.792 75.193 9.816 ;
     RECT  74.833 11.328 75.193 14.28 ;
     RECT  74.513 15.456 75.193 15.48 ;
     RECT  74.837 16.56 75.193 22.248 ;
     RECT  75.049 24.72 75.269 30.216 ;
     RECT  75.157 56.88 75.269 59.304 ;
     RECT  75.193 9.792 75.341 14.28 ;
     RECT  75.269 24.816 75.413 30.216 ;
     RECT  75.193 15.456 75.449 22.248 ;
     RECT  74.761 46.128 75.481 48.84 ;
     RECT  74.689 49.824 75.481 55.416 ;
     RECT  75.341 10.704 75.557 14.28 ;
     RECT  75.269 56.88 75.589 57.576 ;
     RECT  75.269 58.656 75.625 59.304 ;
     RECT  74.837 23.376 75.665 23.736 ;
     RECT  75.557 13.296 75.733 14.28 ;
     RECT  75.449 15.456 75.733 15.624 ;
     RECT  75.557 10.704 75.737 11.976 ;
     RECT  75.481 46.128 75.836 55.416 ;
     RECT  75.733 13.296 75.845 15.624 ;
     RECT  74.945 33.312 75.845 44.808 ;
     RECT  75.625 58.656 75.973 59.832 ;
     RECT  75.845 13.296 75.989 15.48 ;
     RECT  75.973 58.656 76.019 60.552 ;
     RECT  75.413 24.816 76.025 29.064 ;
     RECT  75.589 56.448 76.025 57.576 ;
     RECT  76.019 60.528 76.06 60.552 ;
     RECT  75.836 46.08 76.093 55.416 ;
     RECT  75.449 17.472 76.169 22.248 ;
     RECT  76.169 17.472 76.211 19.416 ;
     RECT  75.841 9.504 76.273 9.528 ;
     RECT  75.737 11.376 76.277 11.976 ;
     RECT  75.413 30.192 76.309 30.216 ;
     RECT  74.981 31.344 76.309 32.328 ;
     RECT  76.309 30.192 76.381 32.328 ;
     RECT  75.845 33.312 76.381 44.76 ;
     RECT  76.025 26.064 76.453 29.064 ;
     RECT  76.381 30.192 76.453 44.76 ;
     RECT  76.019 58.656 76.457 59.496 ;
     RECT  76.211 17.472 76.561 19.272 ;
     RECT  76.273 8.544 76.637 9.528 ;
     RECT  76.277 11.376 76.813 11.784 ;
     RECT  76.453 26.064 76.925 44.76 ;
     RECT  75.989 13.296 76.961 15.048 ;
     RECT  76.961 13.296 77.065 14.232 ;
     RECT  75.665 23.424 77.137 23.736 ;
     RECT  76.025 24.816 77.137 24.84 ;
     RECT  77.137 23.424 77.173 24.84 ;
     RECT  76.561 16.512 77.18 19.272 ;
     RECT  76.925 26.592 77.18 44.76 ;
     RECT  76.093 45.792 77.18 55.416 ;
     RECT  77.18 15.888 77.281 19.272 ;
     RECT  77.173 23.328 77.281 24.84 ;
     RECT  77.281 15.888 77.497 19.512 ;
     RECT  76.813 10.896 77.533 11.784 ;
     RECT  76.169 20.736 77.605 22.248 ;
     RECT  77.281 23.328 77.605 25.608 ;
     RECT  76.025 56.88 77.641 57.576 ;
     RECT  77.497 15.888 77.821 19.56 ;
     RECT  77.605 20.736 77.821 25.608 ;
     RECT  77.821 15.888 77.929 25.608 ;
     RECT  77.18 26.592 77.929 55.416 ;
     RECT  76.637 8.544 78.008 9 ;
     RECT  77.533 10.32 78.008 11.784 ;
     RECT  77.065 13.152 78.008 14.232 ;
     RECT  77.929 15.888 78.008 55.416 ;
     RECT  77.641 56.784 78.008 57.576 ;
     RECT  76.457 59.472 78.008 59.496 ;
     RECT  78.008 2.148 78.112 62.652 ;
     RECT  78.112 2.418 78.304 62.382 ;
     RECT  78.304 9.12 78.509 14.232 ;
     RECT  78.304 58.944 78.581 59.496 ;
     RECT  78.509 9.648 78.653 14.232 ;
     RECT  78.304 23.04 79.121 33.048 ;
     RECT  78.304 7.584 79.229 7.656 ;
     RECT  79.121 23.04 79.229 28.968 ;
     RECT  78.304 17.424 79.297 17.448 ;
     RECT  78.304 18.528 79.297 22.056 ;
     RECT  79.229 23.04 79.297 24.312 ;
     RECT  79.229 25.344 79.301 28.968 ;
     RECT  79.121 30.48 79.405 33.048 ;
     RECT  78.304 34.368 79.405 57.576 ;
     RECT  79.297 17.088 79.409 17.448 ;
     RECT  78.653 9.648 79.477 9.72 ;
     RECT  78.653 11.136 79.477 14.232 ;
     RECT  79.477 11.136 79.513 14.904 ;
     RECT  79.405 30.48 79.657 57.576 ;
     RECT  78.581 58.944 79.657 58.968 ;
     RECT  79.657 30.48 79.667 58.968 ;
     RECT  79.477 8.928 79.669 9.72 ;
     RECT  79.513 11.136 79.669 15.432 ;
     RECT  79.297 18.528 79.733 24.312 ;
     RECT  79.669 8.928 79.756 15.432 ;
     RECT  79.667 33.552 80.012 58.968 ;
     RECT  79.667 30.48 80.057 32.04 ;
     RECT  80.012 33.552 80.099 59.736 ;
     RECT  79.756 10.848 80.125 15.432 ;
     RECT  79.409 17.088 80.125 17.256 ;
     RECT  79.301 25.44 80.273 28.968 ;
     RECT  79.733 23.664 80.521 24.312 ;
     RECT  80.125 10.848 80.561 17.256 ;
     RECT  79.756 8.928 80.597 9.72 ;
     RECT  80.561 10.848 80.597 11.976 ;
     RECT  80.561 13.056 80.701 17.256 ;
     RECT  79.733 18.528 80.737 22.632 ;
     RECT  80.521 23.664 80.737 24.36 ;
     RECT  80.273 25.728 80.737 28.968 ;
     RECT  80.057 30.48 80.737 31.8 ;
     RECT  80.701 13.056 80.809 17.448 ;
     RECT  80.737 18.528 80.809 24.36 ;
     RECT  80.099 33.552 80.809 59.256 ;
     RECT  80.737 25.728 80.813 31.8 ;
     RECT  80.809 33.264 80.845 59.256 ;
     RECT  80.809 13.056 80.917 24.36 ;
     RECT  80.845 33.072 80.957 59.256 ;
     RECT  80.597 9.696 80.989 9.72 ;
     RECT  80.597 10.848 80.989 11.928 ;
     RECT  80.813 25.728 81.029 31.752 ;
     RECT  80.917 13.056 81.277 24.744 ;
     RECT  81.029 25.728 81.277 29.4 ;
     RECT  81.277 13.056 81.929 29.4 ;
     RECT  80.989 9.696 82.109 11.928 ;
     RECT  81.889 61.008 82.145 61.032 ;
     RECT  79.229 7.632 82.177 7.656 ;
     RECT  81.929 13.152 82.181 29.4 ;
     RECT  82.181 13.536 82.213 29.4 ;
     RECT  81.029 30.384 82.213 31.752 ;
     RECT  80.957 33.264 82.357 59.256 ;
     RECT  82.213 13.536 82.501 31.752 ;
     RECT  82.357 33.12 82.501 59.832 ;
     RECT  82.501 13.536 82.681 59.832 ;
     RECT  82.109 10.224 83.173 11.928 ;
     RECT  83.173 10.224 83.185 12.408 ;
     RECT  82.177 7.632 83.269 7.992 ;
     RECT  83.185 10.08 83.269 12.408 ;
     RECT  82.681 13.536 83.365 60.168 ;
     RECT  83.269 7.344 83.408 7.992 ;
     RECT  83.269 9.408 83.408 12.408 ;
     RECT  83.365 13.392 83.408 60.168 ;
     RECT  83.077 62.016 83.408 62.04 ;
     RECT  83.408 2.148 83.512 62.652 ;
     RECT  83.512 2.418 83.704 62.472 ;
     RECT  83.704 29.52 84.017 62.472 ;
     RECT  83.704 9.072 84.805 11.784 ;
     RECT  83.704 12.96 84.805 28.488 ;
     RECT  84.805 9.072 85.021 28.488 ;
     RECT  84.017 29.616 85.021 62.472 ;
     RECT  85.021 9.072 85.493 62.472 ;
     RECT  85.493 9.072 85.565 62.184 ;
     RECT  83.704 7.344 85.669 7.752 ;
     RECT  85.565 9.072 86.141 23.112 ;
     RECT  85.669 7.056 86.317 7.752 ;
     RECT  86.317 7.056 86.353 8.04 ;
     RECT  86.141 9.072 86.353 19.512 ;
     RECT  85.565 24.24 86.645 62.184 ;
     RECT  86.353 7.056 86.681 19.512 ;
     RECT  86.645 24.24 86.753 61.224 ;
     RECT  86.141 20.496 86.857 23.112 ;
     RECT  86.753 24.24 86.857 60.84 ;
     RECT  86.857 20.496 87.109 60.84 ;
     RECT  86.681 7.056 87.289 19.368 ;
     RECT  87.109 20.4 88.225 60.84 ;
     RECT  87.721 62.112 88.225 62.136 ;
     RECT  87.289 6.72 88.297 19.368 ;
     RECT  88.225 20.4 88.297 62.136 ;
     RECT  88.297 6.72 88.808 62.568 ;
     RECT  88.808 2.148 88.912 62.652 ;
     RECT  88.912 2.418 89.057 62.568 ;
     RECT  89.057 2.418 89.104 62.382 ;
     RECT  89.104 6.24 89.669 62.136 ;
     RECT  89.669 8.88 89.705 61.656 ;
     RECT  89.669 6.24 89.843 7.896 ;
     RECT  89.843 6.24 89.891 6.408 ;
     RECT  89.705 38.688 90.029 61.656 ;
     RECT  89.891 6.24 90.097 6.264 ;
     RECT  90.029 61.344 90.101 61.512 ;
     RECT  90.101 61.344 90.137 61.368 ;
     RECT  89.705 8.88 90.173 37.608 ;
     RECT  90.097 6.192 90.181 6.264 ;
     RECT  90.181 6.24 90.275 6.264 ;
     RECT  90.029 38.688 90.281 60.36 ;
     RECT  90.281 38.688 90.317 57.432 ;
     RECT  90.317 38.688 90.461 56.808 ;
     RECT  90.173 8.928 90.611 37.608 ;
     RECT  90.611 9.024 90.641 37.608 ;
     RECT  89.843 7.824 90.713 7.896 ;
     RECT  90.641 9.024 90.713 16.68 ;
     RECT  90.713 7.872 90.785 7.896 ;
     RECT  90.281 58.416 91.177 60.36 ;
     RECT  90.641 17.904 91.213 37.608 ;
     RECT  91.177 58.416 91.465 61.032 ;
     RECT  91.465 58.416 91.537 61.128 ;
     RECT  90.461 39.12 91.609 56.808 ;
     RECT  91.609 39.12 91.681 57.288 ;
     RECT  91.213 17.904 91.717 38.088 ;
     RECT  91.681 39.12 91.717 57.384 ;
     RECT  91.537 58.416 91.717 61.32 ;
     RECT  90.713 9.936 91.753 16.68 ;
     RECT  91.717 17.712 91.753 38.088 ;
     RECT  91.717 39.12 91.753 61.32 ;
     RECT  91.753 9.936 92.761 61.32 ;
     RECT  92.761 9.84 92.844 61.32 ;
     RECT  92.844 9.84 92.873 9.864 ;
    LAYER M5 ;
     RECT  2.256 2.137 2.52 2.151 ;
     RECT  7.8 2.137 7.92 2.151 ;
     RECT  13.2 2.137 13.32 2.151 ;
     RECT  18.6 2.137 18.72 2.151 ;
     RECT  24 2.137 24.12 2.151 ;
     RECT  29.4 2.137 29.52 2.151 ;
     RECT  34.8 2.137 34.92 2.151 ;
     RECT  40.2 2.137 40.32 2.151 ;
     RECT  45.6 2.137 45.72 2.151 ;
     RECT  51 2.137 51.12 2.151 ;
     RECT  56.4 2.137 56.52 2.151 ;
     RECT  61.8 2.137 61.92 2.151 ;
     RECT  67.2 2.137 67.32 2.151 ;
     RECT  72.6 2.137 72.72 2.151 ;
     RECT  78 2.137 78.12 2.151 ;
     RECT  83.4 2.137 83.52 2.151 ;
     RECT  88.8 2.137 88.92 2.151 ;
     RECT  2.256 2.151 2.712 2.197 ;
     RECT  4.176 2.677 4.2 2.725 ;
     RECT  5.472 2.677 5.496 2.725 ;
     RECT  0.144 2.245 0.168 2.773 ;
     RECT  2.256 2.197 2.856 2.773 ;
     RECT  2.256 2.773 3 2.821 ;
     RECT  4.176 2.725 5.496 2.821 ;
     RECT  0.144 2.773 0.216 3.013 ;
     RECT  2.256 2.821 3.144 3.349 ;
     RECT  4.176 2.821 6.6 3.349 ;
     RECT  2.256 3.349 6.6 4.403 ;
     RECT  18.6 2.151 18.912 4.789 ;
     RECT  9.504 3.877 9.528 4.883 ;
     RECT  18.6 4.789 19.416 5.029 ;
     RECT  15.216 4.549 15.24 5.219 ;
     RECT  17.856 5.029 19.416 5.699 ;
     RECT  6.576 4.403 6.6 5.747 ;
     RECT  22.608 5.077 22.632 5.747 ;
     RECT  18.6 5.699 19.416 5.797 ;
     RECT  0.144 3.013 0.456 5.843 ;
     RECT  7.8 2.151 8.112 6.085 ;
     RECT  90.144 6.181 90.168 6.229 ;
     RECT  0.144 5.843 0.36 6.323 ;
     RECT  88.8 2.151 89.112 6.373 ;
     RECT  90.144 6.229 90.264 6.373 ;
     RECT  40.2 2.151 40.512 6.805 ;
     RECT  0.144 6.323 0.312 6.899 ;
     RECT  39.84 6.805 41.448 7.235 ;
     RECT  2.256 4.403 5.496 7.237 ;
     RECT  7.8 6.085 8.232 7.237 ;
     RECT  10.224 5.653 10.248 7.285 ;
     RECT  9.792 7.285 10.248 7.331 ;
     RECT  2.256 7.237 8.232 7.333 ;
     RECT  59.856 7.237 59.88 7.333 ;
     RECT  83.4 2.151 83.712 7.333 ;
     RECT  63.264 6.229 63.288 7.619 ;
     RECT  2.256 7.333 8.664 7.955 ;
     RECT  0.144 6.899 0.264 7.957 ;
     RECT  59.856 7.333 60.696 8.003 ;
     RECT  0.144 7.957 0.312 8.195 ;
     RECT  18.6 5.797 19.656 8.387 ;
     RECT  45.6 2.151 45.912 8.437 ;
     RECT  0.192 8.195 0.312 8.579 ;
     RECT  72.6 2.151 72.912 8.677 ;
     RECT  9.792 7.331 9.912 8.723 ;
     RECT  88.8 6.373 90.264 8.917 ;
     RECT  87.216 7.333 87.24 9.011 ;
     RECT  88.8 8.917 90.6 9.059 ;
     RECT  7.392 7.955 8.664 9.203 ;
     RECT  0.288 8.579 0.312 9.541 ;
     RECT  0.288 9.541 0.36 9.589 ;
     RECT  45.6 8.437 46.296 9.589 ;
     RECT  27.744 6.181 27.768 9.637 ;
     RECT  27.6 9.637 27.768 9.683 ;
     RECT  88.8 9.059 90.264 9.731 ;
     RECT  0.24 9.589 0.36 10.021 ;
     RECT  2.256 7.955 6.264 10.165 ;
     RECT  7.632 9.203 8.664 10.165 ;
     RECT  31.632 8.485 31.656 10.165 ;
     RECT  56.4 2.151 56.712 10.165 ;
     RECT  0.144 10.021 0.36 10.213 ;
     RECT  2.256 10.165 8.664 10.213 ;
     RECT  9.792 8.723 9.816 10.213 ;
     RECT  65.52 7.573 65.544 10.213 ;
     RECT  74.016 9.637 74.04 10.259 ;
     RECT  88.8 9.731 90.168 10.307 ;
     RECT  49.248 6.805 49.272 10.309 ;
     RECT  51 2.151 51.312 10.309 ;
     RECT  49.248 10.309 51.312 10.595 ;
     RECT  27.6 9.683 27.624 10.741 ;
     RECT  31.632 10.165 32.136 10.787 ;
     RECT  45.6 9.589 46.536 10.835 ;
     RECT  2.256 10.213 9.816 10.883 ;
     RECT  27.6 10.741 27.912 10.883 ;
     RECT  88.8 10.307 89.976 10.883 ;
     RECT  49.536 10.595 51.312 10.931 ;
     RECT  31.632 10.787 31.656 11.125 ;
     RECT  64.752 10.213 65.544 11.171 ;
     RECT  79.68 10.501 79.704 11.171 ;
     RECT  29.4 2.151 29.712 11.317 ;
     RECT  30.768 11.125 31.656 11.317 ;
     RECT  60.672 8.003 60.696 11.317 ;
     RECT  61.8 2.151 62.112 11.317 ;
     RECT  29.4 11.317 31.656 11.363 ;
     RECT  60.672 11.317 62.112 11.363 ;
     RECT  18.6 8.387 19.464 11.365 ;
     RECT  24 2.151 24.312 11.365 ;
     RECT  31.584 11.363 31.656 11.459 ;
     RECT  44.016 8.341 44.04 11.651 ;
     RECT  55.632 10.165 56.712 11.701 ;
     RECT  13.2 2.151 13.512 11.845 ;
     RECT  18.6 11.365 20.232 11.941 ;
     RECT  18.144 11.941 20.232 11.987 ;
     RECT  37.728 11.173 37.752 12.035 ;
     RECT  2.256 10.883 9.72 12.133 ;
     RECT  27.6 10.883 27.624 12.179 ;
     RECT  39.84 7.235 40.512 12.181 ;
     RECT  24 11.365 24.648 12.227 ;
     RECT  13.2 11.845 13.944 12.275 ;
     RECT  0.144 10.213 0.552 12.371 ;
     RECT  83.28 7.333 83.712 12.373 ;
     RECT  65.52 11.171 65.544 12.467 ;
     RECT  2.256 12.133 9.96 12.517 ;
     RECT  0.144 12.371 0.504 12.563 ;
     RECT  31.584 11.459 31.608 12.563 ;
     RECT  0.144 12.563 0.264 12.755 ;
     RECT  84.816 12.517 84.84 12.949 ;
     RECT  18.144 11.987 19.464 13.091 ;
     RECT  58.8 12.757 58.824 13.093 ;
     RECT  84.816 12.949 84.936 13.093 ;
     RECT  2.256 12.517 10.824 13.139 ;
     RECT  49.536 10.931 49.56 13.139 ;
     RECT  55.488 11.701 56.712 13.139 ;
     RECT  84.768 13.093 84.936 13.139 ;
     RECT  86.064 12.373 86.088 13.139 ;
     RECT  87.792 12.517 87.816 13.477 ;
     RECT  39.6 12.181 40.512 13.523 ;
     RECT  0.192 12.755 0.264 13.573 ;
     RECT  55.872 13.139 56.712 13.619 ;
     RECT  84.768 13.139 84.888 13.667 ;
     RECT  0.192 13.573 0.312 13.715 ;
     RECT  88.8 10.883 89.88 13.715 ;
     RECT  0.192 13.715 0.264 13.765 ;
     RECT  64.416 12.421 64.44 13.813 ;
     RECT  58.704 13.093 58.824 13.859 ;
     RECT  84.816 13.667 84.888 13.859 ;
     RECT  67.2 2.151 67.512 13.909 ;
     RECT  60.96 11.363 62.112 14.099 ;
     RECT  87.552 13.477 87.816 14.099 ;
     RECT  51 10.931 51.312 14.101 ;
     RECT  52.896 13.957 52.92 14.101 ;
     RECT  84.864 13.859 84.888 14.101 ;
     RECT  74.496 13.477 75.24 14.147 ;
     RECT  83.184 12.373 83.712 14.197 ;
     RECT  75.216 14.147 75.24 14.245 ;
     RECT  75.216 14.245 75.336 14.291 ;
     RECT  2.256 13.139 9.96 14.293 ;
     RECT  81.552 13.141 81.576 14.339 ;
     RECT  87.552 14.099 87.576 14.339 ;
     RECT  18.288 13.091 19.464 14.387 ;
     RECT  64.128 13.813 64.44 14.387 ;
     RECT  13.2 12.275 13.512 14.389 ;
     RECT  32.352 13.429 32.376 14.675 ;
     RECT  72.48 8.677 72.912 14.675 ;
     RECT  58.8 13.859 58.824 14.677 ;
     RECT  88.8 13.715 89.736 14.677 ;
     RECT  13.2 14.389 14.088 14.773 ;
     RECT  72.6 14.675 72.912 14.773 ;
     RECT  52.416 14.101 52.92 14.819 ;
     RECT  88.704 14.677 89.736 14.819 ;
     RECT  13.104 14.773 14.088 14.867 ;
     RECT  84.864 14.101 85.512 14.867 ;
     RECT  16.128 11.365 16.152 14.917 ;
     RECT  0.144 13.765 0.264 15.109 ;
     RECT  58.8 14.677 59.544 15.347 ;
     RECT  26.064 14.821 26.088 15.395 ;
     RECT  27.888 14.773 27.912 15.443 ;
     RECT  52.416 14.819 52.44 15.443 ;
     RECT  50.88 14.101 51.312 15.445 ;
     RECT  50.88 15.445 52.248 15.491 ;
     RECT  85.488 14.867 85.512 15.491 ;
     RECT  64.416 14.387 64.44 15.685 ;
     RECT  78 2.151 78.312 15.877 ;
     RECT  88.8 14.819 89.736 15.877 ;
     RECT  88.8 15.877 89.88 15.925 ;
     RECT  72.6 14.773 73.032 15.971 ;
     RECT  15.936 14.917 16.152 16.019 ;
     RECT  33.408 13.813 33.432 16.019 ;
     RECT  87.504 15.445 87.528 16.019 ;
     RECT  64.416 15.685 65.304 16.211 ;
     RECT  82.8 14.197 83.712 16.259 ;
     RECT  21.312 14.341 21.336 16.405 ;
     RECT  21.12 16.405 21.336 16.451 ;
     RECT  2.256 14.293 10.248 16.501 ;
     RECT  0.144 15.109 0.36 16.595 ;
     RECT  16.128 16.019 16.152 16.595 ;
     RECT  39.888 13.523 40.512 16.595 ;
     RECT  0.144 16.595 0.312 16.691 ;
     RECT  13.104 14.867 13.512 16.837 ;
     RECT  77.232 15.877 78.312 16.979 ;
     RECT  75.312 14.291 75.336 17.077 ;
     RECT  88.8 15.925 90.168 17.077 ;
     RECT  21.12 16.451 21.144 17.123 ;
     RECT  51 15.491 52.248 17.123 ;
     RECT  59.952 16.117 59.976 17.123 ;
     RECT  27.888 16.453 27.912 17.171 ;
     RECT  33.024 17.077 33.048 17.219 ;
     RECT  88.56 17.077 90.168 17.411 ;
     RECT  81.216 16.405 81.24 17.413 ;
     RECT  85.632 16.837 85.656 17.413 ;
     RECT  2.256 16.501 10.632 17.509 ;
     RECT  11.952 17.461 11.976 17.509 ;
     RECT  75.264 17.077 75.336 17.605 ;
     RECT  80.976 17.413 81.24 17.699 ;
     RECT  84.912 17.413 85.656 17.699 ;
     RECT  78 16.979 78.312 17.989 ;
     RECT  83.232 16.259 83.712 18.035 ;
     RECT  0.144 16.691 0.168 18.085 ;
     RECT  34.8 2.151 35.112 18.181 ;
     RECT  64.416 16.211 64.44 18.275 ;
     RECT  65.808 17.605 65.832 18.659 ;
     RECT  75.264 17.605 76.248 18.659 ;
     RECT  0.144 18.085 0.216 18.661 ;
     RECT  14.544 18.661 14.568 18.803 ;
     RECT  47.28 18.181 47.304 18.803 ;
     RECT  77.232 17.989 78.312 18.803 ;
     RECT  2.256 17.509 11.976 18.851 ;
     RECT  0.144 18.661 0.408 18.899 ;
     RECT  75.264 18.659 76.2 18.949 ;
     RECT  34.416 18.181 35.112 18.995 ;
     RECT  74.976 18.949 76.2 18.995 ;
     RECT  67.2 13.909 67.752 19.093 ;
     RECT  13.056 16.837 13.512 19.141 ;
     RECT  64.656 18.613 64.68 19.235 ;
     RECT  43.248 18.757 43.272 19.237 ;
     RECT  44.448 18.037 44.472 19.237 ;
     RECT  22.272 18.181 22.296 19.379 ;
     RECT  72.6 15.971 72.912 19.381 ;
     RECT  43.248 19.237 44.472 19.427 ;
     RECT  58.8 15.347 58.824 19.427 ;
     RECT  76.176 18.995 76.2 19.427 ;
     RECT  29.4 11.363 30.456 19.477 ;
     RECT  40.2 16.595 40.512 19.669 ;
     RECT  43.248 19.427 43.704 19.859 ;
     RECT  24 12.227 24.312 19.861 ;
     RECT  12.768 19.141 13.512 20.003 ;
     RECT  29.4 19.477 30.696 20.003 ;
     RECT  43.248 19.859 43.272 20.003 ;
     RECT  48.096 19.333 48.12 20.003 ;
     RECT  54.096 11.221 54.12 20.003 ;
     RECT  74.976 18.995 75 20.003 ;
     RECT  72.288 19.381 72.912 20.051 ;
     RECT  85.632 17.699 85.656 20.051 ;
     RECT  18.288 14.387 18.912 20.197 ;
     RECT  0.144 18.899 0.168 20.293 ;
     RECT  49.776 18.757 49.8 20.339 ;
     RECT  51 17.123 51.312 20.341 ;
     RECT  14.784 20.149 14.808 20.387 ;
     RECT  67.2 19.093 68.376 20.579 ;
     RECT  0.144 20.293 0.408 20.723 ;
     RECT  83.28 18.035 83.712 21.013 ;
     RECT  58.464 20.437 58.488 21.061 ;
     RECT  58.464 21.061 58.68 21.155 ;
     RECT  83.28 21.013 84.648 21.155 ;
     RECT  88.8 17.411 90.168 21.251 ;
     RECT  90.144 21.251 90.168 21.299 ;
     RECT  50.88 20.341 51.312 21.443 ;
     RECT  81.216 17.699 81.24 21.637 ;
     RECT  2.256 18.851 11.448 21.683 ;
     RECT  53.472 20.053 53.496 21.683 ;
     RECT  2.256 21.683 10.536 21.731 ;
     RECT  0.144 20.723 0.264 21.779 ;
     RECT  58.656 21.155 58.68 21.827 ;
     RECT  29.4 20.003 30.504 21.925 ;
     RECT  72.6 20.051 72.912 21.925 ;
     RECT  29.04 21.925 30.504 22.067 ;
     RECT  17.136 20.197 17.16 22.165 ;
     RECT  81.12 21.637 81.24 22.165 ;
     RECT  0.144 21.779 0.168 22.307 ;
     RECT  44.304 21.061 44.328 22.451 ;
     RECT  81.12 22.165 82.056 22.451 ;
     RECT  16.944 22.165 17.16 22.693 ;
     RECT  18.192 20.197 18.912 22.693 ;
     RECT  5.472 21.731 10.536 22.835 ;
     RECT  82.032 22.451 82.056 22.835 ;
     RECT  60.096 21.541 60.12 22.981 ;
     RECT  5.472 22.835 10.488 23.123 ;
     RECT  87.216 22.117 87.24 23.171 ;
     RECT  39.84 19.669 40.512 23.173 ;
     RECT  61.8 14.099 62.112 23.173 ;
     RECT  2.256 21.731 4.488 23.317 ;
     RECT  5.472 23.123 5.784 23.317 ;
     RECT  13.2 20.003 13.512 23.317 ;
     RECT  72 21.925 72.912 23.365 ;
     RECT  36.96 21.253 36.984 23.411 ;
     RECT  39.84 23.173 41.016 23.411 ;
     RECT  7.008 23.123 10.488 23.507 ;
     RECT  26.16 21.589 26.184 23.555 ;
     RECT  51 21.443 51.312 23.893 ;
     RECT  72 23.365 73.176 24.083 ;
     RECT  48.768 23.893 48.792 24.275 ;
     RECT  0.288 23.653 0.312 24.469 ;
     RECT  7.104 23.507 10.488 24.469 ;
     RECT  34.8 18.995 35.112 24.469 ;
     RECT  37.584 23.701 37.608 24.469 ;
     RECT  78 18.803 78.312 24.469 ;
     RECT  36.72 24.469 37.608 24.563 ;
     RECT  39.888 23.411 41.016 24.563 ;
     RECT  83.4 21.155 84.648 24.611 ;
     RECT  59.856 22.981 60.12 24.659 ;
     RECT  2.256 23.317 5.784 24.805 ;
     RECT  7.008 24.469 10.488 24.805 ;
     RECT  75.456 20.725 75.48 24.899 ;
     RECT  34.8 24.469 35.736 24.901 ;
     RECT  36.72 24.563 36.744 24.901 ;
     RECT  0.192 24.469 0.312 24.997 ;
     RECT  24 19.861 24.504 25.045 ;
     RECT  16.944 22.693 18.912 25.187 ;
     RECT  0.192 24.997 0.456 25.189 ;
     RECT  55.248 22.165 55.272 25.427 ;
     RECT  39.888 24.563 40.968 25.715 ;
     RECT  42.72 24.661 42.744 25.715 ;
     RECT  23.376 25.045 24.504 25.717 ;
     RECT  38.736 22.117 38.76 25.717 ;
     RECT  29.4 22.067 30.504 25.957 ;
     RECT  34.8 24.901 36.744 26.051 ;
     RECT  38.16 25.717 38.76 26.149 ;
     RECT  39.888 25.715 40.512 26.149 ;
     RECT  67.2 20.579 67.752 26.149 ;
     RECT  38.16 26.149 40.512 26.195 ;
     RECT  44.352 22.741 44.376 26.197 ;
     RECT  44.208 26.197 44.376 26.243 ;
     RECT  22.992 25.717 24.504 26.291 ;
     RECT  0.192 25.189 0.504 26.339 ;
     RECT  0.192 26.339 0.456 26.483 ;
     RECT  86.064 24.469 86.088 26.531 ;
     RECT  20.592 26.197 20.616 26.533 ;
     RECT  72 24.083 72.912 26.629 ;
     RECT  29.4 25.957 30.696 26.677 ;
     RECT  29.4 26.677 30.792 26.723 ;
     RECT  38.16 26.195 38.952 26.725 ;
     RECT  79.632 26.581 79.656 26.725 ;
     RECT  81.504 24.085 81.528 26.725 ;
     RECT  13.2 23.317 14.232 26.771 ;
     RECT  20.592 26.533 21.432 26.771 ;
     RECT  51 23.893 51.864 26.771 ;
     RECT  72 26.629 73.224 26.771 ;
     RECT  81.504 26.725 81.624 26.771 ;
     RECT  60.096 24.659 60.12 26.773 ;
     RECT  2.256 24.805 10.488 26.819 ;
     RECT  17.376 25.187 18.912 26.819 ;
     RECT  20.592 26.771 20.616 26.819 ;
     RECT  30.72 26.723 30.792 26.819 ;
     RECT  23.28 26.291 24.504 26.915 ;
     RECT  75.408 25.045 75.432 26.915 ;
     RECT  88.8 21.251 89.112 26.965 ;
     RECT  2.256 26.819 4.536 27.011 ;
     RECT  34.8 26.051 36.36 27.059 ;
     RECT  88.704 26.965 89.112 27.107 ;
     RECT  0.192 26.483 0.408 27.155 ;
     RECT  0.192 27.155 0.264 27.157 ;
     RECT  83.4 24.611 83.712 27.157 ;
     RECT  67.2 26.149 67.8 27.203 ;
     RECT  79.632 26.725 80.52 27.251 ;
     RECT  60.096 26.773 60.456 27.299 ;
     RECT  5.856 26.819 10.488 27.301 ;
     RECT  61.8 23.173 62.952 27.301 ;
     RECT  67.2 27.203 67.752 27.347 ;
     RECT  2.256 27.011 4.44 27.395 ;
     RECT  5.856 27.301 11.16 27.395 ;
     RECT  34.8 27.059 35.64 27.395 ;
     RECT  18.384 26.819 18.912 27.635 ;
     RECT  61.68 27.301 62.952 27.635 ;
     RECT  44.208 26.243 44.232 27.733 ;
     RECT  45.6 10.835 45.912 27.733 ;
     RECT  5.856 27.395 8.472 27.781 ;
     RECT  38.064 26.725 38.952 27.781 ;
     RECT  37.728 27.781 38.952 27.827 ;
     RECT  55.248 27.205 55.272 27.827 ;
     RECT  5.664 27.781 8.472 27.877 ;
     RECT  18.432 27.635 18.912 27.877 ;
     RECT  72.6 26.771 73.224 27.877 ;
     RECT  77.856 24.469 78.312 27.877 ;
     RECT  30.72 26.819 30.744 27.923 ;
     RECT  33.696 27.301 33.72 27.923 ;
     RECT  17.376 26.819 17.4 27.971 ;
     RECT  18.432 27.877 19.032 28.163 ;
     RECT  40.2 26.195 40.512 28.213 ;
     RECT  37.728 27.827 38.808 28.259 ;
     RECT  0.144 27.157 0.264 28.309 ;
     RECT  5.616 27.877 8.472 28.309 ;
     RECT  83.28 27.157 83.712 28.309 ;
     RECT  44.208 27.733 45.912 28.451 ;
     RECT  85.488 27.733 85.512 28.499 ;
     RECT  77.856 27.877 78.648 28.547 ;
     RECT  5.568 28.309 8.472 28.643 ;
     RECT  2.256 27.395 4.296 28.645 ;
     RECT  81.6 26.771 81.624 28.789 ;
     RECT  81.6 28.789 82.056 28.931 ;
     RECT  6.624 28.643 8.472 28.981 ;
     RECT  9.504 27.395 11.16 28.981 ;
     RECT  82.032 28.931 82.056 29.029 ;
     RECT  83.184 28.309 83.712 29.029 ;
     RECT  27.36 27.781 27.384 29.077 ;
     RECT  37.728 28.259 38.088 29.123 ;
     RECT  6.624 28.981 11.16 29.219 ;
     RECT  69.168 27.253 69.192 29.219 ;
     RECT  44.208 28.451 44.232 29.267 ;
     RECT  2.256 28.645 4.536 29.365 ;
     RECT  5.568 28.643 5.64 29.365 ;
     RECT  51 26.771 51.312 29.365 ;
     RECT  60.096 27.299 60.12 29.365 ;
     RECT  47.904 24.469 47.928 29.411 ;
     RECT  59.856 29.365 60.12 29.411 ;
     RECT  61.8 27.635 62.112 29.461 ;
     RECT  18.432 28.163 18.912 29.605 ;
     RECT  34.8 27.395 35.112 29.605 ;
     RECT  36.48 28.117 36.504 29.605 ;
     RECT  54.672 28.933 54.696 29.605 ;
     RECT  26.832 29.077 27.384 29.699 ;
     RECT  82.032 29.029 83.712 29.747 ;
     RECT  38.496 29.221 38.52 29.795 ;
     RECT  2.256 29.365 5.64 29.845 ;
     RECT  6.624 29.219 9.432 29.845 ;
     RECT  0.144 28.309 0.552 29.939 ;
     RECT  0.144 29.939 0.312 30.035 ;
     RECT  52.704 29.077 52.728 30.035 ;
     RECT  32.448 27.877 32.472 30.275 ;
     RECT  34.8 29.605 36.504 30.275 ;
     RECT  54.384 29.605 54.696 30.275 ;
     RECT  83.184 29.747 83.712 30.275 ;
     RECT  83.4 30.275 83.712 30.277 ;
     RECT  54.384 30.275 54.408 30.323 ;
     RECT  82.032 29.747 82.056 30.373 ;
     RECT  85.488 30.181 85.512 30.373 ;
     RECT  81.504 30.373 82.056 30.419 ;
     RECT  67.2 27.347 67.656 30.469 ;
     RECT  22.176 28.453 22.2 30.563 ;
     RECT  18.432 29.605 19.368 30.565 ;
     RECT  61.488 29.461 62.112 30.565 ;
     RECT  83.4 30.277 84.408 30.659 ;
     RECT  29.4 26.723 29.712 30.709 ;
     RECT  66.768 30.469 67.656 30.757 ;
     RECT  70.608 30.661 70.632 30.803 ;
     RECT  2.256 29.845 9.432 30.805 ;
     RECT  10.464 29.219 11.16 30.805 ;
     RECT  13.2 26.771 13.512 30.805 ;
     RECT  0.144 30.035 0.264 30.851 ;
     RECT  18.24 30.565 19.368 30.851 ;
     RECT  29.04 30.709 29.712 30.851 ;
     RECT  59.856 29.411 59.88 30.851 ;
     RECT  90.576 30.757 90.6 30.899 ;
     RECT  13.2 30.805 14.376 30.947 ;
     RECT  0.192 30.851 0.264 31.045 ;
     RECT  48.816 30.709 48.84 31.285 ;
     RECT  50.256 29.365 51.312 31.285 ;
     RECT  57.696 30.037 57.72 31.285 ;
     RECT  0.192 31.045 0.36 31.379 ;
     RECT  2.256 30.805 11.16 31.379 ;
     RECT  27.36 29.699 27.384 31.379 ;
     RECT  36.48 30.275 36.504 31.379 ;
     RECT  48.816 31.285 51.312 31.379 ;
     RECT  57.696 31.285 58.152 31.379 ;
     RECT  68.928 29.461 68.952 31.379 ;
     RECT  81.504 30.419 81.528 31.379 ;
     RECT  83.4 30.659 84.024 31.379 ;
     RECT  85.392 30.373 85.512 31.379 ;
     RECT  87.312 29.605 87.336 31.379 ;
     RECT  66.72 30.757 67.656 31.523 ;
     RECT  72.6 27.877 73.32 31.667 ;
     RECT  58.128 31.379 58.152 31.861 ;
     RECT  0.192 31.379 0.312 31.955 ;
     RECT  40.2 28.213 40.632 31.955 ;
     RECT  52.416 30.805 52.44 31.955 ;
     RECT  64.944 27.781 64.968 31.955 ;
     RECT  0.192 31.955 0.216 32.051 ;
     RECT  49.536 31.379 51.312 32.243 ;
     RECT  79.632 27.251 79.656 32.341 ;
     RECT  86.64 31.621 86.664 32.387 ;
     RECT  4.512 31.379 11.16 32.389 ;
     RECT  58.128 31.861 58.68 32.483 ;
     RECT  49.536 32.243 49.56 32.531 ;
     RECT  2.256 31.379 3.432 32.579 ;
     RECT  88.8 27.107 89.112 32.677 ;
     RECT  21.312 31.381 21.336 32.725 ;
     RECT  70.08 31.861 70.104 32.915 ;
     RECT  67.2 31.523 67.656 32.965 ;
     RECT  34.8 30.275 35.112 33.013 ;
     RECT  85.392 31.379 85.416 33.107 ;
     RECT  42.72 33.013 42.744 33.157 ;
     RECT  61.152 30.565 62.112 33.395 ;
     RECT  2.304 32.579 3.432 33.445 ;
     RECT  4.512 32.389 11.352 33.445 ;
     RECT  45.6 28.451 45.912 33.445 ;
     RECT  77.856 28.547 78.504 33.589 ;
     RECT  88.704 32.677 89.112 33.589 ;
     RECT  21.072 32.725 21.336 33.683 ;
     RECT  88.704 33.589 89.592 33.779 ;
     RECT  34.8 33.013 35.88 33.827 ;
     RECT  79.488 32.341 79.656 33.925 ;
     RECT  86.64 33.781 86.664 34.067 ;
     RECT  13.2 30.947 13.512 34.069 ;
     RECT  45.264 33.445 45.912 34.163 ;
     RECT  18.6 30.851 19.368 34.165 ;
     RECT  79.488 33.925 79.752 34.165 ;
     RECT  2.304 33.445 11.352 34.259 ;
     RECT  42.72 33.157 43.368 34.259 ;
     RECT  79.488 34.165 79.992 34.307 ;
     RECT  21.072 33.683 21.144 34.355 ;
     RECT  75.264 34.309 75.288 34.357 ;
     RECT  77.424 33.589 78.504 34.403 ;
     RECT  88.704 33.779 89.112 34.451 ;
     RECT  2.4 34.259 11.352 34.501 ;
     RECT  79.968 34.307 79.992 34.645 ;
     RECT  17.856 34.165 19.464 34.741 ;
     RECT  79.968 34.645 80.664 34.741 ;
     RECT  83.4 31.379 83.712 34.741 ;
     RECT  69.072 34.501 69.096 34.787 ;
     RECT  12.528 34.069 13.512 34.835 ;
     RECT  63.696 34.645 63.72 34.835 ;
     RECT  77.424 34.403 78.312 34.835 ;
     RECT  88.8 34.451 89.112 34.837 ;
     RECT  48.96 34.501 48.984 34.933 ;
     RECT  48.48 34.933 48.984 34.979 ;
     RECT  74.688 34.357 75.288 35.027 ;
     RECT  17.856 34.741 19.944 35.077 ;
     RECT  21.072 34.355 21.096 35.077 ;
     RECT  88.8 34.837 89.208 35.315 ;
     RECT  31.344 33.013 31.368 35.317 ;
     RECT  77.472 34.835 78.312 35.363 ;
     RECT  87.312 34.117 87.336 35.363 ;
     RECT  17.856 35.077 21.096 35.411 ;
     RECT  91.68 35.221 91.704 35.411 ;
     RECT  79.968 34.741 80.76 35.459 ;
     RECT  77.76 35.363 78.312 35.605 ;
     RECT  72.6 31.667 72.912 35.845 ;
     RECT  83.4 34.741 84.408 35.845 ;
     RECT  22.176 35.221 22.2 35.939 ;
     RECT  58.656 32.483 58.68 35.939 ;
     RECT  76.368 34.981 76.392 35.939 ;
     RECT  0.144 35.797 0.168 36.371 ;
     RECT  25.536 34.741 25.56 36.421 ;
     RECT  31.2 35.317 31.368 36.467 ;
     RECT  79.968 35.459 80.664 36.469 ;
     RECT  74.688 35.027 75.24 36.515 ;
     RECT  40.2 31.955 40.512 36.517 ;
     RECT  17.856 35.411 20.52 36.563 ;
     RECT  74.688 36.515 75 36.707 ;
     RECT  82.032 35.269 82.056 36.853 ;
     RECT  24 26.915 24.504 36.901 ;
     RECT  25.536 36.421 26.136 36.901 ;
     RECT  32.544 36.805 32.568 36.901 ;
     RECT  32.544 36.901 32.664 36.947 ;
     RECT  61.8 33.395 62.112 36.949 ;
     RECT  72.6 35.845 73.656 37.043 ;
     RECT  79.776 36.469 80.664 37.043 ;
     RECT  2.4 34.501 11.4 37.091 ;
     RECT  20.112 36.563 20.52 37.091 ;
     RECT  54.096 35.557 54.12 37.093 ;
     RECT  55.248 36.901 55.272 37.093 ;
     RECT  20.112 37.091 20.424 37.139 ;
     RECT  88.8 35.315 89.112 37.141 ;
     RECT  88.8 37.141 89.592 37.427 ;
     RECT  37.344 36.469 37.368 37.571 ;
     RECT  79.968 37.043 80.664 37.573 ;
     RECT  82.032 36.853 82.104 37.573 ;
     RECT  32.64 36.947 32.664 37.619 ;
     RECT  61.8 36.949 62.28 37.619 ;
     RECT  16.272 35.605 16.296 37.667 ;
     RECT  20.4 37.139 20.424 37.667 ;
     RECT  39.36 36.517 40.512 37.667 ;
     RECT  21.984 36.085 22.008 37.859 ;
     RECT  54.096 37.093 55.272 37.859 ;
     RECT  24 36.901 26.136 37.955 ;
     RECT  42.72 34.259 42.744 38.101 ;
     RECT  79.968 37.573 82.104 38.101 ;
     RECT  83.28 35.845 84.408 38.101 ;
     RECT  42.288 38.101 42.744 38.147 ;
     RECT  31.344 36.467 31.368 38.149 ;
     RECT  2.4 37.091 8.52 38.245 ;
     RECT  9.648 37.091 11.4 38.245 ;
     RECT  55.248 37.859 55.272 38.291 ;
     RECT  2.4 38.245 11.4 38.387 ;
     RECT  25.536 37.955 26.136 38.387 ;
     RECT  79.968 38.101 84.408 38.387 ;
     RECT  17.856 36.563 18.912 38.389 ;
     RECT  40.2 37.667 40.512 38.677 ;
     RECT  65.232 34.069 65.256 38.677 ;
     RECT  77.76 35.605 78.456 38.677 ;
     RECT  64.992 38.677 65.256 38.725 ;
     RECT  72.6 37.043 72.912 38.725 ;
     RECT  70.128 35.317 70.152 38.771 ;
     RECT  25.92 38.387 26.136 38.819 ;
     RECT  80.64 38.387 84.408 38.819 ;
     RECT  29.4 30.851 29.712 39.061 ;
     RECT  74.976 36.707 75 39.109 ;
     RECT  74.688 39.109 75 39.155 ;
     RECT  61.8 37.619 62.112 39.205 ;
     RECT  0.144 39.061 0.168 39.251 ;
     RECT  64.992 38.725 65.88 39.347 ;
     RECT  29.088 39.061 29.712 39.349 ;
     RECT  30.72 38.149 31.656 39.349 ;
     RECT  58.368 36.133 58.392 39.349 ;
     RECT  29.088 39.349 31.656 39.395 ;
     RECT  82.08 38.819 84.408 39.395 ;
     RECT  48.48 34.979 48.504 39.443 ;
     RECT  77.76 38.677 79.224 39.539 ;
     RECT  51 32.243 51.312 39.541 ;
     RECT  17.568 38.389 18.912 39.733 ;
     RECT  17.328 39.733 18.912 39.779 ;
     RECT  74.688 39.155 74.712 39.829 ;
     RECT  11.136 38.387 11.4 39.923 ;
     RECT  38.016 39.253 38.04 39.923 ;
     RECT  74.304 39.829 74.712 39.923 ;
     RECT  27.456 39.445 27.48 40.019 ;
     RECT  54.096 37.859 54.12 40.019 ;
     RECT  29.088 39.395 30.744 40.067 ;
     RECT  77.76 39.539 78.456 40.165 ;
     RECT  60.816 39.205 62.112 40.307 ;
     RECT  39.6 38.677 40.512 40.405 ;
     RECT  72.24 38.725 72.912 40.405 ;
     RECT  80.64 38.819 80.664 40.405 ;
     RECT  58.368 39.349 58.536 40.547 ;
     RECT  64.992 39.347 65.016 40.789 ;
     RECT  25.92 38.819 25.944 40.837 ;
     RECT  25.92 40.837 26.184 40.883 ;
     RECT  29.4 40.067 30.744 40.883 ;
     RECT  82.08 39.395 84.312 40.981 ;
     RECT  0.192 40.645 0.216 41.027 ;
     RECT  71.472 40.405 72.912 41.075 ;
     RECT  81.84 40.981 84.312 41.075 ;
     RECT  39.6 40.405 41.016 41.123 ;
     RECT  2.4 38.387 9.864 41.171 ;
     RECT  81.84 41.075 83.928 41.171 ;
     RECT  48.048 40.405 48.072 41.603 ;
     RECT  64.992 40.789 65.304 41.605 ;
     RECT  2.4 41.171 3.624 41.651 ;
     RECT  33.648 39.109 33.672 41.651 ;
     RECT  39.6 41.123 40.512 41.651 ;
     RECT  43.632 40.741 43.656 41.651 ;
     RECT  64.992 41.605 65.544 41.651 ;
     RECT  80.352 40.405 80.664 41.651 ;
     RECT  81.936 41.171 83.928 41.699 ;
     RECT  82.08 41.699 83.928 41.747 ;
     RECT  4.896 41.171 9.864 41.795 ;
     RECT  22.176 39.733 22.2 41.891 ;
     RECT  82.512 41.747 83.928 41.939 ;
     RECT  82.512 41.939 83.832 41.987 ;
     RECT  76.896 40.165 78.456 42.037 ;
     RECT  59.808 41.509 59.832 42.227 ;
     RECT  60.96 40.307 62.112 42.227 ;
     RECT  80.64 41.651 80.664 42.229 ;
     RECT  4.896 41.795 5.64 42.275 ;
     RECT  0.144 42.325 0.168 42.515 ;
     RECT  53.664 41.269 53.688 42.611 ;
     RECT  37.2 41.797 37.224 42.803 ;
     RECT  76.896 42.037 79.224 42.851 ;
     RECT  76.896 42.851 78.456 42.947 ;
     RECT  17.328 39.779 17.592 42.997 ;
     RECT  18.6 39.779 18.912 42.997 ;
     RECT  74.304 39.923 74.328 42.997 ;
     RECT  17.328 42.997 18.912 43.043 ;
     RECT  72.24 41.075 72.912 43.043 ;
     RECT  74.16 42.997 74.328 43.043 ;
     RECT  2.4 41.651 3.432 43.141 ;
     RECT  30.72 40.883 30.744 43.141 ;
     RECT  58.368 40.547 58.392 43.141 ;
     RECT  4.992 42.275 5.64 43.237 ;
     RECT  80.64 42.229 81 43.237 ;
     RECT  2.4 43.141 3.672 43.285 ;
     RECT  4.896 43.237 5.64 43.285 ;
     RECT  82.512 41.987 83.712 43.285 ;
     RECT  85.056 42.709 85.08 43.285 ;
     RECT  21.12 42.757 21.144 43.331 ;
     RECT  82.512 43.285 85.08 43.331 ;
     RECT  42.288 38.147 42.312 43.379 ;
     RECT  80.64 43.237 81.24 43.379 ;
     RECT  6.672 41.795 9.864 43.427 ;
     RECT  6.672 43.427 8.376 43.475 ;
     RECT  50.4 39.541 51.312 43.811 ;
     RECT  57.792 43.141 58.392 43.811 ;
     RECT  81.216 43.379 81.24 43.861 ;
     RECT  9.552 43.427 9.864 43.907 ;
     RECT  26.16 40.883 26.184 43.955 ;
     RECT  81.216 43.861 81.48 43.955 ;
     RECT  82.512 43.331 84.312 44.051 ;
     RECT  76.896 42.947 78.312 44.099 ;
     RECT  38.544 43.333 38.568 44.149 ;
     RECT  81.456 43.955 81.48 44.245 ;
     RECT  24 37.955 24.504 44.339 ;
     RECT  38.16 44.149 38.568 44.339 ;
     RECT  58.368 43.811 58.392 44.339 ;
     RECT  34.8 33.827 35.112 44.341 ;
     RECT  40.2 41.651 40.512 44.341 ;
     RECT  56.4 13.619 56.712 44.341 ;
     RECT  78 44.099 78.312 44.341 ;
     RECT  80.208 43.717 80.232 44.341 ;
     RECT  6.816 43.475 8.376 44.437 ;
     RECT  24 44.339 24.408 44.483 ;
     RECT  30.72 43.141 31.176 44.483 ;
     RECT  65.52 41.651 65.544 44.483 ;
     RECT  34.8 44.341 35.208 44.531 ;
     RECT  9.84 43.907 9.864 44.677 ;
     RECT  79.776 44.341 80.232 44.677 ;
     RECT  78 44.341 78.504 44.773 ;
     RECT  79.728 44.677 80.232 44.773 ;
     RECT  78 44.773 80.232 44.917 ;
     RECT  81.456 44.245 81.96 44.917 ;
     RECT  13.2 34.835 13.512 44.965 ;
     RECT  17.568 43.043 18.912 44.965 ;
     RECT  67.2 32.965 67.704 45.011 ;
     RECT  30.864 44.483 31.176 45.059 ;
     RECT  55.728 44.341 56.712 45.059 ;
     RECT  61.008 42.227 62.112 45.059 ;
     RECT  83.232 44.051 84.312 45.059 ;
     RECT  9.84 44.677 10.536 45.155 ;
     RECT  49.584 45.013 49.608 45.203 ;
     RECT  78 44.917 81.96 45.203 ;
     RECT  40.2 44.341 40.68 45.443 ;
     RECT  61.536 45.059 62.112 45.493 ;
     RECT  34.8 44.531 35.112 45.541 ;
     RECT  37.008 44.053 37.032 45.541 ;
     RECT  38.16 44.339 38.424 45.541 ;
     RECT  74.16 43.043 74.184 45.541 ;
     RECT  76.848 44.245 76.872 45.541 ;
     RECT  78 45.203 81.864 45.541 ;
     RECT  12.528 44.965 13.512 45.587 ;
     RECT  44.112 44.965 44.136 45.587 ;
     RECT  74.16 45.541 74.28 45.587 ;
     RECT  37.008 45.541 38.424 45.635 ;
     RECT  6.768 44.437 8.376 45.683 ;
     RECT  17.568 44.965 19.56 45.683 ;
     RECT  61.536 45.493 62.904 45.683 ;
     RECT  37.728 45.635 38.424 45.685 ;
     RECT  18.6 45.683 19.56 45.971 ;
     RECT  6.768 45.683 8.28 46.021 ;
     RECT  29.4 40.883 29.712 46.021 ;
     RECT  2.4 43.285 5.64 46.069 ;
     RECT  76.848 45.541 81.864 46.069 ;
     RECT  88.8 37.427 89.112 46.117 ;
     RECT  50.688 43.811 51.312 46.163 ;
     RECT  88.8 46.117 89.208 46.259 ;
     RECT  75.888 46.069 81.864 46.307 ;
     RECT  50.88 46.163 51.312 46.355 ;
     RECT  67.2 45.011 67.512 46.501 ;
     RECT  17.568 45.683 17.592 46.645 ;
     RECT  18.6 45.971 18.912 46.645 ;
     RECT  43.536 46.069 43.56 46.691 ;
     RECT  6.72 46.021 8.28 46.693 ;
     RECT  9.84 45.155 9.864 46.693 ;
     RECT  2.4 46.069 5.688 46.741 ;
     RECT  6.72 46.693 9.864 46.741 ;
     RECT  2.4 46.741 9.864 46.787 ;
     RECT  34.8 45.541 35.256 46.787 ;
     RECT  70.56 45.541 70.584 46.787 ;
     RECT  20.928 45.541 20.952 46.835 ;
     RECT  29.232 46.021 29.712 46.837 ;
     RECT  83.232 45.059 83.712 46.837 ;
     RECT  82.464 46.837 83.712 46.979 ;
     RECT  37.728 45.685 38.76 47.125 ;
     RECT  40.2 45.443 40.512 47.125 ;
     RECT  82.608 46.979 83.712 47.171 ;
     RECT  0.144 45.541 0.168 47.173 ;
     RECT  5.472 46.787 9.864 47.315 ;
     RECT  34.8 46.787 35.208 47.363 ;
     RECT  67.2 46.501 68.376 47.363 ;
     RECT  0.144 47.173 0.264 47.411 ;
     RECT  75.888 46.307 81.096 47.411 ;
     RECT  2.4 46.787 4.296 47.413 ;
     RECT  0.144 47.411 0.168 47.651 ;
     RECT  74.256 45.587 74.28 47.749 ;
     RECT  13.2 45.587 13.512 47.845 ;
     RECT  17.568 46.645 18.912 47.845 ;
     RECT  70.848 47.269 70.92 47.845 ;
     RECT  76.368 47.411 81.096 47.845 ;
     RECT  37.728 47.125 40.512 47.939 ;
     RECT  47.472 43.765 47.496 47.939 ;
     RECT  72.6 43.043 72.912 48.469 ;
     RECT  7.296 47.315 9.864 48.515 ;
     RECT  36.192 47.269 36.216 48.515 ;
     RECT  39.312 47.939 40.512 48.515 ;
     RECT  5.472 47.315 5.88 48.563 ;
     RECT  72.6 48.469 73.032 48.611 ;
     RECT  2.304 47.413 4.296 48.613 ;
     RECT  5.472 48.563 5.496 48.613 ;
     RECT  7.8 48.515 9.864 48.659 ;
     RECT  17.52 47.845 18.912 48.659 ;
     RECT  56.4 45.059 56.712 48.661 ;
     RECT  74.256 47.749 75 48.755 ;
     RECT  76.368 47.845 81.48 48.805 ;
     RECT  70.8 47.845 70.92 48.899 ;
     RECT  61.536 45.683 62.112 48.949 ;
     RECT  83.4 47.171 83.712 48.949 ;
     RECT  56.4 48.661 57 48.995 ;
     RECT  40.2 48.515 40.512 48.997 ;
     RECT  76.272 48.805 81.48 49.043 ;
     RECT  45.6 34.163 45.912 49.045 ;
     RECT  9.504 48.659 9.864 49.091 ;
     RECT  85.488 47.749 85.512 49.091 ;
     RECT  40.2 48.997 41.064 49.139 ;
     RECT  76.272 49.043 81.096 49.139 ;
     RECT  13.2 47.845 13.656 49.235 ;
     RECT  30.864 45.059 30.888 49.333 ;
     RECT  44.784 49.045 45.912 49.523 ;
     RECT  37.728 47.939 37.752 49.525 ;
     RECT  61.392 48.949 62.112 49.571 ;
     RECT  39.168 48.949 39.192 49.619 ;
     RECT  76.272 49.139 79.512 49.619 ;
     RECT  83.4 48.949 84.216 49.667 ;
     RECT  76.272 49.619 79.176 49.715 ;
     RECT  11.904 48.997 11.928 49.763 ;
     RECT  20.784 49.189 20.808 49.763 ;
     RECT  76.272 49.715 78.312 49.811 ;
     RECT  76.272 49.811 76.344 49.909 ;
     RECT  2.304 48.613 5.496 49.955 ;
     RECT  30.864 49.333 31.176 50.101 ;
     RECT  40.2 49.139 40.512 50.101 ;
     RECT  29.184 46.837 29.712 50.147 ;
     RECT  17.568 48.659 18.912 50.195 ;
     RECT  3.84 49.955 5.496 50.245 ;
     RECT  37.728 49.525 37.992 50.291 ;
     RECT  0.144 49.333 0.168 50.533 ;
     RECT  21.264 50.053 21.288 50.579 ;
     RECT  0.144 50.533 0.216 50.723 ;
     RECT  3.84 50.245 6.216 50.723 ;
     RECT  77.472 49.811 78.312 50.771 ;
     RECT  64.224 45.925 64.248 50.773 ;
     RECT  3.84 50.723 5.544 50.819 ;
     RECT  34.8 47.363 35.112 50.821 ;
     RECT  17.568 50.195 17.592 50.867 ;
     RECT  9.504 49.091 9.528 50.965 ;
     RECT  2.304 49.955 2.856 51.011 ;
     RECT  9.504 50.965 9.672 51.011 ;
     RECT  75.792 49.909 76.344 51.061 ;
     RECT  48.096 48.229 48.12 51.253 ;
     RECT  80.544 49.139 81.096 51.253 ;
     RECT  47.904 51.253 48.12 51.299 ;
     RECT  3.936 50.819 5.544 51.347 ;
     RECT  34.176 50.821 35.112 51.347 ;
     RECT  39.312 50.101 40.512 51.347 ;
     RECT  70.896 48.899 70.92 51.347 ;
     RECT  75.6 51.061 76.344 51.349 ;
     RECT  83.4 49.667 83.712 51.493 ;
     RECT  3.936 51.347 5.4 51.539 ;
     RECT  30.864 50.101 31.224 51.683 ;
     RECT  0.144 50.723 0.168 51.685 ;
     RECT  39.888 51.347 40.512 51.781 ;
     RECT  37.728 50.291 37.752 51.827 ;
     RECT  0.144 51.685 0.216 51.875 ;
     RECT  74.256 48.755 74.28 51.877 ;
     RECT  30.864 51.683 31.08 51.923 ;
     RECT  63.792 50.773 64.248 51.971 ;
     RECT  83.4 51.493 84.648 51.973 ;
     RECT  82.656 51.973 84.648 52.259 ;
     RECT  53.568 50.005 53.592 52.357 ;
     RECT  53.232 52.357 53.592 52.403 ;
     RECT  2.4 51.011 2.856 52.405 ;
     RECT  3.936 51.539 5.256 52.405 ;
     RECT  72.6 48.611 72.912 52.405 ;
     RECT  74.256 51.877 74.376 52.405 ;
     RECT  61.536 49.571 62.112 52.451 ;
     RECT  39.888 51.781 41.064 52.499 ;
     RECT  83.4 52.259 84.648 52.499 ;
     RECT  0.144 51.875 0.168 52.547 ;
     RECT  75.6 51.349 76.92 52.547 ;
     RECT  2.4 52.405 5.256 52.549 ;
     RECT  13.2 49.235 13.512 52.837 ;
     RECT  72.6 52.405 74.376 52.883 ;
     RECT  9.648 51.011 9.672 52.933 ;
     RECT  9.168 52.933 9.672 52.979 ;
     RECT  16.512 51.253 16.536 52.981 ;
     RECT  56.4 48.995 56.712 52.981 ;
     RECT  16.224 52.981 16.536 53.027 ;
     RECT  13.2 52.837 13.608 53.075 ;
     RECT  76.32 52.547 76.92 53.075 ;
     RECT  76.896 53.075 76.92 53.123 ;
     RECT  64.224 51.971 64.248 53.507 ;
     RECT  42.96 47.269 42.984 53.557 ;
     RECT  53.232 52.403 53.256 53.557 ;
     RECT  2.4 52.549 5.688 53.603 ;
     RECT  42.96 53.557 43.944 53.603 ;
     RECT  53.04 53.557 53.256 53.603 ;
     RECT  80.496 51.253 81.096 53.603 ;
     RECT  2.4 53.603 3.96 53.651 ;
     RECT  56.4 52.981 57.288 53.795 ;
     RECT  61.8 52.451 62.112 53.797 ;
     RECT  0.144 53.653 0.168 53.843 ;
     RECT  80.496 53.603 80.52 53.843 ;
     RECT  83.4 52.499 83.712 53.941 ;
     RECT  59.856 50.101 59.88 53.989 ;
     RECT  59.856 53.989 60.216 54.035 ;
     RECT  88.8 46.259 89.112 54.037 ;
     RECT  39.888 52.499 40.512 54.085 ;
     RECT  83.4 53.941 84.456 54.085 ;
     RECT  88.704 54.037 89.112 54.085 ;
     RECT  5.184 53.603 5.688 54.179 ;
     RECT  88.608 54.085 89.112 54.323 ;
     RECT  68.928 53.557 68.952 54.371 ;
     RECT  82.656 54.085 84.456 54.515 ;
     RECT  61.8 53.797 63 54.563 ;
     RECT  61.8 54.563 62.112 54.613 ;
     RECT  72.6 52.883 72.912 54.661 ;
     RECT  74.256 52.883 74.376 54.661 ;
     RECT  16.224 53.027 16.248 54.755 ;
     RECT  33.744 54.085 33.768 54.755 ;
     RECT  88.704 54.323 89.112 54.803 ;
     RECT  72.6 54.661 74.376 55.139 ;
     RECT  56.4 53.795 56.712 55.861 ;
     RECT  21.744 51.829 21.768 55.907 ;
     RECT  47.904 51.299 47.928 55.907 ;
     RECT  33.648 55.237 33.672 55.955 ;
     RECT  61.68 54.613 62.112 55.955 ;
     RECT  74.256 55.139 74.376 56.101 ;
     RECT  73.968 56.101 74.376 56.147 ;
     RECT  2.4 53.651 3.72 56.243 ;
     RECT  10.8 55.813 10.824 56.293 ;
     RECT  53.04 53.603 53.064 56.389 ;
     RECT  13.2 53.075 13.512 56.437 ;
     RECT  88.8 54.803 89.112 56.437 ;
     RECT  25.536 50.101 25.56 56.483 ;
     RECT  31.056 51.923 31.08 56.483 ;
     RECT  81.792 55.237 81.816 56.627 ;
     RECT  52.464 56.389 53.064 56.677 ;
     RECT  56.4 55.861 57.096 56.771 ;
     RECT  60.192 54.035 60.216 56.771 ;
     RECT  88.8 56.437 89.256 56.771 ;
     RECT  7.8 48.659 8.112 56.869 ;
     RECT  9.168 52.979 9.192 56.869 ;
     RECT  37.584 56.485 37.608 56.869 ;
     RECT  85.536 54.469 85.56 56.963 ;
     RECT  12.96 56.437 13.512 57.011 ;
     RECT  37.584 56.869 38.088 57.011 ;
     RECT  5.184 54.179 5.208 57.059 ;
     RECT  7.8 56.869 9.192 57.059 ;
     RECT  10.32 56.293 10.824 57.059 ;
     RECT  43.92 53.603 43.944 57.059 ;
     RECT  52.464 56.677 53.304 57.059 ;
     RECT  3.696 56.243 3.72 57.107 ;
     RECT  9.168 57.059 9.192 57.251 ;
     RECT  10.32 57.059 10.344 57.299 ;
     RECT  68.736 56.389 68.76 57.587 ;
     RECT  73.968 56.147 74.28 57.587 ;
     RECT  38.064 57.011 38.088 57.635 ;
     RECT  20.496 56.965 20.52 57.875 ;
     RECT  39.6 54.085 40.512 57.875 ;
     RECT  53.28 57.059 53.304 58.115 ;
     RECT  83.4 54.515 84.456 58.357 ;
     RECT  59.904 58.597 59.928 58.693 ;
     RECT  85.776 58.645 85.8 58.693 ;
     RECT  59.904 58.693 59.976 59.219 ;
     RECT  72.6 55.139 72.912 59.221 ;
     RECT  73.968 57.587 73.992 59.221 ;
     RECT  82.656 58.357 84.456 59.267 ;
     RECT  67.2 47.363 67.512 59.269 ;
     RECT  65.28 53.509 65.304 59.315 ;
     RECT  72.6 59.221 73.992 59.315 ;
     RECT  82.656 59.267 83.712 59.315 ;
     RECT  72.6 59.315 73.512 59.605 ;
     RECT  80.064 58.933 80.088 59.747 ;
     RECT  54.672 58.645 54.696 59.891 ;
     RECT  59.904 59.219 59.928 59.891 ;
     RECT  85.776 58.693 86.424 60.035 ;
     RECT  72.096 59.605 73.512 60.323 ;
     RECT  66.72 59.269 67.512 60.419 ;
     RECT  75.984 59.461 76.008 60.563 ;
     RECT  86.4 60.035 86.424 61.619 ;
     RECT  2.4 56.243 2.712 62.649 ;
     RECT  7.8 57.059 8.112 62.649 ;
     RECT  13.2 57.011 13.512 62.649 ;
     RECT  18.6 50.195 18.912 62.649 ;
     RECT  24 44.483 24.312 62.649 ;
     RECT  29.4 50.147 29.712 62.649 ;
     RECT  34.8 51.347 35.112 62.649 ;
     RECT  40.2 57.875 40.512 62.649 ;
     RECT  45.6 49.523 45.912 62.649 ;
     RECT  51 46.355 51.312 62.649 ;
     RECT  56.4 56.771 56.712 62.649 ;
     RECT  61.8 55.955 62.112 62.649 ;
     RECT  67.2 60.419 67.512 62.649 ;
     RECT  72.6 60.323 72.912 62.649 ;
     RECT  78 50.771 78.312 62.649 ;
     RECT  83.4 59.315 83.712 62.649 ;
     RECT  88.8 56.771 89.112 62.649 ;
     RECT  2.4 62.649 2.52 62.663 ;
     RECT  7.8 62.649 7.92 62.663 ;
     RECT  13.2 62.649 13.32 62.663 ;
     RECT  18.6 62.649 18.72 62.663 ;
     RECT  24 62.649 24.12 62.663 ;
     RECT  29.4 62.649 29.52 62.663 ;
     RECT  34.8 62.649 34.92 62.663 ;
     RECT  40.2 62.649 40.32 62.663 ;
     RECT  45.6 62.649 45.72 62.663 ;
     RECT  51 62.649 51.12 62.663 ;
     RECT  56.4 62.649 56.52 62.663 ;
     RECT  61.8 62.649 61.92 62.663 ;
     RECT  67.2 62.649 67.32 62.663 ;
     RECT  72.6 62.649 72.72 62.663 ;
     RECT  78 62.649 78.12 62.663 ;
     RECT  83.4 62.649 83.52 62.663 ;
     RECT  88.8 62.649 88.92 62.663 ;
  END
END ot_qwen_tree_delay16_t
END LIBRARY
